VERSION 5.8 ;
BUSBITCHARS "[]" ;
DIVIDERCHAR "/" ;
UNITS
    DATABASE MICRONS 1000 ;
END UNITS

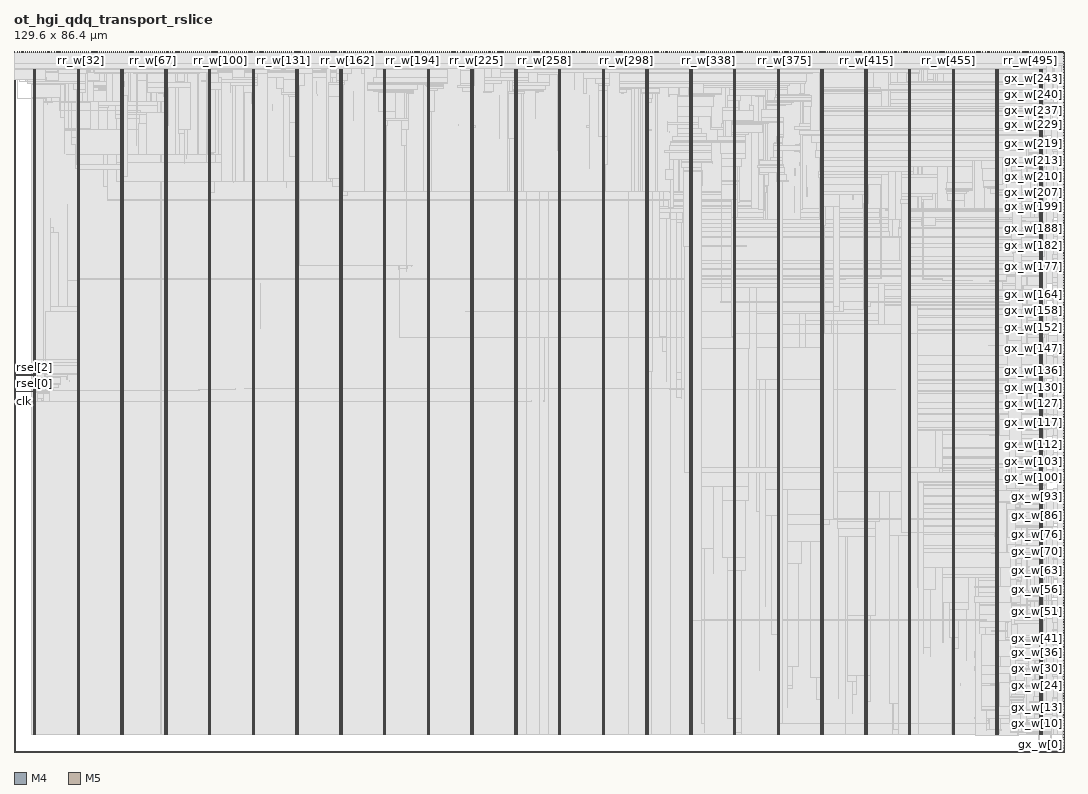
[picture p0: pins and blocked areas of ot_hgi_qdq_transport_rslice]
MACRO ot_hgi_qdq_transport_rslice
  FOREIGN ot_hgi_qdq_transport_rslice 0 0 ;
  CLASS BLOCK ;
  SIZE 129.6 BY 86.4 ;
  PIN clk
    DIRECTION INPUT ;
    USE SIGNAL ;
    PORT
      LAYER M4 ;
        RECT  0 43.2 0.084 43.224 ;
    END
    PORT
      LAYER M4 ;
        RECT  0.06 43.2 0.097 43.224 ;
    END
  END clk
  PIN gx_w[0]
    DIRECTION OUTPUT ;
    USE SIGNAL ;
    PORT
      LAYER M4 ;
        RECT  129.516 0.144 129.6 0.168 ;
    END
  END gx_w[0]
  PIN gx_w[100]
    DIRECTION OUTPUT ;
    USE SIGNAL ;
    PORT
      LAYER M4 ;
        RECT  129.516 33.888 129.6 33.912 ;
    END
  END gx_w[100]
  PIN gx_w[101]
    DIRECTION OUTPUT ;
    USE SIGNAL ;
    PORT
      LAYER M4 ;
        RECT  129.516 34.224 129.6 34.248 ;
    END
  END gx_w[101]
  PIN gx_w[102]
    DIRECTION OUTPUT ;
    USE SIGNAL ;
    PORT
      LAYER M4 ;
        RECT  129.516 34.56 129.6 34.584 ;
    END
  END gx_w[102]
  PIN gx_w[103]
    DIRECTION OUTPUT ;
    USE SIGNAL ;
    PORT
      LAYER M4 ;
        RECT  129.516 34.896 129.6 34.92 ;
    END
  END gx_w[103]
  PIN gx_w[104]
    DIRECTION OUTPUT ;
    USE SIGNAL ;
    PORT
      LAYER M4 ;
        RECT  129.516 35.28 129.6 35.304 ;
    END
  END gx_w[104]
  PIN gx_w[105]
    DIRECTION OUTPUT ;
    USE SIGNAL ;
    PORT
      LAYER M4 ;
        RECT  129.516 35.616 129.6 35.64 ;
    END
  END gx_w[105]
  PIN gx_w[106]
    DIRECTION OUTPUT ;
    USE SIGNAL ;
    PORT
      LAYER M4 ;
        RECT  129.516 35.952 129.6 35.976 ;
    END
  END gx_w[106]
  PIN gx_w[107]
    DIRECTION OUTPUT ;
    USE SIGNAL ;
    PORT
      LAYER M4 ;
        RECT  129.516 36.288 129.6 36.312 ;
    END
  END gx_w[107]
  PIN gx_w[108]
    DIRECTION OUTPUT ;
    USE SIGNAL ;
    PORT
      LAYER M4 ;
        RECT  129.516 36.624 129.6 36.648 ;
    END
  END gx_w[108]
  PIN gx_w[109]
    DIRECTION OUTPUT ;
    USE SIGNAL ;
    PORT
      LAYER M4 ;
        RECT  129.516 36.96 129.6 36.984 ;
    END
  END gx_w[109]
  PIN gx_w[10]
    DIRECTION OUTPUT ;
    USE SIGNAL ;
    PORT
      LAYER M4 ;
        RECT  129.516 3.552 129.6 3.576 ;
    END
  END gx_w[10]
  PIN gx_w[110]
    DIRECTION OUTPUT ;
    USE SIGNAL ;
    PORT
      LAYER M4 ;
        RECT  129.516 37.296 129.6 37.32 ;
    END
  END gx_w[110]
  PIN gx_w[111]
    DIRECTION OUTPUT ;
    USE SIGNAL ;
    PORT
      LAYER M4 ;
        RECT  129.516 37.632 129.6 37.656 ;
    END
  END gx_w[111]
  PIN gx_w[112]
    DIRECTION OUTPUT ;
    USE SIGNAL ;
    PORT
      LAYER M4 ;
        RECT  129.516 37.968 129.6 37.992 ;
    END
  END gx_w[112]
  PIN gx_w[113]
    DIRECTION OUTPUT ;
    USE SIGNAL ;
    PORT
      LAYER M4 ;
        RECT  129.516 38.304 129.6 38.328 ;
    END
  END gx_w[113]
  PIN gx_w[114]
    DIRECTION OUTPUT ;
    USE SIGNAL ;
    PORT
      LAYER M4 ;
        RECT  129.516 38.64 129.6 38.664 ;
    END
  END gx_w[114]
  PIN gx_w[115]
    DIRECTION OUTPUT ;
    USE SIGNAL ;
    PORT
      LAYER M4 ;
        RECT  129.516 38.976 129.6 39 ;
    END
  END gx_w[115]
  PIN gx_w[116]
    DIRECTION OUTPUT ;
    USE SIGNAL ;
    PORT
      LAYER M4 ;
        RECT  129.516 39.312 129.6 39.336 ;
    END
  END gx_w[116]
  PIN gx_w[117]
    DIRECTION OUTPUT ;
    USE SIGNAL ;
    PORT
      LAYER M4 ;
        RECT  129.516 39.648 129.6 39.672 ;
    END
  END gx_w[117]
  PIN gx_w[118]
    DIRECTION OUTPUT ;
    USE SIGNAL ;
    PORT
      LAYER M4 ;
        RECT  129.516 39.984 129.6 40.008 ;
    END
  END gx_w[118]
  PIN gx_w[119]
    DIRECTION OUTPUT ;
    USE SIGNAL ;
    PORT
      LAYER M4 ;
        RECT  129.516 40.32 129.6 40.344 ;
    END
  END gx_w[119]
  PIN gx_w[11]
    DIRECTION OUTPUT ;
    USE SIGNAL ;
    PORT
      LAYER M4 ;
        RECT  129.516 3.888 129.6 3.912 ;
    END
  END gx_w[11]
  PIN gx_w[120]
    DIRECTION OUTPUT ;
    USE SIGNAL ;
    PORT
      LAYER M4 ;
        RECT  129.516 40.656 129.6 40.68 ;
    END
  END gx_w[120]
  PIN gx_w[121]
    DIRECTION OUTPUT ;
    USE SIGNAL ;
    PORT
      LAYER M4 ;
        RECT  129.516 40.992 129.6 41.016 ;
    END
  END gx_w[121]
  PIN gx_w[122]
    DIRECTION OUTPUT ;
    USE SIGNAL ;
    PORT
      LAYER M4 ;
        RECT  129.516 41.328 129.6 41.352 ;
    END
  END gx_w[122]
  PIN gx_w[123]
    DIRECTION OUTPUT ;
    USE SIGNAL ;
    PORT
      LAYER M4 ;
        RECT  129.516 41.664 129.6 41.688 ;
    END
  END gx_w[123]
  PIN gx_w[124]
    DIRECTION OUTPUT ;
    USE SIGNAL ;
    PORT
      LAYER M4 ;
        RECT  129.516 42 129.6 42.024 ;
    END
  END gx_w[124]
  PIN gx_w[125]
    DIRECTION OUTPUT ;
    USE SIGNAL ;
    PORT
      LAYER M4 ;
        RECT  129.516 42.336 129.6 42.36 ;
    END
  END gx_w[125]
  PIN gx_w[126]
    DIRECTION OUTPUT ;
    USE SIGNAL ;
    PORT
      LAYER M4 ;
        RECT  129.516 42.672 129.6 42.696 ;
    END
  END gx_w[126]
  PIN gx_w[127]
    DIRECTION OUTPUT ;
    USE SIGNAL ;
    PORT
      LAYER M4 ;
        RECT  129.516 43.008 129.6 43.032 ;
    END
  END gx_w[127]
  PIN gx_w[128]
    DIRECTION OUTPUT ;
    USE SIGNAL ;
    PORT
      LAYER M4 ;
        RECT  129.516 43.344 129.6 43.368 ;
    END
  END gx_w[128]
  PIN gx_w[129]
    DIRECTION OUTPUT ;
    USE SIGNAL ;
    PORT
      LAYER M4 ;
        RECT  129.516 43.68 129.6 43.704 ;
    END
  END gx_w[129]
  PIN gx_w[12]
    DIRECTION OUTPUT ;
    USE SIGNAL ;
    PORT
      LAYER M4 ;
        RECT  129.516 4.224 129.6 4.248 ;
    END
  END gx_w[12]
  PIN gx_w[130]
    DIRECTION OUTPUT ;
    USE SIGNAL ;
    PORT
      LAYER M4 ;
        RECT  129.516 44.016 129.6 44.04 ;
    END
  END gx_w[130]
  PIN gx_w[131]
    DIRECTION OUTPUT ;
    USE SIGNAL ;
    PORT
      LAYER M4 ;
        RECT  129.516 44.352 129.6 44.376 ;
    END
  END gx_w[131]
  PIN gx_w[132]
    DIRECTION OUTPUT ;
    USE SIGNAL ;
    PORT
      LAYER M4 ;
        RECT  129.516 44.688 129.6 44.712 ;
    END
  END gx_w[132]
  PIN gx_w[133]
    DIRECTION OUTPUT ;
    USE SIGNAL ;
    PORT
      LAYER M4 ;
        RECT  129.516 45.024 129.6 45.048 ;
    END
  END gx_w[133]
  PIN gx_w[134]
    DIRECTION OUTPUT ;
    USE SIGNAL ;
    PORT
      LAYER M4 ;
        RECT  129.516 45.36 129.6 45.384 ;
    END
  END gx_w[134]
  PIN gx_w[135]
    DIRECTION OUTPUT ;
    USE SIGNAL ;
    PORT
      LAYER M4 ;
        RECT  129.516 45.696 129.6 45.72 ;
    END
  END gx_w[135]
  PIN gx_w[136]
    DIRECTION OUTPUT ;
    USE SIGNAL ;
    PORT
      LAYER M4 ;
        RECT  129.516 46.08 129.6 46.104 ;
    END
  END gx_w[136]
  PIN gx_w[137]
    DIRECTION OUTPUT ;
    USE SIGNAL ;
    PORT
      LAYER M4 ;
        RECT  129.516 46.416 129.6 46.44 ;
    END
  END gx_w[137]
  PIN gx_w[138]
    DIRECTION OUTPUT ;
    USE SIGNAL ;
    PORT
      LAYER M4 ;
        RECT  129.516 46.752 129.6 46.776 ;
    END
  END gx_w[138]
  PIN gx_w[139]
    DIRECTION OUTPUT ;
    USE SIGNAL ;
    PORT
      LAYER M4 ;
        RECT  129.516 47.088 129.6 47.112 ;
    END
  END gx_w[139]
  PIN gx_w[13]
    DIRECTION OUTPUT ;
    USE SIGNAL ;
    PORT
      LAYER M4 ;
        RECT  129.516 4.56 129.6 4.584 ;
    END
  END gx_w[13]
  PIN gx_w[140]
    DIRECTION OUTPUT ;
    USE SIGNAL ;
    PORT
      LAYER M4 ;
        RECT  129.516 47.424 129.6 47.448 ;
    END
  END gx_w[140]
  PIN gx_w[141]
    DIRECTION OUTPUT ;
    USE SIGNAL ;
    PORT
      LAYER M4 ;
        RECT  129.516 47.76 129.6 47.784 ;
    END
  END gx_w[141]
  PIN gx_w[142]
    DIRECTION OUTPUT ;
    USE SIGNAL ;
    PORT
      LAYER M4 ;
        RECT  129.516 48.096 129.6 48.12 ;
    END
  END gx_w[142]
  PIN gx_w[143]
    DIRECTION OUTPUT ;
    USE SIGNAL ;
    PORT
      LAYER M4 ;
        RECT  129.516 48.432 129.6 48.456 ;
    END
  END gx_w[143]
  PIN gx_w[144]
    DIRECTION OUTPUT ;
    USE SIGNAL ;
    PORT
      LAYER M4 ;
        RECT  129.516 48.768 129.6 48.792 ;
    END
  END gx_w[144]
  PIN gx_w[145]
    DIRECTION OUTPUT ;
    USE SIGNAL ;
    PORT
      LAYER M4 ;
        RECT  129.516 49.104 129.6 49.128 ;
    END
  END gx_w[145]
  PIN gx_w[146]
    DIRECTION OUTPUT ;
    USE SIGNAL ;
    PORT
      LAYER M4 ;
        RECT  129.516 49.44 129.6 49.464 ;
    END
  END gx_w[146]
  PIN gx_w[147]
    DIRECTION OUTPUT ;
    USE SIGNAL ;
    PORT
      LAYER M4 ;
        RECT  129.516 49.776 129.6 49.8 ;
    END
  END gx_w[147]
  PIN gx_w[148]
    DIRECTION OUTPUT ;
    USE SIGNAL ;
    PORT
      LAYER M4 ;
        RECT  129.516 50.112 129.6 50.136 ;
    END
  END gx_w[148]
  PIN gx_w[149]
    DIRECTION OUTPUT ;
    USE SIGNAL ;
    PORT
      LAYER M4 ;
        RECT  129.516 50.448 129.6 50.472 ;
    END
  END gx_w[149]
  PIN gx_w[14]
    DIRECTION OUTPUT ;
    USE SIGNAL ;
    PORT
      LAYER M4 ;
        RECT  129.516 4.896 129.6 4.92 ;
    END
  END gx_w[14]
  PIN gx_w[150]
    DIRECTION OUTPUT ;
    USE SIGNAL ;
    PORT
      LAYER M4 ;
        RECT  129.516 50.784 129.6 50.808 ;
    END
  END gx_w[150]
  PIN gx_w[151]
    DIRECTION OUTPUT ;
    USE SIGNAL ;
    PORT
      LAYER M4 ;
        RECT  129.516 51.12 129.6 51.144 ;
    END
  END gx_w[151]
  PIN gx_w[152]
    DIRECTION OUTPUT ;
    USE SIGNAL ;
    PORT
      LAYER M4 ;
        RECT  129.516 51.456 129.6 51.48 ;
    END
  END gx_w[152]
  PIN gx_w[153]
    DIRECTION OUTPUT ;
    USE SIGNAL ;
    PORT
      LAYER M4 ;
        RECT  129.516 51.792 129.6 51.816 ;
    END
  END gx_w[153]
  PIN gx_w[154]
    DIRECTION OUTPUT ;
    USE SIGNAL ;
    PORT
      LAYER M4 ;
        RECT  129.516 52.128 129.6 52.152 ;
    END
  END gx_w[154]
  PIN gx_w[155]
    DIRECTION OUTPUT ;
    USE SIGNAL ;
    PORT
      LAYER M4 ;
        RECT  129.516 52.464 129.6 52.488 ;
    END
  END gx_w[155]
  PIN gx_w[156]
    DIRECTION OUTPUT ;
    USE SIGNAL ;
    PORT
      LAYER M4 ;
        RECT  129.516 52.8 129.6 52.824 ;
    END
  END gx_w[156]
  PIN gx_w[157]
    DIRECTION OUTPUT ;
    USE SIGNAL ;
    PORT
      LAYER M4 ;
        RECT  129.516 53.136 129.6 53.16 ;
    END
  END gx_w[157]
  PIN gx_w[158]
    DIRECTION OUTPUT ;
    USE SIGNAL ;
    PORT
      LAYER M4 ;
        RECT  129.516 53.472 129.6 53.496 ;
    END
  END gx_w[158]
  PIN gx_w[159]
    DIRECTION OUTPUT ;
    USE SIGNAL ;
    PORT
      LAYER M4 ;
        RECT  129.516 53.808 129.6 53.832 ;
    END
  END gx_w[159]
  PIN gx_w[15]
    DIRECTION OUTPUT ;
    USE SIGNAL ;
    PORT
      LAYER M4 ;
        RECT  129.516 5.232 129.6 5.256 ;
    END
  END gx_w[15]
  PIN gx_w[160]
    DIRECTION OUTPUT ;
    USE SIGNAL ;
    PORT
      LAYER M4 ;
        RECT  129.516 54.144 129.6 54.168 ;
    END
  END gx_w[160]
  PIN gx_w[161]
    DIRECTION OUTPUT ;
    USE SIGNAL ;
    PORT
      LAYER M4 ;
        RECT  129.516 54.48 129.6 54.504 ;
    END
  END gx_w[161]
  PIN gx_w[162]
    DIRECTION OUTPUT ;
    USE SIGNAL ;
    PORT
      LAYER M4 ;
        RECT  129.516 54.816 129.6 54.84 ;
    END
  END gx_w[162]
  PIN gx_w[163]
    DIRECTION OUTPUT ;
    USE SIGNAL ;
    PORT
      LAYER M4 ;
        RECT  129.516 55.152 129.6 55.176 ;
    END
  END gx_w[163]
  PIN gx_w[164]
    DIRECTION OUTPUT ;
    USE SIGNAL ;
    PORT
      LAYER M4 ;
        RECT  129.516 55.488 129.6 55.512 ;
    END
  END gx_w[164]
  PIN gx_w[165]
    DIRECTION OUTPUT ;
    USE SIGNAL ;
    PORT
      LAYER M4 ;
        RECT  129.516 55.824 129.6 55.848 ;
    END
  END gx_w[165]
  PIN gx_w[166]
    DIRECTION OUTPUT ;
    USE SIGNAL ;
    PORT
      LAYER M4 ;
        RECT  129.516 56.16 129.6 56.184 ;
    END
  END gx_w[166]
  PIN gx_w[167]
    DIRECTION OUTPUT ;
    USE SIGNAL ;
    PORT
      LAYER M4 ;
        RECT  129.516 56.496 129.6 56.52 ;
    END
  END gx_w[167]
  PIN gx_w[168]
    DIRECTION OUTPUT ;
    USE SIGNAL ;
    PORT
      LAYER M4 ;
        RECT  129.516 56.88 129.6 56.904 ;
    END
  END gx_w[168]
  PIN gx_w[169]
    DIRECTION OUTPUT ;
    USE SIGNAL ;
    PORT
      LAYER M4 ;
        RECT  129.516 57.216 129.6 57.24 ;
    END
  END gx_w[169]
  PIN gx_w[16]
    DIRECTION OUTPUT ;
    USE SIGNAL ;
    PORT
      LAYER M4 ;
        RECT  129.516 5.568 129.6 5.592 ;
    END
  END gx_w[16]
  PIN gx_w[170]
    DIRECTION OUTPUT ;
    USE SIGNAL ;
    PORT
      LAYER M4 ;
        RECT  129.516 57.552 129.6 57.576 ;
    END
  END gx_w[170]
  PIN gx_w[171]
    DIRECTION OUTPUT ;
    USE SIGNAL ;
    PORT
      LAYER M4 ;
        RECT  129.516 57.888 129.6 57.912 ;
    END
  END gx_w[171]
  PIN gx_w[172]
    DIRECTION OUTPUT ;
    USE SIGNAL ;
    PORT
      LAYER M4 ;
        RECT  129.516 58.224 129.6 58.248 ;
    END
  END gx_w[172]
  PIN gx_w[173]
    DIRECTION OUTPUT ;
    USE SIGNAL ;
    PORT
      LAYER M4 ;
        RECT  129.516 58.56 129.6 58.584 ;
    END
  END gx_w[173]
  PIN gx_w[174]
    DIRECTION OUTPUT ;
    USE SIGNAL ;
    PORT
      LAYER M4 ;
        RECT  129.516 58.896 129.6 58.92 ;
    END
  END gx_w[174]
  PIN gx_w[175]
    DIRECTION OUTPUT ;
    USE SIGNAL ;
    PORT
      LAYER M4 ;
        RECT  129.516 59.232 129.6 59.256 ;
    END
  END gx_w[175]
  PIN gx_w[176]
    DIRECTION OUTPUT ;
    USE SIGNAL ;
    PORT
      LAYER M4 ;
        RECT  129.516 59.568 129.6 59.592 ;
    END
  END gx_w[176]
  PIN gx_w[177]
    DIRECTION OUTPUT ;
    USE SIGNAL ;
    PORT
      LAYER M4 ;
        RECT  129.516 59.904 129.6 59.928 ;
    END
  END gx_w[177]
  PIN gx_w[178]
    DIRECTION OUTPUT ;
    USE SIGNAL ;
    PORT
      LAYER M4 ;
        RECT  129.516 60.24 129.6 60.264 ;
    END
  END gx_w[178]
  PIN gx_w[179]
    DIRECTION OUTPUT ;
    USE SIGNAL ;
    PORT
      LAYER M4 ;
        RECT  129.516 60.576 129.6 60.6 ;
    END
  END gx_w[179]
  PIN gx_w[17]
    DIRECTION OUTPUT ;
    USE SIGNAL ;
    PORT
      LAYER M4 ;
        RECT  129.516 5.904 129.6 5.928 ;
    END
  END gx_w[17]
  PIN gx_w[180]
    DIRECTION OUTPUT ;
    USE SIGNAL ;
    PORT
      LAYER M4 ;
        RECT  129.516 60.912 129.6 60.936 ;
    END
  END gx_w[180]
  PIN gx_w[181]
    DIRECTION OUTPUT ;
    USE SIGNAL ;
    PORT
      LAYER M4 ;
        RECT  129.516 61.248 129.6 61.272 ;
    END
  END gx_w[181]
  PIN gx_w[182]
    DIRECTION OUTPUT ;
    USE SIGNAL ;
    PORT
      LAYER M4 ;
        RECT  129.516 61.584 129.6 61.608 ;
    END
  END gx_w[182]
  PIN gx_w[183]
    DIRECTION OUTPUT ;
    USE SIGNAL ;
    PORT
      LAYER M4 ;
        RECT  129.516 61.92 129.6 61.944 ;
    END
  END gx_w[183]
  PIN gx_w[184]
    DIRECTION OUTPUT ;
    USE SIGNAL ;
    PORT
      LAYER M4 ;
        RECT  129.516 62.256 129.6 62.28 ;
    END
  END gx_w[184]
  PIN gx_w[185]
    DIRECTION OUTPUT ;
    USE SIGNAL ;
    PORT
      LAYER M4 ;
        RECT  129.516 62.592 129.6 62.616 ;
    END
  END gx_w[185]
  PIN gx_w[186]
    DIRECTION OUTPUT ;
    USE SIGNAL ;
    PORT
      LAYER M4 ;
        RECT  129.516 62.928 129.6 62.952 ;
    END
  END gx_w[186]
  PIN gx_w[187]
    DIRECTION OUTPUT ;
    USE SIGNAL ;
    PORT
      LAYER M4 ;
        RECT  129.516 63.264 129.6 63.288 ;
    END
  END gx_w[187]
  PIN gx_w[188]
    DIRECTION OUTPUT ;
    USE SIGNAL ;
    PORT
      LAYER M4 ;
        RECT  129.516 63.6 129.6 63.624 ;
    END
  END gx_w[188]
  PIN gx_w[189]
    DIRECTION OUTPUT ;
    USE SIGNAL ;
    PORT
      LAYER M4 ;
        RECT  129.516 63.936 129.6 63.96 ;
    END
  END gx_w[189]
  PIN gx_w[18]
    DIRECTION OUTPUT ;
    USE SIGNAL ;
    PORT
      LAYER M4 ;
        RECT  129.516 6.24 129.6 6.264 ;
    END
  END gx_w[18]
  PIN gx_w[190]
    DIRECTION OUTPUT ;
    USE SIGNAL ;
    PORT
      LAYER M4 ;
        RECT  129.516 64.272 129.6 64.296 ;
    END
  END gx_w[190]
  PIN gx_w[191]
    DIRECTION OUTPUT ;
    USE SIGNAL ;
    PORT
      LAYER M4 ;
        RECT  129.516 64.608 129.6 64.632 ;
    END
  END gx_w[191]
  PIN gx_w[192]
    DIRECTION OUTPUT ;
    USE SIGNAL ;
    PORT
      LAYER M4 ;
        RECT  129.516 64.944 129.6 64.968 ;
    END
  END gx_w[192]
  PIN gx_w[193]
    DIRECTION OUTPUT ;
    USE SIGNAL ;
    PORT
      LAYER M4 ;
        RECT  129.516 65.28 129.6 65.304 ;
    END
  END gx_w[193]
  PIN gx_w[194]
    DIRECTION OUTPUT ;
    USE SIGNAL ;
    PORT
      LAYER M4 ;
        RECT  129.516 65.616 129.6 65.64 ;
    END
  END gx_w[194]
  PIN gx_w[195]
    DIRECTION OUTPUT ;
    USE SIGNAL ;
    PORT
      LAYER M4 ;
        RECT  129.516 65.952 129.6 65.976 ;
    END
  END gx_w[195]
  PIN gx_w[196]
    DIRECTION OUTPUT ;
    USE SIGNAL ;
    PORT
      LAYER M4 ;
        RECT  129.516 66.288 129.6 66.312 ;
    END
  END gx_w[196]
  PIN gx_w[197]
    DIRECTION OUTPUT ;
    USE SIGNAL ;
    PORT
      LAYER M4 ;
        RECT  129.516 66.624 129.6 66.648 ;
    END
  END gx_w[197]
  PIN gx_w[198]
    DIRECTION OUTPUT ;
    USE SIGNAL ;
    PORT
      LAYER M4 ;
        RECT  129.516 66.96 129.6 66.984 ;
    END
  END gx_w[198]
  PIN gx_w[199]
    DIRECTION OUTPUT ;
    USE SIGNAL ;
    PORT
      LAYER M4 ;
        RECT  129.516 67.296 129.6 67.32 ;
    END
  END gx_w[199]
  PIN gx_w[19]
    DIRECTION OUTPUT ;
    USE SIGNAL ;
    PORT
      LAYER M4 ;
        RECT  129.516 6.576 129.6 6.6 ;
    END
  END gx_w[19]
  PIN gx_w[1]
    DIRECTION OUTPUT ;
    USE SIGNAL ;
    PORT
      LAYER M4 ;
        RECT  129.516 0.48 129.6 0.504 ;
    END
  END gx_w[1]
  PIN gx_w[200]
    DIRECTION OUTPUT ;
    USE SIGNAL ;
    PORT
      LAYER M4 ;
        RECT  129.516 67.68 129.6 67.704 ;
    END
  END gx_w[200]
  PIN gx_w[201]
    DIRECTION OUTPUT ;
    USE SIGNAL ;
    PORT
      LAYER M4 ;
        RECT  129.516 68.016 129.6 68.04 ;
    END
  END gx_w[201]
  PIN gx_w[202]
    DIRECTION OUTPUT ;
    USE SIGNAL ;
    PORT
      LAYER M4 ;
        RECT  129.516 68.352 129.6 68.376 ;
    END
  END gx_w[202]
  PIN gx_w[203]
    DIRECTION OUTPUT ;
    USE SIGNAL ;
    PORT
      LAYER M4 ;
        RECT  129.516 68.688 129.6 68.712 ;
    END
  END gx_w[203]
  PIN gx_w[204]
    DIRECTION OUTPUT ;
    USE SIGNAL ;
    PORT
      LAYER M4 ;
        RECT  129.516 69.024 129.6 69.048 ;
    END
  END gx_w[204]
  PIN gx_w[205]
    DIRECTION OUTPUT ;
    USE SIGNAL ;
    PORT
      LAYER M4 ;
        RECT  129.516 69.36 129.6 69.384 ;
    END
  END gx_w[205]
  PIN gx_w[206]
    DIRECTION OUTPUT ;
    USE SIGNAL ;
    PORT
      LAYER M4 ;
        RECT  129.516 69.696 129.6 69.72 ;
    END
  END gx_w[206]
  PIN gx_w[207]
    DIRECTION OUTPUT ;
    USE SIGNAL ;
    PORT
      LAYER M4 ;
        RECT  129.516 70.032 129.6 70.056 ;
    END
  END gx_w[207]
  PIN gx_w[208]
    DIRECTION OUTPUT ;
    USE SIGNAL ;
    PORT
      LAYER M4 ;
        RECT  129.516 70.368 129.6 70.392 ;
    END
  END gx_w[208]
  PIN gx_w[209]
    DIRECTION OUTPUT ;
    USE SIGNAL ;
    PORT
      LAYER M4 ;
        RECT  129.516 70.704 129.6 70.728 ;
    END
  END gx_w[209]
  PIN gx_w[20]
    DIRECTION OUTPUT ;
    USE SIGNAL ;
    PORT
      LAYER M4 ;
        RECT  129.516 6.912 129.6 6.936 ;
    END
  END gx_w[20]
  PIN gx_w[210]
    DIRECTION OUTPUT ;
    USE SIGNAL ;
    PORT
      LAYER M4 ;
        RECT  129.516 71.04 129.6 71.064 ;
    END
  END gx_w[210]
  PIN gx_w[211]
    DIRECTION OUTPUT ;
    USE SIGNAL ;
    PORT
      LAYER M4 ;
        RECT  129.516 71.376 129.6 71.4 ;
    END
  END gx_w[211]
  PIN gx_w[212]
    DIRECTION OUTPUT ;
    USE SIGNAL ;
    PORT
      LAYER M4 ;
        RECT  129.516 71.712 129.6 71.736 ;
    END
  END gx_w[212]
  PIN gx_w[213]
    DIRECTION OUTPUT ;
    USE SIGNAL ;
    PORT
      LAYER M4 ;
        RECT  129.516 72.048 129.6 72.072 ;
    END
  END gx_w[213]
  PIN gx_w[214]
    DIRECTION OUTPUT ;
    USE SIGNAL ;
    PORT
      LAYER M4 ;
        RECT  129.516 72.384 129.6 72.408 ;
    END
  END gx_w[214]
  PIN gx_w[215]
    DIRECTION OUTPUT ;
    USE SIGNAL ;
    PORT
      LAYER M4 ;
        RECT  129.516 72.72 129.6 72.744 ;
    END
  END gx_w[215]
  PIN gx_w[216]
    DIRECTION OUTPUT ;
    USE SIGNAL ;
    PORT
      LAYER M4 ;
        RECT  129.516 73.056 129.6 73.08 ;
    END
  END gx_w[216]
  PIN gx_w[217]
    DIRECTION OUTPUT ;
    USE SIGNAL ;
    PORT
      LAYER M4 ;
        RECT  129.516 73.392 129.6 73.416 ;
    END
  END gx_w[217]
  PIN gx_w[218]
    DIRECTION OUTPUT ;
    USE SIGNAL ;
    PORT
      LAYER M4 ;
        RECT  129.516 73.728 129.6 73.752 ;
    END
  END gx_w[218]
  PIN gx_w[219]
    DIRECTION OUTPUT ;
    USE SIGNAL ;
    PORT
      LAYER M4 ;
        RECT  129.516 74.064 129.6 74.088 ;
    END
  END gx_w[219]
  PIN gx_w[21]
    DIRECTION OUTPUT ;
    USE SIGNAL ;
    PORT
      LAYER M4 ;
        RECT  129.516 7.248 129.6 7.272 ;
    END
  END gx_w[21]
  PIN gx_w[220]
    DIRECTION OUTPUT ;
    USE SIGNAL ;
    PORT
      LAYER M4 ;
        RECT  129.516 74.4 129.6 74.424 ;
    END
  END gx_w[220]
  PIN gx_w[221]
    DIRECTION OUTPUT ;
    USE SIGNAL ;
    PORT
      LAYER M4 ;
        RECT  129.516 74.736 129.6 74.76 ;
    END
  END gx_w[221]
  PIN gx_w[222]
    DIRECTION OUTPUT ;
    USE SIGNAL ;
    PORT
      LAYER M4 ;
        RECT  129.516 75.072 129.6 75.096 ;
    END
  END gx_w[222]
  PIN gx_w[223]
    DIRECTION OUTPUT ;
    USE SIGNAL ;
    PORT
      LAYER M4 ;
        RECT  129.516 75.408 129.6 75.432 ;
    END
  END gx_w[223]
  PIN gx_w[224]
    DIRECTION OUTPUT ;
    USE SIGNAL ;
    PORT
      LAYER M4 ;
        RECT  129.516 75.744 129.6 75.768 ;
    END
  END gx_w[224]
  PIN gx_w[225]
    DIRECTION OUTPUT ;
    USE SIGNAL ;
    PORT
      LAYER M4 ;
        RECT  129.516 76.08 129.6 76.104 ;
    END
  END gx_w[225]
  PIN gx_w[226]
    DIRECTION OUTPUT ;
    USE SIGNAL ;
    PORT
      LAYER M4 ;
        RECT  129.516 76.416 129.6 76.44 ;
    END
  END gx_w[226]
  PIN gx_w[227]
    DIRECTION OUTPUT ;
    USE SIGNAL ;
    PORT
      LAYER M4 ;
        RECT  129.516 76.752 129.6 76.776 ;
    END
  END gx_w[227]
  PIN gx_w[228]
    DIRECTION OUTPUT ;
    USE SIGNAL ;
    PORT
      LAYER M4 ;
        RECT  129.516 77.088 129.6 77.112 ;
    END
  END gx_w[228]
  PIN gx_w[229]
    DIRECTION OUTPUT ;
    USE SIGNAL ;
    PORT
      LAYER M4 ;
        RECT  129.516 77.424 129.6 77.448 ;
    END
  END gx_w[229]
  PIN gx_w[22]
    DIRECTION OUTPUT ;
    USE SIGNAL ;
    PORT
      LAYER M4 ;
        RECT  129.516 7.584 129.6 7.608 ;
    END
  END gx_w[22]
  PIN gx_w[230]
    DIRECTION OUTPUT ;
    USE SIGNAL ;
    PORT
      LAYER M4 ;
        RECT  129.516 77.76 129.6 77.784 ;
    END
  END gx_w[230]
  PIN gx_w[231]
    DIRECTION OUTPUT ;
    USE SIGNAL ;
    PORT
      LAYER M4 ;
        RECT  129.516 78.096 129.6 78.12 ;
    END
  END gx_w[231]
  PIN gx_w[232]
    DIRECTION OUTPUT ;
    USE SIGNAL ;
    PORT
      LAYER M4 ;
        RECT  129.516 78.48 129.6 78.504 ;
    END
  END gx_w[232]
  PIN gx_w[233]
    DIRECTION OUTPUT ;
    USE SIGNAL ;
    PORT
      LAYER M4 ;
        RECT  129.516 78.816 129.6 78.84 ;
    END
  END gx_w[233]
  PIN gx_w[234]
    DIRECTION OUTPUT ;
    USE SIGNAL ;
    PORT
      LAYER M4 ;
        RECT  129.516 79.152 129.6 79.176 ;
    END
  END gx_w[234]
  PIN gx_w[235]
    DIRECTION OUTPUT ;
    USE SIGNAL ;
    PORT
      LAYER M4 ;
        RECT  129.516 79.488 129.6 79.512 ;
    END
  END gx_w[235]
  PIN gx_w[236]
    DIRECTION OUTPUT ;
    USE SIGNAL ;
    PORT
      LAYER M4 ;
        RECT  129.516 79.824 129.6 79.848 ;
    END
  END gx_w[236]
  PIN gx_w[237]
    DIRECTION OUTPUT ;
    USE SIGNAL ;
    PORT
      LAYER M4 ;
        RECT  129.516 80.16 129.6 80.184 ;
    END
  END gx_w[237]
  PIN gx_w[238]
    DIRECTION OUTPUT ;
    USE SIGNAL ;
    PORT
      LAYER M4 ;
        RECT  129.516 80.496 129.6 80.52 ;
    END
  END gx_w[238]
  PIN gx_w[239]
    DIRECTION OUTPUT ;
    USE SIGNAL ;
    PORT
      LAYER M4 ;
        RECT  129.516 80.832 129.6 80.856 ;
    END
  END gx_w[239]
  PIN gx_w[23]
    DIRECTION OUTPUT ;
    USE SIGNAL ;
    PORT
      LAYER M4 ;
        RECT  129.516 7.92 129.6 7.944 ;
    END
  END gx_w[23]
  PIN gx_w[240]
    DIRECTION OUTPUT ;
    USE SIGNAL ;
    PORT
      LAYER M4 ;
        RECT  129.516 81.168 129.6 81.192 ;
    END
  END gx_w[240]
  PIN gx_w[241]
    DIRECTION OUTPUT ;
    USE SIGNAL ;
    PORT
      LAYER M4 ;
        RECT  129.516 81.504 129.6 81.528 ;
    END
  END gx_w[241]
  PIN gx_w[242]
    DIRECTION OUTPUT ;
    USE SIGNAL ;
    PORT
      LAYER M4 ;
        RECT  129.516 81.84 129.6 81.864 ;
    END
  END gx_w[242]
  PIN gx_w[243]
    DIRECTION OUTPUT ;
    USE SIGNAL ;
    PORT
      LAYER M4 ;
        RECT  129.516 82.176 129.6 82.2 ;
    END
  END gx_w[243]
  PIN gx_w[244]
    DIRECTION OUTPUT ;
    USE SIGNAL ;
    PORT
      LAYER M4 ;
        RECT  129.516 82.512 129.6 82.536 ;
    END
  END gx_w[244]
  PIN gx_w[245]
    DIRECTION OUTPUT ;
    USE SIGNAL ;
    PORT
      LAYER M4 ;
        RECT  129.516 82.848 129.6 82.872 ;
    END
  END gx_w[245]
  PIN gx_w[246]
    DIRECTION OUTPUT ;
    USE SIGNAL ;
    PORT
      LAYER M4 ;
        RECT  129.516 83.184 129.6 83.208 ;
    END
  END gx_w[246]
  PIN gx_w[247]
    DIRECTION OUTPUT ;
    USE SIGNAL ;
    PORT
      LAYER M4 ;
        RECT  129.516 83.52 129.6 83.544 ;
    END
  END gx_w[247]
  PIN gx_w[248]
    DIRECTION OUTPUT ;
    USE SIGNAL ;
    PORT
      LAYER M4 ;
        RECT  129.516 83.856 129.6 83.88 ;
    END
  END gx_w[248]
  PIN gx_w[249]
    DIRECTION OUTPUT ;
    USE SIGNAL ;
    PORT
      LAYER M4 ;
        RECT  129.516 84.192 129.6 84.216 ;
    END
  END gx_w[249]
  PIN gx_w[24]
    DIRECTION OUTPUT ;
    USE SIGNAL ;
    PORT
      LAYER M4 ;
        RECT  129.516 8.256 129.6 8.28 ;
    END
  END gx_w[24]
  PIN gx_w[250]
    DIRECTION OUTPUT ;
    USE SIGNAL ;
    PORT
      LAYER M4 ;
        RECT  129.516 84.528 129.6 84.552 ;
    END
  END gx_w[250]
  PIN gx_w[251]
    DIRECTION OUTPUT ;
    USE SIGNAL ;
    PORT
      LAYER M4 ;
        RECT  129.516 84.864 129.6 84.888 ;
    END
  END gx_w[251]
  PIN gx_w[252]
    DIRECTION OUTPUT ;
    USE SIGNAL ;
    PORT
      LAYER M4 ;
        RECT  129.516 85.2 129.6 85.224 ;
    END
  END gx_w[252]
  PIN gx_w[253]
    DIRECTION OUTPUT ;
    USE SIGNAL ;
    PORT
      LAYER M4 ;
        RECT  129.516 85.536 129.6 85.56 ;
    END
  END gx_w[253]
  PIN gx_w[254]
    DIRECTION OUTPUT ;
    USE SIGNAL ;
    PORT
      LAYER M4 ;
        RECT  129.516 85.872 129.6 85.896 ;
    END
  END gx_w[254]
  PIN gx_w[255]
    DIRECTION OUTPUT ;
    USE SIGNAL ;
    PORT
      LAYER M4 ;
        RECT  129.516 86.208 129.6 86.232 ;
    END
  END gx_w[255]
  PIN gx_w[25]
    DIRECTION OUTPUT ;
    USE SIGNAL ;
    PORT
      LAYER M4 ;
        RECT  129.516 8.592 129.6 8.616 ;
    END
  END gx_w[25]
  PIN gx_w[26]
    DIRECTION OUTPUT ;
    USE SIGNAL ;
    PORT
      LAYER M4 ;
        RECT  129.516 8.928 129.6 8.952 ;
    END
  END gx_w[26]
  PIN gx_w[27]
    DIRECTION OUTPUT ;
    USE SIGNAL ;
    PORT
      LAYER M4 ;
        RECT  129.516 9.264 129.6 9.288 ;
    END
  END gx_w[27]
  PIN gx_w[28]
    DIRECTION OUTPUT ;
    USE SIGNAL ;
    PORT
      LAYER M4 ;
        RECT  129.516 9.6 129.6 9.624 ;
    END
  END gx_w[28]
  PIN gx_w[29]
    DIRECTION OUTPUT ;
    USE SIGNAL ;
    PORT
      LAYER M4 ;
        RECT  129.516 9.936 129.6 9.96 ;
    END
  END gx_w[29]
  PIN gx_w[2]
    DIRECTION OUTPUT ;
    USE SIGNAL ;
    PORT
      LAYER M4 ;
        RECT  129.516 0.816 129.6 0.84 ;
    END
  END gx_w[2]
  PIN gx_w[30]
    DIRECTION OUTPUT ;
    USE SIGNAL ;
    PORT
      LAYER M4 ;
        RECT  129.516 10.272 129.6 10.296 ;
    END
  END gx_w[30]
  PIN gx_w[31]
    DIRECTION OUTPUT ;
    USE SIGNAL ;
    PORT
      LAYER M4 ;
        RECT  129.516 10.608 129.6 10.632 ;
    END
  END gx_w[31]
  PIN gx_w[32]
    DIRECTION OUTPUT ;
    USE SIGNAL ;
    PORT
      LAYER M4 ;
        RECT  129.516 10.944 129.6 10.968 ;
    END
  END gx_w[32]
  PIN gx_w[33]
    DIRECTION OUTPUT ;
    USE SIGNAL ;
    PORT
      LAYER M4 ;
        RECT  129.516 11.28 129.6 11.304 ;
    END
  END gx_w[33]
  PIN gx_w[34]
    DIRECTION OUTPUT ;
    USE SIGNAL ;
    PORT
      LAYER M4 ;
        RECT  129.516 11.616 129.6 11.64 ;
    END
  END gx_w[34]
  PIN gx_w[35]
    DIRECTION OUTPUT ;
    USE SIGNAL ;
    PORT
      LAYER M4 ;
        RECT  129.516 11.952 129.6 11.976 ;
    END
  END gx_w[35]
  PIN gx_w[36]
    DIRECTION OUTPUT ;
    USE SIGNAL ;
    PORT
      LAYER M4 ;
        RECT  129.516 12.288 129.6 12.312 ;
    END
  END gx_w[36]
  PIN gx_w[37]
    DIRECTION OUTPUT ;
    USE SIGNAL ;
    PORT
      LAYER M4 ;
        RECT  129.516 12.624 129.6 12.648 ;
    END
  END gx_w[37]
  PIN gx_w[38]
    DIRECTION OUTPUT ;
    USE SIGNAL ;
    PORT
      LAYER M4 ;
        RECT  129.516 12.96 129.6 12.984 ;
    END
  END gx_w[38]
  PIN gx_w[39]
    DIRECTION OUTPUT ;
    USE SIGNAL ;
    PORT
      LAYER M4 ;
        RECT  129.516 13.296 129.6 13.32 ;
    END
  END gx_w[39]
  PIN gx_w[3]
    DIRECTION OUTPUT ;
    USE SIGNAL ;
    PORT
      LAYER M4 ;
        RECT  129.516 1.152 129.6 1.176 ;
    END
  END gx_w[3]
  PIN gx_w[40]
    DIRECTION OUTPUT ;
    USE SIGNAL ;
    PORT
      LAYER M4 ;
        RECT  129.516 13.68 129.6 13.704 ;
    END
  END gx_w[40]
  PIN gx_w[41]
    DIRECTION OUTPUT ;
    USE SIGNAL ;
    PORT
      LAYER M4 ;
        RECT  129.516 14.016 129.6 14.04 ;
    END
  END gx_w[41]
  PIN gx_w[42]
    DIRECTION OUTPUT ;
    USE SIGNAL ;
    PORT
      LAYER M4 ;
        RECT  129.516 14.352 129.6 14.376 ;
    END
  END gx_w[42]
  PIN gx_w[43]
    DIRECTION OUTPUT ;
    USE SIGNAL ;
    PORT
      LAYER M4 ;
        RECT  129.516 14.688 129.6 14.712 ;
    END
  END gx_w[43]
  PIN gx_w[44]
    DIRECTION OUTPUT ;
    USE SIGNAL ;
    PORT
      LAYER M4 ;
        RECT  129.516 15.024 129.6 15.048 ;
    END
  END gx_w[44]
  PIN gx_w[45]
    DIRECTION OUTPUT ;
    USE SIGNAL ;
    PORT
      LAYER M4 ;
        RECT  129.516 15.36 129.6 15.384 ;
    END
  END gx_w[45]
  PIN gx_w[46]
    DIRECTION OUTPUT ;
    USE SIGNAL ;
    PORT
      LAYER M4 ;
        RECT  129.516 15.696 129.6 15.72 ;
    END
  END gx_w[46]
  PIN gx_w[47]
    DIRECTION OUTPUT ;
    USE SIGNAL ;
    PORT
      LAYER M4 ;
        RECT  129.516 16.032 129.6 16.056 ;
    END
  END gx_w[47]
  PIN gx_w[48]
    DIRECTION OUTPUT ;
    USE SIGNAL ;
    PORT
      LAYER M4 ;
        RECT  129.516 16.368 129.6 16.392 ;
    END
  END gx_w[48]
  PIN gx_w[49]
    DIRECTION OUTPUT ;
    USE SIGNAL ;
    PORT
      LAYER M4 ;
        RECT  129.516 16.704 129.6 16.728 ;
    END
  END gx_w[49]
  PIN gx_w[4]
    DIRECTION OUTPUT ;
    USE SIGNAL ;
    PORT
      LAYER M4 ;
        RECT  129.516 1.488 129.6 1.512 ;
    END
  END gx_w[4]
  PIN gx_w[50]
    DIRECTION OUTPUT ;
    USE SIGNAL ;
    PORT
      LAYER M4 ;
        RECT  129.516 17.04 129.6 17.064 ;
    END
  END gx_w[50]
  PIN gx_w[51]
    DIRECTION OUTPUT ;
    USE SIGNAL ;
    PORT
      LAYER M4 ;
        RECT  129.516 17.376 129.6 17.4 ;
    END
  END gx_w[51]
  PIN gx_w[52]
    DIRECTION OUTPUT ;
    USE SIGNAL ;
    PORT
      LAYER M4 ;
        RECT  129.516 17.712 129.6 17.736 ;
    END
  END gx_w[52]
  PIN gx_w[53]
    DIRECTION OUTPUT ;
    USE SIGNAL ;
    PORT
      LAYER M4 ;
        RECT  129.516 18.048 129.6 18.072 ;
    END
  END gx_w[53]
  PIN gx_w[54]
    DIRECTION OUTPUT ;
    USE SIGNAL ;
    PORT
      LAYER M4 ;
        RECT  129.516 18.384 129.6 18.408 ;
    END
  END gx_w[54]
  PIN gx_w[55]
    DIRECTION OUTPUT ;
    USE SIGNAL ;
    PORT
      LAYER M4 ;
        RECT  129.516 18.72 129.6 18.744 ;
    END
  END gx_w[55]
  PIN gx_w[56]
    DIRECTION OUTPUT ;
    USE SIGNAL ;
    PORT
      LAYER M4 ;
        RECT  129.516 19.056 129.6 19.08 ;
    END
  END gx_w[56]
  PIN gx_w[57]
    DIRECTION OUTPUT ;
    USE SIGNAL ;
    PORT
      LAYER M4 ;
        RECT  129.516 19.392 129.6 19.416 ;
    END
  END gx_w[57]
  PIN gx_w[58]
    DIRECTION OUTPUT ;
    USE SIGNAL ;
    PORT
      LAYER M4 ;
        RECT  129.516 19.728 129.6 19.752 ;
    END
  END gx_w[58]
  PIN gx_w[59]
    DIRECTION OUTPUT ;
    USE SIGNAL ;
    PORT
      LAYER M4 ;
        RECT  129.516 20.064 129.6 20.088 ;
    END
  END gx_w[59]
  PIN gx_w[5]
    DIRECTION OUTPUT ;
    USE SIGNAL ;
    PORT
      LAYER M4 ;
        RECT  129.516 1.824 129.6 1.848 ;
    END
  END gx_w[5]
  PIN gx_w[60]
    DIRECTION OUTPUT ;
    USE SIGNAL ;
    PORT
      LAYER M4 ;
        RECT  129.516 20.4 129.6 20.424 ;
    END
  END gx_w[60]
  PIN gx_w[61]
    DIRECTION OUTPUT ;
    USE SIGNAL ;
    PORT
      LAYER M4 ;
        RECT  129.516 20.736 129.6 20.76 ;
    END
  END gx_w[61]
  PIN gx_w[62]
    DIRECTION OUTPUT ;
    USE SIGNAL ;
    PORT
      LAYER M4 ;
        RECT  129.516 21.072 129.6 21.096 ;
    END
  END gx_w[62]
  PIN gx_w[63]
    DIRECTION OUTPUT ;
    USE SIGNAL ;
    PORT
      LAYER M4 ;
        RECT  129.516 21.408 129.6 21.432 ;
    END
  END gx_w[63]
  PIN gx_w[64]
    DIRECTION OUTPUT ;
    USE SIGNAL ;
    PORT
      LAYER M4 ;
        RECT  129.516 21.744 129.6 21.768 ;
    END
  END gx_w[64]
  PIN gx_w[65]
    DIRECTION OUTPUT ;
    USE SIGNAL ;
    PORT
      LAYER M4 ;
        RECT  129.516 22.08 129.6 22.104 ;
    END
  END gx_w[65]
  PIN gx_w[66]
    DIRECTION OUTPUT ;
    USE SIGNAL ;
    PORT
      LAYER M4 ;
        RECT  129.516 22.416 129.6 22.44 ;
    END
  END gx_w[66]
  PIN gx_w[67]
    DIRECTION OUTPUT ;
    USE SIGNAL ;
    PORT
      LAYER M4 ;
        RECT  129.516 22.752 129.6 22.776 ;
    END
  END gx_w[67]
  PIN gx_w[68]
    DIRECTION OUTPUT ;
    USE SIGNAL ;
    PORT
      LAYER M4 ;
        RECT  129.516 23.088 129.6 23.112 ;
    END
  END gx_w[68]
  PIN gx_w[69]
    DIRECTION OUTPUT ;
    USE SIGNAL ;
    PORT
      LAYER M4 ;
        RECT  129.516 23.424 129.6 23.448 ;
    END
  END gx_w[69]
  PIN gx_w[6]
    DIRECTION OUTPUT ;
    USE SIGNAL ;
    PORT
      LAYER M4 ;
        RECT  129.516 2.16 129.6 2.184 ;
    END
  END gx_w[6]
  PIN gx_w[70]
    DIRECTION OUTPUT ;
    USE SIGNAL ;
    PORT
      LAYER M4 ;
        RECT  129.516 23.76 129.6 23.784 ;
    END
  END gx_w[70]
  PIN gx_w[71]
    DIRECTION OUTPUT ;
    USE SIGNAL ;
    PORT
      LAYER M4 ;
        RECT  129.516 24.096 129.6 24.12 ;
    END
  END gx_w[71]
  PIN gx_w[72]
    DIRECTION OUTPUT ;
    USE SIGNAL ;
    PORT
      LAYER M4 ;
        RECT  129.516 24.48 129.6 24.504 ;
    END
  END gx_w[72]
  PIN gx_w[73]
    DIRECTION OUTPUT ;
    USE SIGNAL ;
    PORT
      LAYER M4 ;
        RECT  129.516 24.816 129.6 24.84 ;
    END
  END gx_w[73]
  PIN gx_w[74]
    DIRECTION OUTPUT ;
    USE SIGNAL ;
    PORT
      LAYER M4 ;
        RECT  129.516 25.152 129.6 25.176 ;
    END
  END gx_w[74]
  PIN gx_w[75]
    DIRECTION OUTPUT ;
    USE SIGNAL ;
    PORT
      LAYER M4 ;
        RECT  129.516 25.488 129.6 25.512 ;
    END
  END gx_w[75]
  PIN gx_w[76]
    DIRECTION OUTPUT ;
    USE SIGNAL ;
    PORT
      LAYER M4 ;
        RECT  129.516 25.824 129.6 25.848 ;
    END
  END gx_w[76]
  PIN gx_w[77]
    DIRECTION OUTPUT ;
    USE SIGNAL ;
    PORT
      LAYER M4 ;
        RECT  129.516 26.16 129.6 26.184 ;
    END
  END gx_w[77]
  PIN gx_w[78]
    DIRECTION OUTPUT ;
    USE SIGNAL ;
    PORT
      LAYER M4 ;
        RECT  129.516 26.496 129.6 26.52 ;
    END
  END gx_w[78]
  PIN gx_w[79]
    DIRECTION OUTPUT ;
    USE SIGNAL ;
    PORT
      LAYER M4 ;
        RECT  129.516 26.832 129.6 26.856 ;
    END
  END gx_w[79]
  PIN gx_w[7]
    DIRECTION OUTPUT ;
    USE SIGNAL ;
    PORT
      LAYER M4 ;
        RECT  129.516 2.496 129.6 2.52 ;
    END
  END gx_w[7]
  PIN gx_w[80]
    DIRECTION OUTPUT ;
    USE SIGNAL ;
    PORT
      LAYER M4 ;
        RECT  129.516 27.168 129.6 27.192 ;
    END
  END gx_w[80]
  PIN gx_w[81]
    DIRECTION OUTPUT ;
    USE SIGNAL ;
    PORT
      LAYER M4 ;
        RECT  129.516 27.504 129.6 27.528 ;
    END
  END gx_w[81]
  PIN gx_w[82]
    DIRECTION OUTPUT ;
    USE SIGNAL ;
    PORT
      LAYER M4 ;
        RECT  129.516 27.84 129.6 27.864 ;
    END
  END gx_w[82]
  PIN gx_w[83]
    DIRECTION OUTPUT ;
    USE SIGNAL ;
    PORT
      LAYER M4 ;
        RECT  129.516 28.176 129.6 28.2 ;
    END
  END gx_w[83]
  PIN gx_w[84]
    DIRECTION OUTPUT ;
    USE SIGNAL ;
    PORT
      LAYER M4 ;
        RECT  129.516 28.512 129.6 28.536 ;
    END
  END gx_w[84]
  PIN gx_w[85]
    DIRECTION OUTPUT ;
    USE SIGNAL ;
    PORT
      LAYER M4 ;
        RECT  129.516 28.848 129.6 28.872 ;
    END
  END gx_w[85]
  PIN gx_w[86]
    DIRECTION OUTPUT ;
    USE SIGNAL ;
    PORT
      LAYER M4 ;
        RECT  129.516 29.184 129.6 29.208 ;
    END
  END gx_w[86]
  PIN gx_w[87]
    DIRECTION OUTPUT ;
    USE SIGNAL ;
    PORT
      LAYER M4 ;
        RECT  129.516 29.52 129.6 29.544 ;
    END
  END gx_w[87]
  PIN gx_w[88]
    DIRECTION OUTPUT ;
    USE SIGNAL ;
    PORT
      LAYER M4 ;
        RECT  129.516 29.856 129.6 29.88 ;
    END
  END gx_w[88]
  PIN gx_w[89]
    DIRECTION OUTPUT ;
    USE SIGNAL ;
    PORT
      LAYER M4 ;
        RECT  129.516 30.192 129.6 30.216 ;
    END
  END gx_w[89]
  PIN gx_w[8]
    DIRECTION OUTPUT ;
    USE SIGNAL ;
    PORT
      LAYER M4 ;
        RECT  129.516 2.88 129.6 2.904 ;
    END
  END gx_w[8]
  PIN gx_w[90]
    DIRECTION OUTPUT ;
    USE SIGNAL ;
    PORT
      LAYER M4 ;
        RECT  129.516 30.528 129.6 30.552 ;
    END
  END gx_w[90]
  PIN gx_w[91]
    DIRECTION OUTPUT ;
    USE SIGNAL ;
    PORT
      LAYER M4 ;
        RECT  129.516 30.864 129.6 30.888 ;
    END
  END gx_w[91]
  PIN gx_w[92]
    DIRECTION OUTPUT ;
    USE SIGNAL ;
    PORT
      LAYER M4 ;
        RECT  129.516 31.2 129.6 31.224 ;
    END
  END gx_w[92]
  PIN gx_w[93]
    DIRECTION OUTPUT ;
    USE SIGNAL ;
    PORT
      LAYER M4 ;
        RECT  129.516 31.536 129.6 31.56 ;
    END
  END gx_w[93]
  PIN gx_w[94]
    DIRECTION OUTPUT ;
    USE SIGNAL ;
    PORT
      LAYER M4 ;
        RECT  129.516 31.872 129.6 31.896 ;
    END
  END gx_w[94]
  PIN gx_w[95]
    DIRECTION OUTPUT ;
    USE SIGNAL ;
    PORT
      LAYER M4 ;
        RECT  129.516 32.208 129.6 32.232 ;
    END
  END gx_w[95]
  PIN gx_w[96]
    DIRECTION OUTPUT ;
    USE SIGNAL ;
    PORT
      LAYER M4 ;
        RECT  129.516 32.544 129.6 32.568 ;
    END
  END gx_w[96]
  PIN gx_w[97]
    DIRECTION OUTPUT ;
    USE SIGNAL ;
    PORT
      LAYER M4 ;
        RECT  129.516 32.88 129.6 32.904 ;
    END
  END gx_w[97]
  PIN gx_w[98]
    DIRECTION OUTPUT ;
    USE SIGNAL ;
    PORT
      LAYER M4 ;
        RECT  129.516 33.216 129.6 33.24 ;
    END
  END gx_w[98]
  PIN gx_w[99]
    DIRECTION OUTPUT ;
    USE SIGNAL ;
    PORT
      LAYER M4 ;
        RECT  129.516 33.552 129.6 33.576 ;
    END
  END gx_w[99]
  PIN gx_w[9]
    DIRECTION OUTPUT ;
    USE SIGNAL ;
    PORT
      LAYER M4 ;
        RECT  129.516 3.216 129.6 3.24 ;
    END
  END gx_w[9]
  PIN rr_w[0]
    DIRECTION INPUT ;
    USE SIGNAL ;
    PORT
      LAYER M5 ;
        RECT  0.096 86.316 0.12 86.4 ;
    END
  END rr_w[0]
  PIN rr_w[100]
    DIRECTION INPUT ;
    USE SIGNAL ;
    PORT
      LAYER M5 ;
        RECT  25.44 86.316 25.464 86.4 ;
    END
  END rr_w[100]
  PIN rr_w[101]
    DIRECTION INPUT ;
    USE SIGNAL ;
    PORT
      LAYER M5 ;
        RECT  25.68 86.316 25.704 86.4 ;
    END
  END rr_w[101]
  PIN rr_w[102]
    DIRECTION INPUT ;
    USE SIGNAL ;
    PORT
      LAYER M5 ;
        RECT  25.92 86.316 25.944 86.4 ;
    END
  END rr_w[102]
  PIN rr_w[103]
    DIRECTION INPUT ;
    USE SIGNAL ;
    PORT
      LAYER M5 ;
        RECT  26.208 86.316 26.232 86.4 ;
    END
  END rr_w[103]
  PIN rr_w[104]
    DIRECTION INPUT ;
    USE SIGNAL ;
    PORT
      LAYER M5 ;
        RECT  26.448 86.316 26.472 86.4 ;
    END
  END rr_w[104]
  PIN rr_w[105]
    DIRECTION INPUT ;
    USE SIGNAL ;
    PORT
      LAYER M5 ;
        RECT  26.688 86.316 26.712 86.4 ;
    END
  END rr_w[105]
  PIN rr_w[106]
    DIRECTION INPUT ;
    USE SIGNAL ;
    PORT
      LAYER M5 ;
        RECT  26.928 86.316 26.952 86.4 ;
    END
  END rr_w[106]
  PIN rr_w[107]
    DIRECTION INPUT ;
    USE SIGNAL ;
    PORT
      LAYER M5 ;
        RECT  27.216 86.316 27.24 86.4 ;
    END
  END rr_w[107]
  PIN rr_w[108]
    DIRECTION INPUT ;
    USE SIGNAL ;
    PORT
      LAYER M5 ;
        RECT  27.456 86.316 27.48 86.4 ;
    END
  END rr_w[108]
  PIN rr_w[109]
    DIRECTION INPUT ;
    USE SIGNAL ;
    PORT
      LAYER M5 ;
        RECT  27.696 86.316 27.72 86.4 ;
    END
  END rr_w[109]
  PIN rr_w[10]
    DIRECTION INPUT ;
    USE SIGNAL ;
    PORT
      LAYER M5 ;
        RECT  2.64 86.316 2.664 86.4 ;
    END
  END rr_w[10]
  PIN rr_w[110]
    DIRECTION INPUT ;
    USE SIGNAL ;
    PORT
      LAYER M5 ;
        RECT  27.936 86.316 27.96 86.4 ;
    END
  END rr_w[110]
  PIN rr_w[111]
    DIRECTION INPUT ;
    USE SIGNAL ;
    PORT
      LAYER M5 ;
        RECT  28.224 86.316 28.248 86.4 ;
    END
  END rr_w[111]
  PIN rr_w[112]
    DIRECTION INPUT ;
    USE SIGNAL ;
    PORT
      LAYER M5 ;
        RECT  28.464 86.316 28.488 86.4 ;
    END
  END rr_w[112]
  PIN rr_w[113]
    DIRECTION INPUT ;
    USE SIGNAL ;
    PORT
      LAYER M5 ;
        RECT  28.704 86.316 28.728 86.4 ;
    END
  END rr_w[113]
  PIN rr_w[114]
    DIRECTION INPUT ;
    USE SIGNAL ;
    PORT
      LAYER M5 ;
        RECT  28.992 86.316 29.016 86.4 ;
    END
  END rr_w[114]
  PIN rr_w[115]
    DIRECTION INPUT ;
    USE SIGNAL ;
    PORT
      LAYER M5 ;
        RECT  29.232 86.316 29.256 86.4 ;
    END
  END rr_w[115]
  PIN rr_w[116]
    DIRECTION INPUT ;
    USE SIGNAL ;
    PORT
      LAYER M5 ;
        RECT  29.472 86.316 29.496 86.4 ;
    END
  END rr_w[116]
  PIN rr_w[117]
    DIRECTION INPUT ;
    USE SIGNAL ;
    PORT
      LAYER M5 ;
        RECT  29.712 86.316 29.736 86.4 ;
    END
  END rr_w[117]
  PIN rr_w[118]
    DIRECTION INPUT ;
    USE SIGNAL ;
    PORT
      LAYER M5 ;
        RECT  30 86.316 30.024 86.4 ;
    END
  END rr_w[118]
  PIN rr_w[119]
    DIRECTION INPUT ;
    USE SIGNAL ;
    PORT
      LAYER M5 ;
        RECT  30.24 86.316 30.264 86.4 ;
    END
  END rr_w[119]
  PIN rr_w[11]
    DIRECTION INPUT ;
    USE SIGNAL ;
    PORT
      LAYER M5 ;
        RECT  2.88 86.316 2.904 86.4 ;
    END
  END rr_w[11]
  PIN rr_w[120]
    DIRECTION INPUT ;
    USE SIGNAL ;
    PORT
      LAYER M5 ;
        RECT  30.48 86.316 30.504 86.4 ;
    END
  END rr_w[120]
  PIN rr_w[121]
    DIRECTION INPUT ;
    USE SIGNAL ;
    PORT
      LAYER M5 ;
        RECT  30.72 86.316 30.744 86.4 ;
    END
  END rr_w[121]
  PIN rr_w[122]
    DIRECTION INPUT ;
    USE SIGNAL ;
    PORT
      LAYER M5 ;
        RECT  31.008 86.316 31.032 86.4 ;
    END
  END rr_w[122]
  PIN rr_w[123]
    DIRECTION INPUT ;
    USE SIGNAL ;
    PORT
      LAYER M5 ;
        RECT  31.248 86.316 31.272 86.4 ;
    END
  END rr_w[123]
  PIN rr_w[124]
    DIRECTION INPUT ;
    USE SIGNAL ;
    PORT
      LAYER M5 ;
        RECT  31.488 86.316 31.512 86.4 ;
    END
  END rr_w[124]
  PIN rr_w[125]
    DIRECTION INPUT ;
    USE SIGNAL ;
    PORT
      LAYER M5 ;
        RECT  31.776 86.316 31.8 86.4 ;
    END
  END rr_w[125]
  PIN rr_w[126]
    DIRECTION INPUT ;
    USE SIGNAL ;
    PORT
      LAYER M5 ;
        RECT  32.016 86.316 32.04 86.4 ;
    END
  END rr_w[126]
  PIN rr_w[127]
    DIRECTION INPUT ;
    USE SIGNAL ;
    PORT
      LAYER M5 ;
        RECT  32.256 86.316 32.28 86.4 ;
    END
  END rr_w[127]
  PIN rr_w[128]
    DIRECTION INPUT ;
    USE SIGNAL ;
    PORT
      LAYER M5 ;
        RECT  32.496 86.316 32.52 86.4 ;
    END
  END rr_w[128]
  PIN rr_w[129]
    DIRECTION INPUT ;
    USE SIGNAL ;
    PORT
      LAYER M5 ;
        RECT  32.784 86.316 32.808 86.4 ;
    END
  END rr_w[129]
  PIN rr_w[12]
    DIRECTION INPUT ;
    USE SIGNAL ;
    PORT
      LAYER M5 ;
        RECT  3.168 86.316 3.192 86.4 ;
    END
  END rr_w[12]
  PIN rr_w[130]
    DIRECTION INPUT ;
    USE SIGNAL ;
    PORT
      LAYER M5 ;
        RECT  33.024 86.316 33.048 86.4 ;
    END
  END rr_w[130]
  PIN rr_w[131]
    DIRECTION INPUT ;
    USE SIGNAL ;
    PORT
      LAYER M5 ;
        RECT  33.264 86.316 33.288 86.4 ;
    END
  END rr_w[131]
  PIN rr_w[132]
    DIRECTION INPUT ;
    USE SIGNAL ;
    PORT
      LAYER M5 ;
        RECT  33.504 86.316 33.528 86.4 ;
    END
  END rr_w[132]
  PIN rr_w[133]
    DIRECTION INPUT ;
    USE SIGNAL ;
    PORT
      LAYER M5 ;
        RECT  33.792 86.316 33.816 86.4 ;
    END
  END rr_w[133]
  PIN rr_w[134]
    DIRECTION INPUT ;
    USE SIGNAL ;
    PORT
      LAYER M5 ;
        RECT  34.032 86.316 34.056 86.4 ;
    END
  END rr_w[134]
  PIN rr_w[135]
    DIRECTION INPUT ;
    USE SIGNAL ;
    PORT
      LAYER M5 ;
        RECT  34.272 86.316 34.296 86.4 ;
    END
  END rr_w[135]
  PIN rr_w[136]
    DIRECTION INPUT ;
    USE SIGNAL ;
    PORT
      LAYER M5 ;
        RECT  34.56 86.316 34.584 86.4 ;
    END
  END rr_w[136]
  PIN rr_w[137]
    DIRECTION INPUT ;
    USE SIGNAL ;
    PORT
      LAYER M5 ;
        RECT  34.8 86.316 34.824 86.4 ;
    END
  END rr_w[137]
  PIN rr_w[138]
    DIRECTION INPUT ;
    USE SIGNAL ;
    PORT
      LAYER M5 ;
        RECT  35.04 86.316 35.064 86.4 ;
    END
  END rr_w[138]
  PIN rr_w[139]
    DIRECTION INPUT ;
    USE SIGNAL ;
    PORT
      LAYER M5 ;
        RECT  35.28 86.316 35.304 86.4 ;
    END
  END rr_w[139]
  PIN rr_w[13]
    DIRECTION INPUT ;
    USE SIGNAL ;
    PORT
      LAYER M5 ;
        RECT  3.408 86.316 3.432 86.4 ;
    END
  END rr_w[13]
  PIN rr_w[140]
    DIRECTION INPUT ;
    USE SIGNAL ;
    PORT
      LAYER M5 ;
        RECT  35.568 86.316 35.592 86.4 ;
    END
  END rr_w[140]
  PIN rr_w[141]
    DIRECTION INPUT ;
    USE SIGNAL ;
    PORT
      LAYER M5 ;
        RECT  35.808 86.316 35.832 86.4 ;
    END
  END rr_w[141]
  PIN rr_w[142]
    DIRECTION INPUT ;
    USE SIGNAL ;
    PORT
      LAYER M5 ;
        RECT  36.048 86.316 36.072 86.4 ;
    END
  END rr_w[142]
  PIN rr_w[143]
    DIRECTION INPUT ;
    USE SIGNAL ;
    PORT
      LAYER M5 ;
        RECT  36.288 86.316 36.312 86.4 ;
    END
  END rr_w[143]
  PIN rr_w[144]
    DIRECTION INPUT ;
    USE SIGNAL ;
    PORT
      LAYER M5 ;
        RECT  36.576 86.316 36.6 86.4 ;
    END
  END rr_w[144]
  PIN rr_w[145]
    DIRECTION INPUT ;
    USE SIGNAL ;
    PORT
      LAYER M5 ;
        RECT  36.816 86.316 36.84 86.4 ;
    END
  END rr_w[145]
  PIN rr_w[146]
    DIRECTION INPUT ;
    USE SIGNAL ;
    PORT
      LAYER M5 ;
        RECT  37.056 86.316 37.08 86.4 ;
    END
  END rr_w[146]
  PIN rr_w[147]
    DIRECTION INPUT ;
    USE SIGNAL ;
    PORT
      LAYER M5 ;
        RECT  37.344 86.316 37.368 86.4 ;
    END
  END rr_w[147]
  PIN rr_w[148]
    DIRECTION INPUT ;
    USE SIGNAL ;
    PORT
      LAYER M5 ;
        RECT  37.584 86.316 37.608 86.4 ;
    END
  END rr_w[148]
  PIN rr_w[149]
    DIRECTION INPUT ;
    USE SIGNAL ;
    PORT
      LAYER M5 ;
        RECT  37.824 86.316 37.848 86.4 ;
    END
  END rr_w[149]
  PIN rr_w[14]
    DIRECTION INPUT ;
    USE SIGNAL ;
    PORT
      LAYER M5 ;
        RECT  3.648 86.316 3.672 86.4 ;
    END
  END rr_w[14]
  PIN rr_w[150]
    DIRECTION INPUT ;
    USE SIGNAL ;
    PORT
      LAYER M5 ;
        RECT  38.064 86.316 38.088 86.4 ;
    END
  END rr_w[150]
  PIN rr_w[151]
    DIRECTION INPUT ;
    USE SIGNAL ;
    PORT
      LAYER M5 ;
        RECT  38.352 86.316 38.376 86.4 ;
    END
  END rr_w[151]
  PIN rr_w[152]
    DIRECTION INPUT ;
    USE SIGNAL ;
    PORT
      LAYER M5 ;
        RECT  38.592 86.316 38.616 86.4 ;
    END
  END rr_w[152]
  PIN rr_w[153]
    DIRECTION INPUT ;
    USE SIGNAL ;
    PORT
      LAYER M5 ;
        RECT  38.832 86.316 38.856 86.4 ;
    END
  END rr_w[153]
  PIN rr_w[154]
    DIRECTION INPUT ;
    USE SIGNAL ;
    PORT
      LAYER M5 ;
        RECT  39.12 86.316 39.144 86.4 ;
    END
  END rr_w[154]
  PIN rr_w[155]
    DIRECTION INPUT ;
    USE SIGNAL ;
    PORT
      LAYER M5 ;
        RECT  39.36 86.316 39.384 86.4 ;
    END
  END rr_w[155]
  PIN rr_w[156]
    DIRECTION INPUT ;
    USE SIGNAL ;
    PORT
      LAYER M5 ;
        RECT  39.6 86.316 39.624 86.4 ;
    END
  END rr_w[156]
  PIN rr_w[157]
    DIRECTION INPUT ;
    USE SIGNAL ;
    PORT
      LAYER M5 ;
        RECT  39.84 86.316 39.864 86.4 ;
    END
  END rr_w[157]
  PIN rr_w[158]
    DIRECTION INPUT ;
    USE SIGNAL ;
    PORT
      LAYER M5 ;
        RECT  40.128 86.316 40.152 86.4 ;
    END
  END rr_w[158]
  PIN rr_w[159]
    DIRECTION INPUT ;
    USE SIGNAL ;
    PORT
      LAYER M5 ;
        RECT  40.368 86.316 40.392 86.4 ;
    END
  END rr_w[159]
  PIN rr_w[15]
    DIRECTION INPUT ;
    USE SIGNAL ;
    PORT
      LAYER M5 ;
        RECT  3.888 86.316 3.912 86.4 ;
    END
  END rr_w[15]
  PIN rr_w[160]
    DIRECTION INPUT ;
    USE SIGNAL ;
    PORT
      LAYER M5 ;
        RECT  40.608 86.316 40.632 86.4 ;
    END
  END rr_w[160]
  PIN rr_w[161]
    DIRECTION INPUT ;
    USE SIGNAL ;
    PORT
      LAYER M5 ;
        RECT  40.848 86.316 40.872 86.4 ;
    END
  END rr_w[161]
  PIN rr_w[162]
    DIRECTION INPUT ;
    USE SIGNAL ;
    PORT
      LAYER M5 ;
        RECT  41.136 86.316 41.16 86.4 ;
    END
  END rr_w[162]
  PIN rr_w[163]
    DIRECTION INPUT ;
    USE SIGNAL ;
    PORT
      LAYER M5 ;
        RECT  41.376 86.316 41.4 86.4 ;
    END
  END rr_w[163]
  PIN rr_w[164]
    DIRECTION INPUT ;
    USE SIGNAL ;
    PORT
      LAYER M5 ;
        RECT  41.616 86.316 41.64 86.4 ;
    END
  END rr_w[164]
  PIN rr_w[165]
    DIRECTION INPUT ;
    USE SIGNAL ;
    PORT
      LAYER M5 ;
        RECT  41.904 86.316 41.928 86.4 ;
    END
  END rr_w[165]
  PIN rr_w[166]
    DIRECTION INPUT ;
    USE SIGNAL ;
    PORT
      LAYER M5 ;
        RECT  42.144 86.316 42.168 86.4 ;
    END
  END rr_w[166]
  PIN rr_w[167]
    DIRECTION INPUT ;
    USE SIGNAL ;
    PORT
      LAYER M5 ;
        RECT  42.384 86.316 42.408 86.4 ;
    END
  END rr_w[167]
  PIN rr_w[168]
    DIRECTION INPUT ;
    USE SIGNAL ;
    PORT
      LAYER M5 ;
        RECT  42.624 86.316 42.648 86.4 ;
    END
  END rr_w[168]
  PIN rr_w[169]
    DIRECTION INPUT ;
    USE SIGNAL ;
    PORT
      LAYER M5 ;
        RECT  42.912 86.316 42.936 86.4 ;
    END
  END rr_w[169]
  PIN rr_w[16]
    DIRECTION INPUT ;
    USE SIGNAL ;
    PORT
      LAYER M5 ;
        RECT  4.176 86.316 4.2 86.4 ;
    END
  END rr_w[16]
  PIN rr_w[170]
    DIRECTION INPUT ;
    USE SIGNAL ;
    PORT
      LAYER M5 ;
        RECT  43.152 86.316 43.176 86.4 ;
    END
  END rr_w[170]
  PIN rr_w[171]
    DIRECTION INPUT ;
    USE SIGNAL ;
    PORT
      LAYER M5 ;
        RECT  43.392 86.316 43.416 86.4 ;
    END
  END rr_w[171]
  PIN rr_w[172]
    DIRECTION INPUT ;
    USE SIGNAL ;
    PORT
      LAYER M5 ;
        RECT  43.632 86.316 43.656 86.4 ;
    END
  END rr_w[172]
  PIN rr_w[173]
    DIRECTION INPUT ;
    USE SIGNAL ;
    PORT
      LAYER M5 ;
        RECT  43.92 86.316 43.944 86.4 ;
    END
  END rr_w[173]
  PIN rr_w[174]
    DIRECTION INPUT ;
    USE SIGNAL ;
    PORT
      LAYER M5 ;
        RECT  44.16 86.316 44.184 86.4 ;
    END
  END rr_w[174]
  PIN rr_w[175]
    DIRECTION INPUT ;
    USE SIGNAL ;
    PORT
      LAYER M5 ;
        RECT  44.4 86.316 44.424 86.4 ;
    END
  END rr_w[175]
  PIN rr_w[176]
    DIRECTION INPUT ;
    USE SIGNAL ;
    PORT
      LAYER M5 ;
        RECT  44.688 86.316 44.712 86.4 ;
    END
  END rr_w[176]
  PIN rr_w[177]
    DIRECTION INPUT ;
    USE SIGNAL ;
    PORT
      LAYER M5 ;
        RECT  44.928 86.316 44.952 86.4 ;
    END
  END rr_w[177]
  PIN rr_w[178]
    DIRECTION INPUT ;
    USE SIGNAL ;
    PORT
      LAYER M5 ;
        RECT  45.168 86.316 45.192 86.4 ;
    END
  END rr_w[178]
  PIN rr_w[179]
    DIRECTION INPUT ;
    USE SIGNAL ;
    PORT
      LAYER M5 ;
        RECT  45.408 86.316 45.432 86.4 ;
    END
  END rr_w[179]
  PIN rr_w[17]
    DIRECTION INPUT ;
    USE SIGNAL ;
    PORT
      LAYER M5 ;
        RECT  4.416 86.316 4.44 86.4 ;
    END
  END rr_w[17]
  PIN rr_w[180]
    DIRECTION INPUT ;
    USE SIGNAL ;
    PORT
      LAYER M5 ;
        RECT  45.696 86.316 45.72 86.4 ;
    END
  END rr_w[180]
  PIN rr_w[181]
    DIRECTION INPUT ;
    USE SIGNAL ;
    PORT
      LAYER M5 ;
        RECT  45.936 86.316 45.96 86.4 ;
    END
  END rr_w[181]
  PIN rr_w[182]
    DIRECTION INPUT ;
    USE SIGNAL ;
    PORT
      LAYER M5 ;
        RECT  46.176 86.316 46.2 86.4 ;
    END
  END rr_w[182]
  PIN rr_w[183]
    DIRECTION INPUT ;
    USE SIGNAL ;
    PORT
      LAYER M5 ;
        RECT  46.416 86.316 46.44 86.4 ;
    END
  END rr_w[183]
  PIN rr_w[184]
    DIRECTION INPUT ;
    USE SIGNAL ;
    PORT
      LAYER M5 ;
        RECT  46.704 86.316 46.728 86.4 ;
    END
  END rr_w[184]
  PIN rr_w[185]
    DIRECTION INPUT ;
    USE SIGNAL ;
    PORT
      LAYER M5 ;
        RECT  46.944 86.316 46.968 86.4 ;
    END
  END rr_w[185]
  PIN rr_w[186]
    DIRECTION INPUT ;
    USE SIGNAL ;
    PORT
      LAYER M5 ;
        RECT  47.184 86.316 47.208 86.4 ;
    END
  END rr_w[186]
  PIN rr_w[187]
    DIRECTION INPUT ;
    USE SIGNAL ;
    PORT
      LAYER M5 ;
        RECT  47.472 86.316 47.496 86.4 ;
    END
  END rr_w[187]
  PIN rr_w[188]
    DIRECTION INPUT ;
    USE SIGNAL ;
    PORT
      LAYER M5 ;
        RECT  47.712 86.316 47.736 86.4 ;
    END
  END rr_w[188]
  PIN rr_w[189]
    DIRECTION INPUT ;
    USE SIGNAL ;
    PORT
      LAYER M5 ;
        RECT  47.952 86.316 47.976 86.4 ;
    END
  END rr_w[189]
  PIN rr_w[18]
    DIRECTION INPUT ;
    USE SIGNAL ;
    PORT
      LAYER M5 ;
        RECT  4.656 86.316 4.68 86.4 ;
    END
  END rr_w[18]
  PIN rr_w[190]
    DIRECTION INPUT ;
    USE SIGNAL ;
    PORT
      LAYER M5 ;
        RECT  48.192 86.316 48.216 86.4 ;
    END
  END rr_w[190]
  PIN rr_w[191]
    DIRECTION INPUT ;
    USE SIGNAL ;
    PORT
      LAYER M5 ;
        RECT  48.48 86.316 48.504 86.4 ;
    END
  END rr_w[191]
  PIN rr_w[192]
    DIRECTION INPUT ;
    USE SIGNAL ;
    PORT
      LAYER M5 ;
        RECT  48.72 86.316 48.744 86.4 ;
    END
  END rr_w[192]
  PIN rr_w[193]
    DIRECTION INPUT ;
    USE SIGNAL ;
    PORT
      LAYER M5 ;
        RECT  48.96 86.316 48.984 86.4 ;
    END
  END rr_w[193]
  PIN rr_w[194]
    DIRECTION INPUT ;
    USE SIGNAL ;
    PORT
      LAYER M5 ;
        RECT  49.2 86.316 49.224 86.4 ;
    END
  END rr_w[194]
  PIN rr_w[195]
    DIRECTION INPUT ;
    USE SIGNAL ;
    PORT
      LAYER M5 ;
        RECT  49.488 86.316 49.512 86.4 ;
    END
  END rr_w[195]
  PIN rr_w[196]
    DIRECTION INPUT ;
    USE SIGNAL ;
    PORT
      LAYER M5 ;
        RECT  49.728 86.316 49.752 86.4 ;
    END
  END rr_w[196]
  PIN rr_w[197]
    DIRECTION INPUT ;
    USE SIGNAL ;
    PORT
      LAYER M5 ;
        RECT  49.968 86.316 49.992 86.4 ;
    END
  END rr_w[197]
  PIN rr_w[198]
    DIRECTION INPUT ;
    USE SIGNAL ;
    PORT
      LAYER M5 ;
        RECT  50.256 86.316 50.28 86.4 ;
    END
  END rr_w[198]
  PIN rr_w[199]
    DIRECTION INPUT ;
    USE SIGNAL ;
    PORT
      LAYER M5 ;
        RECT  50.496 86.316 50.52 86.4 ;
    END
  END rr_w[199]
  PIN rr_w[19]
    DIRECTION INPUT ;
    USE SIGNAL ;
    PORT
      LAYER M5 ;
        RECT  4.944 86.316 4.968 86.4 ;
    END
  END rr_w[19]
  PIN rr_w[1]
    DIRECTION INPUT ;
    USE SIGNAL ;
    PORT
      LAYER M5 ;
        RECT  0.384 86.316 0.408 86.4 ;
    END
  END rr_w[1]
  PIN rr_w[200]
    DIRECTION INPUT ;
    USE SIGNAL ;
    PORT
      LAYER M5 ;
        RECT  50.736 86.316 50.76 86.4 ;
    END
  END rr_w[200]
  PIN rr_w[201]
    DIRECTION INPUT ;
    USE SIGNAL ;
    PORT
      LAYER M5 ;
        RECT  50.976 86.316 51 86.4 ;
    END
  END rr_w[201]
  PIN rr_w[202]
    DIRECTION INPUT ;
    USE SIGNAL ;
    PORT
      LAYER M5 ;
        RECT  51.264 86.316 51.288 86.4 ;
    END
  END rr_w[202]
  PIN rr_w[203]
    DIRECTION INPUT ;
    USE SIGNAL ;
    PORT
      LAYER M5 ;
        RECT  51.504 86.316 51.528 86.4 ;
    END
  END rr_w[203]
  PIN rr_w[204]
    DIRECTION INPUT ;
    USE SIGNAL ;
    PORT
      LAYER M5 ;
        RECT  51.744 86.316 51.768 86.4 ;
    END
  END rr_w[204]
  PIN rr_w[205]
    DIRECTION INPUT ;
    USE SIGNAL ;
    PORT
      LAYER M5 ;
        RECT  51.984 86.316 52.008 86.4 ;
    END
  END rr_w[205]
  PIN rr_w[206]
    DIRECTION INPUT ;
    USE SIGNAL ;
    PORT
      LAYER M5 ;
        RECT  52.272 86.316 52.296 86.4 ;
    END
  END rr_w[206]
  PIN rr_w[207]
    DIRECTION INPUT ;
    USE SIGNAL ;
    PORT
      LAYER M5 ;
        RECT  52.512 86.316 52.536 86.4 ;
    END
  END rr_w[207]
  PIN rr_w[208]
    DIRECTION INPUT ;
    USE SIGNAL ;
    PORT
      LAYER M5 ;
        RECT  52.752 86.316 52.776 86.4 ;
    END
  END rr_w[208]
  PIN rr_w[209]
    DIRECTION INPUT ;
    USE SIGNAL ;
    PORT
      LAYER M5 ;
        RECT  53.04 86.316 53.064 86.4 ;
    END
  END rr_w[209]
  PIN rr_w[20]
    DIRECTION INPUT ;
    USE SIGNAL ;
    PORT
      LAYER M5 ;
        RECT  5.184 86.316 5.208 86.4 ;
    END
  END rr_w[20]
  PIN rr_w[210]
    DIRECTION INPUT ;
    USE SIGNAL ;
    PORT
      LAYER M5 ;
        RECT  53.28 86.316 53.304 86.4 ;
    END
  END rr_w[210]
  PIN rr_w[211]
    DIRECTION INPUT ;
    USE SIGNAL ;
    PORT
      LAYER M5 ;
        RECT  53.52 86.316 53.544 86.4 ;
    END
  END rr_w[211]
  PIN rr_w[212]
    DIRECTION INPUT ;
    USE SIGNAL ;
    PORT
      LAYER M5 ;
        RECT  53.76 86.316 53.784 86.4 ;
    END
  END rr_w[212]
  PIN rr_w[213]
    DIRECTION INPUT ;
    USE SIGNAL ;
    PORT
      LAYER M5 ;
        RECT  54.048 86.316 54.072 86.4 ;
    END
  END rr_w[213]
  PIN rr_w[214]
    DIRECTION INPUT ;
    USE SIGNAL ;
    PORT
      LAYER M5 ;
        RECT  54.288 86.316 54.312 86.4 ;
    END
  END rr_w[214]
  PIN rr_w[215]
    DIRECTION INPUT ;
    USE SIGNAL ;
    PORT
      LAYER M5 ;
        RECT  54.528 86.316 54.552 86.4 ;
    END
  END rr_w[215]
  PIN rr_w[216]
    DIRECTION INPUT ;
    USE SIGNAL ;
    PORT
      LAYER M5 ;
        RECT  54.768 86.316 54.792 86.4 ;
    END
  END rr_w[216]
  PIN rr_w[217]
    DIRECTION INPUT ;
    USE SIGNAL ;
    PORT
      LAYER M5 ;
        RECT  55.056 86.316 55.08 86.4 ;
    END
  END rr_w[217]
  PIN rr_w[218]
    DIRECTION INPUT ;
    USE SIGNAL ;
    PORT
      LAYER M5 ;
        RECT  55.296 86.316 55.32 86.4 ;
    END
  END rr_w[218]
  PIN rr_w[219]
    DIRECTION INPUT ;
    USE SIGNAL ;
    PORT
      LAYER M5 ;
        RECT  55.536 86.316 55.56 86.4 ;
    END
  END rr_w[219]
  PIN rr_w[21]
    DIRECTION INPUT ;
    USE SIGNAL ;
    PORT
      LAYER M5 ;
        RECT  5.424 86.316 5.448 86.4 ;
    END
  END rr_w[21]
  PIN rr_w[220]
    DIRECTION INPUT ;
    USE SIGNAL ;
    PORT
      LAYER M5 ;
        RECT  55.824 86.316 55.848 86.4 ;
    END
  END rr_w[220]
  PIN rr_w[221]
    DIRECTION INPUT ;
    USE SIGNAL ;
    PORT
      LAYER M5 ;
        RECT  56.064 86.316 56.088 86.4 ;
    END
  END rr_w[221]
  PIN rr_w[222]
    DIRECTION INPUT ;
    USE SIGNAL ;
    PORT
      LAYER M5 ;
        RECT  56.304 86.316 56.328 86.4 ;
    END
  END rr_w[222]
  PIN rr_w[223]
    DIRECTION INPUT ;
    USE SIGNAL ;
    PORT
      LAYER M5 ;
        RECT  56.544 86.316 56.568 86.4 ;
    END
  END rr_w[223]
  PIN rr_w[224]
    DIRECTION INPUT ;
    USE SIGNAL ;
    PORT
      LAYER M5 ;
        RECT  56.832 86.316 56.856 86.4 ;
    END
  END rr_w[224]
  PIN rr_w[225]
    DIRECTION INPUT ;
    USE SIGNAL ;
    PORT
      LAYER M5 ;
        RECT  57.072 86.316 57.096 86.4 ;
    END
  END rr_w[225]
  PIN rr_w[226]
    DIRECTION INPUT ;
    USE SIGNAL ;
    PORT
      LAYER M5 ;
        RECT  57.312 86.316 57.336 86.4 ;
    END
  END rr_w[226]
  PIN rr_w[227]
    DIRECTION INPUT ;
    USE SIGNAL ;
    PORT
      LAYER M5 ;
        RECT  57.552 86.316 57.576 86.4 ;
    END
  END rr_w[227]
  PIN rr_w[228]
    DIRECTION INPUT ;
    USE SIGNAL ;
    PORT
      LAYER M5 ;
        RECT  57.84 86.316 57.864 86.4 ;
    END
  END rr_w[228]
  PIN rr_w[229]
    DIRECTION INPUT ;
    USE SIGNAL ;
    PORT
      LAYER M5 ;
        RECT  58.08 86.316 58.104 86.4 ;
    END
  END rr_w[229]
  PIN rr_w[22]
    DIRECTION INPUT ;
    USE SIGNAL ;
    PORT
      LAYER M5 ;
        RECT  5.664 86.316 5.688 86.4 ;
    END
  END rr_w[22]
  PIN rr_w[230]
    DIRECTION INPUT ;
    USE SIGNAL ;
    PORT
      LAYER M5 ;
        RECT  58.32 86.316 58.344 86.4 ;
    END
  END rr_w[230]
  PIN rr_w[231]
    DIRECTION INPUT ;
    USE SIGNAL ;
    PORT
      LAYER M5 ;
        RECT  58.608 86.316 58.632 86.4 ;
    END
  END rr_w[231]
  PIN rr_w[232]
    DIRECTION INPUT ;
    USE SIGNAL ;
    PORT
      LAYER M5 ;
        RECT  58.848 86.316 58.872 86.4 ;
    END
  END rr_w[232]
  PIN rr_w[233]
    DIRECTION INPUT ;
    USE SIGNAL ;
    PORT
      LAYER M5 ;
        RECT  59.088 86.316 59.112 86.4 ;
    END
  END rr_w[233]
  PIN rr_w[234]
    DIRECTION INPUT ;
    USE SIGNAL ;
    PORT
      LAYER M5 ;
        RECT  59.328 86.316 59.352 86.4 ;
    END
  END rr_w[234]
  PIN rr_w[235]
    DIRECTION INPUT ;
    USE SIGNAL ;
    PORT
      LAYER M5 ;
        RECT  59.616 86.316 59.64 86.4 ;
    END
  END rr_w[235]
  PIN rr_w[236]
    DIRECTION INPUT ;
    USE SIGNAL ;
    PORT
      LAYER M5 ;
        RECT  59.856 86.316 59.88 86.4 ;
    END
  END rr_w[236]
  PIN rr_w[237]
    DIRECTION INPUT ;
    USE SIGNAL ;
    PORT
      LAYER M5 ;
        RECT  60.096 86.316 60.12 86.4 ;
    END
  END rr_w[237]
  PIN rr_w[238]
    DIRECTION INPUT ;
    USE SIGNAL ;
    PORT
      LAYER M5 ;
        RECT  60.336 86.316 60.36 86.4 ;
    END
  END rr_w[238]
  PIN rr_w[239]
    DIRECTION INPUT ;
    USE SIGNAL ;
    PORT
      LAYER M5 ;
        RECT  60.624 86.316 60.648 86.4 ;
    END
  END rr_w[239]
  PIN rr_w[23]
    DIRECTION INPUT ;
    USE SIGNAL ;
    PORT
      LAYER M5 ;
        RECT  5.952 86.316 5.976 86.4 ;
    END
  END rr_w[23]
  PIN rr_w[240]
    DIRECTION INPUT ;
    USE SIGNAL ;
    PORT
      LAYER M5 ;
        RECT  60.864 86.316 60.888 86.4 ;
    END
  END rr_w[240]
  PIN rr_w[241]
    DIRECTION INPUT ;
    USE SIGNAL ;
    PORT
      LAYER M5 ;
        RECT  61.104 86.316 61.128 86.4 ;
    END
  END rr_w[241]
  PIN rr_w[242]
    DIRECTION INPUT ;
    USE SIGNAL ;
    PORT
      LAYER M5 ;
        RECT  61.392 86.316 61.416 86.4 ;
    END
  END rr_w[242]
  PIN rr_w[243]
    DIRECTION INPUT ;
    USE SIGNAL ;
    PORT
      LAYER M5 ;
        RECT  61.632 86.316 61.656 86.4 ;
    END
  END rr_w[243]
  PIN rr_w[244]
    DIRECTION INPUT ;
    USE SIGNAL ;
    PORT
      LAYER M5 ;
        RECT  61.872 86.316 61.896 86.4 ;
    END
  END rr_w[244]
  PIN rr_w[245]
    DIRECTION INPUT ;
    USE SIGNAL ;
    PORT
      LAYER M5 ;
        RECT  62.112 86.316 62.136 86.4 ;
    END
  END rr_w[245]
  PIN rr_w[246]
    DIRECTION INPUT ;
    USE SIGNAL ;
    PORT
      LAYER M5 ;
        RECT  62.4 86.316 62.424 86.4 ;
    END
  END rr_w[246]
  PIN rr_w[247]
    DIRECTION INPUT ;
    USE SIGNAL ;
    PORT
      LAYER M5 ;
        RECT  62.64 86.316 62.664 86.4 ;
    END
  END rr_w[247]
  PIN rr_w[248]
    DIRECTION INPUT ;
    USE SIGNAL ;
    PORT
      LAYER M5 ;
        RECT  62.88 86.316 62.904 86.4 ;
    END
  END rr_w[248]
  PIN rr_w[249]
    DIRECTION INPUT ;
    USE SIGNAL ;
    PORT
      LAYER M5 ;
        RECT  63.12 86.316 63.144 86.4 ;
    END
  END rr_w[249]
  PIN rr_w[24]
    DIRECTION INPUT ;
    USE SIGNAL ;
    PORT
      LAYER M5 ;
        RECT  6.192 86.316 6.216 86.4 ;
    END
  END rr_w[24]
  PIN rr_w[250]
    DIRECTION INPUT ;
    USE SIGNAL ;
    PORT
      LAYER M5 ;
        RECT  63.408 86.316 63.432 86.4 ;
    END
  END rr_w[250]
  PIN rr_w[251]
    DIRECTION INPUT ;
    USE SIGNAL ;
    PORT
      LAYER M5 ;
        RECT  63.648 86.316 63.672 86.4 ;
    END
  END rr_w[251]
  PIN rr_w[252]
    DIRECTION INPUT ;
    USE SIGNAL ;
    PORT
      LAYER M5 ;
        RECT  63.888 86.316 63.912 86.4 ;
    END
  END rr_w[252]
  PIN rr_w[253]
    DIRECTION INPUT ;
    USE SIGNAL ;
    PORT
      LAYER M5 ;
        RECT  64.176 86.316 64.2 86.4 ;
    END
  END rr_w[253]
  PIN rr_w[254]
    DIRECTION INPUT ;
    USE SIGNAL ;
    PORT
      LAYER M5 ;
        RECT  64.416 86.316 64.44 86.4 ;
    END
  END rr_w[254]
  PIN rr_w[255]
    DIRECTION INPUT ;
    USE SIGNAL ;
    PORT
      LAYER M5 ;
        RECT  64.656 86.316 64.68 86.4 ;
    END
  END rr_w[255]
  PIN rr_w[256]
    DIRECTION INPUT ;
    USE SIGNAL ;
    PORT
      LAYER M5 ;
        RECT  64.896 86.316 64.92 86.4 ;
    END
  END rr_w[256]
  PIN rr_w[257]
    DIRECTION INPUT ;
    USE SIGNAL ;
    PORT
      LAYER M5 ;
        RECT  65.184 86.316 65.208 86.4 ;
    END
  END rr_w[257]
  PIN rr_w[258]
    DIRECTION INPUT ;
    USE SIGNAL ;
    PORT
      LAYER M5 ;
        RECT  65.424 86.316 65.448 86.4 ;
    END
  END rr_w[258]
  PIN rr_w[259]
    DIRECTION INPUT ;
    USE SIGNAL ;
    PORT
      LAYER M5 ;
        RECT  65.664 86.316 65.688 86.4 ;
    END
  END rr_w[259]
  PIN rr_w[25]
    DIRECTION INPUT ;
    USE SIGNAL ;
    PORT
      LAYER M5 ;
        RECT  6.432 86.316 6.456 86.4 ;
    END
  END rr_w[25]
  PIN rr_w[260]
    DIRECTION INPUT ;
    USE SIGNAL ;
    PORT
      LAYER M5 ;
        RECT  65.904 86.316 65.928 86.4 ;
    END
  END rr_w[260]
  PIN rr_w[261]
    DIRECTION INPUT ;
    USE SIGNAL ;
    PORT
      LAYER M5 ;
        RECT  66.192 86.316 66.216 86.4 ;
    END
  END rr_w[261]
  PIN rr_w[262]
    DIRECTION INPUT ;
    USE SIGNAL ;
    PORT
      LAYER M5 ;
        RECT  66.432 86.316 66.456 86.4 ;
    END
  END rr_w[262]
  PIN rr_w[263]
    DIRECTION INPUT ;
    USE SIGNAL ;
    PORT
      LAYER M5 ;
        RECT  66.672 86.316 66.696 86.4 ;
    END
  END rr_w[263]
  PIN rr_w[264]
    DIRECTION INPUT ;
    USE SIGNAL ;
    PORT
      LAYER M5 ;
        RECT  66.96 86.316 66.984 86.4 ;
    END
  END rr_w[264]
  PIN rr_w[265]
    DIRECTION INPUT ;
    USE SIGNAL ;
    PORT
      LAYER M5 ;
        RECT  67.2 86.316 67.224 86.4 ;
    END
  END rr_w[265]
  PIN rr_w[266]
    DIRECTION INPUT ;
    USE SIGNAL ;
    PORT
      LAYER M5 ;
        RECT  67.44 86.316 67.464 86.4 ;
    END
  END rr_w[266]
  PIN rr_w[267]
    DIRECTION INPUT ;
    USE SIGNAL ;
    PORT
      LAYER M5 ;
        RECT  67.68 86.316 67.704 86.4 ;
    END
  END rr_w[267]
  PIN rr_w[268]
    DIRECTION INPUT ;
    USE SIGNAL ;
    PORT
      LAYER M5 ;
        RECT  67.968 86.316 67.992 86.4 ;
    END
  END rr_w[268]
  PIN rr_w[269]
    DIRECTION INPUT ;
    USE SIGNAL ;
    PORT
      LAYER M5 ;
        RECT  68.208 86.316 68.232 86.4 ;
    END
  END rr_w[269]
  PIN rr_w[26]
    DIRECTION INPUT ;
    USE SIGNAL ;
    PORT
      LAYER M5 ;
        RECT  6.72 86.316 6.744 86.4 ;
    END
  END rr_w[26]
  PIN rr_w[270]
    DIRECTION INPUT ;
    USE SIGNAL ;
    PORT
      LAYER M5 ;
        RECT  68.448 86.316 68.472 86.4 ;
    END
  END rr_w[270]
  PIN rr_w[271]
    DIRECTION INPUT ;
    USE SIGNAL ;
    PORT
      LAYER M5 ;
        RECT  68.688 86.316 68.712 86.4 ;
    END
  END rr_w[271]
  PIN rr_w[272]
    DIRECTION INPUT ;
    USE SIGNAL ;
    PORT
      LAYER M5 ;
        RECT  68.976 86.316 69 86.4 ;
    END
  END rr_w[272]
  PIN rr_w[273]
    DIRECTION INPUT ;
    USE SIGNAL ;
    PORT
      LAYER M5 ;
        RECT  69.216 86.316 69.24 86.4 ;
    END
  END rr_w[273]
  PIN rr_w[274]
    DIRECTION INPUT ;
    USE SIGNAL ;
    PORT
      LAYER M5 ;
        RECT  69.456 86.316 69.48 86.4 ;
    END
  END rr_w[274]
  PIN rr_w[275]
    DIRECTION INPUT ;
    USE SIGNAL ;
    PORT
      LAYER M5 ;
        RECT  69.744 86.316 69.768 86.4 ;
    END
  END rr_w[275]
  PIN rr_w[276]
    DIRECTION INPUT ;
    USE SIGNAL ;
    PORT
      LAYER M5 ;
        RECT  69.984 86.316 70.008 86.4 ;
    END
  END rr_w[276]
  PIN rr_w[277]
    DIRECTION INPUT ;
    USE SIGNAL ;
    PORT
      LAYER M5 ;
        RECT  70.224 86.316 70.248 86.4 ;
    END
  END rr_w[277]
  PIN rr_w[278]
    DIRECTION INPUT ;
    USE SIGNAL ;
    PORT
      LAYER M5 ;
        RECT  70.464 86.316 70.488 86.4 ;
    END
  END rr_w[278]
  PIN rr_w[279]
    DIRECTION INPUT ;
    USE SIGNAL ;
    PORT
      LAYER M5 ;
        RECT  70.752 86.316 70.776 86.4 ;
    END
  END rr_w[279]
  PIN rr_w[27]
    DIRECTION INPUT ;
    USE SIGNAL ;
    PORT
      LAYER M5 ;
        RECT  6.96 86.316 6.984 86.4 ;
    END
  END rr_w[27]
  PIN rr_w[280]
    DIRECTION INPUT ;
    USE SIGNAL ;
    PORT
      LAYER M5 ;
        RECT  70.992 86.316 71.016 86.4 ;
    END
  END rr_w[280]
  PIN rr_w[281]
    DIRECTION INPUT ;
    USE SIGNAL ;
    PORT
      LAYER M5 ;
        RECT  71.232 86.316 71.256 86.4 ;
    END
  END rr_w[281]
  PIN rr_w[282]
    DIRECTION INPUT ;
    USE SIGNAL ;
    PORT
      LAYER M5 ;
        RECT  71.52 86.316 71.544 86.4 ;
    END
  END rr_w[282]
  PIN rr_w[283]
    DIRECTION INPUT ;
    USE SIGNAL ;
    PORT
      LAYER M5 ;
        RECT  71.76 86.316 71.784 86.4 ;
    END
  END rr_w[283]
  PIN rr_w[284]
    DIRECTION INPUT ;
    USE SIGNAL ;
    PORT
      LAYER M5 ;
        RECT  72 86.316 72.024 86.4 ;
    END
  END rr_w[284]
  PIN rr_w[285]
    DIRECTION INPUT ;
    USE SIGNAL ;
    PORT
      LAYER M5 ;
        RECT  72.24 86.316 72.264 86.4 ;
    END
  END rr_w[285]
  PIN rr_w[286]
    DIRECTION INPUT ;
    USE SIGNAL ;
    PORT
      LAYER M5 ;
        RECT  72.528 86.316 72.552 86.4 ;
    END
  END rr_w[286]
  PIN rr_w[287]
    DIRECTION INPUT ;
    USE SIGNAL ;
    PORT
      LAYER M5 ;
        RECT  72.768 86.316 72.792 86.4 ;
    END
  END rr_w[287]
  PIN rr_w[288]
    DIRECTION INPUT ;
    USE SIGNAL ;
    PORT
      LAYER M5 ;
        RECT  73.008 86.316 73.032 86.4 ;
    END
  END rr_w[288]
  PIN rr_w[289]
    DIRECTION INPUT ;
    USE SIGNAL ;
    PORT
      LAYER M5 ;
        RECT  73.248 86.316 73.272 86.4 ;
    END
  END rr_w[289]
  PIN rr_w[28]
    DIRECTION INPUT ;
    USE SIGNAL ;
    PORT
      LAYER M5 ;
        RECT  7.2 86.316 7.224 86.4 ;
    END
  END rr_w[28]
  PIN rr_w[290]
    DIRECTION INPUT ;
    USE SIGNAL ;
    PORT
      LAYER M5 ;
        RECT  73.536 86.316 73.56 86.4 ;
    END
  END rr_w[290]
  PIN rr_w[291]
    DIRECTION INPUT ;
    USE SIGNAL ;
    PORT
      LAYER M5 ;
        RECT  73.776 86.316 73.8 86.4 ;
    END
  END rr_w[291]
  PIN rr_w[292]
    DIRECTION INPUT ;
    USE SIGNAL ;
    PORT
      LAYER M5 ;
        RECT  74.016 86.316 74.04 86.4 ;
    END
  END rr_w[292]
  PIN rr_w[293]
    DIRECTION INPUT ;
    USE SIGNAL ;
    PORT
      LAYER M5 ;
        RECT  74.304 86.316 74.328 86.4 ;
    END
  END rr_w[293]
  PIN rr_w[294]
    DIRECTION INPUT ;
    USE SIGNAL ;
    PORT
      LAYER M5 ;
        RECT  74.544 86.316 74.568 86.4 ;
    END
  END rr_w[294]
  PIN rr_w[295]
    DIRECTION INPUT ;
    USE SIGNAL ;
    PORT
      LAYER M5 ;
        RECT  74.784 86.316 74.808 86.4 ;
    END
  END rr_w[295]
  PIN rr_w[296]
    DIRECTION INPUT ;
    USE SIGNAL ;
    PORT
      LAYER M5 ;
        RECT  75.024 86.316 75.048 86.4 ;
    END
  END rr_w[296]
  PIN rr_w[297]
    DIRECTION INPUT ;
    USE SIGNAL ;
    PORT
      LAYER M5 ;
        RECT  75.312 86.316 75.336 86.4 ;
    END
  END rr_w[297]
  PIN rr_w[298]
    DIRECTION INPUT ;
    USE SIGNAL ;
    PORT
      LAYER M5 ;
        RECT  75.552 86.316 75.576 86.4 ;
    END
  END rr_w[298]
  PIN rr_w[299]
    DIRECTION INPUT ;
    USE SIGNAL ;
    PORT
      LAYER M5 ;
        RECT  75.792 86.316 75.816 86.4 ;
    END
  END rr_w[299]
  PIN rr_w[29]
    DIRECTION INPUT ;
    USE SIGNAL ;
    PORT
      LAYER M5 ;
        RECT  7.44 86.316 7.464 86.4 ;
    END
  END rr_w[29]
  PIN rr_w[2]
    DIRECTION INPUT ;
    USE SIGNAL ;
    PORT
      LAYER M5 ;
        RECT  0.624 86.316 0.648 86.4 ;
    END
  END rr_w[2]
  PIN rr_w[300]
    DIRECTION INPUT ;
    USE SIGNAL ;
    PORT
      LAYER M5 ;
        RECT  76.032 86.316 76.056 86.4 ;
    END
  END rr_w[300]
  PIN rr_w[301]
    DIRECTION INPUT ;
    USE SIGNAL ;
    PORT
      LAYER M5 ;
        RECT  76.32 86.316 76.344 86.4 ;
    END
  END rr_w[301]
  PIN rr_w[302]
    DIRECTION INPUT ;
    USE SIGNAL ;
    PORT
      LAYER M5 ;
        RECT  76.56 86.316 76.584 86.4 ;
    END
  END rr_w[302]
  PIN rr_w[303]
    DIRECTION INPUT ;
    USE SIGNAL ;
    PORT
      LAYER M5 ;
        RECT  76.8 86.316 76.824 86.4 ;
    END
  END rr_w[303]
  PIN rr_w[304]
    DIRECTION INPUT ;
    USE SIGNAL ;
    PORT
      LAYER M5 ;
        RECT  77.088 86.316 77.112 86.4 ;
    END
  END rr_w[304]
  PIN rr_w[305]
    DIRECTION INPUT ;
    USE SIGNAL ;
    PORT
      LAYER M5 ;
        RECT  77.328 86.316 77.352 86.4 ;
    END
  END rr_w[305]
  PIN rr_w[306]
    DIRECTION INPUT ;
    USE SIGNAL ;
    PORT
      LAYER M5 ;
        RECT  77.568 86.316 77.592 86.4 ;
    END
  END rr_w[306]
  PIN rr_w[307]
    DIRECTION INPUT ;
    USE SIGNAL ;
    PORT
      LAYER M5 ;
        RECT  77.808 86.316 77.832 86.4 ;
    END
  END rr_w[307]
  PIN rr_w[308]
    DIRECTION INPUT ;
    USE SIGNAL ;
    PORT
      LAYER M5 ;
        RECT  78.096 86.316 78.12 86.4 ;
    END
  END rr_w[308]
  PIN rr_w[309]
    DIRECTION INPUT ;
    USE SIGNAL ;
    PORT
      LAYER M5 ;
        RECT  78.336 86.316 78.36 86.4 ;
    END
  END rr_w[309]
  PIN rr_w[30]
    DIRECTION INPUT ;
    USE SIGNAL ;
    PORT
      LAYER M5 ;
        RECT  7.728 86.316 7.752 86.4 ;
    END
  END rr_w[30]
  PIN rr_w[310]
    DIRECTION INPUT ;
    USE SIGNAL ;
    PORT
      LAYER M5 ;
        RECT  78.576 86.316 78.6 86.4 ;
    END
  END rr_w[310]
  PIN rr_w[311]
    DIRECTION INPUT ;
    USE SIGNAL ;
    PORT
      LAYER M5 ;
        RECT  78.816 86.316 78.84 86.4 ;
    END
  END rr_w[311]
  PIN rr_w[312]
    DIRECTION INPUT ;
    USE SIGNAL ;
    PORT
      LAYER M5 ;
        RECT  79.104 86.316 79.128 86.4 ;
    END
  END rr_w[312]
  PIN rr_w[313]
    DIRECTION INPUT ;
    USE SIGNAL ;
    PORT
      LAYER M5 ;
        RECT  79.344 86.316 79.368 86.4 ;
    END
  END rr_w[313]
  PIN rr_w[314]
    DIRECTION INPUT ;
    USE SIGNAL ;
    PORT
      LAYER M5 ;
        RECT  79.584 86.316 79.608 86.4 ;
    END
  END rr_w[314]
  PIN rr_w[315]
    DIRECTION INPUT ;
    USE SIGNAL ;
    PORT
      LAYER M5 ;
        RECT  79.872 86.316 79.896 86.4 ;
    END
  END rr_w[315]
  PIN rr_w[316]
    DIRECTION INPUT ;
    USE SIGNAL ;
    PORT
      LAYER M5 ;
        RECT  80.112 86.316 80.136 86.4 ;
    END
  END rr_w[316]
  PIN rr_w[317]
    DIRECTION INPUT ;
    USE SIGNAL ;
    PORT
      LAYER M5 ;
        RECT  80.352 86.316 80.376 86.4 ;
    END
  END rr_w[317]
  PIN rr_w[318]
    DIRECTION INPUT ;
    USE SIGNAL ;
    PORT
      LAYER M5 ;
        RECT  80.592 86.316 80.616 86.4 ;
    END
  END rr_w[318]
  PIN rr_w[319]
    DIRECTION INPUT ;
    USE SIGNAL ;
    PORT
      LAYER M5 ;
        RECT  80.88 86.316 80.904 86.4 ;
    END
  END rr_w[319]
  PIN rr_w[31]
    DIRECTION INPUT ;
    USE SIGNAL ;
    PORT
      LAYER M5 ;
        RECT  7.968 86.316 7.992 86.4 ;
    END
  END rr_w[31]
  PIN rr_w[320]
    DIRECTION INPUT ;
    USE SIGNAL ;
    PORT
      LAYER M5 ;
        RECT  81.12 86.316 81.144 86.4 ;
    END
  END rr_w[320]
  PIN rr_w[321]
    DIRECTION INPUT ;
    USE SIGNAL ;
    PORT
      LAYER M5 ;
        RECT  81.36 86.316 81.384 86.4 ;
    END
  END rr_w[321]
  PIN rr_w[322]
    DIRECTION INPUT ;
    USE SIGNAL ;
    PORT
      LAYER M5 ;
        RECT  81.6 86.316 81.624 86.4 ;
    END
  END rr_w[322]
  PIN rr_w[323]
    DIRECTION INPUT ;
    USE SIGNAL ;
    PORT
      LAYER M5 ;
        RECT  81.888 86.316 81.912 86.4 ;
    END
  END rr_w[323]
  PIN rr_w[324]
    DIRECTION INPUT ;
    USE SIGNAL ;
    PORT
      LAYER M5 ;
        RECT  82.128 86.316 82.152 86.4 ;
    END
  END rr_w[324]
  PIN rr_w[325]
    DIRECTION INPUT ;
    USE SIGNAL ;
    PORT
      LAYER M5 ;
        RECT  82.368 86.316 82.392 86.4 ;
    END
  END rr_w[325]
  PIN rr_w[326]
    DIRECTION INPUT ;
    USE SIGNAL ;
    PORT
      LAYER M5 ;
        RECT  82.656 86.316 82.68 86.4 ;
    END
  END rr_w[326]
  PIN rr_w[327]
    DIRECTION INPUT ;
    USE SIGNAL ;
    PORT
      LAYER M5 ;
        RECT  82.896 86.316 82.92 86.4 ;
    END
  END rr_w[327]
  PIN rr_w[328]
    DIRECTION INPUT ;
    USE SIGNAL ;
    PORT
      LAYER M5 ;
        RECT  83.136 86.316 83.16 86.4 ;
    END
  END rr_w[328]
  PIN rr_w[329]
    DIRECTION INPUT ;
    USE SIGNAL ;
    PORT
      LAYER M5 ;
        RECT  83.376 86.316 83.4 86.4 ;
    END
  END rr_w[329]
  PIN rr_w[32]
    DIRECTION INPUT ;
    USE SIGNAL ;
    PORT
      LAYER M5 ;
        RECT  8.208 86.316 8.232 86.4 ;
    END
  END rr_w[32]
  PIN rr_w[330]
    DIRECTION INPUT ;
    USE SIGNAL ;
    PORT
      LAYER M5 ;
        RECT  83.664 86.316 83.688 86.4 ;
    END
  END rr_w[330]
  PIN rr_w[331]
    DIRECTION INPUT ;
    USE SIGNAL ;
    PORT
      LAYER M5 ;
        RECT  83.904 86.316 83.928 86.4 ;
    END
  END rr_w[331]
  PIN rr_w[332]
    DIRECTION INPUT ;
    USE SIGNAL ;
    PORT
      LAYER M5 ;
        RECT  84.144 86.316 84.168 86.4 ;
    END
  END rr_w[332]
  PIN rr_w[333]
    DIRECTION INPUT ;
    USE SIGNAL ;
    PORT
      LAYER M5 ;
        RECT  84.384 86.316 84.408 86.4 ;
    END
  END rr_w[333]
  PIN rr_w[334]
    DIRECTION INPUT ;
    USE SIGNAL ;
    PORT
      LAYER M5 ;
        RECT  84.672 86.316 84.696 86.4 ;
    END
  END rr_w[334]
  PIN rr_w[335]
    DIRECTION INPUT ;
    USE SIGNAL ;
    PORT
      LAYER M5 ;
        RECT  84.912 86.316 84.936 86.4 ;
    END
  END rr_w[335]
  PIN rr_w[336]
    DIRECTION INPUT ;
    USE SIGNAL ;
    PORT
      LAYER M5 ;
        RECT  85.152 86.316 85.176 86.4 ;
    END
  END rr_w[336]
  PIN rr_w[337]
    DIRECTION INPUT ;
    USE SIGNAL ;
    PORT
      LAYER M5 ;
        RECT  85.44 86.316 85.464 86.4 ;
    END
  END rr_w[337]
  PIN rr_w[338]
    DIRECTION INPUT ;
    USE SIGNAL ;
    PORT
      LAYER M5 ;
        RECT  85.68 86.316 85.704 86.4 ;
    END
  END rr_w[338]
  PIN rr_w[339]
    DIRECTION INPUT ;
    USE SIGNAL ;
    PORT
      LAYER M5 ;
        RECT  85.92 86.316 85.944 86.4 ;
    END
  END rr_w[339]
  PIN rr_w[33]
    DIRECTION INPUT ;
    USE SIGNAL ;
    PORT
      LAYER M5 ;
        RECT  8.448 86.316 8.472 86.4 ;
    END
  END rr_w[33]
  PIN rr_w[340]
    DIRECTION INPUT ;
    USE SIGNAL ;
    PORT
      LAYER M5 ;
        RECT  86.16 86.316 86.184 86.4 ;
    END
  END rr_w[340]
  PIN rr_w[341]
    DIRECTION INPUT ;
    USE SIGNAL ;
    PORT
      LAYER M5 ;
        RECT  86.448 86.316 86.472 86.4 ;
    END
  END rr_w[341]
  PIN rr_w[342]
    DIRECTION INPUT ;
    USE SIGNAL ;
    PORT
      LAYER M5 ;
        RECT  86.688 86.316 86.712 86.4 ;
    END
  END rr_w[342]
  PIN rr_w[343]
    DIRECTION INPUT ;
    USE SIGNAL ;
    PORT
      LAYER M5 ;
        RECT  86.928 86.316 86.952 86.4 ;
    END
  END rr_w[343]
  PIN rr_w[344]
    DIRECTION INPUT ;
    USE SIGNAL ;
    PORT
      LAYER M5 ;
        RECT  87.168 86.316 87.192 86.4 ;
    END
  END rr_w[344]
  PIN rr_w[345]
    DIRECTION INPUT ;
    USE SIGNAL ;
    PORT
      LAYER M5 ;
        RECT  87.456 86.316 87.48 86.4 ;
    END
  END rr_w[345]
  PIN rr_w[346]
    DIRECTION INPUT ;
    USE SIGNAL ;
    PORT
      LAYER M5 ;
        RECT  87.696 86.316 87.72 86.4 ;
    END
  END rr_w[346]
  PIN rr_w[347]
    DIRECTION INPUT ;
    USE SIGNAL ;
    PORT
      LAYER M5 ;
        RECT  87.936 86.316 87.96 86.4 ;
    END
  END rr_w[347]
  PIN rr_w[348]
    DIRECTION INPUT ;
    USE SIGNAL ;
    PORT
      LAYER M5 ;
        RECT  88.224 86.316 88.248 86.4 ;
    END
  END rr_w[348]
  PIN rr_w[349]
    DIRECTION INPUT ;
    USE SIGNAL ;
    PORT
      LAYER M5 ;
        RECT  88.464 86.316 88.488 86.4 ;
    END
  END rr_w[349]
  PIN rr_w[34]
    DIRECTION INPUT ;
    USE SIGNAL ;
    PORT
      LAYER M5 ;
        RECT  8.736 86.316 8.76 86.4 ;
    END
  END rr_w[34]
  PIN rr_w[350]
    DIRECTION INPUT ;
    USE SIGNAL ;
    PORT
      LAYER M5 ;
        RECT  88.704 86.316 88.728 86.4 ;
    END
  END rr_w[350]
  PIN rr_w[351]
    DIRECTION INPUT ;
    USE SIGNAL ;
    PORT
      LAYER M5 ;
        RECT  88.944 86.316 88.968 86.4 ;
    END
  END rr_w[351]
  PIN rr_w[352]
    DIRECTION INPUT ;
    USE SIGNAL ;
    PORT
      LAYER M5 ;
        RECT  89.232 86.316 89.256 86.4 ;
    END
  END rr_w[352]
  PIN rr_w[353]
    DIRECTION INPUT ;
    USE SIGNAL ;
    PORT
      LAYER M5 ;
        RECT  89.472 86.316 89.496 86.4 ;
    END
  END rr_w[353]
  PIN rr_w[354]
    DIRECTION INPUT ;
    USE SIGNAL ;
    PORT
      LAYER M5 ;
        RECT  89.712 86.316 89.736 86.4 ;
    END
  END rr_w[354]
  PIN rr_w[355]
    DIRECTION INPUT ;
    USE SIGNAL ;
    PORT
      LAYER M5 ;
        RECT  89.952 86.316 89.976 86.4 ;
    END
  END rr_w[355]
  PIN rr_w[356]
    DIRECTION INPUT ;
    USE SIGNAL ;
    PORT
      LAYER M5 ;
        RECT  90.24 86.316 90.264 86.4 ;
    END
  END rr_w[356]
  PIN rr_w[357]
    DIRECTION INPUT ;
    USE SIGNAL ;
    PORT
      LAYER M5 ;
        RECT  90.48 86.316 90.504 86.4 ;
    END
  END rr_w[357]
  PIN rr_w[358]
    DIRECTION INPUT ;
    USE SIGNAL ;
    PORT
      LAYER M5 ;
        RECT  90.72 86.316 90.744 86.4 ;
    END
  END rr_w[358]
  PIN rr_w[359]
    DIRECTION INPUT ;
    USE SIGNAL ;
    PORT
      LAYER M5 ;
        RECT  91.008 86.316 91.032 86.4 ;
    END
  END rr_w[359]
  PIN rr_w[35]
    DIRECTION INPUT ;
    USE SIGNAL ;
    PORT
      LAYER M5 ;
        RECT  8.976 86.316 9 86.4 ;
    END
  END rr_w[35]
  PIN rr_w[360]
    DIRECTION INPUT ;
    USE SIGNAL ;
    PORT
      LAYER M5 ;
        RECT  91.248 86.316 91.272 86.4 ;
    END
  END rr_w[360]
  PIN rr_w[361]
    DIRECTION INPUT ;
    USE SIGNAL ;
    PORT
      LAYER M5 ;
        RECT  91.488 86.316 91.512 86.4 ;
    END
  END rr_w[361]
  PIN rr_w[362]
    DIRECTION INPUT ;
    USE SIGNAL ;
    PORT
      LAYER M5 ;
        RECT  91.728 86.316 91.752 86.4 ;
    END
  END rr_w[362]
  PIN rr_w[363]
    DIRECTION INPUT ;
    USE SIGNAL ;
    PORT
      LAYER M5 ;
        RECT  92.016 86.316 92.04 86.4 ;
    END
  END rr_w[363]
  PIN rr_w[364]
    DIRECTION INPUT ;
    USE SIGNAL ;
    PORT
      LAYER M5 ;
        RECT  92.256 86.316 92.28 86.4 ;
    END
  END rr_w[364]
  PIN rr_w[365]
    DIRECTION INPUT ;
    USE SIGNAL ;
    PORT
      LAYER M5 ;
        RECT  92.496 86.316 92.52 86.4 ;
    END
  END rr_w[365]
  PIN rr_w[366]
    DIRECTION INPUT ;
    USE SIGNAL ;
    PORT
      LAYER M5 ;
        RECT  92.736 86.316 92.76 86.4 ;
    END
  END rr_w[366]
  PIN rr_w[367]
    DIRECTION INPUT ;
    USE SIGNAL ;
    PORT
      LAYER M5 ;
        RECT  93.024 86.316 93.048 86.4 ;
    END
  END rr_w[367]
  PIN rr_w[368]
    DIRECTION INPUT ;
    USE SIGNAL ;
    PORT
      LAYER M5 ;
        RECT  93.264 86.316 93.288 86.4 ;
    END
  END rr_w[368]
  PIN rr_w[369]
    DIRECTION INPUT ;
    USE SIGNAL ;
    PORT
      LAYER M5 ;
        RECT  93.504 86.316 93.528 86.4 ;
    END
  END rr_w[369]
  PIN rr_w[36]
    DIRECTION INPUT ;
    USE SIGNAL ;
    PORT
      LAYER M5 ;
        RECT  9.216 86.316 9.24 86.4 ;
    END
  END rr_w[36]
  PIN rr_w[370]
    DIRECTION INPUT ;
    USE SIGNAL ;
    PORT
      LAYER M5 ;
        RECT  93.792 86.316 93.816 86.4 ;
    END
  END rr_w[370]
  PIN rr_w[371]
    DIRECTION INPUT ;
    USE SIGNAL ;
    PORT
      LAYER M5 ;
        RECT  94.032 86.316 94.056 86.4 ;
    END
  END rr_w[371]
  PIN rr_w[372]
    DIRECTION INPUT ;
    USE SIGNAL ;
    PORT
      LAYER M5 ;
        RECT  94.272 86.316 94.296 86.4 ;
    END
  END rr_w[372]
  PIN rr_w[373]
    DIRECTION INPUT ;
    USE SIGNAL ;
    PORT
      LAYER M5 ;
        RECT  94.512 86.316 94.536 86.4 ;
    END
  END rr_w[373]
  PIN rr_w[374]
    DIRECTION INPUT ;
    USE SIGNAL ;
    PORT
      LAYER M5 ;
        RECT  94.8 86.316 94.824 86.4 ;
    END
  END rr_w[374]
  PIN rr_w[375]
    DIRECTION INPUT ;
    USE SIGNAL ;
    PORT
      LAYER M5 ;
        RECT  95.04 86.316 95.064 86.4 ;
    END
  END rr_w[375]
  PIN rr_w[376]
    DIRECTION INPUT ;
    USE SIGNAL ;
    PORT
      LAYER M5 ;
        RECT  95.28 86.316 95.304 86.4 ;
    END
  END rr_w[376]
  PIN rr_w[377]
    DIRECTION INPUT ;
    USE SIGNAL ;
    PORT
      LAYER M5 ;
        RECT  95.52 86.316 95.544 86.4 ;
    END
  END rr_w[377]
  PIN rr_w[378]
    DIRECTION INPUT ;
    USE SIGNAL ;
    PORT
      LAYER M5 ;
        RECT  95.808 86.316 95.832 86.4 ;
    END
  END rr_w[378]
  PIN rr_w[379]
    DIRECTION INPUT ;
    USE SIGNAL ;
    PORT
      LAYER M5 ;
        RECT  96.048 86.316 96.072 86.4 ;
    END
  END rr_w[379]
  PIN rr_w[37]
    DIRECTION INPUT ;
    USE SIGNAL ;
    PORT
      LAYER M5 ;
        RECT  9.504 86.316 9.528 86.4 ;
    END
  END rr_w[37]
  PIN rr_w[380]
    DIRECTION INPUT ;
    USE SIGNAL ;
    PORT
      LAYER M5 ;
        RECT  96.288 86.316 96.312 86.4 ;
    END
  END rr_w[380]
  PIN rr_w[381]
    DIRECTION INPUT ;
    USE SIGNAL ;
    PORT
      LAYER M5 ;
        RECT  96.576 86.316 96.6 86.4 ;
    END
  END rr_w[381]
  PIN rr_w[382]
    DIRECTION INPUT ;
    USE SIGNAL ;
    PORT
      LAYER M5 ;
        RECT  96.816 86.316 96.84 86.4 ;
    END
  END rr_w[382]
  PIN rr_w[383]
    DIRECTION INPUT ;
    USE SIGNAL ;
    PORT
      LAYER M5 ;
        RECT  97.056 86.316 97.08 86.4 ;
    END
  END rr_w[383]
  PIN rr_w[384]
    DIRECTION INPUT ;
    USE SIGNAL ;
    PORT
      LAYER M5 ;
        RECT  97.296 86.316 97.32 86.4 ;
    END
  END rr_w[384]
  PIN rr_w[385]
    DIRECTION INPUT ;
    USE SIGNAL ;
    PORT
      LAYER M5 ;
        RECT  97.584 86.316 97.608 86.4 ;
    END
  END rr_w[385]
  PIN rr_w[386]
    DIRECTION INPUT ;
    USE SIGNAL ;
    PORT
      LAYER M5 ;
        RECT  97.824 86.316 97.848 86.4 ;
    END
  END rr_w[386]
  PIN rr_w[387]
    DIRECTION INPUT ;
    USE SIGNAL ;
    PORT
      LAYER M5 ;
        RECT  98.064 86.316 98.088 86.4 ;
    END
  END rr_w[387]
  PIN rr_w[388]
    DIRECTION INPUT ;
    USE SIGNAL ;
    PORT
      LAYER M5 ;
        RECT  98.304 86.316 98.328 86.4 ;
    END
  END rr_w[388]
  PIN rr_w[389]
    DIRECTION INPUT ;
    USE SIGNAL ;
    PORT
      LAYER M5 ;
        RECT  98.592 86.316 98.616 86.4 ;
    END
  END rr_w[389]
  PIN rr_w[38]
    DIRECTION INPUT ;
    USE SIGNAL ;
    PORT
      LAYER M5 ;
        RECT  9.744 86.316 9.768 86.4 ;
    END
  END rr_w[38]
  PIN rr_w[390]
    DIRECTION INPUT ;
    USE SIGNAL ;
    PORT
      LAYER M5 ;
        RECT  98.832 86.316 98.856 86.4 ;
    END
  END rr_w[390]
  PIN rr_w[391]
    DIRECTION INPUT ;
    USE SIGNAL ;
    PORT
      LAYER M5 ;
        RECT  99.072 86.316 99.096 86.4 ;
    END
  END rr_w[391]
  PIN rr_w[392]
    DIRECTION INPUT ;
    USE SIGNAL ;
    PORT
      LAYER M5 ;
        RECT  99.36 86.316 99.384 86.4 ;
    END
  END rr_w[392]
  PIN rr_w[393]
    DIRECTION INPUT ;
    USE SIGNAL ;
    PORT
      LAYER M5 ;
        RECT  99.6 86.316 99.624 86.4 ;
    END
  END rr_w[393]
  PIN rr_w[394]
    DIRECTION INPUT ;
    USE SIGNAL ;
    PORT
      LAYER M5 ;
        RECT  99.84 86.316 99.864 86.4 ;
    END
  END rr_w[394]
  PIN rr_w[395]
    DIRECTION INPUT ;
    USE SIGNAL ;
    PORT
      LAYER M5 ;
        RECT  100.08 86.316 100.104 86.4 ;
    END
  END rr_w[395]
  PIN rr_w[396]
    DIRECTION INPUT ;
    USE SIGNAL ;
    PORT
      LAYER M5 ;
        RECT  100.368 86.316 100.392 86.4 ;
    END
  END rr_w[396]
  PIN rr_w[397]
    DIRECTION INPUT ;
    USE SIGNAL ;
    PORT
      LAYER M5 ;
        RECT  100.608 86.316 100.632 86.4 ;
    END
  END rr_w[397]
  PIN rr_w[398]
    DIRECTION INPUT ;
    USE SIGNAL ;
    PORT
      LAYER M5 ;
        RECT  100.848 86.316 100.872 86.4 ;
    END
  END rr_w[398]
  PIN rr_w[399]
    DIRECTION INPUT ;
    USE SIGNAL ;
    PORT
      LAYER M5 ;
        RECT  101.088 86.316 101.112 86.4 ;
    END
  END rr_w[399]
  PIN rr_w[39]
    DIRECTION INPUT ;
    USE SIGNAL ;
    PORT
      LAYER M5 ;
        RECT  9.984 86.316 10.008 86.4 ;
    END
  END rr_w[39]
  PIN rr_w[3]
    DIRECTION INPUT ;
    USE SIGNAL ;
    PORT
      LAYER M5 ;
        RECT  0.864 86.316 0.888 86.4 ;
    END
  END rr_w[3]
  PIN rr_w[400]
    DIRECTION INPUT ;
    USE SIGNAL ;
    PORT
      LAYER M5 ;
        RECT  101.376 86.316 101.4 86.4 ;
    END
  END rr_w[400]
  PIN rr_w[401]
    DIRECTION INPUT ;
    USE SIGNAL ;
    PORT
      LAYER M5 ;
        RECT  101.616 86.316 101.64 86.4 ;
    END
  END rr_w[401]
  PIN rr_w[402]
    DIRECTION INPUT ;
    USE SIGNAL ;
    PORT
      LAYER M5 ;
        RECT  101.856 86.316 101.88 86.4 ;
    END
  END rr_w[402]
  PIN rr_w[403]
    DIRECTION INPUT ;
    USE SIGNAL ;
    PORT
      LAYER M5 ;
        RECT  102.144 86.316 102.168 86.4 ;
    END
  END rr_w[403]
  PIN rr_w[404]
    DIRECTION INPUT ;
    USE SIGNAL ;
    PORT
      LAYER M5 ;
        RECT  102.384 86.316 102.408 86.4 ;
    END
  END rr_w[404]
  PIN rr_w[405]
    DIRECTION INPUT ;
    USE SIGNAL ;
    PORT
      LAYER M5 ;
        RECT  102.624 86.316 102.648 86.4 ;
    END
  END rr_w[405]
  PIN rr_w[406]
    DIRECTION INPUT ;
    USE SIGNAL ;
    PORT
      LAYER M5 ;
        RECT  102.864 86.316 102.888 86.4 ;
    END
  END rr_w[406]
  PIN rr_w[407]
    DIRECTION INPUT ;
    USE SIGNAL ;
    PORT
      LAYER M5 ;
        RECT  103.152 86.316 103.176 86.4 ;
    END
  END rr_w[407]
  PIN rr_w[408]
    DIRECTION INPUT ;
    USE SIGNAL ;
    PORT
      LAYER M5 ;
        RECT  103.392 86.316 103.416 86.4 ;
    END
  END rr_w[408]
  PIN rr_w[409]
    DIRECTION INPUT ;
    USE SIGNAL ;
    PORT
      LAYER M5 ;
        RECT  103.632 86.316 103.656 86.4 ;
    END
  END rr_w[409]
  PIN rr_w[40]
    DIRECTION INPUT ;
    USE SIGNAL ;
    PORT
      LAYER M5 ;
        RECT  10.224 86.316 10.248 86.4 ;
    END
  END rr_w[40]
  PIN rr_w[410]
    DIRECTION INPUT ;
    USE SIGNAL ;
    PORT
      LAYER M5 ;
        RECT  103.92 86.316 103.944 86.4 ;
    END
  END rr_w[410]
  PIN rr_w[411]
    DIRECTION INPUT ;
    USE SIGNAL ;
    PORT
      LAYER M5 ;
        RECT  104.16 86.316 104.184 86.4 ;
    END
  END rr_w[411]
  PIN rr_w[412]
    DIRECTION INPUT ;
    USE SIGNAL ;
    PORT
      LAYER M5 ;
        RECT  104.4 86.316 104.424 86.4 ;
    END
  END rr_w[412]
  PIN rr_w[413]
    DIRECTION INPUT ;
    USE SIGNAL ;
    PORT
      LAYER M5 ;
        RECT  104.64 86.316 104.664 86.4 ;
    END
  END rr_w[413]
  PIN rr_w[414]
    DIRECTION INPUT ;
    USE SIGNAL ;
    PORT
      LAYER M5 ;
        RECT  104.928 86.316 104.952 86.4 ;
    END
  END rr_w[414]
  PIN rr_w[415]
    DIRECTION INPUT ;
    USE SIGNAL ;
    PORT
      LAYER M5 ;
        RECT  105.168 86.316 105.192 86.4 ;
    END
  END rr_w[415]
  PIN rr_w[416]
    DIRECTION INPUT ;
    USE SIGNAL ;
    PORT
      LAYER M5 ;
        RECT  105.408 86.316 105.432 86.4 ;
    END
  END rr_w[416]
  PIN rr_w[417]
    DIRECTION INPUT ;
    USE SIGNAL ;
    PORT
      LAYER M5 ;
        RECT  105.648 86.316 105.672 86.4 ;
    END
  END rr_w[417]
  PIN rr_w[418]
    DIRECTION INPUT ;
    USE SIGNAL ;
    PORT
      LAYER M5 ;
        RECT  105.936 86.316 105.96 86.4 ;
    END
  END rr_w[418]
  PIN rr_w[419]
    DIRECTION INPUT ;
    USE SIGNAL ;
    PORT
      LAYER M5 ;
        RECT  106.176 86.316 106.2 86.4 ;
    END
  END rr_w[419]
  PIN rr_w[41]
    DIRECTION INPUT ;
    USE SIGNAL ;
    PORT
      LAYER M5 ;
        RECT  10.512 86.316 10.536 86.4 ;
    END
  END rr_w[41]
  PIN rr_w[420]
    DIRECTION INPUT ;
    USE SIGNAL ;
    PORT
      LAYER M5 ;
        RECT  106.416 86.316 106.44 86.4 ;
    END
  END rr_w[420]
  PIN rr_w[421]
    DIRECTION INPUT ;
    USE SIGNAL ;
    PORT
      LAYER M5 ;
        RECT  106.704 86.316 106.728 86.4 ;
    END
  END rr_w[421]
  PIN rr_w[422]
    DIRECTION INPUT ;
    USE SIGNAL ;
    PORT
      LAYER M5 ;
        RECT  106.944 86.316 106.968 86.4 ;
    END
  END rr_w[422]
  PIN rr_w[423]
    DIRECTION INPUT ;
    USE SIGNAL ;
    PORT
      LAYER M5 ;
        RECT  107.184 86.316 107.208 86.4 ;
    END
  END rr_w[423]
  PIN rr_w[424]
    DIRECTION INPUT ;
    USE SIGNAL ;
    PORT
      LAYER M5 ;
        RECT  107.424 86.316 107.448 86.4 ;
    END
  END rr_w[424]
  PIN rr_w[425]
    DIRECTION INPUT ;
    USE SIGNAL ;
    PORT
      LAYER M5 ;
        RECT  107.712 86.316 107.736 86.4 ;
    END
  END rr_w[425]
  PIN rr_w[426]
    DIRECTION INPUT ;
    USE SIGNAL ;
    PORT
      LAYER M5 ;
        RECT  107.952 86.316 107.976 86.4 ;
    END
  END rr_w[426]
  PIN rr_w[427]
    DIRECTION INPUT ;
    USE SIGNAL ;
    PORT
      LAYER M5 ;
        RECT  108.192 86.316 108.216 86.4 ;
    END
  END rr_w[427]
  PIN rr_w[428]
    DIRECTION INPUT ;
    USE SIGNAL ;
    PORT
      LAYER M5 ;
        RECT  108.432 86.316 108.456 86.4 ;
    END
  END rr_w[428]
  PIN rr_w[429]
    DIRECTION INPUT ;
    USE SIGNAL ;
    PORT
      LAYER M5 ;
        RECT  108.72 86.316 108.744 86.4 ;
    END
  END rr_w[429]
  PIN rr_w[42]
    DIRECTION INPUT ;
    USE SIGNAL ;
    PORT
      LAYER M5 ;
        RECT  10.752 86.316 10.776 86.4 ;
    END
  END rr_w[42]
  PIN rr_w[430]
    DIRECTION INPUT ;
    USE SIGNAL ;
    PORT
      LAYER M5 ;
        RECT  108.96 86.316 108.984 86.4 ;
    END
  END rr_w[430]
  PIN rr_w[431]
    DIRECTION INPUT ;
    USE SIGNAL ;
    PORT
      LAYER M5 ;
        RECT  109.2 86.316 109.224 86.4 ;
    END
  END rr_w[431]
  PIN rr_w[432]
    DIRECTION INPUT ;
    USE SIGNAL ;
    PORT
      LAYER M5 ;
        RECT  109.488 86.316 109.512 86.4 ;
    END
  END rr_w[432]
  PIN rr_w[433]
    DIRECTION INPUT ;
    USE SIGNAL ;
    PORT
      LAYER M5 ;
        RECT  109.728 86.316 109.752 86.4 ;
    END
  END rr_w[433]
  PIN rr_w[434]
    DIRECTION INPUT ;
    USE SIGNAL ;
    PORT
      LAYER M5 ;
        RECT  109.968 86.316 109.992 86.4 ;
    END
  END rr_w[434]
  PIN rr_w[435]
    DIRECTION INPUT ;
    USE SIGNAL ;
    PORT
      LAYER M5 ;
        RECT  110.208 86.316 110.232 86.4 ;
    END
  END rr_w[435]
  PIN rr_w[436]
    DIRECTION INPUT ;
    USE SIGNAL ;
    PORT
      LAYER M5 ;
        RECT  110.496 86.316 110.52 86.4 ;
    END
  END rr_w[436]
  PIN rr_w[437]
    DIRECTION INPUT ;
    USE SIGNAL ;
    PORT
      LAYER M5 ;
        RECT  110.736 86.316 110.76 86.4 ;
    END
  END rr_w[437]
  PIN rr_w[438]
    DIRECTION INPUT ;
    USE SIGNAL ;
    PORT
      LAYER M5 ;
        RECT  110.976 86.316 111 86.4 ;
    END
  END rr_w[438]
  PIN rr_w[439]
    DIRECTION INPUT ;
    USE SIGNAL ;
    PORT
      LAYER M5 ;
        RECT  111.216 86.316 111.24 86.4 ;
    END
  END rr_w[439]
  PIN rr_w[43]
    DIRECTION INPUT ;
    USE SIGNAL ;
    PORT
      LAYER M5 ;
        RECT  10.992 86.316 11.016 86.4 ;
    END
  END rr_w[43]
  PIN rr_w[440]
    DIRECTION INPUT ;
    USE SIGNAL ;
    PORT
      LAYER M5 ;
        RECT  111.504 86.316 111.528 86.4 ;
    END
  END rr_w[440]
  PIN rr_w[441]
    DIRECTION INPUT ;
    USE SIGNAL ;
    PORT
      LAYER M5 ;
        RECT  111.744 86.316 111.768 86.4 ;
    END
  END rr_w[441]
  PIN rr_w[442]
    DIRECTION INPUT ;
    USE SIGNAL ;
    PORT
      LAYER M5 ;
        RECT  111.984 86.316 112.008 86.4 ;
    END
  END rr_w[442]
  PIN rr_w[443]
    DIRECTION INPUT ;
    USE SIGNAL ;
    PORT
      LAYER M5 ;
        RECT  112.272 86.316 112.296 86.4 ;
    END
  END rr_w[443]
  PIN rr_w[444]
    DIRECTION INPUT ;
    USE SIGNAL ;
    PORT
      LAYER M5 ;
        RECT  112.512 86.316 112.536 86.4 ;
    END
  END rr_w[444]
  PIN rr_w[445]
    DIRECTION INPUT ;
    USE SIGNAL ;
    PORT
      LAYER M5 ;
        RECT  112.752 86.316 112.776 86.4 ;
    END
  END rr_w[445]
  PIN rr_w[446]
    DIRECTION INPUT ;
    USE SIGNAL ;
    PORT
      LAYER M5 ;
        RECT  112.992 86.316 113.016 86.4 ;
    END
  END rr_w[446]
  PIN rr_w[447]
    DIRECTION INPUT ;
    USE SIGNAL ;
    PORT
      LAYER M5 ;
        RECT  113.28 86.316 113.304 86.4 ;
    END
  END rr_w[447]
  PIN rr_w[448]
    DIRECTION INPUT ;
    USE SIGNAL ;
    PORT
      LAYER M5 ;
        RECT  113.52 86.316 113.544 86.4 ;
    END
  END rr_w[448]
  PIN rr_w[449]
    DIRECTION INPUT ;
    USE SIGNAL ;
    PORT
      LAYER M5 ;
        RECT  113.76 86.316 113.784 86.4 ;
    END
  END rr_w[449]
  PIN rr_w[44]
    DIRECTION INPUT ;
    USE SIGNAL ;
    PORT
      LAYER M5 ;
        RECT  11.232 86.316 11.256 86.4 ;
    END
  END rr_w[44]
  PIN rr_w[450]
    DIRECTION INPUT ;
    USE SIGNAL ;
    PORT
      LAYER M5 ;
        RECT  114 86.316 114.024 86.4 ;
    END
  END rr_w[450]
  PIN rr_w[451]
    DIRECTION INPUT ;
    USE SIGNAL ;
    PORT
      LAYER M5 ;
        RECT  114.288 86.316 114.312 86.4 ;
    END
  END rr_w[451]
  PIN rr_w[452]
    DIRECTION INPUT ;
    USE SIGNAL ;
    PORT
      LAYER M5 ;
        RECT  114.528 86.316 114.552 86.4 ;
    END
  END rr_w[452]
  PIN rr_w[453]
    DIRECTION INPUT ;
    USE SIGNAL ;
    PORT
      LAYER M5 ;
        RECT  114.768 86.316 114.792 86.4 ;
    END
  END rr_w[453]
  PIN rr_w[454]
    DIRECTION INPUT ;
    USE SIGNAL ;
    PORT
      LAYER M5 ;
        RECT  115.056 86.316 115.08 86.4 ;
    END
  END rr_w[454]
  PIN rr_w[455]
    DIRECTION INPUT ;
    USE SIGNAL ;
    PORT
      LAYER M5 ;
        RECT  115.296 86.316 115.32 86.4 ;
    END
  END rr_w[455]
  PIN rr_w[456]
    DIRECTION INPUT ;
    USE SIGNAL ;
    PORT
      LAYER M5 ;
        RECT  115.536 86.316 115.56 86.4 ;
    END
  END rr_w[456]
  PIN rr_w[457]
    DIRECTION INPUT ;
    USE SIGNAL ;
    PORT
      LAYER M5 ;
        RECT  115.776 86.316 115.8 86.4 ;
    END
  END rr_w[457]
  PIN rr_w[458]
    DIRECTION INPUT ;
    USE SIGNAL ;
    PORT
      LAYER M5 ;
        RECT  116.064 86.316 116.088 86.4 ;
    END
  END rr_w[458]
  PIN rr_w[459]
    DIRECTION INPUT ;
    USE SIGNAL ;
    PORT
      LAYER M5 ;
        RECT  116.304 86.316 116.328 86.4 ;
    END
  END rr_w[459]
  PIN rr_w[45]
    DIRECTION INPUT ;
    USE SIGNAL ;
    PORT
      LAYER M5 ;
        RECT  11.52 86.316 11.544 86.4 ;
    END
  END rr_w[45]
  PIN rr_w[460]
    DIRECTION INPUT ;
    USE SIGNAL ;
    PORT
      LAYER M5 ;
        RECT  116.544 86.316 116.568 86.4 ;
    END
  END rr_w[460]
  PIN rr_w[461]
    DIRECTION INPUT ;
    USE SIGNAL ;
    PORT
      LAYER M5 ;
        RECT  116.784 86.316 116.808 86.4 ;
    END
  END rr_w[461]
  PIN rr_w[462]
    DIRECTION INPUT ;
    USE SIGNAL ;
    PORT
      LAYER M5 ;
        RECT  117.072 86.316 117.096 86.4 ;
    END
  END rr_w[462]
  PIN rr_w[463]
    DIRECTION INPUT ;
    USE SIGNAL ;
    PORT
      LAYER M5 ;
        RECT  117.312 86.316 117.336 86.4 ;
    END
  END rr_w[463]
  PIN rr_w[464]
    DIRECTION INPUT ;
    USE SIGNAL ;
    PORT
      LAYER M5 ;
        RECT  117.552 86.316 117.576 86.4 ;
    END
  END rr_w[464]
  PIN rr_w[465]
    DIRECTION INPUT ;
    USE SIGNAL ;
    PORT
      LAYER M5 ;
        RECT  117.84 86.316 117.864 86.4 ;
    END
  END rr_w[465]
  PIN rr_w[466]
    DIRECTION INPUT ;
    USE SIGNAL ;
    PORT
      LAYER M5 ;
        RECT  118.08 86.316 118.104 86.4 ;
    END
  END rr_w[466]
  PIN rr_w[467]
    DIRECTION INPUT ;
    USE SIGNAL ;
    PORT
      LAYER M5 ;
        RECT  118.32 86.316 118.344 86.4 ;
    END
  END rr_w[467]
  PIN rr_w[468]
    DIRECTION INPUT ;
    USE SIGNAL ;
    PORT
      LAYER M5 ;
        RECT  118.56 86.316 118.584 86.4 ;
    END
  END rr_w[468]
  PIN rr_w[469]
    DIRECTION INPUT ;
    USE SIGNAL ;
    PORT
      LAYER M5 ;
        RECT  118.848 86.316 118.872 86.4 ;
    END
  END rr_w[469]
  PIN rr_w[46]
    DIRECTION INPUT ;
    USE SIGNAL ;
    PORT
      LAYER M5 ;
        RECT  11.76 86.316 11.784 86.4 ;
    END
  END rr_w[46]
  PIN rr_w[470]
    DIRECTION INPUT ;
    USE SIGNAL ;
    PORT
      LAYER M5 ;
        RECT  119.088 86.316 119.112 86.4 ;
    END
  END rr_w[470]
  PIN rr_w[471]
    DIRECTION INPUT ;
    USE SIGNAL ;
    PORT
      LAYER M5 ;
        RECT  119.328 86.316 119.352 86.4 ;
    END
  END rr_w[471]
  PIN rr_w[472]
    DIRECTION INPUT ;
    USE SIGNAL ;
    PORT
      LAYER M5 ;
        RECT  119.568 86.316 119.592 86.4 ;
    END
  END rr_w[472]
  PIN rr_w[473]
    DIRECTION INPUT ;
    USE SIGNAL ;
    PORT
      LAYER M5 ;
        RECT  119.856 86.316 119.88 86.4 ;
    END
  END rr_w[473]
  PIN rr_w[474]
    DIRECTION INPUT ;
    USE SIGNAL ;
    PORT
      LAYER M5 ;
        RECT  120.096 86.316 120.12 86.4 ;
    END
  END rr_w[474]
  PIN rr_w[475]
    DIRECTION INPUT ;
    USE SIGNAL ;
    PORT
      LAYER M5 ;
        RECT  120.336 86.316 120.36 86.4 ;
    END
  END rr_w[475]
  PIN rr_w[476]
    DIRECTION INPUT ;
    USE SIGNAL ;
    PORT
      LAYER M5 ;
        RECT  120.624 86.316 120.648 86.4 ;
    END
  END rr_w[476]
  PIN rr_w[477]
    DIRECTION INPUT ;
    USE SIGNAL ;
    PORT
      LAYER M5 ;
        RECT  120.864 86.316 120.888 86.4 ;
    END
  END rr_w[477]
  PIN rr_w[478]
    DIRECTION INPUT ;
    USE SIGNAL ;
    PORT
      LAYER M5 ;
        RECT  121.104 86.316 121.128 86.4 ;
    END
  END rr_w[478]
  PIN rr_w[479]
    DIRECTION INPUT ;
    USE SIGNAL ;
    PORT
      LAYER M5 ;
        RECT  121.344 86.316 121.368 86.4 ;
    END
  END rr_w[479]
  PIN rr_w[47]
    DIRECTION INPUT ;
    USE SIGNAL ;
    PORT
      LAYER M5 ;
        RECT  12 86.316 12.024 86.4 ;
    END
  END rr_w[47]
  PIN rr_w[480]
    DIRECTION INPUT ;
    USE SIGNAL ;
    PORT
      LAYER M5 ;
        RECT  121.632 86.316 121.656 86.4 ;
    END
  END rr_w[480]
  PIN rr_w[481]
    DIRECTION INPUT ;
    USE SIGNAL ;
    PORT
      LAYER M5 ;
        RECT  121.872 86.316 121.896 86.4 ;
    END
  END rr_w[481]
  PIN rr_w[482]
    DIRECTION INPUT ;
    USE SIGNAL ;
    PORT
      LAYER M5 ;
        RECT  122.112 86.316 122.136 86.4 ;
    END
  END rr_w[482]
  PIN rr_w[483]
    DIRECTION INPUT ;
    USE SIGNAL ;
    PORT
      LAYER M5 ;
        RECT  122.352 86.316 122.376 86.4 ;
    END
  END rr_w[483]
  PIN rr_w[484]
    DIRECTION INPUT ;
    USE SIGNAL ;
    PORT
      LAYER M5 ;
        RECT  122.64 86.316 122.664 86.4 ;
    END
  END rr_w[484]
  PIN rr_w[485]
    DIRECTION INPUT ;
    USE SIGNAL ;
    PORT
      LAYER M5 ;
        RECT  122.88 86.316 122.904 86.4 ;
    END
  END rr_w[485]
  PIN rr_w[486]
    DIRECTION INPUT ;
    USE SIGNAL ;
    PORT
      LAYER M5 ;
        RECT  123.12 86.316 123.144 86.4 ;
    END
  END rr_w[486]
  PIN rr_w[487]
    DIRECTION INPUT ;
    USE SIGNAL ;
    PORT
      LAYER M5 ;
        RECT  123.408 86.316 123.432 86.4 ;
    END
  END rr_w[487]
  PIN rr_w[488]
    DIRECTION INPUT ;
    USE SIGNAL ;
    PORT
      LAYER M5 ;
        RECT  123.648 86.316 123.672 86.4 ;
    END
  END rr_w[488]
  PIN rr_w[489]
    DIRECTION INPUT ;
    USE SIGNAL ;
    PORT
      LAYER M5 ;
        RECT  123.888 86.316 123.912 86.4 ;
    END
  END rr_w[489]
  PIN rr_w[48]
    DIRECTION INPUT ;
    USE SIGNAL ;
    PORT
      LAYER M5 ;
        RECT  12.288 86.316 12.312 86.4 ;
    END
  END rr_w[48]
  PIN rr_w[490]
    DIRECTION INPUT ;
    USE SIGNAL ;
    PORT
      LAYER M5 ;
        RECT  124.128 86.316 124.152 86.4 ;
    END
  END rr_w[490]
  PIN rr_w[491]
    DIRECTION INPUT ;
    USE SIGNAL ;
    PORT
      LAYER M5 ;
        RECT  124.416 86.316 124.44 86.4 ;
    END
  END rr_w[491]
  PIN rr_w[492]
    DIRECTION INPUT ;
    USE SIGNAL ;
    PORT
      LAYER M5 ;
        RECT  124.656 86.316 124.68 86.4 ;
    END
  END rr_w[492]
  PIN rr_w[493]
    DIRECTION INPUT ;
    USE SIGNAL ;
    PORT
      LAYER M5 ;
        RECT  124.896 86.316 124.92 86.4 ;
    END
  END rr_w[493]
  PIN rr_w[494]
    DIRECTION INPUT ;
    USE SIGNAL ;
    PORT
      LAYER M5 ;
        RECT  125.136 86.316 125.16 86.4 ;
    END
  END rr_w[494]
  PIN rr_w[495]
    DIRECTION INPUT ;
    USE SIGNAL ;
    PORT
      LAYER M5 ;
        RECT  125.424 86.316 125.448 86.4 ;
    END
  END rr_w[495]
  PIN rr_w[496]
    DIRECTION INPUT ;
    USE SIGNAL ;
    PORT
      LAYER M5 ;
        RECT  125.664 86.316 125.688 86.4 ;
    END
  END rr_w[496]
  PIN rr_w[497]
    DIRECTION INPUT ;
    USE SIGNAL ;
    PORT
      LAYER M5 ;
        RECT  125.904 86.316 125.928 86.4 ;
    END
  END rr_w[497]
  PIN rr_w[498]
    DIRECTION INPUT ;
    USE SIGNAL ;
    PORT
      LAYER M5 ;
        RECT  126.192 86.316 126.216 86.4 ;
    END
  END rr_w[498]
  PIN rr_w[499]
    DIRECTION INPUT ;
    USE SIGNAL ;
    PORT
      LAYER M5 ;
        RECT  126.432 86.316 126.456 86.4 ;
    END
  END rr_w[499]
  PIN rr_w[49]
    DIRECTION INPUT ;
    USE SIGNAL ;
    PORT
      LAYER M5 ;
        RECT  12.528 86.316 12.552 86.4 ;
    END
  END rr_w[49]
  PIN rr_w[4]
    DIRECTION INPUT ;
    USE SIGNAL ;
    PORT
      LAYER M5 ;
        RECT  1.104 86.316 1.128 86.4 ;
    END
  END rr_w[4]
  PIN rr_w[500]
    DIRECTION INPUT ;
    USE SIGNAL ;
    PORT
      LAYER M5 ;
        RECT  126.672 86.316 126.696 86.4 ;
    END
  END rr_w[500]
  PIN rr_w[501]
    DIRECTION INPUT ;
    USE SIGNAL ;
    PORT
      LAYER M5 ;
        RECT  126.912 86.316 126.936 86.4 ;
    END
  END rr_w[501]
  PIN rr_w[502]
    DIRECTION INPUT ;
    USE SIGNAL ;
    PORT
      LAYER M5 ;
        RECT  127.2 86.316 127.224 86.4 ;
    END
  END rr_w[502]
  PIN rr_w[503]
    DIRECTION INPUT ;
    USE SIGNAL ;
    PORT
      LAYER M5 ;
        RECT  127.44 86.316 127.464 86.4 ;
    END
  END rr_w[503]
  PIN rr_w[504]
    DIRECTION INPUT ;
    USE SIGNAL ;
    PORT
      LAYER M5 ;
        RECT  127.68 86.316 127.704 86.4 ;
    END
  END rr_w[504]
  PIN rr_w[505]
    DIRECTION INPUT ;
    USE SIGNAL ;
    PORT
      LAYER M5 ;
        RECT  127.92 86.316 127.944 86.4 ;
    END
  END rr_w[505]
  PIN rr_w[506]
    DIRECTION INPUT ;
    USE SIGNAL ;
    PORT
      LAYER M5 ;
        RECT  128.208 86.316 128.232 86.4 ;
    END
  END rr_w[506]
  PIN rr_w[507]
    DIRECTION INPUT ;
    USE SIGNAL ;
    PORT
      LAYER M5 ;
        RECT  128.448 86.316 128.472 86.4 ;
    END
  END rr_w[507]
  PIN rr_w[508]
    DIRECTION INPUT ;
    USE SIGNAL ;
    PORT
      LAYER M5 ;
        RECT  128.688 86.316 128.712 86.4 ;
    END
  END rr_w[508]
  PIN rr_w[509]
    DIRECTION INPUT ;
    USE SIGNAL ;
    PORT
      LAYER M5 ;
        RECT  128.976 86.316 129 86.4 ;
    END
  END rr_w[509]
  PIN rr_w[50]
    DIRECTION INPUT ;
    USE SIGNAL ;
    PORT
      LAYER M5 ;
        RECT  12.768 86.316 12.792 86.4 ;
    END
  END rr_w[50]
  PIN rr_w[510]
    DIRECTION INPUT ;
    USE SIGNAL ;
    PORT
      LAYER M5 ;
        RECT  129.216 86.316 129.24 86.4 ;
    END
  END rr_w[510]
  PIN rr_w[511]
    DIRECTION INPUT ;
    USE SIGNAL ;
    PORT
      LAYER M5 ;
        RECT  129.456 86.316 129.48 86.4 ;
    END
  END rr_w[511]
  PIN rr_w[51]
    DIRECTION INPUT ;
    USE SIGNAL ;
    PORT
      LAYER M5 ;
        RECT  13.008 86.316 13.032 86.4 ;
    END
  END rr_w[51]
  PIN rr_w[52]
    DIRECTION INPUT ;
    USE SIGNAL ;
    PORT
      LAYER M5 ;
        RECT  13.296 86.316 13.32 86.4 ;
    END
  END rr_w[52]
  PIN rr_w[53]
    DIRECTION INPUT ;
    USE SIGNAL ;
    PORT
      LAYER M5 ;
        RECT  13.536 86.316 13.56 86.4 ;
    END
  END rr_w[53]
  PIN rr_w[54]
    DIRECTION INPUT ;
    USE SIGNAL ;
    PORT
      LAYER M5 ;
        RECT  13.776 86.316 13.8 86.4 ;
    END
  END rr_w[54]
  PIN rr_w[55]
    DIRECTION INPUT ;
    USE SIGNAL ;
    PORT
      LAYER M5 ;
        RECT  14.016 86.316 14.04 86.4 ;
    END
  END rr_w[55]
  PIN rr_w[56]
    DIRECTION INPUT ;
    USE SIGNAL ;
    PORT
      LAYER M5 ;
        RECT  14.304 86.316 14.328 86.4 ;
    END
  END rr_w[56]
  PIN rr_w[57]
    DIRECTION INPUT ;
    USE SIGNAL ;
    PORT
      LAYER M5 ;
        RECT  14.544 86.316 14.568 86.4 ;
    END
  END rr_w[57]
  PIN rr_w[58]
    DIRECTION INPUT ;
    USE SIGNAL ;
    PORT
      LAYER M5 ;
        RECT  14.784 86.316 14.808 86.4 ;
    END
  END rr_w[58]
  PIN rr_w[59]
    DIRECTION INPUT ;
    USE SIGNAL ;
    PORT
      LAYER M5 ;
        RECT  15.072 86.316 15.096 86.4 ;
    END
  END rr_w[59]
  PIN rr_w[5]
    DIRECTION INPUT ;
    USE SIGNAL ;
    PORT
      LAYER M5 ;
        RECT  1.392 86.316 1.416 86.4 ;
    END
  END rr_w[5]
  PIN rr_w[60]
    DIRECTION INPUT ;
    USE SIGNAL ;
    PORT
      LAYER M5 ;
        RECT  15.312 86.316 15.336 86.4 ;
    END
  END rr_w[60]
  PIN rr_w[61]
    DIRECTION INPUT ;
    USE SIGNAL ;
    PORT
      LAYER M5 ;
        RECT  15.552 86.316 15.576 86.4 ;
    END
  END rr_w[61]
  PIN rr_w[62]
    DIRECTION INPUT ;
    USE SIGNAL ;
    PORT
      LAYER M5 ;
        RECT  15.792 86.316 15.816 86.4 ;
    END
  END rr_w[62]
  PIN rr_w[63]
    DIRECTION INPUT ;
    USE SIGNAL ;
    PORT
      LAYER M5 ;
        RECT  16.08 86.316 16.104 86.4 ;
    END
  END rr_w[63]
  PIN rr_w[64]
    DIRECTION INPUT ;
    USE SIGNAL ;
    PORT
      LAYER M5 ;
        RECT  16.32 86.316 16.344 86.4 ;
    END
  END rr_w[64]
  PIN rr_w[65]
    DIRECTION INPUT ;
    USE SIGNAL ;
    PORT
      LAYER M5 ;
        RECT  16.56 86.316 16.584 86.4 ;
    END
  END rr_w[65]
  PIN rr_w[66]
    DIRECTION INPUT ;
    USE SIGNAL ;
    PORT
      LAYER M5 ;
        RECT  16.8 86.316 16.824 86.4 ;
    END
  END rr_w[66]
  PIN rr_w[67]
    DIRECTION INPUT ;
    USE SIGNAL ;
    PORT
      LAYER M5 ;
        RECT  17.088 86.316 17.112 86.4 ;
    END
  END rr_w[67]
  PIN rr_w[68]
    DIRECTION INPUT ;
    USE SIGNAL ;
    PORT
      LAYER M5 ;
        RECT  17.328 86.316 17.352 86.4 ;
    END
  END rr_w[68]
  PIN rr_w[69]
    DIRECTION INPUT ;
    USE SIGNAL ;
    PORT
      LAYER M5 ;
        RECT  17.568 86.316 17.592 86.4 ;
    END
  END rr_w[69]
  PIN rr_w[6]
    DIRECTION INPUT ;
    USE SIGNAL ;
    PORT
      LAYER M5 ;
        RECT  1.632 86.316 1.656 86.4 ;
    END
  END rr_w[6]
  PIN rr_w[70]
    DIRECTION INPUT ;
    USE SIGNAL ;
    PORT
      LAYER M5 ;
        RECT  17.856 86.316 17.88 86.4 ;
    END
  END rr_w[70]
  PIN rr_w[71]
    DIRECTION INPUT ;
    USE SIGNAL ;
    PORT
      LAYER M5 ;
        RECT  18.096 86.316 18.12 86.4 ;
    END
  END rr_w[71]
  PIN rr_w[72]
    DIRECTION INPUT ;
    USE SIGNAL ;
    PORT
      LAYER M5 ;
        RECT  18.336 86.316 18.36 86.4 ;
    END
  END rr_w[72]
  PIN rr_w[73]
    DIRECTION INPUT ;
    USE SIGNAL ;
    PORT
      LAYER M5 ;
        RECT  18.576 86.316 18.6 86.4 ;
    END
  END rr_w[73]
  PIN rr_w[74]
    DIRECTION INPUT ;
    USE SIGNAL ;
    PORT
      LAYER M5 ;
        RECT  18.864 86.316 18.888 86.4 ;
    END
  END rr_w[74]
  PIN rr_w[75]
    DIRECTION INPUT ;
    USE SIGNAL ;
    PORT
      LAYER M5 ;
        RECT  19.104 86.316 19.128 86.4 ;
    END
  END rr_w[75]
  PIN rr_w[76]
    DIRECTION INPUT ;
    USE SIGNAL ;
    PORT
      LAYER M5 ;
        RECT  19.344 86.316 19.368 86.4 ;
    END
  END rr_w[76]
  PIN rr_w[77]
    DIRECTION INPUT ;
    USE SIGNAL ;
    PORT
      LAYER M5 ;
        RECT  19.584 86.316 19.608 86.4 ;
    END
  END rr_w[77]
  PIN rr_w[78]
    DIRECTION INPUT ;
    USE SIGNAL ;
    PORT
      LAYER M5 ;
        RECT  19.872 86.316 19.896 86.4 ;
    END
  END rr_w[78]
  PIN rr_w[79]
    DIRECTION INPUT ;
    USE SIGNAL ;
    PORT
      LAYER M5 ;
        RECT  20.112 86.316 20.136 86.4 ;
    END
  END rr_w[79]
  PIN rr_w[7]
    DIRECTION INPUT ;
    USE SIGNAL ;
    PORT
      LAYER M5 ;
        RECT  1.872 86.316 1.896 86.4 ;
    END
  END rr_w[7]
  PIN rr_w[80]
    DIRECTION INPUT ;
    USE SIGNAL ;
    PORT
      LAYER M5 ;
        RECT  20.352 86.316 20.376 86.4 ;
    END
  END rr_w[80]
  PIN rr_w[81]
    DIRECTION INPUT ;
    USE SIGNAL ;
    PORT
      LAYER M5 ;
        RECT  20.64 86.316 20.664 86.4 ;
    END
  END rr_w[81]
  PIN rr_w[82]
    DIRECTION INPUT ;
    USE SIGNAL ;
    PORT
      LAYER M5 ;
        RECT  20.88 86.316 20.904 86.4 ;
    END
  END rr_w[82]
  PIN rr_w[83]
    DIRECTION INPUT ;
    USE SIGNAL ;
    PORT
      LAYER M5 ;
        RECT  21.12 86.316 21.144 86.4 ;
    END
  END rr_w[83]
  PIN rr_w[84]
    DIRECTION INPUT ;
    USE SIGNAL ;
    PORT
      LAYER M5 ;
        RECT  21.36 86.316 21.384 86.4 ;
    END
  END rr_w[84]
  PIN rr_w[85]
    DIRECTION INPUT ;
    USE SIGNAL ;
    PORT
      LAYER M5 ;
        RECT  21.648 86.316 21.672 86.4 ;
    END
  END rr_w[85]
  PIN rr_w[86]
    DIRECTION INPUT ;
    USE SIGNAL ;
    PORT
      LAYER M5 ;
        RECT  21.888 86.316 21.912 86.4 ;
    END
  END rr_w[86]
  PIN rr_w[87]
    DIRECTION INPUT ;
    USE SIGNAL ;
    PORT
      LAYER M5 ;
        RECT  22.128 86.316 22.152 86.4 ;
    END
  END rr_w[87]
  PIN rr_w[88]
    DIRECTION INPUT ;
    USE SIGNAL ;
    PORT
      LAYER M5 ;
        RECT  22.368 86.316 22.392 86.4 ;
    END
  END rr_w[88]
  PIN rr_w[89]
    DIRECTION INPUT ;
    USE SIGNAL ;
    PORT
      LAYER M5 ;
        RECT  22.656 86.316 22.68 86.4 ;
    END
  END rr_w[89]
  PIN rr_w[8]
    DIRECTION INPUT ;
    USE SIGNAL ;
    PORT
      LAYER M5 ;
        RECT  2.16 86.316 2.184 86.4 ;
    END
  END rr_w[8]
  PIN rr_w[90]
    DIRECTION INPUT ;
    USE SIGNAL ;
    PORT
      LAYER M5 ;
        RECT  22.896 86.316 22.92 86.4 ;
    END
  END rr_w[90]
  PIN rr_w[91]
    DIRECTION INPUT ;
    USE SIGNAL ;
    PORT
      LAYER M5 ;
        RECT  23.136 86.316 23.16 86.4 ;
    END
  END rr_w[91]
  PIN rr_w[92]
    DIRECTION INPUT ;
    USE SIGNAL ;
    PORT
      LAYER M5 ;
        RECT  23.424 86.316 23.448 86.4 ;
    END
  END rr_w[92]
  PIN rr_w[93]
    DIRECTION INPUT ;
    USE SIGNAL ;
    PORT
      LAYER M5 ;
        RECT  23.664 86.316 23.688 86.4 ;
    END
  END rr_w[93]
  PIN rr_w[94]
    DIRECTION INPUT ;
    USE SIGNAL ;
    PORT
      LAYER M5 ;
        RECT  23.904 86.316 23.928 86.4 ;
    END
  END rr_w[94]
  PIN rr_w[95]
    DIRECTION INPUT ;
    USE SIGNAL ;
    PORT
      LAYER M5 ;
        RECT  24.144 86.316 24.168 86.4 ;
    END
  END rr_w[95]
  PIN rr_w[96]
    DIRECTION INPUT ;
    USE SIGNAL ;
    PORT
      LAYER M5 ;
        RECT  24.432 86.316 24.456 86.4 ;
    END
  END rr_w[96]
  PIN rr_w[97]
    DIRECTION INPUT ;
    USE SIGNAL ;
    PORT
      LAYER M5 ;
        RECT  24.672 86.316 24.696 86.4 ;
    END
  END rr_w[97]
  PIN rr_w[98]
    DIRECTION INPUT ;
    USE SIGNAL ;
    PORT
      LAYER M5 ;
        RECT  24.912 86.316 24.936 86.4 ;
    END
  END rr_w[98]
  PIN rr_w[99]
    DIRECTION INPUT ;
    USE SIGNAL ;
    PORT
      LAYER M5 ;
        RECT  25.152 86.316 25.176 86.4 ;
    END
  END rr_w[99]
  PIN rr_w[9]
    DIRECTION INPUT ;
    USE SIGNAL ;
    PORT
      LAYER M5 ;
        RECT  2.4 86.316 2.424 86.4 ;
    END
  END rr_w[9]
  PIN rsel[0]
    DIRECTION INPUT ;
    USE SIGNAL ;
    PORT
      LAYER M4 ;
        RECT  0 44.496 0.084 44.52 ;
    END
    PORT
      LAYER M4 ;
        RECT  0.06 44.496 2.408 44.52 ;
    END
  END rsel[0]
  PIN rsel[1]
    DIRECTION INPUT ;
    USE SIGNAL ;
    PORT
      LAYER M4 ;
        RECT  0 45.504 0.084 45.528 ;
    END
    PORT
      LAYER M4 ;
        RECT  0.06 45.504 2.408 45.528 ;
    END
  END rsel[1]
  PIN rsel[2]
    DIRECTION INPUT ;
    USE SIGNAL ;
    PORT
      LAYER M4 ;
        RECT  0 46.512 0.084 46.536 ;
    END
    PORT
      LAYER M4 ;
        RECT  0.06 46.512 2.408 46.536 ;
    END
  END rsel[2]
  PIN VSS
    DIRECTION INOUT ;
    USE GROUND ;
    PORT
      LAYER M5 ;
        RECT  126.6 2.137 126.72 84.263 ;
        RECT  121.2 2.137 121.32 84.263 ;
        RECT  115.8 2.137 115.92 84.263 ;
        RECT  110.4 2.137 110.52 84.263 ;
        RECT  105 2.137 105.12 84.263 ;
        RECT  99.6 2.137 99.72 84.263 ;
        RECT  94.2 2.137 94.32 84.263 ;
        RECT  88.8 2.137 88.92 84.263 ;
        RECT  83.4 2.137 83.52 84.263 ;
        RECT  78 2.137 78.12 84.263 ;
        RECT  72.6 2.137 72.72 84.263 ;
        RECT  67.2 2.137 67.32 84.263 ;
        RECT  61.8 2.137 61.92 84.263 ;
        RECT  56.4 2.137 56.52 84.263 ;
        RECT  51 2.137 51.12 84.263 ;
        RECT  45.6 2.137 45.72 84.263 ;
        RECT  40.2 2.137 40.32 84.263 ;
        RECT  34.8 2.137 34.92 84.263 ;
        RECT  29.4 2.137 29.52 84.263 ;
        RECT  24 2.137 24.12 84.263 ;
        RECT  18.6 2.137 18.72 84.263 ;
        RECT  13.2 2.137 13.32 84.263 ;
        RECT  7.8 2.137 7.92 84.263 ;
        RECT  2.4 2.137 2.52 84.263 ;
    END
  END VSS
  PIN VDD
    DIRECTION INOUT ;
    USE POWER ;
    PORT
      LAYER M5 ;
        RECT  126.792 2.151 126.912 84.249 ;
        RECT  121.392 2.151 121.512 84.249 ;
        RECT  115.992 2.151 116.112 84.249 ;
        RECT  110.592 2.151 110.712 84.249 ;
        RECT  105.192 2.151 105.312 84.249 ;
        RECT  99.792 2.151 99.912 84.249 ;
        RECT  94.392 2.151 94.512 84.249 ;
        RECT  88.992 2.151 89.112 84.249 ;
        RECT  83.592 2.151 83.712 84.249 ;
        RECT  78.192 2.151 78.312 84.249 ;
        RECT  72.792 2.151 72.912 84.249 ;
        RECT  67.392 2.151 67.512 84.249 ;
        RECT  61.992 2.151 62.112 84.249 ;
        RECT  56.592 2.151 56.712 84.249 ;
        RECT  51.192 2.151 51.312 84.249 ;
        RECT  45.792 2.151 45.912 84.249 ;
        RECT  40.392 2.151 40.512 84.249 ;
        RECT  34.992 2.151 35.112 84.249 ;
        RECT  29.592 2.151 29.712 84.249 ;
        RECT  24.192 2.151 24.312 84.249 ;
        RECT  18.792 2.151 18.912 84.249 ;
        RECT  13.392 2.151 13.512 84.249 ;
        RECT  7.992 2.151 8.112 84.249 ;
        RECT  2.592 2.151 2.712 84.249 ;
    END
  END VDD
  # OT_OBS_CLOSED layer=M5 d_um=1.536 added=240
  OBS
    LAYER RVTN ;
     RECT  2.16 2.16 127.44 2.295 ;
     RECT  2.16 2.565 127.44 2.835 ;
     RECT  2.16 3.105 127.44 3.375 ;
     RECT  2.16 3.645 127.44 3.915 ;
     RECT  2.16 4.185 127.44 4.455 ;
     RECT  2.16 4.725 127.44 4.995 ;
     RECT  2.16 5.265 127.44 5.535 ;
     RECT  2.16 5.805 127.44 6.075 ;
     RECT  2.16 6.345 127.44 6.615 ;
     RECT  2.16 6.885 127.44 7.155 ;
     RECT  2.16 7.425 127.44 7.695 ;
     RECT  2.16 7.965 127.44 8.235 ;
     RECT  2.16 8.505 127.44 8.775 ;
     RECT  2.16 9.045 127.44 9.315 ;
     RECT  2.16 9.585 127.44 9.855 ;
     RECT  2.16 10.125 127.44 10.395 ;
     RECT  2.16 10.665 127.44 10.935 ;
     RECT  2.16 11.205 127.44 11.475 ;
     RECT  2.16 11.745 127.44 12.015 ;
     RECT  2.16 12.285 127.44 12.555 ;
     RECT  2.16 12.825 127.44 13.095 ;
     RECT  2.16 13.365 127.44 13.635 ;
     RECT  2.16 13.905 127.44 14.175 ;
     RECT  2.16 14.445 127.44 14.715 ;
     RECT  2.16 14.985 127.44 15.255 ;
     RECT  2.16 15.525 127.44 15.795 ;
     RECT  2.16 16.065 127.44 16.335 ;
     RECT  2.16 16.605 127.44 16.875 ;
     RECT  2.16 17.145 127.44 17.415 ;
     RECT  2.16 17.685 127.44 17.955 ;
     RECT  2.16 18.225 127.44 18.495 ;
     RECT  2.16 18.765 127.44 19.035 ;
     RECT  2.16 19.305 127.44 19.575 ;
     RECT  2.16 19.845 127.44 20.115 ;
     RECT  2.16 20.385 127.44 20.655 ;
     RECT  2.16 20.925 127.44 21.195 ;
     RECT  2.16 21.465 127.44 21.735 ;
     RECT  2.16 22.005 127.44 22.275 ;
     RECT  2.16 22.545 127.44 22.815 ;
     RECT  2.16 23.085 127.44 23.355 ;
     RECT  2.16 23.625 127.44 23.895 ;
     RECT  2.16 24.165 127.44 24.435 ;
     RECT  2.16 24.705 127.44 24.975 ;
     RECT  2.16 25.245 127.44 25.515 ;
     RECT  2.16 25.785 127.44 26.055 ;
     RECT  2.16 26.325 127.44 26.595 ;
     RECT  2.16 26.865 127.44 27.135 ;
     RECT  2.16 27.405 127.44 27.675 ;
     RECT  2.16 27.945 127.44 28.215 ;
     RECT  2.16 28.485 127.44 28.755 ;
     RECT  2.16 29.025 127.44 29.295 ;
     RECT  2.16 29.565 127.44 29.835 ;
     RECT  2.16 30.105 127.44 30.375 ;
     RECT  2.16 30.645 127.44 30.915 ;
     RECT  2.16 31.185 127.44 31.455 ;
     RECT  2.16 31.725 127.44 31.995 ;
     RECT  2.16 32.265 127.44 32.535 ;
     RECT  2.16 32.805 127.44 33.075 ;
     RECT  2.16 33.345 127.44 33.615 ;
     RECT  2.16 33.885 127.44 34.155 ;
     RECT  2.16 34.425 127.44 34.695 ;
     RECT  2.16 34.965 127.44 35.235 ;
     RECT  2.16 35.505 127.44 35.775 ;
     RECT  2.16 36.045 127.44 36.315 ;
     RECT  2.16 36.585 127.44 36.855 ;
     RECT  2.16 37.125 127.44 37.395 ;
     RECT  2.16 37.665 127.44 37.935 ;
     RECT  2.16 38.205 127.44 38.475 ;
     RECT  2.16 38.745 127.44 39.015 ;
     RECT  2.16 39.285 127.44 39.555 ;
     RECT  2.16 39.825 127.44 40.095 ;
     RECT  2.16 40.365 127.44 40.635 ;
     RECT  2.16 40.905 127.44 41.175 ;
     RECT  2.16 41.445 127.44 41.715 ;
     RECT  2.16 41.985 127.44 42.255 ;
     RECT  2.16 42.525 127.44 42.795 ;
     RECT  2.16 43.065 127.44 43.335 ;
     RECT  2.16 43.605 127.44 43.875 ;
     RECT  2.16 44.145 127.44 44.415 ;
     RECT  2.16 44.685 127.44 44.955 ;
     RECT  2.16 45.225 127.44 45.495 ;
     RECT  2.16 45.765 127.44 46.035 ;
     RECT  2.16 46.305 127.44 46.575 ;
     RECT  2.16 46.845 127.44 47.115 ;
     RECT  2.16 47.385 127.44 47.655 ;
     RECT  2.16 47.925 127.44 48.195 ;
     RECT  2.16 48.465 127.44 48.735 ;
     RECT  2.16 49.005 127.44 49.275 ;
     RECT  2.16 49.545 127.44 49.815 ;
     RECT  2.16 50.085 127.44 50.355 ;
     RECT  2.16 50.625 127.44 50.895 ;
     RECT  2.16 51.165 127.44 51.435 ;
     RECT  2.16 51.705 127.44 51.975 ;
     RECT  2.16 52.245 127.44 52.515 ;
     RECT  2.16 52.785 127.44 53.055 ;
     RECT  2.16 53.325 127.44 53.595 ;
     RECT  2.16 53.865 127.44 54.135 ;
     RECT  2.16 54.405 127.44 54.675 ;
     RECT  2.16 54.945 127.44 55.215 ;
     RECT  2.16 55.485 127.44 55.755 ;
     RECT  2.16 56.025 127.44 56.295 ;
     RECT  2.16 56.565 127.44 56.835 ;
     RECT  2.16 57.105 127.44 57.375 ;
     RECT  2.16 57.645 127.44 57.915 ;
     RECT  2.16 58.185 127.44 58.455 ;
     RECT  2.16 58.725 127.44 58.995 ;
     RECT  2.16 59.265 127.44 59.535 ;
     RECT  2.16 59.805 127.44 60.075 ;
     RECT  2.16 60.345 127.44 60.615 ;
     RECT  2.16 60.885 127.44 61.155 ;
     RECT  2.16 61.425 127.44 61.695 ;
     RECT  2.16 61.965 127.44 62.235 ;
     RECT  2.16 62.505 127.44 62.775 ;
     RECT  2.16 63.045 127.44 63.315 ;
     RECT  2.16 63.585 127.44 63.855 ;
     RECT  2.16 64.125 127.44 64.395 ;
     RECT  2.16 64.665 127.44 64.935 ;
     RECT  2.16 65.205 127.44 65.475 ;
     RECT  2.16 65.745 127.44 66.015 ;
     RECT  2.16 66.285 127.44 66.555 ;
     RECT  2.16 66.825 127.44 67.095 ;
     RECT  2.16 67.365 127.44 67.635 ;
     RECT  2.16 67.905 127.44 68.175 ;
     RECT  2.16 68.445 127.44 68.715 ;
     RECT  2.16 68.985 127.44 69.255 ;
     RECT  2.16 69.525 127.44 69.795 ;
     RECT  2.16 70.065 127.44 70.335 ;
     RECT  2.16 70.605 127.44 70.875 ;
     RECT  2.16 71.145 127.44 71.415 ;
     RECT  2.16 71.685 127.44 71.955 ;
     RECT  2.16 72.225 127.44 72.495 ;
     RECT  2.16 72.765 127.44 73.035 ;
     RECT  2.16 73.305 127.44 73.575 ;
     RECT  2.16 73.845 127.44 74.115 ;
     RECT  2.16 74.385 127.44 74.655 ;
     RECT  2.16 74.925 127.44 75.195 ;
     RECT  2.16 75.465 127.44 75.735 ;
     RECT  2.16 76.005 127.44 76.275 ;
     RECT  2.16 76.545 127.44 76.815 ;
     RECT  2.16 77.085 127.44 77.355 ;
     RECT  2.16 77.625 127.44 77.895 ;
     RECT  2.16 78.165 127.44 78.435 ;
     RECT  2.16 78.705 127.44 78.975 ;
     RECT  2.16 79.245 127.44 79.515 ;
     RECT  2.16 79.785 127.44 80.055 ;
     RECT  2.16 80.325 127.44 80.595 ;
     RECT  2.16 80.865 127.44 81.135 ;
     RECT  2.16 81.405 127.44 81.675 ;
     RECT  2.16 81.945 127.44 82.215 ;
     RECT  2.16 82.485 127.44 82.755 ;
     RECT  2.16 83.025 127.44 83.295 ;
     RECT  2.16 83.565 127.44 83.835 ;
     RECT  2.16 84.105 127.44 84.24 ;
    LAYER RVTP ;
     RECT  2.16 2.295 127.44 2.565 ;
     RECT  2.16 2.835 127.44 3.105 ;
     RECT  2.16 3.375 127.44 3.645 ;
     RECT  2.16 3.915 127.44 4.185 ;
     RECT  2.16 4.455 127.44 4.725 ;
     RECT  2.16 4.995 127.44 5.265 ;
     RECT  2.16 5.535 127.44 5.805 ;
     RECT  2.16 6.075 127.44 6.345 ;
     RECT  2.16 6.615 127.44 6.885 ;
     RECT  2.16 7.155 127.44 7.425 ;
     RECT  2.16 7.695 127.44 7.965 ;
     RECT  2.16 8.235 127.44 8.505 ;
     RECT  2.16 8.775 127.44 9.045 ;
     RECT  2.16 9.315 127.44 9.585 ;
     RECT  2.16 9.855 127.44 10.125 ;
     RECT  2.16 10.395 127.44 10.665 ;
     RECT  2.16 10.935 127.44 11.205 ;
     RECT  2.16 11.475 127.44 11.745 ;
     RECT  2.16 12.015 127.44 12.285 ;
     RECT  2.16 12.555 127.44 12.825 ;
     RECT  2.16 13.095 127.44 13.365 ;
     RECT  2.16 13.635 127.44 13.905 ;
     RECT  2.16 14.175 127.44 14.445 ;
     RECT  2.16 14.715 127.44 14.985 ;
     RECT  2.16 15.255 127.44 15.525 ;
     RECT  2.16 15.795 127.44 16.065 ;
     RECT  2.16 16.335 127.44 16.605 ;
     RECT  2.16 16.875 127.44 17.145 ;
     RECT  2.16 17.415 127.44 17.685 ;
     RECT  2.16 17.955 127.44 18.225 ;
     RECT  2.16 18.495 127.44 18.765 ;
     RECT  2.16 19.035 127.44 19.305 ;
     RECT  2.16 19.575 127.44 19.845 ;
     RECT  2.16 20.115 127.44 20.385 ;
     RECT  2.16 20.655 127.44 20.925 ;
     RECT  2.16 21.195 127.44 21.465 ;
     RECT  2.16 21.735 127.44 22.005 ;
     RECT  2.16 22.275 127.44 22.545 ;
     RECT  2.16 22.815 127.44 23.085 ;
     RECT  2.16 23.355 127.44 23.625 ;
     RECT  2.16 23.895 127.44 24.165 ;
     RECT  2.16 24.435 127.44 24.705 ;
     RECT  2.16 24.975 127.44 25.245 ;
     RECT  2.16 25.515 127.44 25.785 ;
     RECT  2.16 26.055 127.44 26.325 ;
     RECT  2.16 26.595 127.44 26.865 ;
     RECT  2.16 27.135 127.44 27.405 ;
     RECT  2.16 27.675 127.44 27.945 ;
     RECT  2.16 28.215 127.44 28.485 ;
     RECT  2.16 28.755 127.44 29.025 ;
     RECT  2.16 29.295 127.44 29.565 ;
     RECT  2.16 29.835 127.44 30.105 ;
     RECT  2.16 30.375 127.44 30.645 ;
     RECT  2.16 30.915 127.44 31.185 ;
     RECT  2.16 31.455 127.44 31.725 ;
     RECT  2.16 31.995 127.44 32.265 ;
     RECT  2.16 32.535 127.44 32.805 ;
     RECT  2.16 33.075 127.44 33.345 ;
     RECT  2.16 33.615 127.44 33.885 ;
     RECT  2.16 34.155 127.44 34.425 ;
     RECT  2.16 34.695 127.44 34.965 ;
     RECT  2.16 35.235 127.44 35.505 ;
     RECT  2.16 35.775 127.44 36.045 ;
     RECT  2.16 36.315 127.44 36.585 ;
     RECT  2.16 36.855 127.44 37.125 ;
     RECT  2.16 37.395 127.44 37.665 ;
     RECT  2.16 37.935 127.44 38.205 ;
     RECT  2.16 38.475 127.44 38.745 ;
     RECT  2.16 39.015 127.44 39.285 ;
     RECT  2.16 39.555 127.44 39.825 ;
     RECT  2.16 40.095 127.44 40.365 ;
     RECT  2.16 40.635 127.44 40.905 ;
     RECT  2.16 41.175 127.44 41.445 ;
     RECT  2.16 41.715 127.44 41.985 ;
     RECT  2.16 42.255 127.44 42.525 ;
     RECT  2.16 42.795 127.44 43.065 ;
     RECT  2.16 43.335 127.44 43.605 ;
     RECT  2.16 43.875 127.44 44.145 ;
     RECT  2.16 44.415 127.44 44.685 ;
     RECT  2.16 44.955 127.44 45.225 ;
     RECT  2.16 45.495 127.44 45.765 ;
     RECT  2.16 46.035 127.44 46.305 ;
     RECT  2.16 46.575 127.44 46.845 ;
     RECT  2.16 47.115 127.44 47.385 ;
     RECT  2.16 47.655 127.44 47.925 ;
     RECT  2.16 48.195 127.44 48.465 ;
     RECT  2.16 48.735 127.44 49.005 ;
     RECT  2.16 49.275 127.44 49.545 ;
     RECT  2.16 49.815 127.44 50.085 ;
     RECT  2.16 50.355 127.44 50.625 ;
     RECT  2.16 50.895 127.44 51.165 ;
     RECT  2.16 51.435 127.44 51.705 ;
     RECT  2.16 51.975 127.44 52.245 ;
     RECT  2.16 52.515 127.44 52.785 ;
     RECT  2.16 53.055 127.44 53.325 ;
     RECT  2.16 53.595 127.44 53.865 ;
     RECT  2.16 54.135 127.44 54.405 ;
     RECT  2.16 54.675 127.44 54.945 ;
     RECT  2.16 55.215 127.44 55.485 ;
     RECT  2.16 55.755 127.44 56.025 ;
     RECT  2.16 56.295 127.44 56.565 ;
     RECT  2.16 56.835 127.44 57.105 ;
     RECT  2.16 57.375 127.44 57.645 ;
     RECT  2.16 57.915 127.44 58.185 ;
     RECT  2.16 58.455 127.44 58.725 ;
     RECT  2.16 58.995 127.44 59.265 ;
     RECT  2.16 59.535 127.44 59.805 ;
     RECT  2.16 60.075 127.44 60.345 ;
     RECT  2.16 60.615 127.44 60.885 ;
     RECT  2.16 61.155 127.44 61.425 ;
     RECT  2.16 61.695 127.44 61.965 ;
     RECT  2.16 62.235 127.44 62.505 ;
     RECT  2.16 62.775 127.44 63.045 ;
     RECT  2.16 63.315 127.44 63.585 ;
     RECT  2.16 63.855 127.44 64.125 ;
     RECT  2.16 64.395 127.44 64.665 ;
     RECT  2.16 64.935 127.44 65.205 ;
     RECT  2.16 65.475 127.44 65.745 ;
     RECT  2.16 66.015 127.44 66.285 ;
     RECT  2.16 66.555 127.44 66.825 ;
     RECT  2.16 67.095 127.44 67.365 ;
     RECT  2.16 67.635 127.44 67.905 ;
     RECT  2.16 68.175 127.44 68.445 ;
     RECT  2.16 68.715 127.44 68.985 ;
     RECT  2.16 69.255 127.44 69.525 ;
     RECT  2.16 69.795 127.44 70.065 ;
     RECT  2.16 70.335 127.44 70.605 ;
     RECT  2.16 70.875 127.44 71.145 ;
     RECT  2.16 71.415 127.44 71.685 ;
     RECT  2.16 71.955 127.44 72.225 ;
     RECT  2.16 72.495 127.44 72.765 ;
     RECT  2.16 73.035 127.44 73.305 ;
     RECT  2.16 73.575 127.44 73.845 ;
     RECT  2.16 74.115 127.44 74.385 ;
     RECT  2.16 74.655 127.44 74.925 ;
     RECT  2.16 75.195 127.44 75.465 ;
     RECT  2.16 75.735 127.44 76.005 ;
     RECT  2.16 76.275 127.44 76.545 ;
     RECT  2.16 76.815 127.44 77.085 ;
     RECT  2.16 77.355 127.44 77.625 ;
     RECT  2.16 77.895 127.44 78.165 ;
     RECT  2.16 78.435 127.44 78.705 ;
     RECT  2.16 78.975 127.44 79.245 ;
     RECT  2.16 79.515 127.44 79.785 ;
     RECT  2.16 80.055 127.44 80.325 ;
     RECT  2.16 80.595 127.44 80.865 ;
     RECT  2.16 81.135 127.44 81.405 ;
     RECT  2.16 81.675 127.44 81.945 ;
     RECT  2.16 82.215 127.44 82.485 ;
     RECT  2.16 82.755 127.44 83.025 ;
     RECT  2.16 83.295 127.44 83.565 ;
     RECT  2.16 83.835 127.44 84.105 ;
    LAYER M1 ;
     RECT  2.16 2.151 127.44 84.249 ;
    LAYER M2 ;
     RECT  0.643 82.8 1.399 82.818 ;
     RECT  1.399 82.8 2.16 82.98 ;
     RECT  2.16 2.151 18.031 84.249 ;
     RECT  18.031 2.151 18.203 84.906 ;
     RECT  18.203 2.151 63.247 84.249 ;
     RECT  63.247 2.151 64.903 84.402 ;
     RECT  64.327 85.5 64.903 85.518 ;
     RECT  64.903 2.151 65.983 85.518 ;
     RECT  65.983 2.151 75.811 85.554 ;
     RECT  75.811 2.151 78.151 85.599 ;
     RECT  78.151 2.151 78.655 85.644 ;
     RECT  78.655 2.151 78.691 85.914 ;
     RECT  78.691 2.151 81.023 85.986 ;
     RECT  81.023 2.151 102.667 85.869 ;
     RECT  102.667 2.151 108.455 85.914 ;
     RECT  108.455 2.151 111.695 85.554 ;
     RECT  111.695 85.5 113.855 85.554 ;
     RECT  113.855 85.5 114.539 85.518 ;
     RECT  111.695 2.151 115.655 84.402 ;
     RECT  115.655 2.151 118.615 84.249 ;
     RECT  118.615 2.034 123.935 84.249 ;
     RECT  123.935 2.106 124.943 84.249 ;
     RECT  124.943 2.151 125.995 84.249 ;
     RECT  125.995 2.106 127.44 84.249 ;
     RECT  127.44 17.316 127.715 24.498 ;
     RECT  127.44 49.716 127.715 51.534 ;
     RECT  127.44 81.756 127.751 83.754 ;
     RECT  127.44 76.896 127.787 80.622 ;
     RECT  127.687 84.888 127.787 84.906 ;
     RECT  127.787 76.896 127.967 79.614 ;
     RECT  127.715 17.316 128.111 21.654 ;
     RECT  128.111 17.316 128.255 18.144 ;
     RECT  127.715 22.626 128.255 24.498 ;
     RECT  127.44 25.326 128.255 28.674 ;
     RECT  127.44 55.692 128.255 56.934 ;
     RECT  127.44 57.816 128.255 67.824 ;
     RECT  127.787 80.604 128.255 80.622 ;
     RECT  127.44 2.106 128.291 16.524 ;
     RECT  128.111 19.044 128.291 21.654 ;
     RECT  128.255 26.136 128.291 27.198 ;
     RECT  127.44 29.538 128.291 32.454 ;
     RECT  127.44 35.676 128.291 38.196 ;
     RECT  127.44 38.952 128.291 45.684 ;
     RECT  127.44 46.746 128.291 48.924 ;
     RECT  128.255 57.816 128.291 62.154 ;
     RECT  128.255 63.216 128.291 67.824 ;
     RECT  127.44 68.652 128.291 70.596 ;
     RECT  127.44 71.352 128.291 75.762 ;
     RECT  128.291 29.538 128.363 29.934 ;
     RECT  128.291 2.106 128.795 8.064 ;
     RECT  128.291 9.216 128.795 13.662 ;
     RECT  128.291 19.044 128.795 20.574 ;
     RECT  128.291 38.952 128.795 40.662 ;
     RECT  127.751 81.756 128.803 82.854 ;
     RECT  127.751 83.61 128.803 83.754 ;
     RECT  128.795 4.896 128.831 8.064 ;
     RECT  128.795 9.216 128.831 10.962 ;
     RECT  128.795 11.916 128.831 13.662 ;
     RECT  128.291 14.526 128.831 16.398 ;
     RECT  128.255 18.036 128.831 18.054 ;
     RECT  128.795 19.044 128.831 19.062 ;
     RECT  128.795 20.016 128.831 20.574 ;
     RECT  128.291 21.366 128.831 21.654 ;
     RECT  128.255 22.752 128.831 24.498 ;
     RECT  128.291 26.766 128.831 27.198 ;
     RECT  128.255 28.188 128.831 28.674 ;
     RECT  128.363 29.538 128.831 29.556 ;
     RECT  128.291 30.816 128.831 32.454 ;
     RECT  127.44 33.246 128.831 33.264 ;
     RECT  127.44 34.056 128.831 34.884 ;
     RECT  128.291 35.676 128.831 36.306 ;
     RECT  128.291 37.296 128.831 38.196 ;
     RECT  128.795 38.952 128.831 38.97 ;
     RECT  128.795 39.726 128.831 40.662 ;
     RECT  128.291 41.616 128.831 43.326 ;
     RECT  128.291 44.352 128.831 45.684 ;
     RECT  128.291 46.746 128.831 48.654 ;
     RECT  127.715 49.716 128.831 51.462 ;
     RECT  127.44 52.686 128.831 54.864 ;
     RECT  128.255 55.692 128.831 55.854 ;
     RECT  128.255 56.916 128.831 56.934 ;
     RECT  128.291 57.816 128.831 59.634 ;
     RECT  128.291 60.516 128.831 62.154 ;
     RECT  128.291 63.216 128.831 64.854 ;
     RECT  128.291 65.952 128.831 67.824 ;
     RECT  128.291 68.652 128.831 70.398 ;
     RECT  128.291 71.352 128.831 72.954 ;
     RECT  128.291 74.016 128.831 75.762 ;
     RECT  127.967 77.94 128.831 79.614 ;
     RECT  128.803 81.756 128.831 83.754 ;
     RECT  128.831 6.822 128.867 6.84 ;
     RECT  128.831 20.466 128.867 20.484 ;
     RECT  128.831 26.766 128.867 26.784 ;
     RECT  128.831 32.436 128.867 32.454 ;
     RECT  128.831 55.836 128.867 55.854 ;
     RECT  128.831 67.806 128.867 67.824 ;
     RECT  128.831 79.056 128.867 79.074 ;
     RECT  128.831 81.756 128.867 83.664 ;
     RECT  128.831 77.94 128.903 77.994 ;
     RECT  128.867 83.574 128.903 83.628 ;
     RECT  128.903 83.61 128.939 83.628 ;
     RECT  128.795 2.106 129.443 3.906 ;
     RECT  129.443 2.106 129.479 2.124 ;
     RECT  129.443 3.114 129.479 3.906 ;
     RECT  129.479 3.888 129.515 3.906 ;
     RECT  128.831 8.046 129.515 8.064 ;
     RECT  128.831 9.666 129.515 10.224 ;
     RECT  128.831 13.644 129.515 13.662 ;
     RECT  128.831 14.526 129.515 14.544 ;
     RECT  128.831 21.636 129.515 21.654 ;
     RECT  128.831 23.256 129.515 23.274 ;
     RECT  128.255 25.326 129.515 25.344 ;
     RECT  128.831 37.566 129.515 37.584 ;
     RECT  128.831 42.156 129.515 42.174 ;
     RECT  128.831 43.308 129.515 43.326 ;
     RECT  128.831 45 129.515 45.018 ;
     RECT  128.831 54.108 129.515 54.126 ;
     RECT  128.831 63.216 129.515 63.234 ;
     RECT  128.831 68.958 129.515 68.976 ;
     RECT  128.831 72 129.515 72.018 ;
     RECT  128.831 72.936 129.515 72.954 ;
     RECT  127.967 76.896 129.515 76.914 ;
     RECT  128.903 77.976 129.515 77.994 ;
     RECT  128.867 81.756 129.515 82.314 ;
     RECT  129.515 81.756 129.587 81.774 ;
    LAYER M3 ;
     RECT  127.944 0.139 127.962 0.811 ;
     RECT  127.944 0.811 127.998 1.147 ;
     RECT  129.492 1.483 129.51 1.819 ;
     RECT  126.504 0.475 126.522 2.101 ;
     RECT  126 2.101 126.522 2.143 ;
     RECT  129.456 1.819 129.51 2.155 ;
     RECT  124.92 2.101 124.938 2.191 ;
     RECT  126 2.143 126.705 2.191 ;
     RECT  122.688 2.101 122.706 2.219 ;
     RECT  118.62 2.029 118.638 2.255 ;
     RECT  124.92 2.191 127.098 2.263 ;
     RECT  127.944 1.147 128.07 2.263 ;
     RECT  121.215 2.143 121.305 2.335 ;
     RECT  123.912 2.029 123.93 2.371 ;
     RECT  2.415 2.143 2.505 2.413 ;
     RECT  7.815 2.143 7.905 2.413 ;
     RECT  13.215 2.143 13.305 2.413 ;
     RECT  18.615 2.143 18.705 2.413 ;
     RECT  24.015 2.143 24.105 2.413 ;
     RECT  29.415 2.143 29.505 2.413 ;
     RECT  34.815 2.143 34.905 2.413 ;
     RECT  40.215 2.143 40.305 2.413 ;
     RECT  45.615 2.143 45.705 2.413 ;
     RECT  51.015 2.143 51.105 2.413 ;
     RECT  56.415 2.143 56.505 2.413 ;
     RECT  61.815 2.143 61.905 2.413 ;
     RECT  67.215 2.143 67.305 2.413 ;
     RECT  72.615 2.143 72.705 2.413 ;
     RECT  78.015 2.143 78.105 2.413 ;
     RECT  83.415 2.143 83.505 2.413 ;
     RECT  88.815 2.143 88.905 2.413 ;
     RECT  89.784 2.191 89.802 2.413 ;
     RECT  94.215 2.143 94.305 2.413 ;
     RECT  99.615 2.143 99.705 2.413 ;
     RECT  105.015 2.143 105.105 2.413 ;
     RECT  110.415 2.143 110.505 2.413 ;
     RECT  115.815 2.143 115.905 2.413 ;
     RECT  121.215 2.335 121.59 2.461 ;
     RECT  123.048 2.371 123.93 2.461 ;
     RECT  124.92 2.263 128.07 2.461 ;
     RECT  123.048 2.461 128.07 2.561 ;
     RECT  129.42 2.155 129.51 2.597 ;
     RECT  121.215 2.461 121.662 2.641 ;
     RECT  109.116 2.227 109.134 2.731 ;
     RECT  121.215 2.641 121.878 2.759 ;
     RECT  119.988 2.641 120.006 2.767 ;
     RECT  119.988 2.767 120.474 2.813 ;
     RECT  124.308 2.561 128.07 2.875 ;
     RECT  123.048 2.561 123.57 3.343 ;
     RECT  124.308 2.875 128.106 3.343 ;
     RECT  123.048 3.343 128.106 3.403 ;
     RECT  85.212 2.461 85.23 3.541 ;
     RECT  122.832 3.403 128.106 3.541 ;
     RECT  122.544 3.541 128.106 3.547 ;
     RECT  129.456 2.597 129.51 3.547 ;
     RECT  122.544 3.547 129.51 3.581 ;
     RECT  122.544 3.581 124.29 3.713 ;
     RECT  125.064 3.581 129.51 3.839 ;
     RECT  119.988 2.813 120.006 3.847 ;
     RECT  121.215 2.759 121.698 3.847 ;
     RECT  125.1 3.839 129.51 3.911 ;
     RECT  119.988 3.847 121.698 3.931 ;
     RECT  88.815 2.413 89.802 4.081 ;
     RECT  125.1 3.911 128.826 4.109 ;
     RECT  125.532 4.109 128.826 4.145 ;
     RECT  119.988 3.931 121.878 4.157 ;
     RECT  118.584 4.081 118.602 4.253 ;
     RECT  122.832 3.713 124.29 4.621 ;
     RECT  125.964 4.145 128.826 4.649 ;
     RECT  125.964 4.649 127.242 4.721 ;
     RECT  122.544 4.621 124.29 4.757 ;
     RECT  122.94 4.757 124.29 4.955 ;
     RECT  125.964 4.721 127.134 4.955 ;
     RECT  128.196 4.649 128.826 5.027 ;
     RECT  125.964 4.955 127.098 5.071 ;
     RECT  119.988 4.157 121.497 5.161 ;
     RECT  125.136 5.071 127.098 5.189 ;
     RECT  119.376 5.161 121.497 5.305 ;
     RECT  119.376 5.305 121.806 5.597 ;
     RECT  123.084 4.955 124.29 5.707 ;
     RECT  108.576 2.731 109.134 6.007 ;
     RECT  125.424 5.189 127.098 6.115 ;
     RECT  123.084 5.707 124.434 6.151 ;
     RECT  105.015 2.413 105.297 6.241 ;
     RECT  125.388 6.115 127.098 6.269 ;
     RECT  123.084 6.151 124.614 6.385 ;
     RECT  99.615 2.413 99.897 6.511 ;
     RECT  122.724 6.385 124.614 6.511 ;
     RECT  122.544 6.511 124.614 6.719 ;
     RECT  128.232 5.027 128.826 6.719 ;
     RECT  122.616 6.719 124.614 6.781 ;
     RECT  122.616 6.781 124.758 6.809 ;
     RECT  125.784 6.269 127.098 6.809 ;
     RECT  128.808 6.719 128.826 6.817 ;
     RECT  103.464 4.729 103.482 7.123 ;
     RECT  123.084 6.809 124.758 7.151 ;
     RECT  128.808 6.817 128.862 7.619 ;
     RECT  101.736 6.583 101.754 7.627 ;
     RECT  125.964 6.809 127.098 7.735 ;
     RECT  95.436 5.467 95.454 7.861 ;
     RECT  123.552 7.151 124.758 8.041 ;
     RECT  125.964 7.735 127.134 8.041 ;
     RECT  129.492 7.915 129.51 8.069 ;
     RECT  123.552 8.041 127.134 8.159 ;
     RECT  95.436 7.861 96.03 8.167 ;
     RECT  119.376 5.597 121.497 8.203 ;
     RECT  128.232 8.239 128.25 8.285 ;
     RECT  122.544 8.203 122.562 8.339 ;
     RECT  123.552 8.159 124.758 8.401 ;
     RECT  116.856 8.203 116.874 8.429 ;
     RECT  119.376 8.203 121.554 8.429 ;
     RECT  125.532 8.159 127.134 8.429 ;
     RECT  122.94 8.401 124.758 8.477 ;
     RECT  128.268 8.473 128.286 8.587 ;
     RECT  103.464 7.123 104.022 8.671 ;
     RECT  125.568 8.429 126.954 8.699 ;
     RECT  123.156 8.477 124.758 8.861 ;
     RECT  125.676 8.699 126.954 8.969 ;
     RECT  99.036 6.511 99.897 9.211 ;
     RECT  128.268 8.587 128.826 9.259 ;
     RECT  122.436 9.211 122.454 9.275 ;
     RECT  102.888 8.671 104.022 9.481 ;
     RECT  105.015 6.241 105.714 9.481 ;
     RECT  128.16 9.259 128.826 9.617 ;
     RECT  119.376 8.429 121.497 9.625 ;
     RECT  126.108 8.969 126.954 9.625 ;
     RECT  128.808 9.617 128.826 9.661 ;
     RECT  123.552 8.861 124.758 9.691 ;
     RECT  128.808 9.661 129.51 9.779 ;
     RECT  126.108 9.625 127.026 9.859 ;
     RECT  125.784 9.859 127.026 9.931 ;
     RECT  122.904 9.691 124.758 10.129 ;
     RECT  122.832 10.129 124.758 10.165 ;
     RECT  125.712 9.931 127.026 10.165 ;
     RECT  122.832 10.165 127.026 10.229 ;
     RECT  129.492 9.779 129.51 10.301 ;
     RECT  123.12 10.229 127.026 10.319 ;
     RECT  95.436 8.167 96.138 10.561 ;
     RECT  118.584 10.021 118.602 10.589 ;
     RECT  119.376 9.625 121.662 10.648 ;
     RECT  126.072 10.319 127.026 10.705 ;
     RECT  123.12 10.319 125.262 10.733 ;
     RECT  126.072 10.705 127.062 10.975 ;
     RECT  123.552 10.733 125.262 11.281 ;
     RECT  126.072 10.975 127.134 11.281 ;
     RECT  128.808 10.561 128.826 11.281 ;
     RECT  123.552 11.281 127.134 11.785 ;
     RECT  123.3 11.785 127.134 11.837 ;
     RECT  128.772 11.281 128.826 11.947 ;
     RECT  128.196 11.947 128.826 12.281 ;
     RECT  118.584 11.641 118.602 12.353 ;
     RECT  122.292 11.803 122.31 12.631 ;
     RECT  123.552 11.837 127.134 12.749 ;
     RECT  115.815 2.413 116.097 12.829 ;
     RECT  112.212 12.181 112.23 12.865 ;
     RECT  113.112 11.749 113.13 12.865 ;
     RECT  128.808 12.281 128.826 13.019 ;
     RECT  128.232 13.261 128.25 13.325 ;
     RECT  122.292 12.631 122.634 13.433 ;
     RECT  122.328 13.433 122.634 13.441 ;
     RECT  123.552 12.749 127.026 13.639 ;
     RECT  122.328 13.441 122.67 13.771 ;
     RECT  123.552 13.639 127.206 13.771 ;
     RECT  122.328 13.771 127.206 13.829 ;
     RECT  122.328 13.829 127.134 14.141 ;
     RECT  115.815 12.829 116.55 14.143 ;
     RECT  123.552 14.141 127.134 14.369 ;
     RECT  94.215 2.413 94.497 14.521 ;
     RECT  119.376 10.648 121.497 14.549 ;
     RECT  129.492 13.639 129.51 14.549 ;
     RECT  128.268 13.981 128.286 14.611 ;
     RECT  128.268 14.611 128.826 15.019 ;
     RECT  128.232 15.019 128.826 15.089 ;
     RECT  119.196 14.611 119.214 15.421 ;
     RECT  119.952 14.549 121.497 15.421 ;
     RECT  123.552 14.369 127.026 15.835 ;
     RECT  123.552 15.835 127.098 15.871 ;
     RECT  122.328 14.141 122.67 15.961 ;
     RECT  128.808 15.089 128.826 15.961 ;
     RECT  119.196 15.421 121.497 16.141 ;
     RECT  122.328 15.961 122.742 16.141 ;
     RECT  115.416 14.143 116.55 16.231 ;
     RECT  117.504 11.281 117.522 16.231 ;
     RECT  123.48 15.871 127.098 16.267 ;
     RECT  128.232 15.961 128.826 16.403 ;
     RECT  102.888 9.481 105.714 16.807 ;
     RECT  123.48 16.267 127.134 16.835 ;
     RECT  119.196 16.141 122.742 16.951 ;
     RECT  123.48 16.835 124.29 16.951 ;
     RECT  125.136 16.835 127.134 17.069 ;
     RECT  128.232 16.403 128.286 17.069 ;
     RECT  115.416 16.231 117.522 17.617 ;
     RECT  125.136 17.069 126.897 17.645 ;
     RECT  119.196 16.951 124.29 18.031 ;
     RECT  125.136 17.645 125.514 18.031 ;
     RECT  126.432 17.645 126.897 18.031 ;
     RECT  128.232 17.069 128.25 18.031 ;
     RECT  128.232 18.031 128.826 18.077 ;
     RECT  128.232 18.077 128.25 18.149 ;
     RECT  119.196 18.031 125.514 18.221 ;
     RECT  114.66 13.531 114.678 18.427 ;
     RECT  115.416 17.617 117.846 18.427 ;
     RECT  119.196 18.221 124.29 18.427 ;
     RECT  125.064 18.221 125.514 18.571 ;
     RECT  126.432 18.031 127.098 18.571 ;
     RECT  128.088 18.379 128.106 18.599 ;
     RECT  125.064 18.571 127.098 18.661 ;
     RECT  125.064 18.661 127.71 18.749 ;
     RECT  118.584 18.427 124.29 19.139 ;
     RECT  125.064 18.749 127.098 19.229 ;
     RECT  125.064 19.229 126.954 19.265 ;
     RECT  128.808 19.039 128.826 19.345 ;
     RECT  119.016 19.139 124.29 19.679 ;
     RECT  126.504 19.265 126.954 19.769 ;
     RECT  112.212 12.865 113.13 20.047 ;
     RECT  128.772 19.345 128.826 20.059 ;
     RECT  126.504 19.769 126.897 20.191 ;
     RECT  126.36 20.191 126.897 20.309 ;
     RECT  119.016 19.679 122.346 20.317 ;
     RECT  118.584 20.317 122.346 20.417 ;
     RECT  128.232 20.059 128.826 20.417 ;
     RECT  128.808 20.417 128.826 20.461 ;
     RECT  126.54 20.309 126.897 20.695 ;
     RECT  128.808 20.461 128.862 20.765 ;
     RECT  123.228 19.679 124.29 21.001 ;
     RECT  119.016 20.417 122.346 21.127 ;
     RECT  123.228 21.001 124.326 21.127 ;
     RECT  126.54 20.695 127.062 21.235 ;
     RECT  128.808 20.765 128.826 21.271 ;
     RECT  128.268 21.271 128.826 21.389 ;
     RECT  128.268 21.389 128.286 21.437 ;
     RECT  114.66 18.427 117.846 21.541 ;
     RECT  119.016 21.127 124.326 21.541 ;
     RECT  126.54 21.235 127.134 21.541 ;
     RECT  129.492 21.631 129.51 21.773 ;
     RECT  126.504 21.541 127.134 21.775 ;
     RECT  114.66 21.541 124.326 21.965 ;
     RECT  126.504 21.775 127.17 21.973 ;
     RECT  125.064 19.265 125.514 22.045 ;
     RECT  126.504 21.973 128.25 22.045 ;
     RECT  88.092 4.081 89.802 22.441 ;
     RECT  125.064 22.045 128.25 22.445 ;
     RECT  128.232 22.445 128.25 22.649 ;
     RECT  83.415 2.413 83.697 22.711 ;
     RECT  114.66 21.965 122.346 22.711 ;
     RECT  123.228 21.965 124.326 22.711 ;
     RECT  125.064 22.445 127.242 22.739 ;
     RECT  112.212 20.047 113.706 22.783 ;
     RECT  114.66 22.711 124.326 22.783 ;
     RECT  112.212 22.783 124.326 22.811 ;
     RECT  125.064 22.739 127.062 22.847 ;
     RECT  128.808 22.747 128.826 23.251 ;
     RECT  95.436 10.561 96.786 23.287 ;
     RECT  128.808 23.251 129.51 23.453 ;
     RECT  125.136 22.847 127.062 23.701 ;
     RECT  128.808 23.453 128.826 23.755 ;
     RECT  123.228 22.811 124.326 23.899 ;
     RECT  125.136 23.701 127.134 23.899 ;
     RECT  128.196 23.755 128.826 23.927 ;
     RECT  88.092 22.441 90.342 24.061 ;
     RECT  123.228 23.899 127.134 24.403 ;
     RECT  128.808 23.927 128.826 24.512 ;
     RECT  112.212 22.811 122.346 24.571 ;
     RECT  123.228 24.403 127.71 24.571 ;
     RECT  84.888 3.541 85.23 25.141 ;
     RECT  86.328 22.009 86.346 25.141 ;
     RECT  112.212 24.571 127.71 25.169 ;
     RECT  127.692 25.169 127.71 25.181 ;
     RECT  129.492 24.811 129.51 25.349 ;
     RECT  112.212 25.169 126.897 25.439 ;
     RECT  95.436 23.287 97.182 25.987 ;
     RECT  98.352 9.211 99.897 25.987 ;
     RECT  125.136 25.439 126.897 26.095 ;
     RECT  128.232 25.483 128.25 26.131 ;
     RECT  128.232 26.131 128.286 26.189 ;
     RECT  125.136 26.095 127.062 26.401 ;
     RECT  125.136 26.401 127.71 26.599 ;
     RECT  101.736 7.627 101.826 26.635 ;
     RECT  102.888 16.807 106.29 26.635 ;
     RECT  108 6.007 109.134 26.671 ;
     RECT  110.415 2.413 110.697 26.671 ;
     RECT  112.212 25.439 124.326 26.789 ;
     RECT  125.064 26.599 127.71 26.789 ;
     RECT  128.844 26.761 128.862 26.861 ;
     RECT  128.808 27.163 128.826 27.203 ;
     RECT  125.136 26.789 127.71 27.499 ;
     RECT  101.736 26.635 106.29 27.571 ;
     RECT  123.228 26.789 124.326 27.715 ;
     RECT  125.136 27.499 128.25 27.715 ;
     RECT  123.228 27.715 128.25 27.841 ;
     RECT  123.192 27.841 128.25 27.869 ;
     RECT  112.212 26.789 122.346 27.877 ;
     RECT  123.192 27.869 126.99 27.877 ;
     RECT  112.212 27.877 126.99 27.917 ;
     RECT  95.436 25.987 99.897 28.111 ;
     RECT  101.664 27.571 106.29 28.417 ;
     RECT  128.808 28.171 128.826 28.679 ;
     RECT  123.192 27.917 126.99 28.781 ;
     RECT  123.228 28.781 126.99 28.795 ;
     RECT  123.228 28.795 127.062 28.831 ;
     RECT  123.228 28.831 127.134 28.877 ;
     RECT  92.772 17.923 92.79 29.191 ;
     RECT  93.528 14.521 94.497 29.191 ;
     RECT  95.436 28.111 100.602 29.263 ;
     RECT  128.196 29.179 128.214 29.515 ;
     RECT  123.228 28.877 127.062 29.605 ;
     RECT  112.212 27.917 122.346 29.611 ;
     RECT  92.016 10.021 92.034 29.731 ;
     RECT  128.196 29.515 128.826 29.867 ;
     RECT  123.228 29.605 127.098 29.875 ;
     RECT  112.212 29.611 122.418 29.995 ;
     RECT  123.228 29.875 127.134 29.995 ;
     RECT  112.212 29.995 127.134 30.569 ;
     RECT  112.212 30.569 126.954 30.677 ;
     RECT  128.268 29.867 128.826 30.859 ;
     RECT  87.48 24.061 90.342 31.081 ;
     RECT  128.232 30.859 128.826 31.109 ;
     RECT  112.212 30.677 126.897 31.495 ;
     RECT  112.212 31.495 127.062 31.525 ;
     RECT  112.212 31.525 127.134 31.565 ;
     RECT  112.212 31.565 127.062 31.649 ;
     RECT  101.664 28.417 106.866 32.161 ;
     RECT  108 26.671 110.697 32.161 ;
     RECT  128.808 31.109 128.826 32.197 ;
     RECT  128.232 32.197 128.826 32.237 ;
     RECT  92.772 29.191 94.497 32.431 ;
     RECT  95.436 29.263 100.926 32.431 ;
     RECT  128.268 32.237 128.826 32.431 ;
     RECT  112.212 31.649 126.954 32.467 ;
     RECT  128.268 32.431 128.862 32.573 ;
     RECT  84.888 25.141 86.346 32.773 ;
     RECT  87.48 31.081 90.702 32.773 ;
     RECT  112.212 32.467 127.134 32.881 ;
     RECT  128.808 32.573 128.862 32.909 ;
     RECT  112.212 32.881 127.314 32.999 ;
     RECT  111.456 20.317 111.474 33.241 ;
     RECT  112.212 32.999 127.098 33.241 ;
     RECT  111.456 33.241 127.098 33.341 ;
     RECT  128.808 32.909 128.826 33.547 ;
     RECT  111.456 33.341 126.897 34.493 ;
     RECT  128.232 33.547 128.826 34.555 ;
     RECT  128.196 34.555 128.826 34.727 ;
     RECT  114.66 34.493 126.897 34.735 ;
     RECT  114.66 34.735 126.99 35.005 ;
     RECT  114.66 35.005 127.062 35.159 ;
     RECT  114.66 35.159 126.897 35.465 ;
     RECT  128.232 34.727 128.826 35.947 ;
     RECT  114.66 35.465 125.586 36.211 ;
     RECT  126.54 35.465 126.897 36.211 ;
     RECT  127.656 35.947 128.826 36.32 ;
     RECT  114.66 36.211 126.897 36.355 ;
     RECT  127.656 36.32 128.286 36.355 ;
     RECT  114.66 36.355 128.286 36.413 ;
     RECT  123.228 36.413 128.286 36.419 ;
     RECT  128.232 36.419 128.286 36.689 ;
     RECT  128.268 36.689 128.286 36.989 ;
     RECT  123.228 36.419 127.134 37.049 ;
     RECT  114.66 36.413 122.418 37.471 ;
     RECT  123.228 37.049 127.062 37.471 ;
     RECT  128.808 37.291 128.826 37.561 ;
     RECT  114.66 37.471 127.062 37.589 ;
     RECT  128.808 37.561 129.51 37.661 ;
     RECT  123.228 37.589 127.062 37.975 ;
     RECT  123.228 37.975 127.206 38.129 ;
     RECT  128.808 37.661 128.826 38.299 ;
     RECT  123.228 38.129 127.134 38.669 ;
     RECT  128.232 38.299 128.826 39.047 ;
     RECT  114.66 37.589 122.418 39.181 ;
     RECT  123.228 38.669 127.026 39.181 ;
     RECT  114.66 39.181 127.026 39.631 ;
     RECT  128.772 39.047 128.826 39.677 ;
     RECT  111.456 34.493 113.706 39.721 ;
     RECT  114.66 39.631 127.098 39.721 ;
     RECT  111.456 39.721 127.098 39.829 ;
     RECT  111.456 39.829 127.71 40.013 ;
     RECT  111.456 40.013 127.098 40.829 ;
     RECT  128.808 39.677 128.826 40.981 ;
     RECT  128.268 40.981 128.826 41.357 ;
     RECT  111.456 40.829 126.954 41.611 ;
     RECT  111.456 41.611 127.062 41.659 ;
     RECT  111.456 41.659 127.674 41.819 ;
     RECT  128.808 41.357 128.826 42.151 ;
     RECT  128.808 42.151 129.51 42.365 ;
     RECT  111.456 41.819 127.098 42.449 ;
     RECT  128.808 42.365 128.826 42.667 ;
     RECT  128.196 42.667 128.826 42.755 ;
     RECT  128.808 42.755 128.826 43.037 ;
     RECT  111.456 42.449 127.026 43.169 ;
     RECT  125.064 43.169 127.026 43.303 ;
     RECT  0.108 43.195 0.126 43.325 ;
     RECT  63.864 43.231 63.882 43.325 ;
     RECT  65.412 43.291 65.43 43.331 ;
     RECT  129.492 43.303 129.51 43.373 ;
     RECT  3.42 43.375 3.438 43.411 ;
     RECT  125.064 43.303 127.134 43.529 ;
     RECT  2.415 2.413 2.697 43.681 ;
     RECT  3.42 43.411 3.618 43.681 ;
     RECT  4.392 43.267 4.41 43.681 ;
     RECT  82.332 43.609 82.35 43.771 ;
     RECT  128.232 43.675 128.286 44.069 ;
     RECT  2.415 43.681 3.618 44.221 ;
     RECT  4.356 43.681 4.41 44.221 ;
     RECT  111.456 43.169 124.326 44.221 ;
     RECT  125.064 43.529 126.954 44.221 ;
     RECT  111.456 44.221 126.954 44.455 ;
     RECT  2.415 44.221 4.41 44.491 ;
     RECT  2.304 44.491 4.41 44.581 ;
     RECT  2.304 44.581 4.878 44.645 ;
     RECT  111.456 44.455 127.026 44.681 ;
     RECT  22.824 44.587 22.842 44.717 ;
     RECT  27.36 44.683 27.378 44.879 ;
     RECT  28.476 44.875 28.494 44.915 ;
     RECT  2.415 44.645 4.878 44.995 ;
     RECT  126.396 44.681 127.026 44.995 ;
     RECT  128.808 44.347 128.826 44.995 ;
     RECT  128.808 44.995 129.51 45.053 ;
     RECT  2.415 44.995 5.49 45.301 ;
     RECT  128.808 45.053 128.826 45.355 ;
     RECT  2.415 45.301 5.742 45.427 ;
     RECT  2.304 45.427 5.742 45.455 ;
     RECT  111.456 44.681 125.55 45.499 ;
     RECT  126.396 44.995 127.134 45.499 ;
     RECT  128.196 45.355 128.826 45.527 ;
     RECT  2.304 45.455 3.078 45.533 ;
     RECT  2.34 45.533 3.078 45.689 ;
     RECT  111.456 45.499 127.134 45.805 ;
     RECT  6.84 45.733 6.858 45.869 ;
     RECT  2.415 45.689 3.078 45.959 ;
     RECT  111.456 45.805 127.17 45.959 ;
     RECT  91.656 29.731 92.034 45.967 ;
     RECT  92.772 32.431 100.926 45.967 ;
     RECT  81.828 43.771 82.35 46.003 ;
     RECT  125.064 45.959 127.17 46.111 ;
     RECT  3.852 45.455 5.742 46.219 ;
     RECT  3.816 46.219 5.742 46.381 ;
     RECT  6.516 46.003 6.606 46.381 ;
     RECT  3.708 46.381 6.606 46.651 ;
     RECT  7.815 2.413 8.097 46.651 ;
     RECT  2.415 45.959 2.934 46.741 ;
     RECT  3.708 46.651 8.097 46.741 ;
     RECT  125.064 46.111 127.314 46.781 ;
     RECT  81.72 46.003 82.35 46.885 ;
     RECT  111.456 45.959 124.326 46.921 ;
     RECT  125.064 46.781 127.098 46.921 ;
     RECT  78.015 2.413 78.297 47.011 ;
     RECT  128.808 45.527 128.826 47.191 ;
     RECT  128.268 47.191 128.826 47.453 ;
     RECT  2.415 46.741 8.097 47.759 ;
     RECT  111.456 46.921 127.098 47.849 ;
     RECT  3.456 47.759 8.097 48.029 ;
     RECT  3.6 48.029 8.097 48.119 ;
     RECT  3.636 48.119 8.097 48.467 ;
     RECT  128.808 47.453 128.826 48.763 ;
     RECT  128.232 48.763 128.826 48.803 ;
     RECT  111.456 47.849 126.954 48.929 ;
     RECT  125.064 48.929 126.954 48.937 ;
     RECT  80.532 45.733 80.55 49.441 ;
     RECT  128.268 48.803 128.826 49.771 ;
     RECT  84.888 32.773 90.702 49.855 ;
     RECT  125.064 48.937 126.99 49.855 ;
     RECT  91.656 45.967 100.926 49.883 ;
     RECT  128.196 49.771 128.826 50.621 ;
     RECT  125.064 49.855 127.098 51.205 ;
     RECT  80.064 49.441 80.55 51.331 ;
     RECT  125.064 51.205 127.134 51.475 ;
     RECT  128.808 50.621 128.826 51.485 ;
     RECT  125.064 51.475 127.17 51.511 ;
     RECT  125.064 51.511 127.71 51.787 ;
     RECT  111.456 48.929 124.326 52.051 ;
     RECT  125.064 51.787 128.25 52.051 ;
     RECT  111.456 52.051 128.25 52.157 ;
     RECT  111.456 52.157 127.17 52.169 ;
     RECT  128.196 52.157 128.25 52.459 ;
     RECT  111.456 52.169 127.098 52.709 ;
     RECT  101.664 32.161 110.697 52.733 ;
     RECT  97.74 49.883 100.926 53.293 ;
     RECT  101.664 52.733 106.65 53.293 ;
     RECT  125.064 52.709 127.098 53.321 ;
     RECT  128.196 52.459 128.826 53.429 ;
     RECT  128.232 53.429 128.826 53.519 ;
     RECT  111.456 52.709 124.326 53.671 ;
     RECT  125.064 53.321 127.026 53.671 ;
     RECT  111.456 53.671 127.026 53.825 ;
     RECT  128.232 53.519 128.25 53.837 ;
     RECT  91.656 49.883 97.002 54.067 ;
     RECT  97.74 53.293 106.65 54.067 ;
     RECT  125.064 53.825 127.026 54.103 ;
     RECT  129.492 54.103 129.51 54.173 ;
     RECT  56.415 2.413 56.697 54.328 ;
     RECT  3.852 48.467 8.097 54.365 ;
     RECT  55.8 54.328 56.697 54.365 ;
     RECT  111.456 53.825 124.326 54.607 ;
     RECT  125.064 54.103 127.098 54.607 ;
     RECT  111.456 54.607 127.098 54.679 ;
     RECT  4.536 54.365 8.097 55.013 ;
     RECT  107.424 52.733 110.697 55.111 ;
     RECT  111.456 54.679 127.242 55.111 ;
     RECT  128.268 54.475 128.826 55.147 ;
     RECT  107.424 55.111 127.242 55.175 ;
     RECT  128.268 55.147 128.862 55.483 ;
     RECT  128.196 55.483 128.862 55.859 ;
     RECT  107.424 55.175 124.326 55.915 ;
     RECT  125.064 55.175 127.242 55.915 ;
     RECT  107.424 55.915 127.242 55.949 ;
     RECT  107.424 55.949 127.17 56.219 ;
     RECT  128.196 55.859 128.25 56.875 ;
     RECT  107.424 56.219 127.134 57.029 ;
     RECT  84.888 49.855 90.774 57.271 ;
     RECT  91.656 54.067 106.65 57.271 ;
     RECT  107.424 57.029 126.897 57.581 ;
     RECT  84.888 57.271 106.65 57.847 ;
     RECT  107.424 57.581 124.326 57.847 ;
     RECT  30.456 52.321 30.474 57.875 ;
     RECT  128.196 56.875 128.826 57.947 ;
     RECT  6.588 55.013 8.097 58.253 ;
     RECT  13.215 2.413 13.497 58.351 ;
     RECT  24.015 2.413 24.297 58.351 ;
     RECT  34.815 2.413 35.097 58.351 ;
     RECT  45.615 2.413 45.897 58.351 ;
     RECT  56.415 54.365 56.697 58.351 ;
     RECT  67.215 2.413 67.497 58.351 ;
     RECT  78.015 47.011 78.822 58.351 ;
     RECT  13.104 58.351 13.497 58.397 ;
     RECT  23.904 58.351 24.297 58.397 ;
     RECT  34.704 58.351 35.097 58.397 ;
     RECT  45.504 58.351 45.897 58.397 ;
     RECT  56.304 58.351 56.697 58.397 ;
     RECT  67.104 58.351 67.497 58.397 ;
     RECT  77.904 58.351 78.822 58.397 ;
     RECT  84.888 57.847 124.326 58.699 ;
     RECT  125.064 57.581 126.897 58.699 ;
     RECT  84.888 58.699 126.897 58.765 ;
     RECT  128.232 57.947 128.826 59.227 ;
     RECT  128.196 59.227 128.826 59.567 ;
     RECT  84.888 58.765 126.954 59.575 ;
     RECT  48.42 59.341 48.438 59.645 ;
     RECT  84.888 59.575 127.206 59.729 ;
     RECT  49.104 59.881 49.122 60.029 ;
     RECT  47.556 59.515 47.574 60.035 ;
     RECT  84.888 59.729 127.134 60.269 ;
     RECT  128.268 59.567 128.826 60.571 ;
     RECT  84.888 60.269 126.897 60.719 ;
     RECT  110.415 60.719 126.897 61.195 ;
     RECT  128.232 60.571 128.826 61.349 ;
     RECT  128.808 61.349 128.826 62.159 ;
     RECT  110.415 61.195 127.134 62.275 ;
     RECT  110.415 62.275 127.314 62.311 ;
     RECT  128.232 62.239 128.25 62.311 ;
     RECT  110.415 62.311 128.25 62.735 ;
     RECT  127.764 62.735 128.25 62.957 ;
     RECT  128.232 62.957 128.25 62.969 ;
     RECT  129.492 63.211 129.51 63.293 ;
     RECT  84.888 60.719 109.35 63.481 ;
     RECT  110.415 62.735 127.026 63.481 ;
     RECT  84.888 63.481 127.026 63.581 ;
     RECT  128.268 63.595 128.826 63.965 ;
     RECT  4.536 55.013 5.49 64.121 ;
     RECT  84.888 63.581 108.018 64.193 ;
     RECT  109.116 63.581 127.026 64.661 ;
     RECT  4.536 64.121 4.842 64.697 ;
     RECT  83.415 22.711 84.114 64.705 ;
     RECT  84.888 64.193 107.946 64.705 ;
     RECT  109.116 64.661 125.514 64.733 ;
     RECT  126.432 64.661 127.026 64.939 ;
     RECT  128.808 63.965 128.826 64.973 ;
     RECT  83.415 64.705 107.946 65.273 ;
     RECT  81.72 46.885 82.422 65.371 ;
     RECT  126.432 64.939 127.098 65.435 ;
     RECT  109.332 64.733 125.514 65.515 ;
     RECT  126.432 65.435 126.99 65.515 ;
     RECT  128.232 65.275 128.286 65.669 ;
     RECT  79.632 51.331 80.55 65.821 ;
     RECT  4.536 64.697 4.554 65.849 ;
     RECT  109.332 65.515 126.99 66.011 ;
     RECT  126.432 66.011 126.99 66.595 ;
     RECT  79.632 65.821 80.946 66.631 ;
     RECT  81.72 65.371 82.494 66.631 ;
     RECT  83.415 65.273 106.83 66.631 ;
     RECT  107.928 65.273 107.946 66.721 ;
     RECT  126.432 66.595 127.026 66.721 ;
     RECT  109.332 66.011 125.514 66.763 ;
     RECT  107.928 66.721 108.522 66.793 ;
     RECT  109.26 66.763 125.514 66.793 ;
     RECT  126.432 66.721 127.098 66.821 ;
     RECT  107.928 66.793 125.514 66.829 ;
     RECT  107.568 66.829 125.514 66.901 ;
     RECT  126.432 66.821 127.026 66.901 ;
     RECT  107.568 66.901 127.026 67.019 ;
     RECT  79.632 66.631 106.83 67.027 ;
     RECT  107.568 67.019 126.99 67.027 ;
     RECT  79.632 67.027 126.99 67.277 ;
     RECT  128.808 65.947 128.826 67.288 ;
     RECT  80.928 67.277 126.99 67.469 ;
     RECT  6.588 58.253 6.606 67.559 ;
     RECT  128.232 67.288 128.826 67.801 ;
     RECT  81.324 67.469 126.99 67.945 ;
     RECT  128.232 67.801 128.862 68.011 ;
     RECT  128.196 68.011 128.862 68.717 ;
     RECT  40.215 2.413 40.497 68.719 ;
     RECT  128.196 68.717 128.286 68.747 ;
     RECT  81.324 67.945 127.062 68.755 ;
     RECT  24.015 58.397 24.297 69.025 ;
     RECT  81.324 68.755 127.134 69.025 ;
     RECT  129.492 68.953 129.51 69.053 ;
     RECT  79.632 67.277 80.154 69.307 ;
     RECT  80.964 69.025 127.134 69.307 ;
     RECT  128.268 68.747 128.286 69.389 ;
     RECT  79.632 69.307 127.134 69.449 ;
     RECT  79.632 69.449 127.062 69.485 ;
     RECT  11.52 68.107 11.538 69.799 ;
     RECT  13.215 58.397 13.497 70.363 ;
     RECT  126.324 69.485 127.062 70.375 ;
     RECT  128.808 69.691 128.826 70.403 ;
     RECT  56.415 58.397 56.697 70.411 ;
     RECT  79.632 69.485 125.478 70.411 ;
     RECT  79.632 70.411 125.514 70.681 ;
     RECT  126.324 70.375 127.206 70.681 ;
     RECT  79.632 70.681 127.206 70.699 ;
     RECT  128.268 70.573 128.286 70.699 ;
     RECT  24.015 69.025 24.714 70.891 ;
     RECT  40.215 68.719 41.166 70.939 ;
     RECT  79.632 70.699 128.286 71.069 ;
     RECT  127.836 71.069 127.854 71.447 ;
     RECT  34.815 58.397 35.097 71.467 ;
     RECT  71.82 71.185 71.838 71.645 ;
     RECT  74.664 71.617 74.682 71.689 ;
     RECT  128.808 71.347 128.826 71.707 ;
     RECT  78.015 58.397 78.822 71.752 ;
     RECT  74.664 71.689 74.754 71.753 ;
     RECT  72.615 2.413 72.897 71.755 ;
     RECT  74.736 71.753 74.754 71.789 ;
     RECT  77.904 71.752 78.822 71.803 ;
     RECT  79.632 71.069 124.326 71.803 ;
     RECT  24.015 70.891 24.786 71.851 ;
     RECT  45.615 58.397 45.897 71.851 ;
     RECT  67.215 58.397 67.497 71.851 ;
     RECT  23.904 71.851 24.786 71.888 ;
     RECT  45.504 71.851 45.897 71.888 ;
     RECT  67.104 71.851 67.497 71.888 ;
     RECT  77.904 71.803 124.326 71.888 ;
     RECT  56.124 70.411 56.697 71.899 ;
     RECT  125.064 71.069 127.026 71.959 ;
     RECT  7.815 58.253 8.097 71.995 ;
     RECT  78.015 71.888 124.326 71.995 ;
     RECT  125.064 71.959 127.062 71.995 ;
     RECT  128.808 71.707 129.51 72.023 ;
     RECT  78.015 71.995 127.062 72.121 ;
     RECT  52.488 71.617 52.506 72.157 ;
     RECT  40.215 70.939 41.31 72.301 ;
     RECT  42.228 71.491 42.246 72.301 ;
     RECT  128.808 72.023 128.826 72.413 ;
     RECT  55.728 71.899 56.697 72.535 ;
     RECT  57.528 71.179 57.546 72.535 ;
     RECT  33.624 69.691 33.642 72.661 ;
     RECT  34.488 71.467 35.097 72.661 ;
     RECT  67.215 71.888 67.497 72.661 ;
     RECT  24.015 71.888 24.786 72.697 ;
     RECT  30.456 71.923 30.474 72.697 ;
     RECT  33.624 72.661 35.19 72.697 ;
     RECT  33.624 72.697 35.262 72.701 ;
     RECT  12.636 70.363 13.497 72.715 ;
     RECT  24.015 72.697 24.858 72.733 ;
     RECT  67.215 72.661 67.554 72.733 ;
     RECT  55.728 72.535 57.546 72.761 ;
     RECT  128.232 72.715 128.25 72.761 ;
     RECT  30.456 72.697 30.798 72.797 ;
     RECT  45.615 71.888 45.897 72.811 ;
     RECT  78.015 72.121 127.134 73.075 ;
     RECT  129.492 72.931 129.51 73.085 ;
     RECT  58.104 73.003 58.122 73.099 ;
     RECT  78.015 73.075 127.206 73.229 ;
     RECT  45 72.811 45.897 73.243 ;
     RECT  37.548 70.555 37.566 73.291 ;
     RECT  37.548 73.291 37.926 73.309 ;
     RECT  72.615 71.755 72.954 73.309 ;
     RECT  44.424 73.243 45.897 73.337 ;
     RECT  128.268 73.381 128.286 73.387 ;
     RECT  25.596 73.627 25.614 73.769 ;
     RECT  78.015 73.229 127.134 73.769 ;
     RECT  6.444 73.768 6.462 73.805 ;
     RECT  55.728 72.761 57.042 73.849 ;
     RECT  67.215 72.733 68.238 73.912 ;
     RECT  78.015 73.769 126.954 73.912 ;
     RECT  77.904 73.912 126.954 73.949 ;
     RECT  45.504 73.337 45.897 74.048 ;
     RECT  67.104 73.912 68.238 74.048 ;
     RECT  77.904 73.949 126.897 74.048 ;
     RECT  128.268 73.387 128.826 74.059 ;
     RECT  38.772 73.867 39.15 74.093 ;
     RECT  58.104 73.099 58.698 74.107 ;
     RECT  43.02 74.059 43.038 74.155 ;
     RECT  74.736 74.191 74.754 74.251 ;
     RECT  128.232 74.059 128.826 74.309 ;
     RECT  72.54 73.309 72.954 74.317 ;
     RECT  74.448 74.251 74.754 74.345 ;
     RECT  12.636 72.715 13.914 74.389 ;
     RECT  67.215 74.048 68.238 74.389 ;
     RECT  9.396 73.819 9.414 74.395 ;
     RECT  54.828 69.259 54.846 74.425 ;
     RECT  78.015 74.048 126.897 74.695 ;
     RECT  61.815 2.413 62.097 74.731 ;
     RECT  7.56 71.995 8.097 74.821 ;
     RECT  7.56 74.821 8.19 74.861 ;
     RECT  8.964 74.395 9.414 74.929 ;
     RECT  58.068 74.107 58.698 74.957 ;
     RECT  7.56 74.861 8.097 74.965 ;
     RECT  23.724 72.733 24.858 74.965 ;
     RECT  44.424 73.337 44.658 74.993 ;
     RECT  55.728 73.849 57.078 75.001 ;
     RECT  58.068 74.957 58.122 75.001 ;
     RECT  78.015 74.695 127.026 75.199 ;
     RECT  78.015 75.199 127.314 75.245 ;
     RECT  74.448 74.345 74.466 75.259 ;
     RECT  128.808 74.309 128.826 75.403 ;
     RECT  12.636 74.389 14.598 75.505 ;
     RECT  15.444 75.163 15.462 75.505 ;
     RECT  17.028 75.403 17.046 75.541 ;
     RECT  72.54 74.317 73.602 75.569 ;
     RECT  128.124 75.403 128.826 75.569 ;
     RECT  78.015 75.245 79.758 75.631 ;
     RECT  45.615 74.048 45.897 75.643 ;
     RECT  67.215 74.389 68.418 75.643 ;
     RECT  67.104 75.643 68.418 75.659 ;
     RECT  40.215 72.301 42.246 75.667 ;
     RECT  43.02 74.155 43.614 75.667 ;
     RECT  77.904 75.631 79.758 75.677 ;
     RECT  11.088 69.799 11.538 75.739 ;
     RECT  10.872 75.739 11.538 75.775 ;
     RECT  128.808 75.569 128.826 75.776 ;
     RECT  61.815 74.731 62.73 75.803 ;
     RECT  7.092 74.965 8.097 75.901 ;
     RECT  8.856 74.929 9.414 75.901 ;
     RECT  23.472 74.965 24.858 75.937 ;
     RECT  34.488 72.701 35.262 76.009 ;
     RECT  36.144 70.879 36.162 76.009 ;
     RECT  78.015 75.677 79.758 76.009 ;
     RECT  80.568 75.245 127.314 76.009 ;
     RECT  55.728 75.001 58.122 76.081 ;
     RECT  78.015 76.009 127.314 76.109 ;
     RECT  21.312 73.237 21.33 76.171 ;
     RECT  74.412 75.259 74.466 76.171 ;
     RECT  49.824 75.163 49.842 76.207 ;
     RECT  21.06 76.171 21.33 76.208 ;
     RECT  67.104 75.659 68.238 76.243 ;
     RECT  20.196 74.347 20.214 76.279 ;
     RECT  74.412 76.171 74.718 76.301 ;
     RECT  78.015 76.109 127.242 76.307 ;
     RECT  72.54 75.569 73.566 76.315 ;
     RECT  74.412 76.301 74.682 76.315 ;
     RECT  78.015 76.307 78.894 76.343 ;
     RECT  19.764 76.279 20.214 76.351 ;
     RECT  40.215 75.667 43.614 76.379 ;
     RECT  78.015 76.343 78.822 76.379 ;
     RECT  19.764 76.351 20.286 76.397 ;
     RECT  78.015 76.379 78.786 76.585 ;
     RECT  10.476 75.775 11.538 76.603 ;
     RECT  51.015 2.413 51.297 76.621 ;
     RECT  52.056 72.157 52.506 76.621 ;
     RECT  77.904 76.585 78.786 76.637 ;
     RECT  45.504 75.643 45.897 76.649 ;
     RECT  6.192 73.885 6.21 76.711 ;
     RECT  7.092 75.901 9.414 76.711 ;
     RECT  10.224 76.603 11.538 76.739 ;
     RECT  54.216 74.425 54.846 76.783 ;
     RECT  6.192 76.711 9.414 76.855 ;
     RECT  71.496 71.761 71.514 76.855 ;
     RECT  61.815 75.803 62.097 76.885 ;
     RECT  6.192 76.855 9.45 76.925 ;
     RECT  55.728 76.081 58.662 77.083 ;
     RECT  39.132 74.093 39.15 77.161 ;
     RECT  46.764 77.083 46.782 77.161 ;
     RECT  49.824 76.207 50.202 77.161 ;
     RECT  51.015 76.621 52.506 77.161 ;
     RECT  80.208 76.307 127.242 77.161 ;
     RECT  43.308 76.379 43.614 77.189 ;
     RECT  45.615 76.649 45.897 77.251 ;
     RECT  46.764 77.161 46.854 77.251 ;
     RECT  80.136 77.161 127.242 77.251 ;
     RECT  44.64 74.993 44.658 77.275 ;
     RECT  71.208 76.855 71.514 77.275 ;
     RECT  70.812 77.275 71.514 77.308 ;
     RECT  43.308 77.189 43.362 77.315 ;
     RECT  44.136 77.275 44.658 77.315 ;
     RECT  26.244 74.587 26.262 77.323 ;
     RECT  45.615 77.251 47.214 77.323 ;
     RECT  38.772 77.161 39.15 77.371 ;
     RECT  40.215 76.379 42.426 77.371 ;
     RECT  43.308 77.315 43.326 77.371 ;
     RECT  53.964 76.783 54.846 77.371 ;
     RECT  55.728 77.083 58.734 77.371 ;
     RECT  61.815 76.885 62.19 77.371 ;
     RECT  72.54 76.315 74.682 77.371 ;
     RECT  49.824 77.161 52.506 77.387 ;
     RECT  80.136 77.251 127.962 77.387 ;
     RECT  70.74 77.308 71.514 77.395 ;
     RECT  72.54 77.371 74.79 77.395 ;
     RECT  70.74 77.395 74.79 77.405 ;
     RECT  49.824 77.387 50.274 77.459 ;
     RECT  45.615 77.323 47.286 77.501 ;
     RECT  78.015 76.637 78.786 77.501 ;
     RECT  80.172 77.387 127.962 77.501 ;
     RECT  26.208 77.323 26.262 77.611 ;
     RECT  27.072 70.231 27.09 77.611 ;
     RECT  46.872 77.501 47.286 77.659 ;
     RECT  53.964 77.371 54.954 77.665 ;
     RECT  55.728 77.371 58.842 77.665 ;
     RECT  78.015 77.501 78.678 77.741 ;
     RECT  53.964 77.665 58.842 77.755 ;
     RECT  129.492 76.891 129.51 77.755 ;
     RECT  38.772 77.371 39.402 77.789 ;
     RECT  23.256 75.937 24.858 77.803 ;
     RECT  26.208 77.611 27.09 77.819 ;
     RECT  46.872 77.659 47.862 77.885 ;
     RECT  61.815 77.371 62.802 77.885 ;
     RECT  70.812 77.405 74.79 77.885 ;
     RECT  26.208 77.819 26.262 77.899 ;
     RECT  80.208 77.501 127.962 77.927 ;
     RECT  22.824 77.803 24.858 77.933 ;
     RECT  25.956 77.899 26.262 77.999 ;
     RECT  47.052 77.885 47.862 78.029 ;
     RECT  26.028 77.999 26.262 78.089 ;
     RECT  53.964 77.755 58.878 78.091 ;
     RECT  12.636 75.505 15.462 78.169 ;
     RECT  6.192 76.925 6.21 78.331 ;
     RECT  78.015 77.741 78.426 78.331 ;
     RECT  27.072 77.819 27.09 78.359 ;
     RECT  47.592 78.029 47.862 78.359 ;
     RECT  17.028 75.541 17.694 78.367 ;
     RECT  34.488 76.009 36.162 78.367 ;
     RECT  19.764 76.397 19.926 78.403 ;
     RECT  66.564 76.243 68.238 78.403 ;
     RECT  53.316 78.091 58.878 78.427 ;
     RECT  40.215 77.371 43.326 78.467 ;
     RECT  16.632 78.367 17.694 78.475 ;
     RECT  128.808 77.755 129.51 78.509 ;
     RECT  80.208 77.927 80.226 78.523 ;
     RECT  47.592 78.359 47.61 78.557 ;
     RECT  30.456 72.797 30.474 78.665 ;
     RECT  49.824 77.459 49.986 78.667 ;
     RECT  51.015 77.387 52.506 78.667 ;
     RECT  12.564 78.169 15.462 78.673 ;
     RECT  16.308 78.475 17.694 78.673 ;
     RECT  61.815 77.885 62.097 78.673 ;
     RECT  77.904 78.331 78.426 78.673 ;
     RECT  26.208 78.089 26.262 78.709 ;
     RECT  61.776 78.673 62.097 78.709 ;
     RECT  71.208 77.885 74.466 78.709 ;
     RECT  18.615 2.413 18.897 78.745 ;
     RECT  19.764 78.403 19.998 78.745 ;
     RECT  80.172 78.523 80.226 78.745 ;
     RECT  80.964 77.927 127.962 78.745 ;
     RECT  45.615 77.501 45.897 78.763 ;
     RECT  77.904 78.673 78.678 78.809 ;
     RECT  80.172 78.745 127.962 78.811 ;
     RECT  128.808 78.509 128.898 78.811 ;
     RECT  61.776 78.709 62.73 78.899 ;
     RECT  71.208 78.709 74.682 78.899 ;
     RECT  44.64 77.315 44.658 78.907 ;
     RECT  45.615 78.763 46.602 78.941 ;
     RECT  23.256 77.933 24.858 78.979 ;
     RECT  80.172 78.811 128.898 79.099 ;
     RECT  44.28 78.907 44.658 79.141 ;
     RECT  79.992 79.099 128.898 79.169 ;
     RECT  46.62 79.003 46.638 79.181 ;
     RECT  80.064 79.169 128.898 79.181 ;
     RECT  80.064 79.181 128.862 79.241 ;
     RECT  38.988 77.789 39.402 79.249 ;
     RECT  40.215 78.467 43.11 79.249 ;
     RECT  78.015 78.809 78.678 79.321 ;
     RECT  26.208 78.709 26.874 79.435 ;
     RECT  26.208 79.435 27.09 79.483 ;
     RECT  28.044 78.205 28.062 79.483 ;
     RECT  71.208 78.899 74.466 79.483 ;
     RECT  26.208 79.483 28.062 79.511 ;
     RECT  59.868 79.051 59.886 79.511 ;
     RECT  18.615 78.745 19.998 79.519 ;
     RECT  23.256 78.979 25.11 79.547 ;
     RECT  10.476 76.739 11.538 79.555 ;
     RECT  38.988 79.249 43.11 79.555 ;
     RECT  43.956 79.141 44.658 79.555 ;
     RECT  26.208 79.511 26.262 79.591 ;
     RECT  34.488 78.367 36.378 79.591 ;
     RECT  37.548 73.309 37.998 79.591 ;
     RECT  22.212 79.483 22.23 79.717 ;
     RECT  23.256 79.547 24.858 79.717 ;
     RECT  10.476 79.555 11.682 79.753 ;
     RECT  12.564 78.673 17.694 79.753 ;
     RECT  80.892 79.241 128.862 79.853 ;
     RECT  31.896 79.819 31.914 79.951 ;
     RECT  78.015 79.321 78.75 79.951 ;
     RECT  34.488 79.591 37.998 79.979 ;
     RECT  31.752 79.951 31.914 80.023 ;
     RECT  61.776 78.899 62.622 80.059 ;
     RECT  70.812 79.483 74.466 80.059 ;
     RECT  80.892 79.853 128.826 80.087 ;
     RECT  4.104 79.951 4.122 80.131 ;
     RECT  5.724 78.331 6.21 80.131 ;
     RECT  7.092 76.925 9.45 80.131 ;
     RECT  45.615 78.941 45.897 80.131 ;
     RECT  70.704 80.059 74.466 80.131 ;
     RECT  80.892 80.087 81.378 80.131 ;
     RECT  77.904 79.951 78.75 80.155 ;
     RECT  61.776 80.059 62.73 80.159 ;
     RECT  45.615 80.131 45.99 80.189 ;
     RECT  82.152 80.087 128.826 80.189 ;
     RECT  3.456 80.131 4.122 80.221 ;
     RECT  60.696 77.947 60.714 80.221 ;
     RECT  31.356 80.023 31.914 80.249 ;
     RECT  61.776 80.159 62.262 80.249 ;
     RECT  70.704 80.131 74.682 80.249 ;
     RECT  29.415 2.413 29.697 80.251 ;
     RECT  31.356 80.249 31.59 80.251 ;
     RECT  2.415 47.759 2.697 80.257 ;
     RECT  3.456 80.221 4.77 80.257 ;
     RECT  77.904 80.155 78.894 80.285 ;
     RECT  27.072 79.511 28.062 80.299 ;
     RECT  61.776 80.249 62.097 80.329 ;
     RECT  33.624 72.701 33.642 80.365 ;
     RECT  29.415 80.251 31.59 80.381 ;
     RECT  77.904 80.285 78.786 80.381 ;
     RECT  25.632 79.591 26.262 80.393 ;
     RECT  38.988 79.555 44.658 80.395 ;
     RECT  45.615 80.189 45.897 80.395 ;
     RECT  2.415 80.257 4.77 80.401 ;
     RECT  80.856 80.131 81.378 80.401 ;
     RECT  18.615 79.519 20.502 80.491 ;
     RECT  21.312 76.208 21.33 80.491 ;
     RECT  29.415 80.381 30.33 80.491 ;
     RECT  77.904 80.381 78.426 80.491 ;
     RECT  82.188 80.189 128.286 80.525 ;
     RECT  25.704 80.393 26.262 80.527 ;
     RECT  27.072 80.299 28.206 80.527 ;
     RECT  66.564 78.403 68.562 80.527 ;
     RECT  18.615 80.491 21.33 80.528 ;
     RECT  69.912 73.813 69.93 80.563 ;
     RECT  70.704 80.249 74.466 80.563 ;
     RECT  47.664 79.789 47.682 80.587 ;
     RECT  22.212 79.717 24.858 80.599 ;
     RECT  2.415 80.401 4.806 80.629 ;
     RECT  25.704 80.527 28.314 80.663 ;
     RECT  2.415 80.629 4.842 80.671 ;
     RECT  5.724 80.131 9.45 80.671 ;
     RECT  29.34 80.491 30.33 80.797 ;
     RECT  60.696 80.221 61.002 80.797 ;
     RECT  2.415 80.671 9.45 80.824 ;
     RECT  32.904 80.365 33.642 80.833 ;
     RECT  53.316 78.427 59.058 80.833 ;
     RECT  60.084 80.797 61.002 80.833 ;
     RECT  2.34 80.824 9.45 80.861 ;
     RECT  29.052 80.797 30.33 80.861 ;
     RECT  47.664 80.587 47.79 80.869 ;
     RECT  53.316 80.833 61.002 80.869 ;
     RECT  61.74 80.329 62.097 80.869 ;
     RECT  53.316 80.869 62.097 80.897 ;
     RECT  32.796 80.833 33.642 80.923 ;
     RECT  34.632 79.979 37.998 80.923 ;
     RECT  47.16 80.869 47.79 80.923 ;
     RECT  61.02 80.897 62.097 81.031 ;
     RECT  80.064 79.241 80.082 81.031 ;
     RECT  80.82 80.401 81.378 81.031 ;
     RECT  31.356 80.381 31.59 81.067 ;
     RECT  79.524 81.031 81.378 81.067 ;
     RECT  82.188 80.525 128.25 81.067 ;
     RECT  22.212 80.599 24.966 81.103 ;
     RECT  76.392 80.059 76.41 81.103 ;
     RECT  77.832 80.491 78.426 81.103 ;
     RECT  27.072 80.663 28.314 81.115 ;
     RECT  29.052 80.861 30.186 81.115 ;
     RECT  75.528 81.067 75.546 81.163 ;
     RECT  46.692 80.923 47.79 81.175 ;
     RECT  18.615 80.528 20.502 81.211 ;
     RECT  38.988 80.395 45.897 81.211 ;
     RECT  46.692 81.175 47.862 81.211 ;
     RECT  48.888 78.379 48.906 81.259 ;
     RECT  49.824 78.667 52.506 81.259 ;
     RECT  10.476 79.753 17.694 81.301 ;
     RECT  18.468 81.211 20.502 81.301 ;
     RECT  69.912 80.563 74.466 81.301 ;
     RECT  75.528 81.163 75.654 81.301 ;
     RECT  76.392 81.103 78.426 81.301 ;
     RECT  79.524 81.067 128.25 81.301 ;
     RECT  64.62 81.211 64.638 81.337 ;
     RECT  38.988 81.211 47.862 81.355 ;
     RECT  48.888 81.259 52.506 81.355 ;
     RECT  62.964 81.301 63.414 81.373 ;
     RECT  21.492 81.103 24.966 81.409 ;
     RECT  25.704 80.663 26.262 81.409 ;
     RECT  10.476 81.301 20.502 81.445 ;
     RECT  21.492 81.409 26.262 81.445 ;
     RECT  31.356 81.067 31.662 81.445 ;
     RECT  32.796 80.923 37.998 81.445 ;
     RECT  38.988 81.355 52.506 81.445 ;
     RECT  61.02 81.031 62.154 81.445 ;
     RECT  62.964 81.373 63.522 81.445 ;
     RECT  64.62 81.337 64.674 81.445 ;
     RECT  69.912 81.301 75.654 81.445 ;
     RECT  76.392 81.301 128.25 81.445 ;
     RECT  21.492 81.445 26.298 81.451 ;
     RECT  27.072 81.115 30.186 81.451 ;
     RECT  10.476 81.445 20.574 81.481 ;
     RECT  32.796 81.445 52.506 81.481 ;
     RECT  61.02 81.445 63.846 81.499 ;
     RECT  64.62 81.445 65.142 81.499 ;
     RECT  66.564 80.527 68.958 81.499 ;
     RECT  69.912 81.445 128.25 81.499 ;
     RECT  31.284 81.445 31.662 81.547 ;
     RECT  32.616 81.481 52.506 81.547 ;
     RECT  31.284 81.547 52.506 81.571 ;
     RECT  53.316 80.897 60.102 81.571 ;
     RECT  61.02 81.499 65.286 81.571 ;
     RECT  66.564 81.499 128.25 81.571 ;
     RECT  10.476 81.481 20.646 81.607 ;
     RECT  21.492 81.451 30.186 81.607 ;
     RECT  31.212 81.571 60.102 81.607 ;
     RECT  61.02 81.571 65.43 81.607 ;
     RECT  66.168 81.571 128.25 81.607 ;
     RECT  2.415 80.861 9.45 81.643 ;
     RECT  2.415 81.643 9.666 81.715 ;
     RECT  10.476 81.607 30.186 81.715 ;
     RECT  30.924 81.607 60.102 81.715 ;
     RECT  61.02 81.607 128.25 81.739 ;
     RECT  129.564 81.751 129.582 81.835 ;
     RECT  10.476 81.715 60.102 81.841 ;
     RECT  60.984 81.739 128.25 81.841 ;
     RECT  2.376 81.715 9.666 81.877 ;
     RECT  2.376 81.877 9.738 81.985 ;
     RECT  10.476 81.841 128.25 81.985 ;
     RECT  2.304 81.985 128.25 82.147 ;
     RECT  2.196 82.147 128.25 82.255 ;
     RECT  2.196 82.255 128.466 82.831 ;
     RECT  129.492 81.835 129.582 82.831 ;
     RECT  1.404 82.957 1.422 83.165 ;
     RECT  0.648 82.795 0.666 83.213 ;
     RECT  2.196 82.831 129.582 83.837 ;
     RECT  2.196 83.837 47.178 84.029 ;
     RECT  47.916 83.837 129.582 84.029 ;
     RECT  6.624 84.029 9.738 84.065 ;
     RECT  70.38 84.029 71.802 84.065 ;
     RECT  86.436 84.029 89.802 84.065 ;
     RECT  119.772 84.029 120.294 84.065 ;
     RECT  48.024 84.029 51.21 84.077 ;
     RECT  75.528 84.029 85.698 84.077 ;
     RECT  91.116 84.029 111.69 84.077 ;
     RECT  125.784 84.029 129.582 84.077 ;
     RECT  18.036 84.029 20.178 84.101 ;
     RECT  22.644 84.029 47.178 84.101 ;
     RECT  53.28 84.029 67.698 84.101 ;
     RECT  68.652 84.029 69.498 84.101 ;
     RECT  71.244 84.065 71.802 84.101 ;
     RECT  91.116 84.077 100.782 84.101 ;
     RECT  101.736 84.077 111.69 84.101 ;
     RECT  112.428 84.029 115.905 84.101 ;
     RECT  116.784 84.029 118.962 84.101 ;
     RECT  122.508 84.029 123.138 84.101 ;
     RECT  55.656 84.101 67.698 84.125 ;
     RECT  103.176 84.101 110.754 84.125 ;
     RECT  127.728 84.077 129.582 84.125 ;
     RECT  25.164 84.101 47.178 84.137 ;
     RECT  50.616 84.077 51.21 84.137 ;
     RECT  68.976 84.101 69.498 84.137 ;
     RECT  91.26 84.101 100.782 84.137 ;
     RECT  104.256 84.125 110.754 84.137 ;
     RECT  116.784 84.101 116.802 84.137 ;
     RECT  119.952 84.065 119.97 84.137 ;
     RECT  71.352 84.101 71.802 84.173 ;
     RECT  86.436 84.065 87.534 84.173 ;
     RECT  88.416 84.065 89.694 84.173 ;
     RECT  96.48 84.137 100.782 84.173 ;
     RECT  122.508 84.101 122.598 84.173 ;
     RECT  22.644 84.101 24.354 84.209 ;
     RECT  25.164 84.137 30.762 84.209 ;
     RECT  41.184 84.137 42.606 84.209 ;
     RECT  50.868 84.137 51.21 84.209 ;
     RECT  91.26 84.137 95.49 84.209 ;
     RECT  96.588 84.173 100.782 84.209 ;
     RECT  103.176 84.125 103.194 84.209 ;
     RECT  117.684 84.101 118.962 84.209 ;
     RECT  122.508 84.173 122.526 84.209 ;
     RECT  6.624 84.065 6.75 84.221 ;
     RECT  11.376 84.029 11.394 84.221 ;
     RECT  12.132 84.029 17.01 84.221 ;
     RECT  70.38 84.065 70.398 84.221 ;
     RECT  75.528 84.077 83.682 84.221 ;
     RECT  84.492 84.077 85.698 84.221 ;
     RECT  88.632 84.173 89.694 84.221 ;
     RECT  91.26 84.209 94.878 84.221 ;
     RECT  96.588 84.209 97.902 84.221 ;
     RECT  99.144 84.209 100.782 84.221 ;
     RECT  112.608 84.101 115.905 84.221 ;
     RECT  118.548 84.209 118.962 84.221 ;
     RECT  125.784 84.077 126.81 84.221 ;
     RECT  127.728 84.125 129.51 84.221 ;
     RECT  18.036 84.101 20.142 84.257 ;
     RECT  23.94 84.209 24.105 84.257 ;
     RECT  51.015 84.209 51.21 84.257 ;
     RECT  55.656 84.125 67.41 84.257 ;
     RECT  112.644 84.221 115.905 84.257 ;
     RECT  121.215 84.029 121.374 84.257 ;
     RECT  53.496 84.101 54.918 84.269 ;
     RECT  57.096 84.257 67.41 84.269 ;
     RECT  88.704 84.221 89.082 84.269 ;
     RECT  94.104 84.221 94.41 84.269 ;
     RECT  99.432 84.221 99.882 84.269 ;
     RECT  104.256 84.137 109.458 84.269 ;
     RECT  83.304 84.221 83.682 84.299 ;
     RECT  92.016 84.221 93.042 84.308 ;
     RECT  7.596 84.065 9.738 84.317 ;
     RECT  86.436 84.173 86.85 84.317 ;
     RECT  88.992 84.269 89.046 84.317 ;
     RECT  99.504 84.269 99.81 84.317 ;
     RECT  110.304 84.137 110.754 84.317 ;
     RECT  96.948 84.221 97.506 84.335 ;
     RECT  2.196 84.029 5.85 84.365 ;
     RECT  6.732 84.221 6.75 84.365 ;
     RECT  7.596 84.317 9.09 84.365 ;
     RECT  12.132 84.221 12.15 84.365 ;
     RECT  13.14 84.221 15.138 84.365 ;
     RECT  18.972 84.257 20.142 84.365 ;
     RECT  22.644 84.209 22.662 84.365 ;
     RECT  25.2 84.209 27.054 84.365 ;
     RECT  27.828 84.209 30.762 84.365 ;
     RECT  31.536 84.137 40.374 84.365 ;
     RECT  41.436 84.209 42.606 84.365 ;
     RECT  43.488 84.137 47.178 84.365 ;
     RECT  48.024 84.077 49.482 84.365 ;
     RECT  51.156 84.257 51.21 84.365 ;
     RECT  53.532 84.269 54.918 84.365 ;
     RECT  55.656 84.257 56.142 84.365 ;
     RECT  57.096 84.269 67.374 84.365 ;
     RECT  68.976 84.137 69.138 84.365 ;
     RECT  72.576 84.029 74.754 84.365 ;
     RECT  112.644 84.257 115.758 84.365 ;
     RECT  69.012 84.365 69.138 84.371 ;
     RECT  71.424 84.173 71.802 84.371 ;
     RECT  84.924 84.221 85.698 84.371 ;
     RECT  89.028 84.317 89.046 84.371 ;
     RECT  91.26 84.221 91.278 84.371 ;
     RECT  62.604 84.365 66.006 84.407 ;
     RECT  13.14 84.365 13.158 84.413 ;
     RECT  23.94 84.257 23.958 84.413 ;
     RECT  29.34 84.365 29.358 84.413 ;
     RECT  110.736 84.317 110.754 84.413 ;
     RECT  115.308 84.365 115.758 84.413 ;
     RECT  121.356 84.257 121.374 84.413 ;
     RECT  126.504 84.221 126.81 84.413 ;
     RECT  45.576 84.365 45.774 84.461 ;
     RECT  61.776 84.365 61.794 84.461 ;
     RECT  69.12 84.371 69.138 84.524 ;
     RECT  92.016 84.308 93.006 84.524 ;
     RECT  67.176 84.365 67.194 84.557 ;
     RECT  71.784 84.371 71.802 84.557 ;
     RECT  75.528 84.221 82.422 84.569 ;
     RECT  104.256 84.269 109.35 84.569 ;
     RECT  72.576 84.365 73.53 84.605 ;
     RECT  75.528 84.569 82.098 84.605 ;
     RECT  84.924 84.371 84.942 84.605 ;
     RECT  104.256 84.569 104.274 84.605 ;
     RECT  75.528 84.605 77.202 84.653 ;
     RECT  74.412 84.365 74.754 84.701 ;
     RECT  105.336 84.569 109.35 84.701 ;
     RECT  74.736 84.701 74.754 84.797 ;
     RECT  100.764 84.221 100.782 84.797 ;
     RECT  83.376 84.299 83.574 84.845 ;
     RECT  97.308 84.335 97.506 84.845 ;
     RECT  127.728 84.221 128.934 84.883 ;
     RECT  126.504 84.413 126.522 84.893 ;
     RECT  18.036 84.257 18.198 84.911 ;
     RECT  3.168 84.365 3.654 84.941 ;
     RECT  16.38 84.221 16.974 84.941 ;
     RECT  105.516 84.701 109.35 84.941 ;
     RECT  63.72 84.407 66.006 84.947 ;
     RECT  111.492 84.101 111.69 84.947 ;
     RECT  65.448 84.947 66.006 84.983 ;
     RECT  9.072 84.365 9.09 84.989 ;
     RECT  10.512 84.029 10.53 84.989 ;
     RECT  14.112 84.365 14.13 84.989 ;
     RECT  16.38 84.941 16.398 84.989 ;
     RECT  26.208 84.365 26.226 84.989 ;
     RECT  32.364 84.365 32.382 84.989 ;
     RECT  34.632 84.365 34.65 84.989 ;
     RECT  40.176 84.365 40.194 84.989 ;
     RECT  45.576 84.461 45.594 84.989 ;
     RECT  48.24 84.365 48.258 84.989 ;
     RECT  117.684 84.209 117.702 84.989 ;
     RECT  118.548 84.221 118.566 84.989 ;
     RECT  78.156 84.605 82.098 85.019 ;
     RECT  80.64 85.019 82.098 85.064 ;
     RECT  105.516 84.941 108.774 85.064 ;
     RECT  51.192 84.365 51.21 85.085 ;
     RECT  63.72 84.947 64.35 85.085 ;
     RECT  113.256 84.365 114.534 85.085 ;
     RECT  101.736 84.101 102.402 85.109 ;
     RECT  72.936 84.605 73.53 85.133 ;
     RECT  75.816 84.653 77.202 85.133 ;
     RECT  108.252 85.064 108.774 85.133 ;
     RECT  111.492 84.947 111.618 85.133 ;
     RECT  92.016 84.524 92.826 85.145 ;
     RECT  108.252 85.133 108.45 85.145 ;
     RECT  76.572 85.133 77.202 85.181 ;
     RECT  92.664 85.145 92.826 85.181 ;
     RECT  77.148 85.181 77.202 85.229 ;
     RECT  101.736 85.109 101.754 85.229 ;
     RECT  127.692 84.883 128.934 85.229 ;
     RECT  18.18 84.911 18.198 85.517 ;
     RECT  21.348 84.029 21.366 85.517 ;
     RECT  47.16 84.365 47.178 85.517 ;
     RECT  60.876 84.365 60.894 85.517 ;
     RECT  62.604 84.407 62.622 85.517 ;
     RECT  77.148 85.229 77.166 85.517 ;
     RECT  82.08 85.064 82.098 85.517 ;
     RECT  92.808 85.181 92.826 85.517 ;
     RECT  111.6 85.133 111.618 85.517 ;
     RECT  113.724 85.085 114.534 85.517 ;
     RECT  127.692 85.229 128.25 85.517 ;
     RECT  64.332 85.085 64.35 85.523 ;
     RECT  113.832 85.517 114.534 85.523 ;
     RECT  105.516 85.064 107.19 85.531 ;
     RECT  65.988 84.983 66.006 85.559 ;
     RECT  108.36 85.145 108.45 85.559 ;
     RECT  113.832 85.523 113.85 85.559 ;
     RECT  75.816 85.133 75.834 85.604 ;
     RECT  105.3 85.531 107.19 85.604 ;
     RECT  78.156 85.019 79.794 85.649 ;
     RECT  108.396 85.559 108.45 85.649 ;
     RECT  105.372 85.604 106.218 85.685 ;
     RECT  80.64 85.064 81.018 85.721 ;
     RECT  107.172 85.604 107.19 85.721 ;
     RECT  80.676 85.721 81.018 85.757 ;
     RECT  105.444 85.685 106.218 85.757 ;
     RECT  78.66 85.649 79.794 85.793 ;
     RECT  105.588 85.757 106.218 85.793 ;
     RECT  80.712 85.757 81.018 85.829 ;
     RECT  105.912 85.793 106.218 85.829 ;
     RECT  105.912 85.829 105.93 85.874 ;
     RECT  78.66 85.793 79.182 85.919 ;
     RECT  80.928 85.829 81.018 85.919 ;
     RECT  102.672 85.531 102.69 85.919 ;
     RECT  108.432 85.649 108.45 85.919 ;
     RECT  78.696 85.919 79.182 85.991 ;
     RECT  81 85.919 81.018 85.991 ;
     RECT  79.164 85.991 79.182 86.045 ;
     RECT  124.848 84.029 124.866 86.237 ;
     RECT  3.636 84.941 3.654 86.285 ;
     RECT  5.004 84.365 5.454 86.285 ;
     RECT  20.124 84.365 20.142 86.285 ;
     RECT  30.708 84.365 30.726 86.285 ;
     RECT  35.604 84.365 35.838 86.285 ;
     RECT  49.464 84.365 49.482 86.285 ;
     RECT  59.652 84.365 59.67 86.285 ;
     RECT  73.512 85.133 73.53 86.285 ;
     RECT  85.68 84.371 85.698 86.285 ;
     RECT  97.308 84.845 97.326 86.285 ;
     RECT  115.308 84.413 115.326 86.285 ;
     RECT  128.232 85.517 128.25 86.285 ;
    LAYER M4 ;
     RECT  0.097 43.2 0.137 43.32 ;
     RECT  0.085 82.992 0.593 83.016 ;
     RECT  0.593 82.992 1.621 83.208 ;
     RECT  0.373 80.64 2.149 80.664 ;
     RECT  1.621 82.512 2.252 83.208 ;
     RECT  2.252 82.032 2.293 83.208 ;
     RECT  2.149 80.64 2.329 80.808 ;
     RECT  0.137 43.296 2.408 43.32 ;
     RECT  2.329 80.64 2.408 80.856 ;
     RECT  2.293 82.032 2.408 83.256 ;
     RECT  1.861 84.336 2.408 84.36 ;
     RECT  2.408 2.148 2.512 84.36 ;
     RECT  2.512 2.418 2.704 84.36 ;
     RECT  2.704 43.296 2.873 44.424 ;
     RECT  2.704 80.304 3.157 84.36 ;
     RECT  3.157 80.304 3.443 84.936 ;
     RECT  2.873 44.4 3.836 44.424 ;
     RECT  2.704 46.224 3.845 46.248 ;
     RECT  3.443 80.304 3.881 84.36 ;
     RECT  2.704 48.432 3.923 48.456 ;
     RECT  2.389 86.256 3.923 86.28 ;
     RECT  3.881 80.304 3.953 83.304 ;
     RECT  3.953 80.304 3.961 82.776 ;
     RECT  3.836 44.4 4.205 44.472 ;
     RECT  3.949 47.28 4.277 47.304 ;
     RECT  3.961 80.304 4.673 82.728 ;
     RECT  3.881 84.288 5.42 84.36 ;
     RECT  4.993 86.256 5.465 86.28 ;
     RECT  4.673 80.304 6.217 82.68 ;
     RECT  6.217 80.256 6.361 82.68 ;
     RECT  5.42 83.808 6.361 84.36 ;
     RECT  6.361 80.256 6.689 84.36 ;
     RECT  6.62 76.896 6.707 76.92 ;
     RECT  6.689 80.256 7.801 82.68 ;
     RECT  2.873 43.296 7.808 43.32 ;
     RECT  4.849 44.592 7.808 44.616 ;
     RECT  7.081 58.224 7.808 58.248 ;
     RECT  7.669 72.576 7.808 72.6 ;
     RECT  6.433 73.776 7.808 73.8 ;
     RECT  7.513 74.976 7.808 75 ;
     RECT  6.793 76.752 7.808 76.776 ;
     RECT  5.653 79.2 7.808 79.224 ;
     RECT  7.801 80.256 7.808 82.728 ;
     RECT  6.689 83.808 7.808 84.36 ;
     RECT  7.808 2.148 7.912 84.36 ;
     RECT  7.912 2.418 8.104 84.36 ;
     RECT  8.104 80.256 8.489 84.36 ;
     RECT  8.489 80.256 9.101 83.832 ;
     RECT  9.061 84.96 9.251 84.984 ;
     RECT  9.101 83.808 9.493 83.832 ;
     RECT  9.493 83.808 9.793 84.312 ;
     RECT  9.101 80.256 9.857 82.728 ;
     RECT  9.857 82.704 10.501 82.728 ;
     RECT  9.793 83.808 10.501 83.832 ;
     RECT  10.501 84.96 11.027 84.984 ;
     RECT  10.501 82.704 11.221 83.832 ;
     RECT  9.857 80.256 11.437 81.672 ;
     RECT  11.221 82.704 11.437 84.216 ;
     RECT  11.437 80.256 12.121 84.216 ;
     RECT  12.121 80.256 13.129 84.36 ;
     RECT  8.104 43.296 13.208 43.32 ;
     RECT  8.104 44.592 13.208 44.616 ;
     RECT  8.104 58.368 13.208 58.392 ;
     RECT  11.509 68.112 13.208 68.136 ;
     RECT  12.625 70.368 13.208 70.392 ;
     RECT  8.104 71.856 13.208 72.456 ;
     RECT  8.104 73.776 13.208 76.776 ;
     RECT  8.104 79.2 13.208 79.224 ;
     RECT  13.129 80.256 13.208 84.408 ;
     RECT  13.208 2.148 13.312 84.408 ;
     RECT  13.312 2.418 13.504 84.408 ;
     RECT  13.504 80.256 14.101 84.408 ;
     RECT  14.101 80.256 14.339 84.984 ;
     RECT  13.504 78.96 15.109 79.224 ;
     RECT  14.339 80.256 15.109 84.36 ;
     RECT  15.109 78.96 15.193 84.36 ;
     RECT  15.193 80.256 15.203 84.36 ;
     RECT  15.203 83.808 15.347 84.36 ;
     RECT  13.504 73.776 15.397 76.776 ;
     RECT  15.193 78.96 15.653 79.224 ;
     RECT  15.347 83.808 15.725 84.216 ;
     RECT  15.397 73.776 16.297 77.592 ;
     RECT  15.653 78.96 16.297 78.984 ;
     RECT  15.203 80.256 16.405 82.824 ;
     RECT  15.725 83.808 16.405 83.832 ;
     RECT  16.405 80.256 16.789 83.832 ;
     RECT  16.369 84.96 16.789 84.984 ;
     RECT  16.789 80.256 17.021 84.984 ;
     RECT  17.021 84.912 17.077 84.984 ;
     RECT  17.077 84.912 17.123 85.032 ;
     RECT  17.123 85.008 17.219 85.032 ;
     RECT  17.077 86.256 17.219 86.28 ;
     RECT  17.021 80.256 17.644 83.928 ;
     RECT  18.169 85.488 18.325 85.512 ;
     RECT  18.325 85.392 18.371 85.512 ;
     RECT  13.504 43.296 18.608 43.32 ;
     RECT  13.504 44.592 18.608 44.616 ;
     RECT  13.504 58.368 18.608 58.392 ;
     RECT  13.504 68.112 18.608 68.136 ;
     RECT  13.504 70.368 18.608 72.744 ;
     RECT  16.297 73.776 18.608 78.984 ;
     RECT  17.644 80.256 18.608 83.832 ;
     RECT  18.371 85.392 18.611 85.416 ;
     RECT  18.608 2.148 18.712 84.252 ;
     RECT  18.712 2.418 18.853 84.252 ;
     RECT  18.853 2.418 18.904 84.36 ;
     RECT  18.904 73.776 19.907 84.36 ;
     RECT  20.069 86.256 20.153 86.28 ;
     RECT  19.907 73.776 20.441 83.928 ;
     RECT  20.441 73.776 21.395 83.88 ;
     RECT  21.337 85.488 21.683 85.512 ;
     RECT  21.395 73.776 22.633 83.832 ;
     RECT  22.633 73.776 22.717 84.36 ;
     RECT  18.904 44.592 22.813 44.616 ;
     RECT  22.813 44.592 22.853 44.712 ;
     RECT  22.717 73.776 23.752 83.88 ;
     RECT  23.752 73.776 23.929 83.928 ;
     RECT  18.904 43.296 24.008 43.32 ;
     RECT  22.853 44.688 24.008 44.712 ;
     RECT  18.904 58.368 24.008 58.392 ;
     RECT  18.904 68.112 24.008 68.136 ;
     RECT  18.904 70.368 24.008 72.744 ;
     RECT  23.929 73.776 24.008 84.408 ;
     RECT  24.008 2.148 24.112 84.408 ;
     RECT  24.112 2.418 24.179 84.408 ;
     RECT  24.179 2.418 24.304 83.982 ;
     RECT  24.304 73.776 25.189 83.982 ;
     RECT  25.189 73.776 25.229 84.36 ;
     RECT  24.304 70.368 25.585 72.744 ;
     RECT  25.229 73.776 25.585 83.256 ;
     RECT  25.585 70.368 25.669 83.256 ;
     RECT  25.229 84.288 26.197 84.36 ;
     RECT  26.197 84.288 26.201 84.984 ;
     RECT  26.201 84.336 26.483 84.984 ;
     RECT  25.669 70.368 26.917 82.968 ;
     RECT  26.917 70.368 27.281 83.208 ;
     RECT  24.304 44.688 27.389 44.712 ;
     RECT  27.281 70.368 28.357 82.92 ;
     RECT  26.483 84.336 28.357 84.36 ;
     RECT  28.357 70.368 28.441 84.36 ;
     RECT  28.441 84.288 29.329 84.36 ;
     RECT  24.304 43.296 29.408 43.32 ;
     RECT  28.465 44.88 29.408 44.904 ;
     RECT  24.304 58.368 29.408 58.392 ;
     RECT  24.304 68.112 29.408 68.136 ;
     RECT  28.441 70.368 29.408 83.256 ;
     RECT  29.329 84.288 29.408 84.408 ;
     RECT  29.408 2.148 29.507 84.408 ;
     RECT  29.507 2.148 29.512 84.36 ;
     RECT  29.512 2.418 29.704 84.36 ;
     RECT  30.697 86.256 31.043 86.28 ;
     RECT  29.704 70.368 31.283 84.36 ;
     RECT  31.283 84.336 32.353 84.36 ;
     RECT  32.353 84.336 32.531 84.984 ;
     RECT  32.531 84.336 32.993 84.36 ;
     RECT  31.283 70.368 33.257 83.256 ;
     RECT  32.993 84.288 33.539 84.36 ;
     RECT  33.539 84.336 34.621 84.36 ;
     RECT  29.704 43.296 34.808 43.32 ;
     RECT  29.704 44.88 34.808 44.904 ;
     RECT  29.704 58.368 34.808 58.392 ;
     RECT  29.704 68.112 34.808 68.136 ;
     RECT  33.257 70.368 34.808 83.064 ;
     RECT  34.621 84.336 34.808 84.984 ;
     RECT  34.808 2.148 34.835 84.984 ;
     RECT  34.835 2.148 34.912 84.36 ;
     RECT  34.912 2.418 35.104 84.36 ;
     RECT  35.549 86.256 35.849 86.28 ;
     RECT  35.104 70.368 36.851 84.36 ;
     RECT  36.851 84.336 38.005 84.36 ;
     RECT  36.851 70.368 38.581 83.304 ;
     RECT  38.005 84.288 38.581 84.36 ;
     RECT  38.581 70.368 39.017 84.36 ;
     RECT  39.017 70.368 39.301 83.304 ;
     RECT  39.017 84.336 40.165 84.36 ;
     RECT  35.104 43.296 40.208 43.32 ;
     RECT  35.104 44.88 40.208 44.904 ;
     RECT  35.104 58.368 40.208 58.392 ;
     RECT  35.104 60 40.208 60.024 ;
     RECT  35.104 68.112 40.208 68.136 ;
     RECT  39.301 69.792 40.208 83.304 ;
     RECT  40.165 84.336 40.208 84.984 ;
     RECT  40.208 2.148 40.312 84.984 ;
     RECT  40.312 2.418 40.504 84.984 ;
     RECT  40.504 69.216 40.643 84.984 ;
     RECT  39.733 86.256 40.883 86.28 ;
     RECT  40.643 69.216 43.285 84.36 ;
     RECT  44.677 86.256 44.819 86.28 ;
     RECT  43.285 69.216 45.565 84.408 ;
     RECT  40.504 43.296 45.608 43.32 ;
     RECT  40.504 44.88 45.608 44.904 ;
     RECT  40.504 58.368 45.608 58.392 ;
     RECT  40.504 60 45.608 60.024 ;
     RECT  40.504 68.112 45.608 68.136 ;
     RECT  45.565 69.216 45.608 84.984 ;
     RECT  45.608 2.148 45.712 84.984 ;
     RECT  45.712 2.418 45.904 84.984 ;
     RECT  45.904 69.216 45.971 84.984 ;
     RECT  47.149 85.488 47.507 85.512 ;
     RECT  45.904 60 47.516 60.024 ;
     RECT  47.516 59.52 47.603 60.024 ;
     RECT  45.971 69.216 48.229 84.408 ;
     RECT  47.603 59.616 48.515 60.024 ;
     RECT  48.515 60 49.133 60.024 ;
     RECT  48.229 69.216 50.533 84.984 ;
     RECT  49.189 86.256 50.867 86.28 ;
     RECT  45.904 43.296 51.008 43.32 ;
     RECT  45.904 44.88 51.008 44.904 ;
     RECT  47.557 51.12 51.008 51.144 ;
     RECT  45.904 58.368 51.008 58.392 ;
     RECT  45.904 68.112 51.008 68.136 ;
     RECT  50.533 69.216 51.008 85.032 ;
     RECT  50.869 86.16 51.011 86.184 ;
     RECT  51.008 2.148 51.112 85.032 ;
     RECT  51.112 2.418 51.181 85.032 ;
     RECT  51.181 2.418 51.304 85.08 ;
     RECT  51.304 69.216 51.539 85.08 ;
     RECT  51.973 86.208 52.259 86.232 ;
     RECT  53.269 86.256 53.459 86.28 ;
     RECT  51.304 43.296 56.408 43.32 ;
     RECT  51.304 44.88 56.408 44.904 ;
     RECT  51.304 51.12 56.408 51.144 ;
     RECT  55.789 54.336 56.408 54.36 ;
     RECT  51.304 58.368 56.408 58.392 ;
     RECT  51.304 68.112 56.408 68.136 ;
     RECT  51.539 69.216 56.408 85.032 ;
     RECT  56.408 2.148 56.512 85.032 ;
     RECT  56.512 2.418 56.704 85.032 ;
     RECT  59.641 86.256 59.891 86.28 ;
     RECT  56.704 69.216 60.865 85.032 ;
     RECT  60.865 69.216 61.139 85.512 ;
     RECT  56.704 43.296 61.808 43.32 ;
     RECT  56.704 44.88 61.808 44.904 ;
     RECT  56.704 51.12 61.808 51.144 ;
     RECT  56.704 54.336 61.808 54.36 ;
     RECT  56.704 58.368 61.808 58.392 ;
     RECT  56.704 68.112 61.808 68.136 ;
     RECT  61.139 69.216 61.808 85.032 ;
     RECT  61.808 2.148 61.912 85.032 ;
     RECT  61.912 2.418 62.104 85.032 ;
     RECT  62.104 69.216 62.593 85.032 ;
     RECT  62.593 69.216 62.915 85.512 ;
     RECT  62.104 43.296 63.893 43.32 ;
     RECT  65.401 43.296 65.485 43.32 ;
     RECT  65.173 86.256 65.555 86.28 ;
     RECT  62.104 44.88 67.208 44.904 ;
     RECT  62.104 51.12 67.208 51.144 ;
     RECT  62.104 54.336 67.208 54.36 ;
     RECT  62.104 58.368 67.208 58.392 ;
     RECT  62.104 68.112 67.208 68.136 ;
     RECT  62.915 69.216 67.208 85.08 ;
     RECT  67.208 2.148 67.312 85.08 ;
     RECT  67.312 2.418 67.504 85.08 ;
     RECT  71.989 86.256 72.131 86.28 ;
     RECT  67.504 44.88 72.608 44.904 ;
     RECT  67.504 51.12 72.608 51.144 ;
     RECT  67.504 54.336 72.608 54.36 ;
     RECT  67.504 58.368 72.608 58.392 ;
     RECT  67.504 68.112 72.608 68.136 ;
     RECT  67.504 69.216 72.608 85.08 ;
     RECT  72.608 2.148 72.712 85.08 ;
     RECT  72.469 86.208 72.803 86.232 ;
     RECT  72.712 2.418 72.904 85.08 ;
     RECT  72.904 69.216 72.925 85.08 ;
     RECT  72.925 69.216 73.043 85.128 ;
     RECT  73.501 86.256 73.585 86.28 ;
     RECT  73.043 69.216 76.201 85.08 ;
     RECT  76.201 69.216 76.561 85.128 ;
     RECT  76.561 69.216 77.137 85.176 ;
     RECT  77.077 86.208 77.137 86.232 ;
     RECT  77.137 69.216 77.315 86.232 ;
     RECT  77.315 69.216 77.603 85.512 ;
     RECT  72.904 44.88 78.008 44.904 ;
     RECT  72.904 51.12 78.008 51.144 ;
     RECT  72.904 54.336 78.008 54.36 ;
     RECT  72.904 58.368 78.008 58.392 ;
     RECT  72.904 68.112 78.008 68.136 ;
     RECT  77.603 69.216 78.008 85.224 ;
     RECT  78.008 2.148 78.112 85.224 ;
     RECT  78.112 2.418 78.304 85.224 ;
     RECT  78.325 86.256 78.467 86.28 ;
     RECT  78.304 69.216 79.153 85.224 ;
     RECT  79.153 69.216 79.379 86.04 ;
     RECT  78.304 68.112 80.737 68.136 ;
     RECT  78.304 44.88 80.965 44.904 ;
     RECT  80.737 67.248 81.443 68.136 ;
     RECT  79.379 69.216 82.069 85.224 ;
     RECT  82.069 69.216 82.163 85.512 ;
     RECT  82.789 34.464 83.408 34.488 ;
     RECT  80.965 44.688 83.408 44.904 ;
     RECT  78.304 51.12 83.408 51.144 ;
     RECT  78.304 54.336 83.408 54.36 ;
     RECT  78.304 58.368 83.408 58.392 ;
     RECT  82.645 62.448 83.408 62.472 ;
     RECT  81.013 65.712 83.408 65.736 ;
     RECT  81.443 68.112 83.408 68.136 ;
     RECT  82.163 69.216 83.408 85.224 ;
     RECT  83.408 2.148 83.512 85.224 ;
     RECT  83.512 2.418 83.704 85.224 ;
     RECT  83.704 34.464 84.853 34.488 ;
     RECT  84.517 86.256 85.753 86.28 ;
     RECT  87.541 86.256 87.731 86.28 ;
     RECT  83.704 68.112 87.836 68.136 ;
     RECT  83.704 69.216 87.836 85.224 ;
     RECT  83.704 51.12 88.549 51.144 ;
     RECT  84.805 16.272 88.808 16.296 ;
     RECT  84.853 34.464 88.808 35.064 ;
     RECT  83.704 44.688 88.808 44.712 ;
     RECT  88.549 51.12 88.808 51.288 ;
     RECT  83.704 54.336 88.808 54.36 ;
     RECT  87.253 55.536 88.808 55.56 ;
     RECT  83.704 58.368 88.808 58.392 ;
     RECT  83.704 62.448 88.808 62.472 ;
     RECT  83.704 65.712 88.808 65.736 ;
     RECT  87.836 68.112 88.808 85.224 ;
     RECT  88.808 2.148 88.912 85.224 ;
     RECT  88.912 2.418 89.104 85.224 ;
     RECT  88.933 86.208 89.315 86.232 ;
     RECT  89.104 67.872 89.489 85.224 ;
     RECT  89.461 86.256 89.603 86.28 ;
     RECT  89.104 62.448 90.353 62.472 ;
     RECT  90.349 67.056 90.997 67.08 ;
     RECT  89.489 68.112 90.997 85.224 ;
     RECT  90.997 67.056 91.897 85.224 ;
     RECT  91.237 86.208 92.339 86.232 ;
     RECT  89.104 65.712 92.54 65.976 ;
     RECT  91.897 67.008 92.54 85.224 ;
     RECT  92.54 65.712 92.797 85.224 ;
     RECT  92.797 65.712 93.059 85.512 ;
     RECT  89.104 16.272 94.208 16.296 ;
     RECT  89.104 34.464 94.208 35.064 ;
     RECT  89.104 44.688 94.208 44.712 ;
     RECT  89.104 51.648 94.208 51.672 ;
     RECT  89.104 54.336 94.208 54.36 ;
     RECT  89.104 55.536 94.208 55.56 ;
     RECT  89.104 58.368 94.208 58.392 ;
     RECT  93.059 65.712 94.208 85.224 ;
     RECT  94.069 86.208 94.307 86.232 ;
     RECT  94.208 2.148 94.312 85.224 ;
     RECT  94.312 2.418 94.504 85.224 ;
     RECT  94.504 65.712 97.085 85.224 ;
     RECT  97.085 67.008 97.265 85.224 ;
     RECT  97.253 86.256 97.337 86.28 ;
     RECT  97.085 65.712 99.385 65.976 ;
     RECT  97.265 67.056 99.385 85.224 ;
     RECT  94.504 3.552 99.608 3.576 ;
     RECT  94.504 16.272 99.608 16.296 ;
     RECT  94.504 34.464 99.608 35.064 ;
     RECT  94.504 44.688 99.608 44.712 ;
     RECT  94.504 51.648 99.608 51.672 ;
     RECT  94.504 52.704 99.608 52.728 ;
     RECT  94.504 54.336 99.608 54.36 ;
     RECT  94.504 55.536 99.608 55.56 ;
     RECT  94.504 58.368 99.608 58.392 ;
     RECT  99.385 65.712 99.608 85.224 ;
     RECT  99.608 2.148 99.712 85.224 ;
     RECT  99.712 2.418 99.904 85.224 ;
     RECT  99.829 86.256 100.019 86.28 ;
     RECT  99.904 64.992 100.115 85.224 ;
     RECT  100.115 65.712 101.117 85.224 ;
     RECT  101.117 67.056 101.765 85.224 ;
     RECT  99.904 54.336 101.845 54.36 ;
     RECT  99.904 55.536 101.845 55.56 ;
     RECT  101.845 54.336 102.377 55.56 ;
     RECT  99.904 58.368 102.589 58.392 ;
     RECT  102.589 58.368 102.629 58.488 ;
     RECT  103.237 86.256 104.051 86.28 ;
     RECT  104.053 86.16 104.195 86.184 ;
     RECT  101.765 67.056 104.723 85.176 ;
     RECT  99.904 3.552 105.008 3.576 ;
     RECT  99.904 16.272 105.008 16.296 ;
     RECT  101.125 28.752 105.008 28.776 ;
     RECT  99.904 34.464 105.008 35.064 ;
     RECT  99.904 44.688 105.008 44.712 ;
     RECT  99.904 51.648 105.008 51.672 ;
     RECT  99.904 52.704 105.008 52.728 ;
     RECT  102.377 54.576 105.008 55.56 ;
     RECT  102.629 58.464 105.008 58.488 ;
     RECT  101.117 65.712 105.008 65.976 ;
     RECT  104.723 67.056 105.008 85.128 ;
     RECT  105.008 2.148 105.112 85.128 ;
     RECT  105.112 2.418 105.304 85.128 ;
     RECT  105.304 54.96 105.725 55.56 ;
     RECT  106.021 86.256 106.211 86.28 ;
     RECT  105.304 52.704 106.877 52.728 ;
     RECT  105.304 58.464 107.027 58.488 ;
     RECT  105.304 65.712 107.917 65.976 ;
     RECT  105.304 67.056 107.917 85.128 ;
     RECT  107.917 65.712 108.785 85.128 ;
     RECT  105.304 44.688 108.857 44.712 ;
     RECT  105.304 3.552 110.408 3.576 ;
     RECT  105.304 16.272 110.408 16.296 ;
     RECT  109.525 27.072 110.408 27.096 ;
     RECT  105.304 28.752 110.408 28.776 ;
     RECT  105.304 34.464 110.408 35.064 ;
     RECT  105.304 51.648 110.408 51.672 ;
     RECT  105.725 55.536 110.408 55.56 ;
     RECT  108.785 65.712 110.408 85.08 ;
     RECT  110.408 2.148 110.512 85.08 ;
     RECT  110.293 86.256 110.531 86.28 ;
     RECT  110.512 2.418 110.704 85.08 ;
     RECT  110.704 67.056 111.481 85.08 ;
     RECT  111.481 67.056 111.589 85.128 ;
     RECT  111.589 67.056 112.019 85.512 ;
     RECT  110.704 65.712 112.069 65.976 ;
     RECT  112.019 67.056 112.307 85.128 ;
     RECT  112.307 67.056 113.713 85.08 ;
     RECT  112.069 64.944 113.717 65.976 ;
     RECT  113.713 67.056 114.035 85.512 ;
     RECT  110.704 34.464 114.293 35.064 ;
     RECT  112.165 58.368 114.577 58.392 ;
     RECT  114.577 58.224 114.617 58.392 ;
     RECT  115.253 86.256 115.337 86.28 ;
     RECT  114.035 67.056 115.667 85.032 ;
     RECT  110.704 3.552 115.808 3.576 ;
     RECT  110.704 16.272 115.808 16.296 ;
     RECT  110.704 27.072 115.808 27.096 ;
     RECT  110.704 28.752 115.808 28.776 ;
     RECT  114.293 35.04 115.808 35.064 ;
     RECT  110.704 51.648 115.808 51.672 ;
     RECT  110.704 55.536 115.808 55.56 ;
     RECT  114.617 58.224 115.808 58.248 ;
     RECT  113.717 65.712 115.808 65.976 ;
     RECT  115.667 67.056 115.808 84.984 ;
     RECT  115.808 2.148 115.912 84.984 ;
     RECT  115.912 2.418 116.104 84.984 ;
     RECT  116.053 86.208 116.291 86.232 ;
     RECT  116.104 58.224 118.325 58.248 ;
     RECT  116.104 67.056 118.595 84.984 ;
     RECT  118.595 67.056 119.747 84.456 ;
     RECT  116.104 16.272 120.017 16.296 ;
     RECT  116.104 3.552 120.337 3.576 ;
     RECT  120.337 3.552 120.445 4.152 ;
     RECT  120.325 86.256 120.515 86.28 ;
     RECT  116.104 35.04 120.553 35.064 ;
     RECT  116.104 27.072 121.057 27.096 ;
     RECT  116.104 28.752 121.165 28.776 ;
     RECT  120.445 2.784 121.208 4.152 ;
     RECT  120.481 8.256 121.208 8.28 ;
     RECT  120.625 14.928 121.208 14.952 ;
     RECT  120.337 22.752 121.208 22.776 ;
     RECT  120.625 24.48 121.208 24.504 ;
     RECT  121.057 26.64 121.208 27.096 ;
     RECT  121.165 28.416 121.208 28.776 ;
     RECT  120.877 32.304 121.208 32.328 ;
     RECT  120.553 34.896 121.208 35.064 ;
     RECT  120.445 39.072 121.208 39.096 ;
     RECT  120.985 41.664 121.208 41.688 ;
     RECT  120.337 44.448 121.208 44.472 ;
     RECT  121.093 47.424 121.208 47.448 ;
     RECT  120.229 50.112 121.208 50.136 ;
     RECT  116.104 51.648 121.208 51.672 ;
     RECT  120.733 53.904 121.208 53.928 ;
     RECT  116.104 55.536 121.208 55.56 ;
     RECT  120.445 58.128 121.208 58.152 ;
     RECT  116.104 65.712 121.208 65.976 ;
     RECT  119.747 67.056 121.208 84.024 ;
     RECT  121.208 2.148 121.312 84.252 ;
     RECT  121.312 2.418 121.333 84.252 ;
     RECT  121.333 2.418 121.42 84.408 ;
     RECT  121.42 2.418 121.504 83.982 ;
     RECT  121.504 67.056 121.565 83.88 ;
     RECT  121.504 7.92 121.619 9.24 ;
     RECT  121.504 39.072 121.619 39.096 ;
     RECT  121.504 41.664 121.619 41.688 ;
     RECT  121.504 40.464 121.66 40.536 ;
     RECT  121.504 2.784 121.709 4.152 ;
     RECT  121.504 10.608 121.717 10.632 ;
     RECT  121.504 20.496 121.763 20.52 ;
     RECT  121.621 86.256 121.763 86.28 ;
     RECT  121.504 5.568 121.817 5.592 ;
     RECT  121.565 70.08 122.069 83.88 ;
     RECT  121.504 46.08 122.099 47.448 ;
     RECT  121.504 22.704 122.21 22.776 ;
     RECT  121.504 21.552 122.249 21.576 ;
     RECT  121.504 17.616 122.291 18.408 ;
     RECT  121.504 53.904 122.321 53.928 ;
     RECT  121.504 26.64 122.429 30.888 ;
     RECT  121.504 56.928 122.465 56.952 ;
     RECT  121.504 32.304 122.497 32.328 ;
     RECT  122.429 30 122.531 30.888 ;
     RECT  122.069 70.224 122.531 83.88 ;
     RECT  121.504 24.48 122.533 24.504 ;
     RECT  121.504 33.648 122.533 35.064 ;
     RECT  121.504 14.928 122.537 14.952 ;
     RECT  121.504 16.128 122.537 16.152 ;
     RECT  121.504 58.128 122.537 58.968 ;
     RECT  121.504 50.112 122.561 50.136 ;
     RECT  121.504 51.648 122.561 52.44 ;
     RECT  121.504 43.296 122.579 43.32 ;
     RECT  122.581 48.384 122.613 48.408 ;
     RECT  121.504 44.448 122.636 44.472 ;
     RECT  122.099 46.08 122.636 46.824 ;
     RECT  122.531 30 122.645 30.792 ;
     RECT  122.561 50.112 122.645 52.44 ;
     RECT  122.645 50.112 122.675 50.136 ;
     RECT  121.565 67.056 122.681 68.664 ;
     RECT  121.504 36.384 122.717 36.408 ;
     RECT  122.613 48.384 122.717 48.504 ;
     RECT  122.645 51.648 122.717 52.44 ;
     RECT  122.636 44.448 122.723 46.824 ;
     RECT  121.66 40.464 122.735 40.488 ;
     RECT  121.504 6.672 122.753 6.696 ;
     RECT  121.504 25.632 122.773 25.656 ;
     RECT  122.429 26.64 122.773 28.776 ;
     RECT  122.533 33.36 122.789 35.064 ;
     RECT  122.723 46.176 122.819 46.824 ;
     RECT  121.709 3.552 122.821 4.152 ;
     RECT  121.504 55.536 122.825 55.56 ;
     RECT  122.821 3.408 122.828 4.152 ;
     RECT  122.789 34.224 122.828 35.064 ;
     RECT  121.619 8.544 122.849 9.24 ;
     RECT  122.773 25.632 122.86 28.776 ;
     RECT  121.504 65.712 122.861 65.976 ;
     RECT  122.849 8.544 122.865 9.72 ;
     RECT  122.717 51.648 122.867 51.672 ;
     RECT  122.735 40.464 122.893 41.064 ;
     RECT  122.828 3.408 122.915 4.536 ;
     RECT  122.893 39.888 122.915 41.064 ;
     RECT  122.291 18.384 122.924 18.408 ;
     RECT  122.865 8.448 122.933 9.72 ;
     RECT  122.915 39.888 122.933 40.488 ;
     RECT  122.933 8.448 123.011 8.856 ;
     RECT  122.965 13.776 123.037 13.8 ;
     RECT  122.533 24.48 123.061 24.6 ;
     RECT  122.819 46.704 123.068 46.824 ;
     RECT  121.504 63.216 123.073 63.24 ;
     RECT  122.531 70.848 123.073 83.88 ;
     RECT  122.86 27.072 123.077 28.776 ;
     RECT  122.537 58.896 123.077 58.968 ;
     RECT  122.924 18.384 123.107 19.368 ;
     RECT  122.717 48.48 123.109 48.504 ;
     RECT  123.037 13.776 123.113 14.136 ;
     RECT  122.645 30 123.113 30.216 ;
     RECT  123.061 23.76 123.148 24.6 ;
     RECT  123.011 8.832 123.185 8.856 ;
     RECT  122.821 57.024 123.185 57.048 ;
     RECT  123.109 48.48 123.193 49.032 ;
     RECT  123.077 28.752 123.221 28.776 ;
     RECT  122.497 32.064 123.253 32.328 ;
     RECT  123.073 62.592 123.299 63.24 ;
     RECT  122.681 67.056 123.299 68.376 ;
     RECT  121.504 11.808 123.329 11.832 ;
     RECT  123.26 60.384 123.347 60.408 ;
     RECT  122.933 39.888 123.433 39.912 ;
     RECT  123.299 62.64 123.443 63.24 ;
     RECT  123.433 39.696 123.473 39.912 ;
     RECT  123.301 61.584 123.473 61.608 ;
     RECT  123.443 62.64 123.473 62.664 ;
     RECT  122.21 22.704 123.544 22.728 ;
     RECT  123.544 22.704 123.545 22.776 ;
     RECT  123.068 46.704 123.587 47.256 ;
     RECT  122.861 65.712 123.617 65.736 ;
     RECT  123.545 22.752 123.637 22.776 ;
     RECT  123.148 23.76 123.637 23.88 ;
     RECT  122.677 42.672 123.649 42.696 ;
     RECT  123.637 22.752 123.683 23.88 ;
     RECT  123.107 18.384 123.757 18.408 ;
     RECT  123.757 18.192 123.797 18.408 ;
     RECT  122.677 37.536 123.797 37.56 ;
     RECT  123.74 15.648 123.827 15.672 ;
     RECT  123.073 70.848 123.833 83.928 ;
     RECT  123.299 67.056 123.941 67.32 ;
     RECT  123.577 10.8 123.973 10.824 ;
     RECT  123.941 67.296 123.977 67.32 ;
     RECT  123.077 58.896 124.009 58.92 ;
     RECT  123.925 53.568 124.012 53.592 ;
     RECT  122.677 21.264 124.013 21.288 ;
     RECT  123.932 38.592 124.019 38.616 ;
     RECT  123.973 40.8 124.085 40.824 ;
     RECT  123.113 30.192 124.109 30.216 ;
     RECT  124.009 58.656 124.115 58.92 ;
     RECT  124.109 30.192 124.117 30.744 ;
     RECT  123.253 32.064 124.117 32.472 ;
     RECT  123.113 14.112 124.157 14.136 ;
     RECT  124.117 30.192 124.163 32.472 ;
     RECT  123.649 42.192 124.172 42.696 ;
     RECT  122.723 44.448 124.172 44.472 ;
     RECT  123.193 48.48 124.172 48.504 ;
     RECT  122.915 3.408 124.193 3.576 ;
     RECT  122.86 25.632 124.193 25.656 ;
     RECT  124.163 30.192 124.193 31.656 ;
     RECT  124.172 48.48 124.213 48.888 ;
     RECT  123.833 72.24 124.213 83.928 ;
     RECT  123.683 23.232 124.229 23.256 ;
     RECT  123.587 46.704 124.229 46.728 ;
     RECT  124.172 42.192 124.259 44.856 ;
     RECT  124.213 47.856 124.259 48.888 ;
     RECT  122.929 4.8 124.261 4.824 ;
     RECT  123.649 50.736 124.261 50.76 ;
     RECT  124.165 40.992 124.265 41.016 ;
     RECT  124.259 42.192 124.265 42.216 ;
     RECT  122.828 34.224 124.301 35.88 ;
     RECT  124.261 4.8 124.307 5.736 ;
     RECT  124.261 50.4 124.307 50.76 ;
     RECT  123.077 27.072 124.337 27.096 ;
     RECT  124.301 35.04 124.373 35.88 ;
     RECT  123.833 70.848 124.373 71.064 ;
     RECT  123.299 68.352 124.409 68.376 ;
     RECT  124.333 38.16 124.417 38.184 ;
     RECT  124.307 5.712 124.445 5.736 ;
     RECT  124.309 86.256 124.451 86.28 ;
     RECT  124.009 57.552 124.501 57.576 ;
     RECT  124.193 3.552 124.517 3.576 ;
     RECT  123.757 54.672 124.547 54.696 ;
     RECT  124.501 57.024 124.553 57.576 ;
     RECT  124.553 57.024 124.588 57.048 ;
     RECT  123.577 12.864 124.661 12.888 ;
     RECT  124.373 35.856 124.697 35.88 ;
     RECT  123.973 10.8 124.721 10.92 ;
     RECT  124.721 10.224 124.805 10.92 ;
     RECT  124.193 31.632 124.805 31.656 ;
     RECT  124.259 47.856 124.805 47.88 ;
     RECT  123.081 64.32 124.805 64.344 ;
     RECT  124.373 70.848 124.805 70.872 ;
     RECT  123.797 18.192 124.877 18.216 ;
     RECT  124.501 55.92 124.877 55.944 ;
     RECT  123.649 65.52 124.877 65.544 ;
     RECT  124.621 29.088 124.913 29.112 ;
     RECT  123.473 39.696 124.913 39.72 ;
     RECT  124.213 72.24 124.913 84.552 ;
     RECT  124.837 86.208 124.933 86.232 ;
     RECT  124.913 72.336 124.949 84.552 ;
     RECT  124.949 73.344 124.985 84.552 ;
     RECT  124.949 72.336 125.065 72.36 ;
     RECT  124.115 58.704 125.093 58.728 ;
     RECT  124.307 50.4 125.165 50.424 ;
     RECT  124.985 73.488 125.201 84.552 ;
     RECT  123.253 19.68 125.237 19.944 ;
     RECT  125.201 73.488 125.237 73.512 ;
     RECT  124.805 10.896 125.273 10.92 ;
     RECT  125.201 78.528 125.315 84.552 ;
     RECT  125.237 19.68 125.381 19.704 ;
     RECT  125.201 74.64 125.381 77.448 ;
     RECT  125.381 75.12 126.421 77.448 ;
     RECT  125.315 78.576 126.421 84.552 ;
     RECT  126.421 75.12 126.493 84.552 ;
     RECT  124.933 85.536 126.493 86.232 ;
     RECT  126.493 75.12 126.608 86.232 ;
     RECT  126.608 2.148 126.712 86.232 ;
     RECT  126.712 2.418 126.901 86.232 ;
     RECT  126.901 2.418 126.904 86.28 ;
     RECT  126.904 79.488 127.043 86.28 ;
     RECT  126.904 76.08 127.181 78.12 ;
     RECT  127.043 79.488 127.181 79.56 ;
     RECT  126.493 0.48 127.933 0.504 ;
     RECT  127.933 0.144 127.969 0.504 ;
     RECT  127.969 0.144 128.041 0.84 ;
     RECT  126.904 18.72 128.077 18.744 ;
     RECT  127.181 76.08 128.113 77.112 ;
     RECT  127.043 80.832 128.177 86.232 ;
     RECT  126.904 28.848 128.185 28.872 ;
     RECT  126.904 46.08 128.185 46.776 ;
     RECT  126.904 52.128 128.185 52.152 ;
     RECT  128.185 4.56 128.221 4.584 ;
     RECT  128.077 18.384 128.221 18.744 ;
     RECT  126.904 22.416 128.221 22.44 ;
     RECT  126.904 25.152 128.221 25.176 ;
     RECT  126.904 26.496 128.221 26.52 ;
     RECT  126.904 27.84 128.221 27.864 ;
     RECT  126.904 31.536 128.221 31.56 ;
     RECT  128.185 34.56 128.221 34.584 ;
     RECT  126.904 35.952 128.221 35.976 ;
     RECT  128.185 52.128 128.221 52.824 ;
     RECT  128.185 55.488 128.221 55.512 ;
     RECT  128.185 56.496 128.221 56.52 ;
     RECT  128.185 59.232 128.221 59.256 ;
     RECT  126.904 62.928 128.221 62.952 ;
     RECT  128.185 68.016 128.221 68.04 ;
     RECT  127.181 78.096 128.221 78.12 ;
     RECT  127.181 79.488 128.221 79.512 ;
     RECT  128.221 8.256 128.257 8.28 ;
     RECT  128.149 9.264 128.257 9.288 ;
     RECT  128.221 15.024 128.257 15.048 ;
     RECT  128.221 22.08 128.257 22.44 ;
     RECT  128.221 30.864 128.257 32.232 ;
     RECT  128.221 34.56 128.257 36.648 ;
     RECT  126.904 41.664 128.257 41.688 ;
     RECT  128.221 43.68 128.257 43.704 ;
     RECT  128.185 45.36 128.257 46.776 ;
     RECT  128.221 48.768 128.257 48.792 ;
     RECT  128.185 49.776 128.257 50.472 ;
     RECT  128.221 55.488 128.257 56.52 ;
     RECT  128.221 60.576 128.257 60.936 ;
     RECT  128.221 65.28 128.257 65.304 ;
     RECT  126.904 70.704 128.257 70.728 ;
     RECT  128.221 74.064 128.257 74.088 ;
     RECT  128.177 80.832 128.257 86.28 ;
     RECT  128.257 80.496 128.261 86.28 ;
     RECT  128.185 28.848 128.329 29.208 ;
     RECT  128.257 30.528 128.329 32.568 ;
     RECT  128.221 4.56 128.725 4.92 ;
     RECT  128.725 4.224 128.761 4.92 ;
     RECT  128.185 11.952 128.761 11.976 ;
     RECT  128.221 20.064 128.761 20.088 ;
     RECT  126.904 39.984 128.761 40.008 ;
     RECT  128.077 2.88 128.797 2.904 ;
     RECT  128.761 3.888 128.797 4.92 ;
     RECT  128.221 5.904 128.797 6.6 ;
     RECT  128.257 8.256 128.797 9.288 ;
     RECT  128.761 11.616 128.797 11.976 ;
     RECT  128.221 13.296 128.797 13.32 ;
     RECT  128.257 14.352 128.797 15.048 ;
     RECT  128.221 16.032 128.797 18.744 ;
     RECT  128.761 19.728 128.797 20.088 ;
     RECT  128.257 21.408 128.797 22.44 ;
     RECT  128.185 23.76 128.797 23.784 ;
     RECT  128.221 25.152 128.797 26.52 ;
     RECT  128.221 27.504 128.797 27.864 ;
     RECT  128.329 28.848 128.797 32.568 ;
     RECT  128.221 33.552 128.797 33.576 ;
     RECT  128.257 34.56 128.797 36.984 ;
     RECT  128.221 38.304 128.797 38.328 ;
     RECT  128.761 39.648 128.797 40.008 ;
     RECT  128.257 41.328 128.797 41.688 ;
     RECT  128.185 42.672 128.797 42.696 ;
     RECT  128.257 43.68 128.797 44.04 ;
     RECT  128.257 45.36 128.797 47.448 ;
     RECT  128.257 48.768 128.797 50.472 ;
     RECT  128.221 51.792 128.797 52.824 ;
     RECT  128.221 53.808 128.797 53.832 ;
     RECT  128.257 54.816 128.797 56.52 ;
     RECT  128.185 57.552 128.797 57.576 ;
     RECT  128.221 58.56 128.797 59.256 ;
     RECT  128.257 60.24 128.797 60.936 ;
     RECT  128.221 62.256 128.797 62.952 ;
     RECT  128.257 63.936 128.797 63.96 ;
     RECT  128.257 65.28 128.797 65.64 ;
     RECT  128.221 67.296 128.797 68.04 ;
     RECT  128.257 69.36 128.797 69.384 ;
     RECT  128.257 70.704 128.797 71.064 ;
     RECT  128.221 72.72 128.797 72.744 ;
     RECT  128.257 73.728 128.797 74.088 ;
     RECT  128.113 75.408 128.797 77.112 ;
     RECT  128.221 78.096 128.797 79.512 ;
     RECT  128.261 80.496 128.797 86.232 ;
     RECT  128.797 2.88 129.409 9.624 ;
     RECT  128.041 0.144 129.445 1.176 ;
     RECT  129.409 2.16 129.445 9.624 ;
     RECT  129.445 0.144 129.481 9.624 ;
     RECT  128.797 10.608 129.481 13.32 ;
     RECT  128.797 14.352 129.481 86.232 ;
     RECT  129.481 0.144 129.516 0.168 ;
     RECT  129.481 0.168 129.564 0.48 ;
     RECT  129.481 0.48 129.516 0.504 ;
     RECT  129.481 0.504 129.564 0.816 ;
     RECT  129.481 0.816 129.516 0.84 ;
     RECT  129.481 0.84 129.564 1.152 ;
     RECT  129.481 1.152 129.516 1.176 ;
     RECT  129.481 1.176 129.564 1.488 ;
     RECT  129.481 1.488 129.516 1.512 ;
     RECT  129.481 1.512 129.564 1.824 ;
     RECT  129.481 1.824 129.516 1.848 ;
     RECT  129.481 1.848 129.564 2.16 ;
     RECT  129.481 2.16 129.516 2.184 ;
     RECT  129.481 2.184 129.564 2.496 ;
     RECT  129.481 2.496 129.516 2.52 ;
     RECT  129.481 2.52 129.564 2.88 ;
     RECT  129.481 2.88 129.516 2.904 ;
     RECT  129.481 2.904 129.564 3.216 ;
     RECT  129.481 3.216 129.516 3.24 ;
     RECT  129.481 3.24 129.564 3.552 ;
     RECT  129.481 3.552 129.516 3.576 ;
     RECT  129.481 3.576 129.564 3.888 ;
     RECT  129.481 3.888 129.516 3.912 ;
     RECT  129.481 3.912 129.564 4.224 ;
     RECT  129.481 4.224 129.516 4.248 ;
     RECT  129.481 4.248 129.564 4.56 ;
     RECT  129.481 4.56 129.516 4.584 ;
     RECT  129.481 4.584 129.564 4.896 ;
     RECT  129.481 4.896 129.516 4.92 ;
     RECT  129.481 4.92 129.564 5.232 ;
     RECT  129.481 5.232 129.516 5.256 ;
     RECT  129.481 5.256 129.564 5.568 ;
     RECT  129.481 5.568 129.516 5.592 ;
     RECT  129.481 5.592 129.564 5.904 ;
     RECT  129.481 5.904 129.516 5.928 ;
     RECT  129.481 5.928 129.564 6.24 ;
     RECT  129.481 6.24 129.516 6.264 ;
     RECT  129.481 6.264 129.564 6.576 ;
     RECT  129.481 6.576 129.516 6.6 ;
     RECT  129.481 6.6 129.564 6.912 ;
     RECT  129.481 6.912 129.516 6.936 ;
     RECT  129.481 6.936 129.564 7.248 ;
     RECT  129.481 7.248 129.516 7.272 ;
     RECT  129.481 7.272 129.564 7.584 ;
     RECT  129.481 7.584 129.516 7.608 ;
     RECT  129.481 7.608 129.564 7.92 ;
     RECT  129.481 7.92 129.516 7.944 ;
     RECT  129.481 7.944 129.564 8.256 ;
     RECT  129.481 8.256 129.516 8.28 ;
     RECT  129.481 8.28 129.564 8.592 ;
     RECT  129.481 8.592 129.516 8.616 ;
     RECT  129.481 8.616 129.564 8.928 ;
     RECT  129.481 8.928 129.516 8.952 ;
     RECT  129.481 8.952 129.564 9.264 ;
     RECT  129.481 9.264 129.516 9.288 ;
     RECT  129.481 9.288 129.564 9.6 ;
     RECT  129.481 9.6 129.516 9.624 ;
     RECT  129.481 9.624 129.564 9.936 ;
     RECT  129.481 9.936 129.516 9.96 ;
     RECT  129.481 9.96 129.564 10.272 ;
     RECT  129.481 10.272 129.516 10.296 ;
     RECT  129.481 10.296 129.564 10.608 ;
     RECT  129.481 10.608 129.516 10.632 ;
     RECT  129.481 10.632 129.564 10.944 ;
     RECT  129.481 10.944 129.516 10.968 ;
     RECT  129.481 10.968 129.564 11.28 ;
     RECT  129.481 11.28 129.516 11.304 ;
     RECT  129.481 11.304 129.564 11.616 ;
     RECT  129.481 11.616 129.516 11.64 ;
     RECT  129.481 11.64 129.564 11.952 ;
     RECT  129.481 11.952 129.516 11.976 ;
     RECT  129.481 11.976 129.564 12.288 ;
     RECT  129.481 12.288 129.516 12.312 ;
     RECT  129.481 12.312 129.564 12.624 ;
     RECT  129.481 12.624 129.516 12.648 ;
     RECT  129.481 12.648 129.564 12.96 ;
     RECT  129.481 12.96 129.516 12.984 ;
     RECT  129.481 12.984 129.564 13.296 ;
     RECT  129.481 13.296 129.516 13.32 ;
     RECT  129.481 13.32 129.564 13.68 ;
     RECT  129.481 13.68 129.516 13.704 ;
     RECT  129.481 13.704 129.564 14.016 ;
     RECT  129.481 14.016 129.516 14.04 ;
     RECT  129.481 14.04 129.564 14.352 ;
     RECT  129.481 14.352 129.516 14.376 ;
     RECT  129.481 14.376 129.564 14.688 ;
     RECT  129.481 14.688 129.516 14.712 ;
     RECT  129.481 14.712 129.564 15.024 ;
     RECT  129.481 15.024 129.516 15.048 ;
     RECT  129.481 15.048 129.564 15.36 ;
     RECT  129.481 15.36 129.516 15.384 ;
     RECT  129.481 15.384 129.564 15.696 ;
     RECT  129.481 15.696 129.516 15.72 ;
     RECT  129.481 15.72 129.564 16.032 ;
     RECT  129.481 16.032 129.516 16.056 ;
     RECT  129.481 16.056 129.564 16.368 ;
     RECT  129.481 16.368 129.516 16.392 ;
     RECT  129.481 16.392 129.564 16.704 ;
     RECT  129.481 16.704 129.516 16.728 ;
     RECT  129.481 16.728 129.564 17.04 ;
     RECT  129.481 17.04 129.516 17.064 ;
     RECT  129.481 17.064 129.564 17.376 ;
     RECT  129.481 17.376 129.516 17.4 ;
     RECT  129.481 17.4 129.564 17.712 ;
     RECT  129.481 17.712 129.516 17.736 ;
     RECT  129.481 17.736 129.564 18.048 ;
     RECT  129.481 18.048 129.516 18.072 ;
     RECT  129.481 18.072 129.564 18.384 ;
     RECT  129.481 18.384 129.516 18.408 ;
     RECT  129.481 18.408 129.564 18.72 ;
     RECT  129.481 18.72 129.516 18.744 ;
     RECT  129.481 18.744 129.564 19.056 ;
     RECT  129.481 19.056 129.516 19.08 ;
     RECT  129.481 19.08 129.564 19.392 ;
     RECT  129.481 19.392 129.516 19.416 ;
     RECT  129.481 19.416 129.564 19.728 ;
     RECT  129.481 19.728 129.516 19.752 ;
     RECT  129.481 19.752 129.564 20.064 ;
     RECT  129.481 20.064 129.516 20.088 ;
     RECT  129.481 20.088 129.564 20.4 ;
     RECT  129.481 20.4 129.516 20.424 ;
     RECT  129.481 20.424 129.564 20.736 ;
     RECT  129.481 20.736 129.516 20.76 ;
     RECT  129.481 20.76 129.564 21.072 ;
     RECT  129.481 21.072 129.516 21.096 ;
     RECT  129.481 21.096 129.564 21.408 ;
     RECT  129.481 21.408 129.516 21.432 ;
     RECT  129.481 21.432 129.564 21.744 ;
     RECT  129.481 21.744 129.516 21.768 ;
     RECT  129.481 21.768 129.564 22.08 ;
     RECT  129.481 22.08 129.516 22.104 ;
     RECT  129.481 22.104 129.564 22.416 ;
     RECT  129.481 22.416 129.516 22.44 ;
     RECT  129.481 22.44 129.564 22.752 ;
     RECT  129.481 22.752 129.516 22.776 ;
     RECT  129.481 22.776 129.564 23.088 ;
     RECT  129.481 23.088 129.516 23.112 ;
     RECT  129.481 23.112 129.564 23.424 ;
     RECT  129.481 23.424 129.516 23.448 ;
     RECT  129.481 23.448 129.564 23.76 ;
     RECT  129.481 23.76 129.516 23.784 ;
     RECT  129.481 23.784 129.564 24.096 ;
     RECT  129.481 24.096 129.516 24.12 ;
     RECT  129.481 24.12 129.564 24.48 ;
     RECT  129.481 24.48 129.516 24.504 ;
     RECT  129.481 24.504 129.564 24.816 ;
     RECT  129.481 24.816 129.516 24.84 ;
     RECT  129.481 24.84 129.564 25.152 ;
     RECT  129.481 25.152 129.516 25.176 ;
     RECT  129.481 25.176 129.564 25.488 ;
     RECT  129.481 25.488 129.516 25.512 ;
     RECT  129.481 25.512 129.564 25.824 ;
     RECT  129.481 25.824 129.516 25.848 ;
     RECT  129.481 25.848 129.564 26.16 ;
     RECT  129.481 26.16 129.516 26.184 ;
     RECT  129.481 26.184 129.564 26.496 ;
     RECT  129.481 26.496 129.516 26.52 ;
     RECT  129.481 26.52 129.564 26.832 ;
     RECT  129.481 26.832 129.516 26.856 ;
     RECT  129.481 26.856 129.564 27.168 ;
     RECT  129.481 27.168 129.516 27.192 ;
     RECT  129.481 27.192 129.564 27.504 ;
     RECT  129.481 27.504 129.516 27.528 ;
     RECT  129.481 27.528 129.564 27.84 ;
     RECT  129.481 27.84 129.516 27.864 ;
     RECT  129.481 27.864 129.564 28.176 ;
     RECT  129.481 28.176 129.516 28.2 ;
     RECT  129.481 28.2 129.564 28.512 ;
     RECT  129.481 28.512 129.516 28.536 ;
     RECT  129.481 28.536 129.564 28.848 ;
     RECT  129.481 28.848 129.516 28.872 ;
     RECT  129.481 28.872 129.564 29.184 ;
     RECT  129.481 29.184 129.516 29.208 ;
     RECT  129.481 29.208 129.564 29.52 ;
     RECT  129.481 29.52 129.516 29.544 ;
     RECT  129.481 29.544 129.564 29.856 ;
     RECT  129.481 29.856 129.516 29.88 ;
     RECT  129.481 29.88 129.564 30.192 ;
     RECT  129.481 30.192 129.516 30.216 ;
     RECT  129.481 30.216 129.564 30.528 ;
     RECT  129.481 30.528 129.516 30.552 ;
     RECT  129.481 30.552 129.564 30.864 ;
     RECT  129.481 30.864 129.516 30.888 ;
     RECT  129.481 30.888 129.564 31.2 ;
     RECT  129.481 31.2 129.516 31.224 ;
     RECT  129.481 31.224 129.564 31.536 ;
     RECT  129.481 31.536 129.516 31.56 ;
     RECT  129.481 31.56 129.564 31.872 ;
     RECT  129.481 31.872 129.516 31.896 ;
     RECT  129.481 31.896 129.564 32.208 ;
     RECT  129.481 32.208 129.516 32.232 ;
     RECT  129.481 32.232 129.564 32.544 ;
     RECT  129.481 32.544 129.516 32.568 ;
     RECT  129.481 32.568 129.564 32.88 ;
     RECT  129.481 32.88 129.516 32.904 ;
     RECT  129.481 32.904 129.564 33.216 ;
     RECT  129.481 33.216 129.516 33.24 ;
     RECT  129.481 33.24 129.564 33.552 ;
     RECT  129.481 33.552 129.516 33.576 ;
     RECT  129.481 33.576 129.564 33.888 ;
     RECT  129.481 33.888 129.516 33.912 ;
     RECT  129.481 33.912 129.564 34.224 ;
     RECT  129.481 34.224 129.516 34.248 ;
     RECT  129.481 34.248 129.564 34.56 ;
     RECT  129.481 34.56 129.516 34.584 ;
     RECT  129.481 34.584 129.564 34.896 ;
     RECT  129.481 34.896 129.516 34.92 ;
     RECT  129.481 34.92 129.564 35.28 ;
     RECT  129.481 35.28 129.516 35.304 ;
     RECT  129.481 35.304 129.564 35.616 ;
     RECT  129.481 35.616 129.516 35.64 ;
     RECT  129.481 35.64 129.564 35.952 ;
     RECT  129.481 35.952 129.516 35.976 ;
     RECT  129.481 35.976 129.564 36.288 ;
     RECT  129.481 36.288 129.516 36.312 ;
     RECT  129.481 36.312 129.564 36.624 ;
     RECT  129.481 36.624 129.516 36.648 ;
     RECT  129.481 36.648 129.564 36.96 ;
     RECT  129.481 36.96 129.516 36.984 ;
     RECT  129.481 36.984 129.564 37.296 ;
     RECT  129.481 37.296 129.516 37.32 ;
     RECT  129.481 37.32 129.564 37.632 ;
     RECT  129.481 37.632 129.516 37.656 ;
     RECT  129.481 37.656 129.564 37.968 ;
     RECT  129.481 37.968 129.516 37.992 ;
     RECT  129.481 37.992 129.564 38.304 ;
     RECT  129.481 38.304 129.516 38.328 ;
     RECT  129.481 38.328 129.564 38.64 ;
     RECT  129.481 38.64 129.516 38.664 ;
     RECT  129.481 38.664 129.564 38.976 ;
     RECT  129.481 38.976 129.516 39 ;
     RECT  129.481 39 129.564 39.312 ;
     RECT  129.481 39.312 129.516 39.336 ;
     RECT  129.481 39.336 129.564 39.648 ;
     RECT  129.481 39.648 129.516 39.672 ;
     RECT  129.481 39.672 129.564 39.984 ;
     RECT  129.481 39.984 129.516 40.008 ;
     RECT  129.481 40.008 129.564 40.32 ;
     RECT  129.481 40.32 129.516 40.344 ;
     RECT  129.481 40.344 129.564 40.656 ;
     RECT  129.481 40.656 129.516 40.68 ;
     RECT  129.481 40.68 129.564 40.992 ;
     RECT  129.481 40.992 129.516 41.016 ;
     RECT  129.481 41.016 129.564 41.328 ;
     RECT  129.481 41.328 129.516 41.352 ;
     RECT  129.481 41.352 129.564 41.664 ;
     RECT  129.481 41.664 129.516 41.688 ;
     RECT  129.481 41.688 129.564 42 ;
     RECT  129.481 42 129.516 42.024 ;
     RECT  129.481 42.024 129.564 42.336 ;
     RECT  129.481 42.336 129.516 42.36 ;
     RECT  129.481 42.36 129.564 42.672 ;
     RECT  129.481 42.672 129.516 42.696 ;
     RECT  129.481 42.696 129.564 43.008 ;
     RECT  129.481 43.008 129.516 43.032 ;
     RECT  129.481 43.032 129.564 43.344 ;
     RECT  129.481 43.344 129.516 43.368 ;
     RECT  129.481 43.368 129.564 43.68 ;
     RECT  129.481 43.68 129.516 43.704 ;
     RECT  129.481 43.704 129.564 44.016 ;
     RECT  129.481 44.016 129.516 44.04 ;
     RECT  129.481 44.04 129.564 44.352 ;
     RECT  129.481 44.352 129.516 44.376 ;
     RECT  129.481 44.376 129.564 44.688 ;
     RECT  129.481 44.688 129.516 44.712 ;
     RECT  129.481 44.712 129.564 45.024 ;
     RECT  129.481 45.024 129.516 45.048 ;
     RECT  129.481 45.048 129.564 45.36 ;
     RECT  129.481 45.36 129.516 45.384 ;
     RECT  129.481 45.384 129.564 45.696 ;
     RECT  129.481 45.696 129.516 45.72 ;
     RECT  129.481 45.72 129.564 46.08 ;
     RECT  129.481 46.08 129.516 46.104 ;
     RECT  129.481 46.104 129.564 46.416 ;
     RECT  129.481 46.416 129.516 46.44 ;
     RECT  129.481 46.44 129.564 46.752 ;
     RECT  129.481 46.752 129.516 46.776 ;
     RECT  129.481 46.776 129.564 47.088 ;
     RECT  129.481 47.088 129.516 47.112 ;
     RECT  129.481 47.112 129.564 47.424 ;
     RECT  129.481 47.424 129.516 47.448 ;
     RECT  129.481 47.448 129.564 47.76 ;
     RECT  129.481 47.76 129.516 47.784 ;
     RECT  129.481 47.784 129.564 48.096 ;
     RECT  129.481 48.096 129.516 48.12 ;
     RECT  129.481 48.12 129.564 48.432 ;
     RECT  129.481 48.432 129.516 48.456 ;
     RECT  129.481 48.456 129.564 48.768 ;
     RECT  129.481 48.768 129.516 48.792 ;
     RECT  129.481 48.792 129.564 49.104 ;
     RECT  129.481 49.104 129.516 49.128 ;
     RECT  129.481 49.128 129.564 49.44 ;
     RECT  129.481 49.44 129.516 49.464 ;
     RECT  129.481 49.464 129.564 49.776 ;
     RECT  129.481 49.776 129.516 49.8 ;
     RECT  129.481 49.8 129.564 50.112 ;
     RECT  129.481 50.112 129.516 50.136 ;
     RECT  129.481 50.136 129.564 50.448 ;
     RECT  129.481 50.448 129.516 50.472 ;
     RECT  129.481 50.472 129.564 50.784 ;
     RECT  129.481 50.784 129.516 50.808 ;
     RECT  129.481 50.808 129.564 51.12 ;
     RECT  129.481 51.12 129.516 51.144 ;
     RECT  129.481 51.144 129.564 51.456 ;
     RECT  129.481 51.456 129.516 51.48 ;
     RECT  129.481 51.48 129.564 51.792 ;
     RECT  129.481 51.792 129.516 51.816 ;
     RECT  129.481 51.816 129.564 52.128 ;
     RECT  129.481 52.128 129.516 52.152 ;
     RECT  129.481 52.152 129.564 52.464 ;
     RECT  129.481 52.464 129.516 52.488 ;
     RECT  129.481 52.488 129.564 52.8 ;
     RECT  129.481 52.8 129.516 52.824 ;
     RECT  129.481 52.824 129.564 53.136 ;
     RECT  129.481 53.136 129.516 53.16 ;
     RECT  129.481 53.16 129.564 53.472 ;
     RECT  129.481 53.472 129.516 53.496 ;
     RECT  129.481 53.496 129.564 53.808 ;
     RECT  129.481 53.808 129.516 53.832 ;
     RECT  129.481 53.832 129.564 54.144 ;
     RECT  129.481 54.144 129.516 54.168 ;
     RECT  129.481 54.168 129.564 54.48 ;
     RECT  129.481 54.48 129.516 54.504 ;
     RECT  129.481 54.504 129.564 54.816 ;
     RECT  129.481 54.816 129.516 54.84 ;
     RECT  129.481 54.84 129.564 55.152 ;
     RECT  129.481 55.152 129.516 55.176 ;
     RECT  129.481 55.176 129.564 55.488 ;
     RECT  129.481 55.488 129.516 55.512 ;
     RECT  129.481 55.512 129.564 55.824 ;
     RECT  129.481 55.824 129.516 55.848 ;
     RECT  129.481 55.848 129.564 56.16 ;
     RECT  129.481 56.16 129.516 56.184 ;
     RECT  129.481 56.184 129.564 56.496 ;
     RECT  129.481 56.496 129.516 56.52 ;
     RECT  129.481 56.52 129.564 56.88 ;
     RECT  129.481 56.88 129.516 56.904 ;
     RECT  129.481 56.904 129.564 57.216 ;
     RECT  129.481 57.216 129.516 57.24 ;
     RECT  129.481 57.24 129.564 57.552 ;
     RECT  129.481 57.552 129.516 57.576 ;
     RECT  129.481 57.576 129.564 57.888 ;
     RECT  129.481 57.888 129.516 57.912 ;
     RECT  129.481 57.912 129.564 58.224 ;
     RECT  129.481 58.224 129.516 58.248 ;
     RECT  129.481 58.248 129.564 58.56 ;
     RECT  129.481 58.56 129.516 58.584 ;
     RECT  129.481 58.584 129.564 58.896 ;
     RECT  129.481 58.896 129.516 58.92 ;
     RECT  129.481 58.92 129.564 59.232 ;
     RECT  129.481 59.232 129.516 59.256 ;
     RECT  129.481 59.256 129.564 59.568 ;
     RECT  129.481 59.568 129.516 59.592 ;
     RECT  129.481 59.592 129.564 59.904 ;
     RECT  129.481 59.904 129.516 59.928 ;
     RECT  129.481 59.928 129.564 60.24 ;
     RECT  129.481 60.24 129.516 60.264 ;
     RECT  129.481 60.264 129.564 60.576 ;
     RECT  129.481 60.576 129.516 60.6 ;
     RECT  129.481 60.6 129.564 60.912 ;
     RECT  129.481 60.912 129.516 60.936 ;
     RECT  129.481 60.936 129.564 61.248 ;
     RECT  129.481 61.248 129.516 61.272 ;
     RECT  129.481 61.272 129.564 61.584 ;
     RECT  129.481 61.584 129.516 61.608 ;
     RECT  129.481 61.608 129.564 61.92 ;
     RECT  129.481 61.92 129.516 61.944 ;
     RECT  129.481 61.944 129.564 62.256 ;
     RECT  129.481 62.256 129.516 62.28 ;
     RECT  129.481 62.28 129.564 62.592 ;
     RECT  129.481 62.592 129.516 62.616 ;
     RECT  129.481 62.616 129.564 62.928 ;
     RECT  129.481 62.928 129.516 62.952 ;
     RECT  129.481 62.952 129.564 63.264 ;
     RECT  129.481 63.264 129.516 63.288 ;
     RECT  129.481 63.288 129.564 63.6 ;
     RECT  129.481 63.6 129.516 63.624 ;
     RECT  129.481 63.624 129.564 63.936 ;
     RECT  129.481 63.936 129.516 63.96 ;
     RECT  129.481 63.96 129.564 64.272 ;
     RECT  129.481 64.272 129.516 64.296 ;
     RECT  129.481 64.296 129.564 64.608 ;
     RECT  129.481 64.608 129.516 64.632 ;
     RECT  129.481 64.632 129.564 64.944 ;
     RECT  129.481 64.944 129.516 64.968 ;
     RECT  129.481 64.968 129.564 65.28 ;
     RECT  129.481 65.28 129.516 65.304 ;
     RECT  129.481 65.304 129.564 65.616 ;
     RECT  129.481 65.616 129.516 65.64 ;
     RECT  129.481 65.64 129.564 65.952 ;
     RECT  129.481 65.952 129.516 65.976 ;
     RECT  129.481 65.976 129.564 66.288 ;
     RECT  129.481 66.288 129.516 66.312 ;
     RECT  129.481 66.312 129.564 66.624 ;
     RECT  129.481 66.624 129.516 66.648 ;
     RECT  129.481 66.648 129.564 66.96 ;
     RECT  129.481 66.96 129.516 66.984 ;
     RECT  129.481 66.984 129.564 67.296 ;
     RECT  129.481 67.296 129.516 67.32 ;
     RECT  129.481 67.32 129.564 67.68 ;
     RECT  129.481 67.68 129.516 67.704 ;
     RECT  129.481 67.704 129.564 68.016 ;
     RECT  129.481 68.016 129.516 68.04 ;
     RECT  129.481 68.04 129.564 68.352 ;
     RECT  129.481 68.352 129.516 68.376 ;
     RECT  129.481 68.376 129.564 68.688 ;
     RECT  129.481 68.688 129.516 68.712 ;
     RECT  129.481 68.712 129.564 69.024 ;
     RECT  129.481 69.024 129.516 69.048 ;
     RECT  129.481 69.048 129.564 69.36 ;
     RECT  129.481 69.36 129.516 69.384 ;
     RECT  129.481 69.384 129.564 69.696 ;
     RECT  129.481 69.696 129.516 69.72 ;
     RECT  129.481 69.72 129.564 70.032 ;
     RECT  129.481 70.032 129.516 70.056 ;
     RECT  129.481 70.056 129.564 70.368 ;
     RECT  129.481 70.368 129.516 70.392 ;
     RECT  129.481 70.392 129.564 70.704 ;
     RECT  129.481 70.704 129.516 70.728 ;
     RECT  129.481 70.728 129.564 71.04 ;
     RECT  129.481 71.04 129.516 71.064 ;
     RECT  129.481 71.064 129.564 71.376 ;
     RECT  129.481 71.376 129.516 71.4 ;
     RECT  129.481 71.4 129.564 71.712 ;
     RECT  129.481 71.712 129.516 71.736 ;
     RECT  129.481 71.736 129.564 72.048 ;
     RECT  129.481 72.048 129.516 72.072 ;
     RECT  129.481 72.072 129.564 72.384 ;
     RECT  129.481 72.384 129.516 72.408 ;
     RECT  129.481 72.408 129.564 72.72 ;
     RECT  129.481 72.72 129.516 72.744 ;
     RECT  129.481 72.744 129.564 73.056 ;
     RECT  129.481 73.056 129.516 73.08 ;
     RECT  129.481 73.08 129.564 73.392 ;
     RECT  129.481 73.392 129.516 73.416 ;
     RECT  129.481 73.416 129.564 73.728 ;
     RECT  129.481 73.728 129.516 73.752 ;
     RECT  129.481 73.752 129.564 74.064 ;
     RECT  129.481 74.064 129.516 74.088 ;
     RECT  129.481 74.088 129.564 74.4 ;
     RECT  129.481 74.4 129.516 74.424 ;
     RECT  129.481 74.424 129.564 74.736 ;
     RECT  129.481 74.736 129.516 74.76 ;
     RECT  129.481 74.76 129.564 75.072 ;
     RECT  129.481 75.072 129.516 75.096 ;
     RECT  129.481 75.096 129.564 75.408 ;
     RECT  129.481 75.408 129.516 75.432 ;
     RECT  129.481 75.432 129.564 75.744 ;
     RECT  129.481 75.744 129.516 75.768 ;
     RECT  129.481 75.768 129.564 76.08 ;
     RECT  129.481 76.08 129.516 76.104 ;
     RECT  129.481 76.104 129.564 76.416 ;
     RECT  129.481 76.416 129.516 76.44 ;
     RECT  129.481 76.44 129.564 76.752 ;
     RECT  129.481 76.752 129.516 76.776 ;
     RECT  129.481 76.776 129.564 77.088 ;
     RECT  129.481 77.088 129.516 77.112 ;
     RECT  129.481 77.112 129.564 77.424 ;
     RECT  129.481 77.424 129.516 77.448 ;
     RECT  129.481 77.448 129.564 77.76 ;
     RECT  129.481 77.76 129.516 77.784 ;
     RECT  129.481 77.784 129.564 78.096 ;
     RECT  129.481 78.096 129.516 78.12 ;
     RECT  129.481 78.12 129.564 78.48 ;
     RECT  129.481 78.48 129.516 78.504 ;
     RECT  129.481 78.504 129.564 78.816 ;
     RECT  129.481 78.816 129.516 78.84 ;
     RECT  129.481 78.84 129.564 79.152 ;
     RECT  129.481 79.152 129.516 79.176 ;
     RECT  129.481 79.176 129.564 79.488 ;
     RECT  129.481 79.488 129.516 79.512 ;
     RECT  129.481 79.512 129.564 79.824 ;
     RECT  129.481 79.824 129.516 79.848 ;
     RECT  129.481 79.848 129.564 80.16 ;
     RECT  129.481 80.16 129.516 80.184 ;
     RECT  129.481 80.184 129.564 80.496 ;
     RECT  129.481 80.496 129.516 80.52 ;
     RECT  129.481 80.52 129.564 80.832 ;
     RECT  129.481 80.832 129.516 80.856 ;
     RECT  129.481 80.856 129.564 81.168 ;
     RECT  129.481 81.168 129.516 81.192 ;
     RECT  129.481 81.192 129.564 81.504 ;
     RECT  129.481 81.504 129.516 81.528 ;
     RECT  129.481 81.528 129.564 81.84 ;
     RECT  129.481 81.84 129.516 81.864 ;
     RECT  129.481 81.864 129.564 82.176 ;
     RECT  129.481 82.176 129.516 82.2 ;
     RECT  129.481 82.2 129.564 82.512 ;
     RECT  129.481 82.512 129.516 82.536 ;
     RECT  129.481 82.536 129.564 82.848 ;
     RECT  129.481 82.848 129.516 82.872 ;
     RECT  129.481 82.872 129.564 83.184 ;
     RECT  129.481 83.184 129.516 83.208 ;
     RECT  129.481 83.208 129.564 83.52 ;
     RECT  129.481 83.52 129.516 83.544 ;
     RECT  129.481 83.544 129.564 83.856 ;
     RECT  129.481 83.856 129.516 83.88 ;
     RECT  129.481 83.88 129.564 84.192 ;
     RECT  129.481 84.192 129.516 84.216 ;
     RECT  129.481 84.216 129.564 84.528 ;
     RECT  129.481 84.528 129.516 84.552 ;
     RECT  129.481 84.552 129.564 84.864 ;
     RECT  129.481 84.864 129.516 84.888 ;
     RECT  129.481 84.888 129.564 85.2 ;
     RECT  129.481 85.2 129.516 85.224 ;
     RECT  129.481 85.224 129.564 85.536 ;
     RECT  129.481 85.536 129.516 85.56 ;
     RECT  129.481 85.56 129.564 85.872 ;
     RECT  129.481 85.872 129.516 85.896 ;
     RECT  129.481 85.896 129.564 86.208 ;
     RECT  129.481 86.208 129.516 86.232 ;
     RECT  129.564 84.096 129.593 84.12 ;
    LAYER M5 ;
     RECT  2.4 2.137 2.52 2.151 ;
     RECT  7.8 2.137 7.92 2.151 ;
     RECT  13.2 2.137 13.32 2.151 ;
     RECT  18.6 2.137 18.72 2.151 ;
     RECT  24 2.137 24.12 2.151 ;
     RECT  29.4 2.137 29.52 2.151 ;
     RECT  34.8 2.137 34.92 2.151 ;
     RECT  40.2 2.137 40.32 2.151 ;
     RECT  45.6 2.137 45.72 2.151 ;
     RECT  51 2.137 51.12 2.151 ;
     RECT  56.4 2.137 56.52 2.151 ;
     RECT  61.8 2.137 61.92 2.151 ;
     RECT  67.2 2.137 67.32 2.151 ;
     RECT  72.6 2.137 72.72 2.151 ;
     RECT  78 2.137 78.12 2.151 ;
     RECT  83.4 2.137 83.52 2.151 ;
     RECT  88.8 2.137 88.92 2.151 ;
     RECT  94.2 2.137 94.32 2.151 ;
     RECT  99.6 2.137 99.72 2.151 ;
     RECT  105 2.137 105.12 2.151 ;
     RECT  110.4 2.137 110.52 2.151 ;
     RECT  115.8 2.137 115.92 2.151 ;
     RECT  121.2 2.137 121.32 2.151 ;
     RECT  126.6 2.137 126.72 2.151 ;
     RECT  94.2 2.151 94.512 3.541 ;
     RECT  121.2 2.151 121.512 5.557 ;
     RECT  124.272 4.789 124.296 5.747 ;
     RECT  122.88 4.501 122.904 8.437 ;
     RECT  121.2 5.557 121.608 8.579 ;
     RECT  122.88 8.437 123 9.731 ;
     RECT  121.2 8.579 121.512 10.597 ;
     RECT  124.752 10.213 124.776 10.931 ;
     RECT  121.2 10.597 121.704 11.843 ;
     RECT  122.976 9.731 123 13.765 ;
     RECT  122.976 13.765 123.096 13.811 ;
     RECT  123.072 13.811 123.096 14.101 ;
     RECT  123.072 14.101 123.816 15.683 ;
     RECT  121.2 11.843 121.512 16.117 ;
     RECT  123.072 15.683 123.096 16.117 ;
     RECT  121.2 16.117 123.096 18.419 ;
     RECT  122.976 18.419 123.096 19.669 ;
     RECT  122.976 19.669 123.576 19.909 ;
     RECT  121.2 18.419 121.512 20.485 ;
     RECT  122.976 19.909 123.72 21.299 ;
     RECT  122.976 21.299 123.576 22.741 ;
     RECT  121.2 20.485 121.752 22.787 ;
     RECT  122.976 22.741 123.672 24.565 ;
     RECT  122.544 24.565 123.672 24.611 ;
     RECT  122.544 24.611 122.568 25.621 ;
     RECT  123.648 24.611 123.672 25.621 ;
     RECT  122.544 25.621 123.672 26.483 ;
     RECT  110.4 2.151 110.712 27.061 ;
     RECT  122.544 26.483 122.568 29.989 ;
     RECT  123.648 26.483 123.672 29.989 ;
     RECT  122.544 29.989 123.672 30.709 ;
     RECT  122.544 30.709 124.152 30.757 ;
     RECT  122.496 30.757 124.152 30.899 ;
     RECT  123.072 30.899 124.152 32.293 ;
     RECT  122.544 32.293 124.152 32.483 ;
     RECT  122.544 32.483 123.672 33.683 ;
     RECT  83.4 2.151 83.712 34.453 ;
     RECT  84.816 16.261 84.84 35.029 ;
     RECT  123.072 33.683 123.672 35.605 ;
     RECT  122.88 35.605 123.672 38.149 ;
     RECT  121.2 22.787 121.512 39.061 ;
     RECT  122.88 38.149 124.392 41.029 ;
     RECT  121.2 39.061 121.608 41.699 ;
     RECT  122.784 41.029 124.392 43.285 ;
     RECT  122.544 43.285 124.392 44.483 ;
     RECT  121.2 41.699 121.512 46.069 ;
     RECT  122.688 44.483 124.392 46.069 ;
     RECT  121.2 46.069 124.392 47.459 ;
     RECT  2.4 2.151 2.712 48.421 ;
     RECT  3.888 44.437 3.912 48.421 ;
     RECT  2.4 48.421 3.912 48.467 ;
     RECT  122.592 47.459 124.392 50.771 ;
     RECT  65.424 43.285 65.448 51.155 ;
     RECT  88.8 2.151 89.112 51.253 ;
     RECT  99.6 2.151 99.912 51.637 ;
     RECT  121.2 47.459 121.512 52.405 ;
     RECT  122.736 50.771 124.392 52.405 ;
     RECT  121.2 52.405 124.392 53.939 ;
     RECT  105 2.151 105.312 54.565 ;
     RECT  122.832 53.939 124.392 54.661 ;
     RECT  101.136 28.741 101.16 54.949 ;
     RECT  121.2 53.939 121.512 56.917 ;
     RECT  122.832 54.661 124.536 56.917 ;
     RECT  121.2 56.917 124.536 57.059 ;
     RECT  121.2 57.059 121.992 58.117 ;
     RECT  121.2 58.117 122.52 58.163 ;
     RECT  122.496 58.163 122.52 58.979 ;
     RECT  47.568 51.109 47.592 59.555 ;
     RECT  34.8 2.151 35.112 59.989 ;
     RECT  123.648 57.059 124.392 60.373 ;
     RECT  123.312 60.373 124.392 61.619 ;
     RECT  82.8 34.453 83.712 62.437 ;
     RECT  123.648 61.619 124.392 62.581 ;
     RECT  123.264 62.581 124.392 63.205 ;
     RECT  123.12 63.205 124.392 64.355 ;
     RECT  112.176 58.357 112.2 64.933 ;
     RECT  99.6 51.637 100.008 64.981 ;
     RECT  80.976 44.677 81 65.701 ;
     RECT  88.56 51.253 89.112 65.941 ;
     RECT  80.976 65.701 81.048 67.237 ;
     RECT  99.6 64.981 100.104 67.333 ;
     RECT  101.136 54.949 101.88 67.333 ;
     RECT  112.08 64.933 112.2 67.381 ;
     RECT  104.88 54.565 105.312 67.669 ;
     RECT  123.264 64.355 124.392 67.669 ;
     RECT  104.88 67.669 105.432 67.715 ;
     RECT  109.536 27.061 110.712 67.717 ;
     RECT  112.08 67.381 112.296 67.861 ;
     RECT  115.8 2.151 116.112 68.053 ;
     RECT  117.264 67.333 117.288 68.053 ;
     RECT  115.8 68.053 117.288 68.101 ;
     RECT  92.592 66.805 92.616 68.149 ;
     RECT  87.264 55.525 87.288 68.197 ;
     RECT  88.56 65.941 89.256 68.197 ;
     RECT  111.984 67.861 112.296 68.197 ;
     RECT  109.392 67.717 110.712 68.243 ;
     RECT  109.536 68.243 110.712 68.533 ;
     RECT  111.984 68.197 113.4 68.533 ;
     RECT  99.6 67.333 101.88 68.821 ;
     RECT  103.536 68.245 103.56 68.821 ;
     RECT  99.6 68.821 103.56 68.869 ;
     RECT  105 67.715 105.432 68.869 ;
     RECT  109.536 68.533 113.4 68.917 ;
     RECT  115.248 68.101 117.288 68.917 ;
     RECT  121.2 58.163 121.512 68.917 ;
     RECT  92.592 68.149 92.664 69.109 ;
     RECT  40.2 2.151 40.512 69.205 ;
     RECT  99.6 68.869 105.432 69.205 ;
     RECT  115.152 68.917 117.528 69.205 ;
     RECT  115.152 69.205 117.816 69.349 ;
     RECT  115.152 69.349 118.248 69.445 ;
     RECT  97.872 68.533 97.896 69.493 ;
     RECT  115.008 69.445 118.248 69.493 ;
     RECT  120.576 68.917 121.512 69.493 ;
     RECT  115.008 69.493 118.344 69.587 ;
     RECT  97.776 69.493 97.896 69.731 ;
     RECT  120.144 69.493 121.512 69.733 ;
     RECT  96.288 66.565 96.312 69.779 ;
     RECT  40.2 69.205 40.728 69.781 ;
     RECT  92.592 69.109 92.904 69.829 ;
     RECT  119.712 69.733 121.512 69.829 ;
     RECT  92.592 69.829 92.952 69.877 ;
     RECT  84.816 35.029 84.888 69.973 ;
     RECT  87.264 68.197 89.256 70.069 ;
     RECT  99.504 69.205 105.432 70.069 ;
     RECT  106.992 58.453 107.016 70.069 ;
     RECT  115.152 69.587 118.344 70.259 ;
     RECT  122.496 67.669 124.392 70.259 ;
     RECT  94.2 3.541 94.872 70.357 ;
     RECT  87.264 70.069 89.304 70.405 ;
     RECT  94.2 70.357 95.592 70.405 ;
     RECT  87.264 70.405 89.496 70.595 ;
     RECT  94.08 70.405 95.592 70.595 ;
     RECT  119.664 69.829 121.512 70.597 ;
     RECT  80.976 67.237 81.432 70.645 ;
     RECT  39.312 69.781 40.728 70.837 ;
     RECT  99.504 70.069 107.016 70.885 ;
     RECT  109.536 68.917 113.928 70.885 ;
     RECT  13.2 2.151 13.512 71.077 ;
     RECT  94.08 70.595 95.4 71.267 ;
     RECT  99.312 70.885 107.016 71.269 ;
     RECT  109.536 70.885 114.024 71.315 ;
     RECT  92.592 69.877 93.096 71.317 ;
     RECT  91.968 71.317 93.096 71.509 ;
     RECT  94.08 71.267 95.112 71.509 ;
     RECT  99.312 71.269 107.976 71.653 ;
     RECT  109.536 71.315 111 71.653 ;
     RECT  99.312 71.653 111 71.699 ;
     RECT  82.656 62.437 83.712 71.701 ;
     RECT  84.816 69.973 84.936 71.701 ;
     RECT  82.656 71.701 84.936 71.747 ;
     RECT  123.264 70.259 124.392 71.797 ;
     RECT  80.4 70.645 81.432 71.843 ;
     RECT  96.384 71.173 96.408 72.035 ;
     RECT  119.568 70.597 121.512 72.037 ;
     RECT  82.656 71.747 84.888 72.133 ;
     RECT  91.968 71.509 95.112 72.133 ;
     RECT  91.728 72.133 95.112 72.179 ;
     RECT  87.264 70.595 89.352 72.229 ;
     RECT  99.6 71.699 111 72.277 ;
     RECT  112.08 71.315 114.024 72.277 ;
     RECT  115.2 70.259 118.344 72.277 ;
     RECT  123.12 71.797 124.392 72.325 ;
     RECT  91.728 72.179 94.92 72.419 ;
     RECT  97.776 69.731 97.8 72.419 ;
     RECT  72.6 2.151 72.912 72.469 ;
     RECT  92.064 72.419 94.92 72.563 ;
     RECT  7.8 2.151 8.112 72.565 ;
     RECT  82.416 72.133 84.888 72.709 ;
     RECT  86.208 72.613 86.232 72.709 ;
     RECT  123.12 72.325 125.016 72.757 ;
     RECT  97.008 72.421 97.032 72.803 ;
     RECT  82.416 72.709 86.232 72.851 ;
     RECT  99.6 72.277 118.344 72.949 ;
     RECT  119.424 72.037 121.512 72.949 ;
     RECT  92.064 72.563 94.872 72.995 ;
     RECT  92.064 72.995 92.328 73.139 ;
     RECT  80.928 71.843 81.432 73.189 ;
     RECT  82.416 72.851 86.04 73.189 ;
     RECT  87.264 72.229 89.784 73.285 ;
     RECT  99.6 72.949 121.512 73.333 ;
     RECT  122.64 72.757 125.016 73.333 ;
     RECT  93.408 72.995 94.872 73.427 ;
     RECT  99.6 73.333 125.016 73.429 ;
     RECT  34.8 59.989 35.208 73.525 ;
     RECT  24 2.151 24.312 73.861 ;
     RECT  87.264 73.285 90.312 73.861 ;
     RECT  24 73.861 24.648 73.957 ;
     RECT  80.928 73.189 86.04 74.005 ;
     RECT  97.008 73.957 97.032 74.053 ;
     RECT  96.912 74.053 97.032 74.101 ;
     RECT  98.88 73.429 125.016 74.243 ;
     RECT  93.792 73.427 94.872 74.245 ;
     RECT  96.288 74.101 97.032 74.245 ;
     RECT  80.304 74.005 86.04 74.291 ;
     RECT  67.2 2.151 67.512 74.293 ;
     RECT  80.928 74.291 86.04 74.819 ;
     RECT  93.792 74.245 97.032 74.867 ;
     RECT  48.48 59.605 48.504 74.917 ;
     RECT  96.432 74.867 97.032 75.011 ;
     RECT  126.6 2.151 126.912 75.109 ;
     RECT  93.792 74.867 94.872 75.155 ;
     RECT  96.912 75.011 97.032 75.155 ;
     RECT  126.144 75.109 126.912 75.157 ;
     RECT  93.888 75.155 94.872 75.203 ;
     RECT  80.976 74.819 86.04 75.205 ;
     RECT  87.168 73.861 90.312 75.205 ;
     RECT  99.024 74.243 125.016 75.205 ;
     RECT  126 75.157 126.912 75.205 ;
     RECT  80.976 75.205 90.312 75.347 ;
     RECT  81.216 75.347 90.312 75.491 ;
     RECT  61.8 2.151 62.112 75.733 ;
     RECT  94.08 75.203 94.872 75.829 ;
     RECT  81.216 75.491 85.512 75.923 ;
     RECT  86.784 75.491 90.312 75.971 ;
     RECT  94.08 75.829 94.968 75.971 ;
     RECT  72.6 72.469 73.224 76.021 ;
     RECT  97.344 75.685 97.368 76.117 ;
     RECT  98.448 75.205 126.912 76.117 ;
     RECT  94.2 75.971 94.968 76.213 ;
     RECT  88.56 75.971 90.312 76.261 ;
     RECT  97.344 76.117 126.912 76.261 ;
     RECT  81.936 75.923 85.512 76.307 ;
     RECT  21.072 72.661 21.096 76.357 ;
     RECT  88.56 76.261 90.696 76.501 ;
     RECT  92.304 76.453 92.328 76.501 ;
     RECT  80.928 76.405 80.952 76.547 ;
     RECT  96.96 76.261 126.912 76.691 ;
     RECT  78 2.151 78.312 76.693 ;
     RECT  20.256 76.357 21.096 76.789 ;
     RECT  47.856 74.917 48.504 76.789 ;
     RECT  86.784 75.971 87.528 76.789 ;
     RECT  96.96 76.691 98.328 76.789 ;
     RECT  78 76.693 78.696 76.883 ;
     RECT  81.936 76.307 84.84 76.979 ;
     RECT  99.456 76.691 126.912 76.979 ;
     RECT  86.016 76.789 87.528 77.027 ;
     RECT  56.4 2.151 56.712 77.125 ;
     RECT  71.04 71.989 71.064 77.125 ;
     RECT  96.336 76.789 98.328 77.171 ;
     RECT  18.6 2.151 18.912 77.269 ;
     RECT  56.4 77.125 57 77.315 ;
     RECT  70.704 77.125 71.064 77.315 ;
     RECT  45.6 2.151 45.912 77.317 ;
     RECT  54.816 77.269 54.84 77.411 ;
     RECT  88.56 76.501 92.328 77.413 ;
     RECT  80.64 76.645 80.664 77.509 ;
     RECT  81.936 76.979 84.504 77.509 ;
     RECT  87.264 77.027 87.528 77.555 ;
     RECT  96.96 77.171 98.328 77.555 ;
     RECT  88.56 77.413 92.376 77.557 ;
     RECT  80.64 77.509 84.504 77.651 ;
     RECT  33.984 73.525 35.208 77.749 ;
     RECT  88.56 77.557 93.096 77.749 ;
     RECT  94.2 76.213 95.016 77.749 ;
     RECT  80.64 77.651 80.664 77.795 ;
     RECT  18.6 77.269 19.032 77.797 ;
     RECT  88.56 77.749 95.016 77.843 ;
     RECT  45.6 77.317 46.104 77.893 ;
     RECT  87.456 77.555 87.528 77.941 ;
     RECT  88.56 77.843 91.32 77.941 ;
     RECT  45.6 77.893 46.344 77.989 ;
     RECT  47.856 76.789 48.744 77.989 ;
     RECT  45.6 77.989 48.744 78.131 ;
     RECT  126.432 76.979 126.912 78.131 ;
     RECT  92.304 77.843 95.016 78.323 ;
     RECT  81.936 77.651 84.504 78.469 ;
     RECT  86.016 77.027 86.04 78.469 ;
     RECT  99.456 76.979 125.16 78.517 ;
     RECT  99.456 78.517 125.304 78.613 ;
     RECT  45.6 78.131 47.112 78.997 ;
     RECT  51 2.151 51.312 79.045 ;
     RECT  99.456 78.613 125.352 79.045 ;
     RECT  99.456 79.045 125.4 79.141 ;
     RECT  126.6 78.131 126.912 79.141 ;
     RECT  87.456 77.941 91.32 79.235 ;
     RECT  92.304 78.323 94.512 79.283 ;
     RECT  99.456 79.141 126.912 79.379 ;
     RECT  87.456 79.235 89.4 79.571 ;
     RECT  81.936 78.469 86.04 79.669 ;
     RECT  97.392 77.555 98.328 79.669 ;
     RECT  99.6 79.379 126.912 79.715 ;
     RECT  92.88 79.283 94.512 79.765 ;
     RECT  90.768 79.235 91.32 79.811 ;
     RECT  15.12 74.869 15.144 79.859 ;
     RECT  31.872 79.189 31.896 79.859 ;
     RECT  90.768 79.811 90.792 79.859 ;
     RECT  92.88 79.765 95.256 79.861 ;
     RECT  29.4 2.151 29.712 80.005 ;
     RECT  108.192 79.715 126.912 80.101 ;
     RECT  92.88 79.861 95.928 80.149 ;
     RECT  78 76.883 78.312 80.197 ;
     RECT  92.88 80.149 96.264 80.341 ;
     RECT  97.392 79.669 98.424 80.341 ;
     RECT  92.88 80.341 98.424 80.435 ;
     RECT  88.08 79.571 89.4 80.437 ;
     RECT  108.192 80.101 127.032 80.483 ;
     RECT  2.4 48.467 3.672 80.677 ;
     RECT  78 80.197 78.696 80.677 ;
     RECT  2.4 80.677 3.912 80.725 ;
     RECT  2.4 80.725 4.536 80.773 ;
     RECT  93.888 80.435 98.424 80.819 ;
     RECT  2.16 80.773 4.536 80.821 ;
     RECT  5.664 79.189 5.688 80.821 ;
     RECT  18.6 77.797 19.08 80.869 ;
     RECT  33.984 77.749 35.256 80.869 ;
     RECT  81.936 79.669 86.376 80.917 ;
     RECT  33.888 80.869 35.256 80.963 ;
     RECT  38.784 70.837 40.728 80.963 ;
     RECT  91.536 80.917 91.56 80.965 ;
     RECT  6.672 76.885 6.696 81.011 ;
     RECT  13.2 71.077 14.04 81.011 ;
     RECT  59.952 75.781 59.976 81.011 ;
     RECT  71.04 77.315 71.064 81.011 ;
     RECT  81.936 80.917 86.52 81.011 ;
     RECT  88.08 80.437 89.64 81.011 ;
     RECT  91.536 80.965 92.76 81.013 ;
     RECT  93.984 80.819 98.424 81.059 ;
     RECT  88.272 81.011 89.64 81.061 ;
     RECT  91.104 81.013 92.76 81.061 ;
     RECT  93.984 81.059 98.232 81.107 ;
     RECT  33.888 80.963 35.208 81.157 ;
     RECT  37.488 81.061 37.512 81.203 ;
     RECT  80.832 80.965 80.856 81.205 ;
     RECT  81.936 81.011 82.056 81.205 ;
     RECT  83.232 81.011 86.52 81.205 ;
     RECT  96.96 81.107 97.56 81.251 ;
     RECT  48.48 78.131 48.744 81.253 ;
     RECT  78 80.677 78.84 81.253 ;
     RECT  83.232 81.205 87.288 81.299 ;
     RECT  18.48 80.869 19.08 81.301 ;
     RECT  61.056 75.733 62.112 81.301 ;
     RECT  78 81.253 79.704 81.301 ;
     RECT  99.6 79.715 107.064 81.301 ;
     RECT  44.976 78.997 47.112 81.349 ;
     RECT  48.48 81.253 49.32 81.349 ;
     RECT  108.24 80.483 127.032 81.349 ;
     RECT  17.856 81.301 19.08 81.397 ;
     RECT  33.024 81.157 35.208 81.443 ;
     RECT  7.68 72.565 8.112 81.445 ;
     RECT  29.28 80.005 29.712 81.445 ;
     RECT  57.936 81.349 57.96 81.445 ;
     RECT  64.368 78.181 64.392 81.445 ;
     RECT  75.024 81.301 75.24 81.445 ;
     RECT  77.472 81.301 79.704 81.445 ;
     RECT  57.936 81.445 58.92 81.491 ;
     RECT  44.928 81.349 49.32 81.493 ;
     RECT  58.08 81.491 58.92 81.493 ;
     RECT  64.368 81.445 64.728 81.493 ;
     RECT  41.904 77.941 41.928 81.539 ;
     RECT  61.056 81.301 63 81.539 ;
     RECT  67.056 74.293 67.512 81.539 ;
     RECT  99.504 81.301 107.064 81.539 ;
     RECT  56.4 77.315 56.712 81.541 ;
     RECT  44.352 81.493 49.32 81.589 ;
     RECT  61.536 81.539 63 81.589 ;
     RECT  64.368 81.493 65.304 81.589 ;
     RECT  72.144 76.021 73.224 81.589 ;
     RECT  72.144 81.589 73.272 81.637 ;
     RECT  51 79.045 51.864 81.685 ;
     RECT  99.6 81.539 107.064 81.685 ;
     RECT  108.24 81.349 127.224 81.685 ;
     RECT  99.6 81.685 127.224 81.731 ;
     RECT  24 73.957 24.84 81.733 ;
     RECT  7.68 81.445 8.856 81.781 ;
     RECT  43.68 81.589 49.32 81.781 ;
     RECT  74.736 81.445 75.576 81.781 ;
     RECT  43.68 81.781 49.56 81.829 ;
     RECT  61.536 81.589 65.304 81.829 ;
     RECT  88.272 81.061 92.76 81.829 ;
     RECT  93.984 81.107 95.448 81.829 ;
     RECT  33.024 81.443 33.24 81.877 ;
     RECT  51 81.685 52.296 81.877 ;
     RECT  74.736 81.781 76.2 81.877 ;
     RECT  77.424 81.445 79.704 81.877 ;
     RECT  13.2 81.011 13.512 81.925 ;
     RECT  99.6 81.731 106.92 81.971 ;
     RECT  16.464 81.397 19.08 82.021 ;
     RECT  20.256 76.789 21.816 82.021 ;
     RECT  55.296 81.541 56.712 82.021 ;
     RECT  74.736 81.877 79.704 82.021 ;
     RECT  80.832 81.205 82.056 82.021 ;
     RECT  83.232 81.299 83.712 82.021 ;
     RECT  85.056 81.299 87.288 82.021 ;
     RECT  88.272 81.829 95.448 82.021 ;
     RECT  13.104 81.925 13.512 82.117 ;
     RECT  51 81.877 53.064 82.117 ;
     RECT  54.72 82.021 56.712 82.211 ;
     RECT  55.056 82.211 56.712 82.213 ;
     RECT  72.096 81.637 73.272 82.261 ;
     RECT  26.688 81.445 26.712 82.309 ;
     RECT  28.368 81.445 29.712 82.309 ;
     RECT  34.8 81.443 35.208 82.309 ;
     RECT  50.88 82.117 53.064 82.309 ;
     RECT  61.536 81.829 65.544 82.309 ;
     RECT  85.056 82.021 95.448 82.309 ;
     RECT  43.68 81.829 49.752 82.357 ;
     RECT  50.832 82.309 53.064 82.357 ;
     RECT  107.904 81.731 127.224 82.403 ;
     RECT  2.16 80.821 5.688 82.405 ;
     RECT  38.784 80.963 40.512 82.405 ;
     RECT  55.056 82.213 56.856 82.451 ;
     RECT  2.16 82.405 6.264 82.453 ;
     RECT  7.392 81.781 8.856 82.453 ;
     RECT  43.68 82.357 53.064 82.453 ;
     RECT  58.08 81.493 59.16 82.453 ;
     RECT  85.056 82.309 95.688 82.453 ;
     RECT  97.104 81.251 97.56 82.453 ;
     RECT  2.16 82.453 8.856 82.501 ;
     RECT  74.736 82.021 83.712 82.501 ;
     RECT  84.912 82.453 95.688 82.501 ;
     RECT  97.008 82.453 97.56 82.501 ;
     RECT  72.096 82.261 73.512 82.549 ;
     RECT  74.736 82.501 97.56 82.549 ;
     RECT  23.904 81.733 25.656 82.645 ;
     RECT  26.688 82.309 30.024 82.645 ;
     RECT  16.464 82.021 21.816 82.691 ;
     RECT  23.904 82.645 30.024 82.691 ;
     RECT  38.784 82.405 40.776 82.691 ;
     RECT  43.68 82.453 53.448 82.691 ;
     RECT  61.536 82.309 66.12 82.691 ;
     RECT  108.24 82.403 127.224 82.691 ;
     RECT  1.632 82.501 8.856 82.739 ;
     RECT  37.296 81.253 37.32 82.739 ;
     RECT  110.16 82.691 127.224 82.739 ;
     RECT  23.904 82.691 24.312 82.741 ;
     RECT  74.736 82.549 97.752 82.741 ;
     RECT  1.632 82.739 3.912 82.787 ;
     RECT  13.104 82.117 13.608 82.787 ;
     RECT  19.92 82.691 21.048 82.787 ;
     RECT  112.704 82.739 127.224 82.787 ;
     RECT  39.744 82.691 40.776 82.837 ;
     RECT  23.184 82.741 24.312 82.883 ;
     RECT  58.08 82.453 60.12 82.885 ;
     RECT  61.536 82.691 63.528 82.885 ;
     RECT  25.632 82.691 30.024 82.979 ;
     RECT  0.384 80.629 0.408 82.981 ;
     RECT  112.704 82.787 113.544 83.027 ;
     RECT  0.096 82.981 0.408 83.029 ;
     RECT  1.632 82.787 3.864 83.029 ;
     RECT  70.272 81.301 70.68 83.125 ;
     RECT  71.808 82.549 73.512 83.125 ;
     RECT  25.632 82.979 25.656 83.267 ;
     RECT  26.928 82.979 30.024 83.267 ;
     RECT  32.448 81.877 33.24 83.267 ;
     RECT  44.352 82.691 53.448 83.267 ;
     RECT  58.08 82.885 63.528 83.267 ;
     RECT  128.688 83.029 128.712 83.269 ;
     RECT  64.656 82.691 66.12 83.653 ;
     RECT  67.104 81.539 67.512 83.653 ;
     RECT  74.736 82.741 97.848 83.701 ;
     RECT  114.72 82.787 127.224 83.749 ;
     RECT  128.688 83.269 129.24 83.749 ;
     RECT  5.472 82.739 8.856 83.797 ;
     RECT  13.104 82.787 13.512 83.797 ;
     RECT  15.168 81.781 15.192 83.797 ;
     RECT  16.464 82.691 18.912 83.797 ;
     RECT  20.16 82.787 21.048 83.797 ;
     RECT  23.904 82.883 24.312 83.797 ;
     RECT  29.4 83.267 30.024 83.797 ;
     RECT  31.248 81.589 31.272 83.797 ;
     RECT  34.8 82.309 35.88 83.797 ;
     RECT  39.744 82.837 41.16 83.797 ;
     RECT  43.296 82.933 43.32 83.797 ;
     RECT  110.16 82.739 111.672 83.797 ;
     RECT  112.752 83.027 113.544 83.797 ;
     RECT  114.72 83.749 127.464 83.797 ;
     RECT  9.984 83.797 13.8 83.845 ;
     RECT  14.784 83.797 22.92 83.845 ;
     RECT  23.904 83.797 25.176 83.845 ;
     RECT  60.096 83.267 63.528 83.845 ;
     RECT  64.656 83.653 67.512 83.845 ;
     RECT  99.6 81.971 106.056 83.845 ;
     RECT  108.24 82.691 109.032 83.845 ;
     RECT  110.16 83.797 111.768 83.845 ;
     RECT  60.096 83.845 67.512 83.893 ;
     RECT  69.216 81.781 69.24 83.893 ;
     RECT  70.272 83.125 73.512 83.893 ;
     RECT  74.736 83.701 98.616 83.893 ;
     RECT  99.6 83.845 111.768 83.893 ;
     RECT  55.056 82.451 56.808 84.133 ;
     RECT  5.472 83.797 9 84.181 ;
     RECT  9.984 83.845 25.176 84.181 ;
     RECT  60.096 83.893 111.768 84.181 ;
     RECT  112.752 83.797 127.464 84.181 ;
     RECT  44.784 83.267 53.448 84.229 ;
     RECT  0.096 83.029 3.864 84.277 ;
     RECT  5.472 84.181 25.176 84.277 ;
     RECT  26.928 83.267 28.392 84.277 ;
     RECT  29.4 83.797 31.272 84.277 ;
     RECT  0.096 84.277 25.944 84.325 ;
     RECT  26.928 84.277 31.272 84.325 ;
     RECT  33.024 84.277 33.528 84.325 ;
     RECT  34.8 83.797 36.84 84.325 ;
     RECT  38.064 84.277 38.088 84.325 ;
     RECT  39.744 83.797 41.64 84.325 ;
     RECT  42.912 83.797 43.32 84.325 ;
     RECT  44.784 84.229 53.544 84.325 ;
     RECT  55.056 84.133 56.856 84.325 ;
     RECT  58.08 83.267 58.92 84.325 ;
     RECT  60.096 84.181 127.464 84.325 ;
     RECT  128.448 83.749 129.24 84.757 ;
     RECT  0.096 84.325 127.464 84.949 ;
     RECT  128.448 84.757 129.48 84.949 ;
     RECT  0.096 84.949 129.48 86.316 ;
     RECT  0.12 86.316 0.384 86.352 ;
     RECT  0.408 86.316 0.624 86.352 ;
     RECT  0.648 86.316 0.864 86.352 ;
     RECT  0.888 86.316 1.104 86.352 ;
     RECT  1.128 86.316 1.392 86.352 ;
     RECT  1.416 86.316 1.632 86.352 ;
     RECT  1.656 86.316 1.872 86.352 ;
     RECT  1.896 86.316 2.16 86.352 ;
     RECT  2.184 86.316 2.4 86.352 ;
     RECT  2.424 86.316 2.64 86.352 ;
     RECT  2.664 86.316 2.88 86.352 ;
     RECT  2.904 86.316 3.168 86.352 ;
     RECT  3.192 86.316 3.408 86.352 ;
     RECT  3.432 86.316 3.648 86.352 ;
     RECT  3.672 86.316 3.888 86.352 ;
     RECT  3.912 86.316 4.176 86.352 ;
     RECT  4.2 86.316 4.416 86.352 ;
     RECT  4.44 86.316 4.656 86.352 ;
     RECT  4.68 86.316 4.944 86.352 ;
     RECT  4.968 86.316 5.184 86.352 ;
     RECT  5.208 86.316 5.424 86.352 ;
     RECT  5.448 86.316 5.664 86.352 ;
     RECT  5.688 86.316 5.952 86.352 ;
     RECT  5.976 86.316 6.192 86.352 ;
     RECT  6.216 86.316 6.432 86.352 ;
     RECT  6.456 86.316 6.72 86.352 ;
     RECT  6.744 86.316 6.96 86.352 ;
     RECT  6.984 86.316 7.2 86.352 ;
     RECT  7.224 86.316 7.44 86.352 ;
     RECT  7.464 86.316 7.728 86.352 ;
     RECT  7.752 86.316 7.968 86.352 ;
     RECT  7.992 86.316 8.208 86.352 ;
     RECT  8.232 86.316 8.448 86.352 ;
     RECT  8.472 86.316 8.736 86.352 ;
     RECT  8.76 86.316 8.976 86.352 ;
     RECT  9 86.316 9.216 86.352 ;
     RECT  9.24 86.316 9.504 86.352 ;
     RECT  9.528 86.316 9.744 86.352 ;
     RECT  9.768 86.316 9.984 86.352 ;
     RECT  10.008 86.316 10.224 86.352 ;
     RECT  10.248 86.316 10.512 86.352 ;
     RECT  10.536 86.316 10.752 86.352 ;
     RECT  10.776 86.316 10.992 86.352 ;
     RECT  11.016 86.316 11.232 86.352 ;
     RECT  11.256 86.316 11.52 86.352 ;
     RECT  11.544 86.316 11.76 86.352 ;
     RECT  11.784 86.316 12 86.352 ;
     RECT  12.024 86.316 12.288 86.352 ;
     RECT  12.312 86.316 12.528 86.352 ;
     RECT  12.552 86.316 12.768 86.352 ;
     RECT  12.792 86.316 13.008 86.352 ;
     RECT  13.032 86.316 13.296 86.352 ;
     RECT  13.32 86.316 13.536 86.352 ;
     RECT  13.56 86.316 13.776 86.352 ;
     RECT  13.8 86.316 14.016 86.352 ;
     RECT  14.04 86.316 14.304 86.352 ;
     RECT  14.328 86.316 14.544 86.352 ;
     RECT  14.568 86.316 14.784 86.352 ;
     RECT  14.808 86.316 15.072 86.352 ;
     RECT  15.096 86.316 15.312 86.352 ;
     RECT  15.336 86.316 15.552 86.352 ;
     RECT  15.576 86.316 15.792 86.352 ;
     RECT  15.816 86.316 16.08 86.352 ;
     RECT  16.104 86.316 16.32 86.352 ;
     RECT  16.344 86.316 16.56 86.352 ;
     RECT  16.584 86.316 16.8 86.352 ;
     RECT  16.824 86.316 17.088 86.352 ;
     RECT  17.112 86.316 17.328 86.352 ;
     RECT  17.352 86.316 17.568 86.352 ;
     RECT  17.592 86.316 17.856 86.352 ;
     RECT  17.88 86.316 18.096 86.352 ;
     RECT  18.12 86.316 18.336 86.352 ;
     RECT  18.36 86.316 18.576 86.352 ;
     RECT  18.6 86.316 18.864 86.352 ;
     RECT  18.888 86.316 19.104 86.352 ;
     RECT  19.128 86.316 19.344 86.352 ;
     RECT  19.368 86.316 19.584 86.352 ;
     RECT  19.608 86.316 19.872 86.352 ;
     RECT  19.896 86.316 20.112 86.352 ;
     RECT  20.136 86.316 20.352 86.352 ;
     RECT  20.376 86.316 20.64 86.352 ;
     RECT  20.664 86.316 20.88 86.352 ;
     RECT  20.904 86.316 21.12 86.352 ;
     RECT  21.144 86.316 21.36 86.352 ;
     RECT  21.384 86.316 21.648 86.352 ;
     RECT  21.672 86.316 21.888 86.352 ;
     RECT  21.912 86.316 22.128 86.352 ;
     RECT  22.152 86.316 22.368 86.352 ;
     RECT  22.392 86.316 22.656 86.352 ;
     RECT  22.68 86.316 22.896 86.352 ;
     RECT  22.92 86.316 23.136 86.352 ;
     RECT  23.16 86.316 23.424 86.352 ;
     RECT  23.448 86.316 23.664 86.352 ;
     RECT  23.688 86.316 23.904 86.352 ;
     RECT  23.928 86.316 24.144 86.352 ;
     RECT  24.168 86.316 24.432 86.352 ;
     RECT  24.456 86.316 24.672 86.352 ;
     RECT  24.696 86.316 24.912 86.352 ;
     RECT  24.936 86.316 25.152 86.352 ;
     RECT  25.176 86.316 25.44 86.352 ;
     RECT  25.464 86.316 25.68 86.352 ;
     RECT  25.704 86.316 25.92 86.352 ;
     RECT  25.944 86.316 26.208 86.352 ;
     RECT  26.232 86.316 26.448 86.352 ;
     RECT  26.472 86.316 26.688 86.352 ;
     RECT  26.712 86.316 26.928 86.352 ;
     RECT  26.952 86.316 27.216 86.352 ;
     RECT  27.24 86.316 27.456 86.352 ;
     RECT  27.48 86.316 27.696 86.352 ;
     RECT  27.72 86.316 27.936 86.352 ;
     RECT  27.96 86.316 28.224 86.352 ;
     RECT  28.248 86.316 28.464 86.352 ;
     RECT  28.488 86.316 28.704 86.352 ;
     RECT  28.728 86.316 28.992 86.352 ;
     RECT  29.016 86.316 29.232 86.352 ;
     RECT  29.256 86.316 29.472 86.352 ;
     RECT  29.496 86.316 29.712 86.352 ;
     RECT  29.736 86.316 30 86.352 ;
     RECT  30.024 86.316 30.24 86.352 ;
     RECT  30.264 86.316 30.48 86.352 ;
     RECT  30.504 86.316 30.72 86.352 ;
     RECT  30.744 86.316 31.008 86.352 ;
     RECT  31.032 86.316 31.248 86.352 ;
     RECT  31.272 86.316 31.488 86.352 ;
     RECT  31.512 86.316 31.776 86.352 ;
     RECT  31.8 86.316 32.016 86.352 ;
     RECT  32.04 86.316 32.256 86.352 ;
     RECT  32.28 86.316 32.496 86.352 ;
     RECT  32.52 86.316 32.784 86.352 ;
     RECT  32.808 86.316 33.024 86.352 ;
     RECT  33.048 86.316 33.264 86.352 ;
     RECT  33.288 86.316 33.504 86.352 ;
     RECT  33.528 86.316 33.792 86.352 ;
     RECT  33.816 86.316 34.032 86.352 ;
     RECT  34.056 86.316 34.272 86.352 ;
     RECT  34.296 86.316 34.56 86.352 ;
     RECT  34.584 86.316 34.8 86.352 ;
     RECT  34.824 86.316 35.04 86.352 ;
     RECT  35.064 86.316 35.28 86.352 ;
     RECT  35.304 86.316 35.568 86.352 ;
     RECT  35.592 86.316 35.808 86.352 ;
     RECT  35.832 86.316 36.048 86.352 ;
     RECT  36.072 86.316 36.288 86.352 ;
     RECT  36.312 86.316 36.576 86.352 ;
     RECT  36.6 86.316 36.816 86.352 ;
     RECT  36.84 86.316 37.056 86.352 ;
     RECT  37.08 86.316 37.344 86.352 ;
     RECT  37.368 86.316 37.584 86.352 ;
     RECT  37.608 86.316 37.824 86.352 ;
     RECT  37.848 86.316 38.064 86.352 ;
     RECT  38.088 86.316 38.352 86.352 ;
     RECT  38.376 86.316 38.592 86.352 ;
     RECT  38.616 86.316 38.832 86.352 ;
     RECT  38.856 86.316 39.12 86.352 ;
     RECT  39.144 86.316 39.36 86.352 ;
     RECT  39.384 86.316 39.6 86.352 ;
     RECT  39.624 86.316 39.84 86.352 ;
     RECT  39.864 86.316 40.128 86.352 ;
     RECT  40.152 86.316 40.368 86.352 ;
     RECT  40.392 86.316 40.608 86.352 ;
     RECT  40.632 86.316 40.848 86.352 ;
     RECT  40.872 86.316 41.136 86.352 ;
     RECT  41.16 86.316 41.376 86.352 ;
     RECT  41.4 86.316 41.616 86.352 ;
     RECT  41.64 86.316 41.904 86.352 ;
     RECT  41.928 86.316 42.144 86.352 ;
     RECT  42.168 86.316 42.384 86.352 ;
     RECT  42.408 86.316 42.624 86.352 ;
     RECT  42.648 86.316 42.912 86.352 ;
     RECT  42.936 86.316 43.152 86.352 ;
     RECT  43.176 86.316 43.392 86.352 ;
     RECT  43.416 86.316 43.632 86.352 ;
     RECT  43.656 86.316 43.92 86.352 ;
     RECT  43.944 86.316 44.16 86.352 ;
     RECT  44.184 86.316 44.4 86.352 ;
     RECT  44.424 86.316 44.688 86.352 ;
     RECT  44.712 86.316 44.928 86.352 ;
     RECT  44.952 86.316 45.168 86.352 ;
     RECT  45.192 86.316 45.408 86.352 ;
     RECT  45.432 86.316 45.696 86.352 ;
     RECT  45.72 86.316 45.936 86.352 ;
     RECT  45.96 86.316 46.176 86.352 ;
     RECT  46.2 86.316 46.416 86.352 ;
     RECT  46.44 86.316 46.704 86.352 ;
     RECT  46.728 86.316 46.944 86.352 ;
     RECT  46.968 86.316 47.184 86.352 ;
     RECT  47.208 86.316 47.472 86.352 ;
     RECT  47.496 86.316 47.712 86.352 ;
     RECT  47.736 86.316 47.952 86.352 ;
     RECT  47.976 86.316 48.192 86.352 ;
     RECT  48.216 86.316 48.48 86.352 ;
     RECT  48.504 86.316 48.72 86.352 ;
     RECT  48.744 86.316 48.96 86.352 ;
     RECT  48.984 86.316 49.2 86.352 ;
     RECT  49.224 86.316 49.488 86.352 ;
     RECT  49.512 86.316 49.728 86.352 ;
     RECT  49.752 86.316 49.968 86.352 ;
     RECT  49.992 86.316 50.256 86.352 ;
     RECT  50.28 86.316 50.496 86.352 ;
     RECT  50.52 86.316 50.736 86.352 ;
     RECT  50.76 86.316 50.976 86.352 ;
     RECT  51 86.316 51.264 86.352 ;
     RECT  51.288 86.316 51.504 86.352 ;
     RECT  51.528 86.316 51.744 86.352 ;
     RECT  51.768 86.316 51.984 86.352 ;
     RECT  52.008 86.316 52.272 86.352 ;
     RECT  52.296 86.316 52.512 86.352 ;
     RECT  52.536 86.316 52.752 86.352 ;
     RECT  52.776 86.316 53.04 86.352 ;
     RECT  53.064 86.316 53.28 86.352 ;
     RECT  53.304 86.316 53.52 86.352 ;
     RECT  53.544 86.316 53.76 86.352 ;
     RECT  53.784 86.316 54.048 86.352 ;
     RECT  54.072 86.316 54.288 86.352 ;
     RECT  54.312 86.316 54.528 86.352 ;
     RECT  54.552 86.316 54.768 86.352 ;
     RECT  54.792 86.316 55.056 86.352 ;
     RECT  55.08 86.316 55.296 86.352 ;
     RECT  55.32 86.316 55.536 86.352 ;
     RECT  55.56 86.316 55.824 86.352 ;
     RECT  55.848 86.316 56.064 86.352 ;
     RECT  56.088 86.316 56.304 86.352 ;
     RECT  56.328 86.316 56.544 86.352 ;
     RECT  56.568 86.316 56.832 86.352 ;
     RECT  56.856 86.316 57.072 86.352 ;
     RECT  57.096 86.316 57.312 86.352 ;
     RECT  57.336 86.316 57.552 86.352 ;
     RECT  57.576 86.316 57.84 86.352 ;
     RECT  57.864 86.316 58.08 86.352 ;
     RECT  58.104 86.316 58.32 86.352 ;
     RECT  58.344 86.316 58.608 86.352 ;
     RECT  58.632 86.316 58.848 86.352 ;
     RECT  58.872 86.316 59.088 86.352 ;
     RECT  59.112 86.316 59.328 86.352 ;
     RECT  59.352 86.316 59.616 86.352 ;
     RECT  59.64 86.316 59.856 86.352 ;
     RECT  59.88 86.316 60.096 86.352 ;
     RECT  60.12 86.316 60.336 86.352 ;
     RECT  60.36 86.316 60.624 86.352 ;
     RECT  60.648 86.316 60.864 86.352 ;
     RECT  60.888 86.316 61.104 86.352 ;
     RECT  61.128 86.316 61.392 86.352 ;
     RECT  61.416 86.316 61.632 86.352 ;
     RECT  61.656 86.316 61.872 86.352 ;
     RECT  61.896 86.316 62.112 86.352 ;
     RECT  62.136 86.316 62.4 86.352 ;
     RECT  62.424 86.316 62.64 86.352 ;
     RECT  62.664 86.316 62.88 86.352 ;
     RECT  62.904 86.316 63.12 86.352 ;
     RECT  63.144 86.316 63.408 86.352 ;
     RECT  63.432 86.316 63.648 86.352 ;
     RECT  63.672 86.316 63.888 86.352 ;
     RECT  63.912 86.316 64.176 86.352 ;
     RECT  64.2 86.316 64.416 86.352 ;
     RECT  64.44 86.316 64.656 86.352 ;
     RECT  64.68 86.316 64.896 86.352 ;
     RECT  64.92 86.316 65.184 86.352 ;
     RECT  65.208 86.316 65.424 86.352 ;
     RECT  65.448 86.316 65.664 86.352 ;
     RECT  65.688 86.316 65.904 86.352 ;
     RECT  65.928 86.316 66.192 86.352 ;
     RECT  66.216 86.316 66.432 86.352 ;
     RECT  66.456 86.316 66.672 86.352 ;
     RECT  66.696 86.316 66.96 86.352 ;
     RECT  66.984 86.316 67.2 86.352 ;
     RECT  67.224 86.316 67.44 86.352 ;
     RECT  67.464 86.316 67.68 86.352 ;
     RECT  67.704 86.316 67.968 86.352 ;
     RECT  67.992 86.316 68.208 86.352 ;
     RECT  68.232 86.316 68.448 86.352 ;
     RECT  68.472 86.316 68.688 86.352 ;
     RECT  68.712 86.316 68.976 86.352 ;
     RECT  69 86.316 69.216 86.352 ;
     RECT  69.24 86.316 69.456 86.352 ;
     RECT  69.48 86.316 69.744 86.352 ;
     RECT  69.768 86.316 69.984 86.352 ;
     RECT  70.008 86.316 70.224 86.352 ;
     RECT  70.248 86.316 70.464 86.352 ;
     RECT  70.488 86.316 70.752 86.352 ;
     RECT  70.776 86.316 70.992 86.352 ;
     RECT  71.016 86.316 71.232 86.352 ;
     RECT  71.256 86.316 71.52 86.352 ;
     RECT  71.544 86.316 71.76 86.352 ;
     RECT  71.784 86.316 72 86.352 ;
     RECT  72.024 86.316 72.24 86.352 ;
     RECT  72.264 86.316 72.528 86.352 ;
     RECT  72.552 86.316 72.768 86.352 ;
     RECT  72.792 86.316 73.008 86.352 ;
     RECT  73.032 86.316 73.248 86.352 ;
     RECT  73.272 86.316 73.536 86.352 ;
     RECT  73.56 86.316 73.776 86.352 ;
     RECT  73.8 86.316 74.016 86.352 ;
     RECT  74.04 86.316 74.304 86.352 ;
     RECT  74.328 86.316 74.544 86.352 ;
     RECT  74.568 86.316 74.784 86.352 ;
     RECT  74.808 86.316 75.024 86.352 ;
     RECT  75.048 86.316 75.312 86.352 ;
     RECT  75.336 86.316 75.552 86.352 ;
     RECT  75.576 86.316 75.792 86.352 ;
     RECT  75.816 86.316 76.032 86.352 ;
     RECT  76.056 86.316 76.32 86.352 ;
     RECT  76.344 86.316 76.56 86.352 ;
     RECT  76.584 86.316 76.8 86.352 ;
     RECT  76.824 86.316 77.088 86.352 ;
     RECT  77.112 86.316 77.328 86.352 ;
     RECT  77.352 86.316 77.568 86.352 ;
     RECT  77.592 86.316 77.808 86.352 ;
     RECT  77.832 86.316 78.096 86.352 ;
     RECT  78.12 86.316 78.336 86.352 ;
     RECT  78.36 86.316 78.576 86.352 ;
     RECT  78.6 86.316 78.816 86.352 ;
     RECT  78.84 86.316 79.104 86.352 ;
     RECT  79.128 86.316 79.344 86.352 ;
     RECT  79.368 86.316 79.584 86.352 ;
     RECT  79.608 86.316 79.872 86.352 ;
     RECT  79.896 86.316 80.112 86.352 ;
     RECT  80.136 86.316 80.352 86.352 ;
     RECT  80.376 86.316 80.592 86.352 ;
     RECT  80.616 86.316 80.88 86.352 ;
     RECT  80.904 86.316 81.12 86.352 ;
     RECT  81.144 86.316 81.36 86.352 ;
     RECT  81.384 86.316 81.6 86.352 ;
     RECT  81.624 86.316 81.888 86.352 ;
     RECT  81.912 86.316 82.128 86.352 ;
     RECT  82.152 86.316 82.368 86.352 ;
     RECT  82.392 86.316 82.656 86.352 ;
     RECT  82.68 86.316 82.896 86.352 ;
     RECT  82.92 86.316 83.136 86.352 ;
     RECT  83.16 86.316 83.376 86.352 ;
     RECT  83.4 86.316 83.664 86.352 ;
     RECT  83.688 86.316 83.904 86.352 ;
     RECT  83.928 86.316 84.144 86.352 ;
     RECT  84.168 86.316 84.384 86.352 ;
     RECT  84.408 86.316 84.672 86.352 ;
     RECT  84.696 86.316 84.912 86.352 ;
     RECT  84.936 86.316 85.152 86.352 ;
     RECT  85.176 86.316 85.44 86.352 ;
     RECT  85.464 86.316 85.68 86.352 ;
     RECT  85.704 86.316 85.92 86.352 ;
     RECT  85.944 86.316 86.16 86.352 ;
     RECT  86.184 86.316 86.448 86.352 ;
     RECT  86.472 86.316 86.688 86.352 ;
     RECT  86.712 86.316 86.928 86.352 ;
     RECT  86.952 86.316 87.168 86.352 ;
     RECT  87.192 86.316 87.456 86.352 ;
     RECT  87.48 86.316 87.696 86.352 ;
     RECT  87.72 86.316 87.936 86.352 ;
     RECT  87.96 86.316 88.224 86.352 ;
     RECT  88.248 86.316 88.464 86.352 ;
     RECT  88.488 86.316 88.704 86.352 ;
     RECT  88.728 86.316 88.944 86.352 ;
     RECT  88.968 86.316 89.232 86.352 ;
     RECT  89.256 86.316 89.472 86.352 ;
     RECT  89.496 86.316 89.712 86.352 ;
     RECT  89.736 86.316 89.952 86.352 ;
     RECT  89.976 86.316 90.24 86.352 ;
     RECT  90.264 86.316 90.48 86.352 ;
     RECT  90.504 86.316 90.72 86.352 ;
     RECT  90.744 86.316 91.008 86.352 ;
     RECT  91.032 86.316 91.248 86.352 ;
     RECT  91.272 86.316 91.488 86.352 ;
     RECT  91.512 86.316 91.728 86.352 ;
     RECT  91.752 86.316 92.016 86.352 ;
     RECT  92.04 86.316 92.256 86.352 ;
     RECT  92.28 86.316 92.496 86.352 ;
     RECT  92.52 86.316 92.736 86.352 ;
     RECT  92.76 86.316 93.024 86.352 ;
     RECT  93.048 86.316 93.264 86.352 ;
     RECT  93.288 86.316 93.504 86.352 ;
     RECT  93.528 86.316 93.792 86.352 ;
     RECT  93.816 86.316 94.032 86.352 ;
     RECT  94.056 86.316 94.272 86.352 ;
     RECT  94.296 86.316 94.512 86.352 ;
     RECT  94.536 86.316 94.8 86.352 ;
     RECT  94.824 86.316 95.04 86.352 ;
     RECT  95.064 86.316 95.28 86.352 ;
     RECT  95.304 86.316 95.52 86.352 ;
     RECT  95.544 86.316 95.808 86.352 ;
     RECT  95.832 86.316 96.048 86.352 ;
     RECT  96.072 86.316 96.288 86.352 ;
     RECT  96.312 86.316 96.576 86.352 ;
     RECT  96.6 86.316 96.816 86.352 ;
     RECT  96.84 86.316 97.056 86.352 ;
     RECT  97.08 86.316 97.296 86.352 ;
     RECT  97.32 86.316 97.584 86.352 ;
     RECT  97.608 86.316 97.824 86.352 ;
     RECT  97.848 86.316 98.064 86.352 ;
     RECT  98.088 86.316 98.304 86.352 ;
     RECT  98.328 86.316 98.592 86.352 ;
     RECT  98.616 86.316 98.832 86.352 ;
     RECT  98.856 86.316 99.072 86.352 ;
     RECT  99.096 86.316 99.36 86.352 ;
     RECT  99.384 86.316 99.6 86.352 ;
     RECT  99.624 86.316 99.84 86.352 ;
     RECT  99.864 86.316 100.08 86.352 ;
     RECT  100.104 86.316 100.368 86.352 ;
     RECT  100.392 86.316 100.608 86.352 ;
     RECT  100.632 86.316 100.848 86.352 ;
     RECT  100.872 86.316 101.088 86.352 ;
     RECT  101.112 86.316 101.376 86.352 ;
     RECT  101.4 86.316 101.616 86.352 ;
     RECT  101.64 86.316 101.856 86.352 ;
     RECT  101.88 86.316 102.144 86.352 ;
     RECT  102.168 86.316 102.384 86.352 ;
     RECT  102.408 86.316 102.624 86.352 ;
     RECT  102.648 86.316 102.864 86.352 ;
     RECT  102.888 86.316 103.152 86.352 ;
     RECT  103.176 86.316 103.392 86.352 ;
     RECT  103.416 86.316 103.632 86.352 ;
     RECT  103.656 86.316 103.92 86.352 ;
     RECT  103.944 86.316 104.16 86.352 ;
     RECT  104.184 86.316 104.4 86.352 ;
     RECT  104.424 86.316 104.64 86.352 ;
     RECT  104.664 86.316 104.928 86.352 ;
     RECT  104.952 86.316 105.168 86.352 ;
     RECT  105.192 86.316 105.408 86.352 ;
     RECT  105.432 86.316 105.648 86.352 ;
     RECT  105.672 86.316 105.936 86.352 ;
     RECT  105.96 86.316 106.176 86.352 ;
     RECT  106.2 86.316 106.416 86.352 ;
     RECT  106.44 86.316 106.704 86.352 ;
     RECT  106.728 86.316 106.944 86.352 ;
     RECT  106.968 86.316 107.184 86.352 ;
     RECT  107.208 86.316 107.424 86.352 ;
     RECT  107.448 86.316 107.712 86.352 ;
     RECT  107.736 86.316 107.952 86.352 ;
     RECT  107.976 86.316 108.192 86.352 ;
     RECT  108.216 86.316 108.432 86.352 ;
     RECT  108.456 86.316 108.72 86.352 ;
     RECT  108.744 86.316 108.96 86.352 ;
     RECT  108.984 86.316 109.2 86.352 ;
     RECT  109.224 86.316 109.488 86.352 ;
     RECT  109.512 86.316 109.728 86.352 ;
     RECT  109.752 86.316 109.968 86.352 ;
     RECT  109.992 86.316 110.208 86.352 ;
     RECT  110.232 86.316 110.496 86.352 ;
     RECT  110.52 86.316 110.736 86.352 ;
     RECT  110.76 86.316 110.976 86.352 ;
     RECT  111 86.316 111.216 86.352 ;
     RECT  111.24 86.316 111.504 86.352 ;
     RECT  111.528 86.316 111.744 86.352 ;
     RECT  111.768 86.316 111.984 86.352 ;
     RECT  112.008 86.316 112.272 86.352 ;
     RECT  112.296 86.316 112.512 86.352 ;
     RECT  112.536 86.316 112.752 86.352 ;
     RECT  112.776 86.316 112.992 86.352 ;
     RECT  113.016 86.316 113.28 86.352 ;
     RECT  113.304 86.316 113.52 86.352 ;
     RECT  113.544 86.316 113.76 86.352 ;
     RECT  113.784 86.316 114 86.352 ;
     RECT  114.024 86.316 114.288 86.352 ;
     RECT  114.312 86.316 114.528 86.352 ;
     RECT  114.552 86.316 114.768 86.352 ;
     RECT  114.792 86.316 115.056 86.352 ;
     RECT  115.08 86.316 115.296 86.352 ;
     RECT  115.32 86.316 115.536 86.352 ;
     RECT  115.56 86.316 115.776 86.352 ;
     RECT  115.8 86.316 116.064 86.352 ;
     RECT  116.088 86.316 116.304 86.352 ;
     RECT  116.328 86.316 116.544 86.352 ;
     RECT  116.568 86.316 116.784 86.352 ;
     RECT  116.808 86.316 117.072 86.352 ;
     RECT  117.096 86.316 117.312 86.352 ;
     RECT  117.336 86.316 117.552 86.352 ;
     RECT  117.576 86.316 117.84 86.352 ;
     RECT  117.864 86.316 118.08 86.352 ;
     RECT  118.104 86.316 118.32 86.352 ;
     RECT  118.344 86.316 118.56 86.352 ;
     RECT  118.584 86.316 118.848 86.352 ;
     RECT  118.872 86.316 119.088 86.352 ;
     RECT  119.112 86.316 119.328 86.352 ;
     RECT  119.352 86.316 119.568 86.352 ;
     RECT  119.592 86.316 119.856 86.352 ;
     RECT  119.88 86.316 120.096 86.352 ;
     RECT  120.12 86.316 120.336 86.352 ;
     RECT  120.36 86.316 120.624 86.352 ;
     RECT  120.648 86.316 120.864 86.352 ;
     RECT  120.888 86.316 121.104 86.352 ;
     RECT  121.128 86.316 121.344 86.352 ;
     RECT  121.368 86.316 121.632 86.352 ;
     RECT  121.656 86.316 121.872 86.352 ;
     RECT  121.896 86.316 122.112 86.352 ;
     RECT  122.136 86.316 122.352 86.352 ;
     RECT  122.376 86.316 122.64 86.352 ;
     RECT  122.664 86.316 122.88 86.352 ;
     RECT  122.904 86.316 123.12 86.352 ;
     RECT  123.144 86.316 123.408 86.352 ;
     RECT  123.432 86.316 123.648 86.352 ;
     RECT  123.672 86.316 123.888 86.352 ;
     RECT  123.912 86.316 124.128 86.352 ;
     RECT  124.152 86.316 124.416 86.352 ;
     RECT  124.44 86.316 124.656 86.352 ;
     RECT  124.68 86.316 124.896 86.352 ;
     RECT  124.92 86.316 125.136 86.352 ;
     RECT  125.16 86.316 125.424 86.352 ;
     RECT  125.448 86.316 125.664 86.352 ;
     RECT  125.688 86.316 125.904 86.352 ;
     RECT  125.928 86.316 126.192 86.352 ;
     RECT  126.216 86.316 126.432 86.352 ;
     RECT  126.456 86.316 126.672 86.352 ;
     RECT  126.696 86.316 126.912 86.352 ;
     RECT  126.936 86.316 127.2 86.352 ;
     RECT  127.224 86.316 127.44 86.352 ;
     RECT  127.464 86.316 127.68 86.352 ;
     RECT  127.704 86.316 127.92 86.352 ;
     RECT  127.944 86.316 128.208 86.352 ;
     RECT  128.232 86.316 128.448 86.352 ;
     RECT  128.472 86.316 128.688 86.352 ;
     RECT  128.712 86.316 128.976 86.352 ;
     RECT  129 86.316 129.216 86.352 ;
     RECT  129.24 86.316 129.456 86.352 ;
     RECT  121.512 4.501 122.88 5.557 ;
     RECT  122.904 4.789 124.272 5.747 ;
     RECT  121.608 5.557 122.88 8.579 ;
     RECT  121.512 8.579 122.88 9.731 ;
     RECT  121.512 9.731 122.976 10.597 ;
     RECT  121.704 10.597 122.976 11.843 ;
     RECT  121.512 11.843 122.976 13.811 ;
     RECT  83.712 16.261 84.816 71.701 ;
     RECT  121.512 18.419 122.976 20.485 ;
     RECT  121.752 20.485 122.976 22.787 ;
     RECT  123.576 21.299 123.672 22.741 ;
     RECT  121.512 22.787 122.976 24.565 ;
     RECT  121.512 24.565 122.544 30.757 ;
     RECT  122.568 24.611 123.648 25.621 ;
     RECT  122.568 26.483 123.648 29.989 ;
     RECT  99.912 28.741 101.136 51.637 ;
     RECT  121.512 30.757 122.496 30.899 ;
     RECT  121.512 30.899 123.072 32.293 ;
     RECT  121.512 32.293 122.544 33.683 ;
     RECT  121.512 35.605 122.88 39.061 ;
     RECT  121.608 39.061 122.88 41.029 ;
     RECT  121.608 41.029 122.784 41.699 ;
     RECT  121.512 41.699 122.784 43.285 ;
     RECT  121.512 43.285 122.544 44.483 ;
     RECT  2.712 44.437 3.888 48.421 ;
     RECT  121.512 44.483 122.688 46.069 ;
     RECT  121.512 47.459 122.592 50.771 ;
     RECT  121.512 50.771 122.736 52.405 ;
     RECT  100.008 51.637 101.136 64.981 ;
     RECT  121.512 53.939 122.832 56.917 ;
     RECT  87.288 55.525 88.56 68.197 ;
     RECT  121.992 57.059 123.648 58.117 ;
     RECT  122.52 58.117 123.648 58.979 ;
     RECT  121.512 58.163 122.496 58.979 ;
     RECT  110.712 58.357 112.176 64.933 ;
     RECT  123.312 58.979 123.648 60.373 ;
     RECT  123.312 61.619 123.648 62.581 ;
     RECT  110.712 64.933 112.08 67.861 ;
     RECT  100.104 64.981 101.136 67.333 ;
     RECT  94.872 66.565 96.288 69.779 ;
     RECT  81.432 67.237 82.656 72.133 ;
     RECT  116.112 67.333 117.264 68.053 ;
     RECT  121.512 67.669 122.496 70.259 ;
     RECT  104.88 67.715 105 68.245 ;
     RECT  110.712 67.861 111.984 68.533 ;
     RECT  103.56 68.245 105 68.869 ;
     RECT  113.928 68.917 115.152 69.445 ;
     RECT  92.904 69.109 94.2 69.829 ;
     RECT  113.928 69.445 115.008 69.587 ;
     RECT  96.312 69.493 97.776 69.779 ;
     RECT  113.928 69.587 115.152 70.259 ;
     RECT  97.8 69.731 97.896 70.885 ;
     RECT  118.344 69.733 119.712 69.829 ;
     RECT  94.872 69.779 97.776 70.357 ;
     RECT  92.952 69.829 94.2 69.877 ;
     RECT  118.344 69.829 119.664 70.597 ;
     RECT  93.096 69.877 94.2 70.405 ;
     RECT  113.928 70.259 115.2 70.885 ;
     RECT  95.592 70.357 97.776 70.595 ;
     RECT  93.096 70.405 94.08 71.509 ;
     RECT  95.4 70.595 97.776 71.173 ;
     RECT  118.344 70.597 119.568 72.037 ;
     RECT  97.8 70.885 99.312 71.699 ;
     RECT  114.024 70.885 115.2 72.277 ;
     RECT  95.4 71.173 96.384 71.267 ;
     RECT  96.408 71.173 97.776 72.035 ;
     RECT  95.112 71.267 96.384 72.035 ;
     RECT  111 71.315 112.08 72.277 ;
     RECT  84.888 71.747 84.936 72.613 ;
     RECT  97.008 72.035 97.776 72.419 ;
     RECT  118.344 72.037 119.424 72.949 ;
     RECT  81.432 72.133 82.416 73.189 ;
     RECT  97.008 72.419 97.032 72.421 ;
     RECT  84.888 72.613 86.208 72.709 ;
     RECT  86.232 72.613 87.264 72.851 ;
     RECT  121.512 72.757 122.64 73.333 ;
     RECT  97.008 72.803 97.032 73.957 ;
     RECT  86.04 72.851 87.264 73.861 ;
     RECT  92.328 72.995 93.408 73.139 ;
     RECT  86.04 73.861 87.168 75.205 ;
     RECT  94.872 74.101 96.288 74.245 ;
     RECT  98.88 74.243 99.024 75.205 ;
     RECT  94.872 74.867 96.432 75.011 ;
     RECT  14.04 74.869 15.12 79.859 ;
     RECT  94.872 75.011 95.016 75.829 ;
     RECT  125.016 75.109 126.144 75.157 ;
     RECT  96.96 75.155 97.032 75.205 ;
     RECT  125.016 75.157 126 75.205 ;
     RECT  96.96 75.205 98.448 75.685 ;
     RECT  80.976 75.347 81.216 75.923 ;
     RECT  85.512 75.491 86.784 76.307 ;
     RECT  96.96 75.685 97.344 76.261 ;
     RECT  97.368 75.685 98.448 76.117 ;
     RECT  59.976 75.781 61.056 81.011 ;
     RECT  94.968 75.829 95.016 76.213 ;
     RECT  80.976 75.923 81.936 76.405 ;
     RECT  87.528 75.971 88.56 77.941 ;
     RECT  71.064 76.021 72.144 81.011 ;
     RECT  84.84 76.307 86.784 76.789 ;
     RECT  18.912 76.357 20.256 77.269 ;
     RECT  80.952 76.405 81.936 76.547 ;
     RECT  80.928 76.547 81.936 76.645 ;
     RECT  80.664 76.645 81.936 77.509 ;
     RECT  98.328 76.691 99.456 79.379 ;
     RECT  84.84 76.789 86.016 76.979 ;
     RECT  95.016 76.789 96.336 77.171 ;
     RECT  6.696 76.885 7.68 81.011 ;
     RECT  84.504 76.979 86.016 78.469 ;
     RECT  125.16 76.979 126.432 78.131 ;
     RECT  86.04 77.027 87.264 77.555 ;
     RECT  19.032 77.269 20.256 77.797 ;
     RECT  86.04 77.555 87.456 79.571 ;
     RECT  93.096 77.557 94.2 77.749 ;
     RECT  80.664 77.651 81.936 77.795 ;
     RECT  19.08 77.797 20.256 82.021 ;
     RECT  91.32 77.843 92.304 79.283 ;
     RECT  46.344 77.893 47.856 77.989 ;
     RECT  40.728 77.941 41.904 80.963 ;
     RECT  47.112 78.131 48.48 81.349 ;
     RECT  125.16 78.131 126.6 78.517 ;
     RECT  94.512 78.323 95.016 79.765 ;
     RECT  125.304 78.517 126.6 78.613 ;
     RECT  125.352 78.613 126.6 79.045 ;
     RECT  125.4 79.045 126.6 79.141 ;
     RECT  5.688 79.189 6.672 81.011 ;
     RECT  89.4 79.235 90.768 79.859 ;
     RECT  98.328 79.379 99.6 79.669 ;
     RECT  86.04 79.571 86.52 79.669 ;
     RECT  86.376 79.669 86.52 80.917 ;
     RECT  98.424 79.669 99.6 81.059 ;
     RECT  107.064 79.715 108.192 80.483 ;
     RECT  90.792 79.811 91.32 79.859 ;
     RECT  89.4 79.859 91.32 80.437 ;
     RECT  95.928 79.861 97.392 80.149 ;
     RECT  96.264 80.149 97.392 80.341 ;
     RECT  92.88 80.435 93.888 80.819 ;
     RECT  89.64 80.437 91.32 80.917 ;
     RECT  107.064 80.483 108.24 81.685 ;
     RECT  4.536 80.725 5.664 80.821 ;
     RECT  92.88 80.819 93.984 80.917 ;
     RECT  89.64 80.917 91.536 81.013 ;
     RECT  91.56 80.917 93.984 80.965 ;
     RECT  35.208 80.963 35.256 82.309 ;
     RECT  40.512 80.963 41.904 81.539 ;
     RECT  80.856 80.965 81.936 81.205 ;
     RECT  92.76 80.965 93.984 81.829 ;
     RECT  5.688 81.011 7.68 81.781 ;
     RECT  13.512 81.011 13.608 82.117 ;
     RECT  59.952 81.011 61.056 81.445 ;
     RECT  71.04 81.011 72.144 81.301 ;
     RECT  82.056 81.011 83.232 82.021 ;
     RECT  88.08 81.011 88.272 81.205 ;
     RECT  89.64 81.013 91.104 81.061 ;
     RECT  98.232 81.059 99.6 81.107 ;
     RECT  37.512 81.061 38.784 81.203 ;
     RECT  95.448 81.107 96.96 81.251 ;
     RECT  97.56 81.107 97.752 82.549 ;
     RECT  99.504 81.107 99.6 81.301 ;
     RECT  37.488 81.203 38.784 81.253 ;
     RECT  87.288 81.205 88.272 82.021 ;
     RECT  95.448 81.251 97.104 82.309 ;
     RECT  37.32 81.253 38.784 82.691 ;
     RECT  79.704 81.253 80.832 82.021 ;
     RECT  83.712 81.299 85.056 82.453 ;
     RECT  63 81.301 64.368 81.589 ;
     RECT  70.68 81.301 72.144 81.637 ;
     RECT  56.712 81.349 57.936 81.491 ;
     RECT  58.92 81.445 61.056 81.493 ;
     RECT  73.224 81.445 74.736 81.589 ;
     RECT  56.712 81.491 58.08 82.213 ;
     RECT  59.16 81.493 61.056 81.539 ;
     RECT  40.512 81.539 41.16 82.405 ;
     RECT  59.16 81.539 61.536 82.453 ;
     RECT  67.056 81.539 67.104 81.829 ;
     RECT  73.272 81.589 74.736 82.261 ;
     RECT  70.68 81.637 72.096 82.549 ;
     RECT  106.92 81.731 107.904 81.971 ;
     RECT  25.656 81.733 26.688 82.645 ;
     RECT  5.688 81.781 7.392 82.405 ;
     RECT  15.192 81.781 16.464 83.797 ;
     RECT  49.56 81.781 51 81.829 ;
     RECT  69.24 81.781 70.272 83.893 ;
     RECT  76.2 81.781 77.424 81.877 ;
     RECT  49.752 81.829 51 82.117 ;
     RECT  65.544 81.829 67.104 82.309 ;
     RECT  31.272 81.877 32.448 83.267 ;
     RECT  49.752 82.117 50.88 82.309 ;
     RECT  56.856 82.213 58.08 82.451 ;
     RECT  73.512 82.261 74.736 83.893 ;
     RECT  30.024 82.309 31.248 83.797 ;
     RECT  35.88 82.309 37.296 82.739 ;
     RECT  49.752 82.309 50.832 82.357 ;
     RECT  66.12 82.309 67.104 83.653 ;
     RECT  95.688 82.309 97.104 82.453 ;
     RECT  107.904 82.403 108.24 83.845 ;
     RECT  6.264 82.405 7.392 82.453 ;
     RECT  40.776 82.405 41.16 82.837 ;
     RECT  56.808 82.451 58.08 84.133 ;
     RECT  60.12 82.453 61.536 82.885 ;
     RECT  83.712 82.453 84.912 82.501 ;
     RECT  95.688 82.453 97.008 82.501 ;
     RECT  0.408 82.501 1.632 83.029 ;
     RECT  70.68 82.549 71.808 83.125 ;
     RECT  18.912 82.691 19.92 82.787 ;
     RECT  21.048 82.691 21.816 82.741 ;
     RECT  24.312 82.691 25.632 83.267 ;
     RECT  43.68 82.691 44.352 82.933 ;
     RECT  63.528 82.691 64.656 83.845 ;
     RECT  109.032 82.691 110.16 83.845 ;
     RECT  35.88 82.739 36.84 83.797 ;
     RECT  111.672 82.739 112.704 83.027 ;
     RECT  21.048 82.741 23.184 82.883 ;
     RECT  3.864 82.787 3.912 84.277 ;
     RECT  13.512 82.787 13.608 83.797 ;
     RECT  18.912 82.787 20.16 83.797 ;
     RECT  113.544 82.787 114.72 83.797 ;
     RECT  21.048 82.883 23.904 83.797 ;
     RECT  43.32 82.933 44.352 83.267 ;
     RECT  25.656 82.979 26.928 83.267 ;
     RECT  111.672 83.027 112.752 83.797 ;
     RECT  127.224 83.029 128.688 83.749 ;
     RECT  24.312 83.267 26.928 83.797 ;
     RECT  28.392 83.267 29.4 84.277 ;
     RECT  31.272 83.267 33.24 84.277 ;
     RECT  43.32 83.267 44.784 84.325 ;
     RECT  58.92 83.267 60.096 84.325 ;
     RECT  98.616 83.701 99.6 83.893 ;
     RECT  127.464 83.749 128.448 84.949 ;
     RECT  9 83.797 9.984 84.181 ;
     RECT  13.8 83.797 14.784 83.845 ;
     RECT  22.92 83.797 23.904 83.845 ;
     RECT  25.176 83.797 26.928 84.277 ;
     RECT  41.64 83.797 42.912 84.325 ;
     RECT  111.768 83.797 112.752 84.181 ;
     RECT  56.856 84.133 58.08 84.325 ;
     RECT  53.544 84.229 55.056 84.325 ;
     RECT  25.944 84.277 26.928 84.325 ;
     RECT  31.272 84.277 33.024 84.325 ;
     RECT  33.528 84.277 34.8 84.325 ;
     RECT  36.84 84.277 38.064 84.325 ;
  END
END ot_hgi_qdq_transport_rslice
END LIBRARY
